VERSION 5.8 ;
BUSBITCHARS "[]" ;
DIVIDERCHAR "/" ;
UNITS
    DATABASE MICRONS 1000 ;
END UNITS

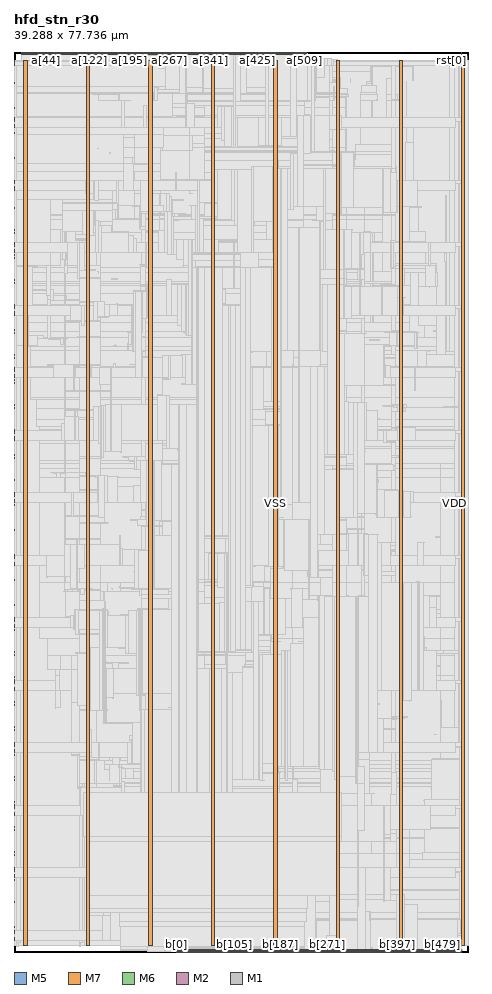
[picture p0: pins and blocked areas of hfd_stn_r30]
MACRO hfd_stn_r30
  FOREIGN hfd_stn_r30 0 0 ;
  CLASS BLOCK ;
  SIZE 39.288 BY 77.736 ;
  PIN a[0]
    DIRECTION INPUT ;
    USE SIGNAL ;
    PORT
      LAYER M5 ;
        RECT  0.624 77.544 0.648 77.736 ;
    END
  END a[0]
  PIN a[100]
    DIRECTION INPUT ;
    USE SIGNAL ;
    PORT
      LAYER M5 ;
        RECT  5.424 77.544 5.448 77.736 ;
    END
  END a[100]
  PIN a[101]
    DIRECTION INPUT ;
    USE SIGNAL ;
    PORT
      LAYER M5 ;
        RECT  5.472 77.544 5.496 77.736 ;
    END
  END a[101]
  PIN a[102]
    DIRECTION INPUT ;
    USE SIGNAL ;
    PORT
      LAYER M5 ;
        RECT  5.52 77.544 5.544 77.736 ;
    END
  END a[102]
  PIN a[103]
    DIRECTION INPUT ;
    USE SIGNAL ;
    PORT
      LAYER M5 ;
        RECT  5.568 77.544 5.592 77.736 ;
    END
  END a[103]
  PIN a[104]
    DIRECTION INPUT ;
    USE SIGNAL ;
    PORT
      LAYER M5 ;
        RECT  5.616 77.544 5.64 77.736 ;
    END
  END a[104]
  PIN a[105]
    DIRECTION INPUT ;
    USE SIGNAL ;
    PORT
      LAYER M5 ;
        RECT  5.664 77.544 5.688 77.736 ;
    END
  END a[105]
  PIN a[106]
    DIRECTION INPUT ;
    USE SIGNAL ;
    PORT
      LAYER M5 ;
        RECT  5.712 77.544 5.736 77.736 ;
    END
  END a[106]
  PIN a[107]
    DIRECTION INPUT ;
    USE SIGNAL ;
    PORT
      LAYER M5 ;
        RECT  5.76 77.544 5.784 77.736 ;
    END
  END a[107]
  PIN a[108]
    DIRECTION INPUT ;
    USE SIGNAL ;
    PORT
      LAYER M5 ;
        RECT  5.808 77.544 5.832 77.736 ;
    END
  END a[108]
  PIN a[109]
    DIRECTION INPUT ;
    USE SIGNAL ;
    PORT
      LAYER M5 ;
        RECT  5.856 77.544 5.88 77.736 ;
    END
  END a[109]
  PIN a[10]
    DIRECTION INPUT ;
    USE SIGNAL ;
    PORT
      LAYER M5 ;
        RECT  1.104 77.544 1.128 77.736 ;
    END
  END a[10]
  PIN a[110]
    DIRECTION INPUT ;
    USE SIGNAL ;
    PORT
      LAYER M5 ;
        RECT  5.904 77.544 5.928 77.736 ;
    END
  END a[110]
  PIN a[111]
    DIRECTION INPUT ;
    USE SIGNAL ;
    PORT
      LAYER M5 ;
        RECT  5.952 77.544 5.976 77.736 ;
    END
  END a[111]
  PIN a[112]
    DIRECTION INPUT ;
    USE SIGNAL ;
    PORT
      LAYER M5 ;
        RECT  6 77.544 6.024 77.736 ;
    END
  END a[112]
  PIN a[113]
    DIRECTION INPUT ;
    USE SIGNAL ;
    PORT
      LAYER M5 ;
        RECT  6.048 77.544 6.072 77.736 ;
    END
  END a[113]
  PIN a[114]
    DIRECTION INPUT ;
    USE SIGNAL ;
    PORT
      LAYER M5 ;
        RECT  6.096 77.544 6.12 77.736 ;
    END
  END a[114]
  PIN a[115]
    DIRECTION INPUT ;
    USE SIGNAL ;
    PORT
      LAYER M5 ;
        RECT  6.144 77.544 6.168 77.736 ;
    END
  END a[115]
  PIN a[116]
    DIRECTION INPUT ;
    USE SIGNAL ;
    PORT
      LAYER M5 ;
        RECT  6.192 77.544 6.216 77.736 ;
    END
  END a[116]
  PIN a[117]
    DIRECTION INPUT ;
    USE SIGNAL ;
    PORT
      LAYER M5 ;
        RECT  6.24 77.544 6.264 77.736 ;
    END
  END a[117]
  PIN a[118]
    DIRECTION INPUT ;
    USE SIGNAL ;
    PORT
      LAYER M5 ;
        RECT  6.288 77.544 6.312 77.736 ;
    END
  END a[118]
  PIN a[119]
    DIRECTION INPUT ;
    USE SIGNAL ;
    PORT
      LAYER M5 ;
        RECT  6.336 77.544 6.36 77.736 ;
    END
  END a[119]
  PIN a[11]
    DIRECTION INPUT ;
    USE SIGNAL ;
    PORT
      LAYER M5 ;
        RECT  1.152 77.544 1.176 77.736 ;
    END
  END a[11]
  PIN a[120]
    DIRECTION INPUT ;
    USE SIGNAL ;
    PORT
      LAYER M5 ;
        RECT  6.384 77.544 6.408 77.736 ;
    END
  END a[120]
  PIN a[121]
    DIRECTION INPUT ;
    USE SIGNAL ;
    PORT
      LAYER M5 ;
        RECT  6.432 77.544 6.456 77.736 ;
    END
  END a[121]
  PIN a[122]
    DIRECTION INPUT ;
    USE SIGNAL ;
    PORT
      LAYER M5 ;
        RECT  6.48 77.544 6.504 77.736 ;
    END
  END a[122]
  PIN a[123]
    DIRECTION INPUT ;
    USE SIGNAL ;
    PORT
      LAYER M5 ;
        RECT  6.528 77.544 6.552 77.736 ;
    END
  END a[123]
  PIN a[124]
    DIRECTION INPUT ;
    USE SIGNAL ;
    PORT
      LAYER M5 ;
        RECT  6.576 77.544 6.6 77.736 ;
    END
  END a[124]
  PIN a[125]
    DIRECTION INPUT ;
    USE SIGNAL ;
    PORT
      LAYER M5 ;
        RECT  6.624 77.544 6.648 77.736 ;
    END
  END a[125]
  PIN a[126]
    DIRECTION INPUT ;
    USE SIGNAL ;
    PORT
      LAYER M5 ;
        RECT  6.672 77.544 6.696 77.736 ;
    END
  END a[126]
  PIN a[127]
    DIRECTION INPUT ;
    USE SIGNAL ;
    PORT
      LAYER M5 ;
        RECT  6.72 77.544 6.744 77.736 ;
    END
  END a[127]
  PIN a[128]
    DIRECTION INPUT ;
    USE SIGNAL ;
    PORT
      LAYER M5 ;
        RECT  6.768 77.544 6.792 77.736 ;
    END
  END a[128]
  PIN a[129]
    DIRECTION INPUT ;
    USE SIGNAL ;
    PORT
      LAYER M5 ;
        RECT  6.816 77.544 6.84 77.736 ;
    END
  END a[129]
  PIN a[12]
    DIRECTION INPUT ;
    USE SIGNAL ;
    PORT
      LAYER M5 ;
        RECT  1.2 77.544 1.224 77.736 ;
    END
  END a[12]
  PIN a[130]
    DIRECTION INPUT ;
    USE SIGNAL ;
    PORT
      LAYER M5 ;
        RECT  6.864 77.544 6.888 77.736 ;
    END
  END a[130]
  PIN a[131]
    DIRECTION INPUT ;
    USE SIGNAL ;
    PORT
      LAYER M5 ;
        RECT  6.912 77.544 6.936 77.736 ;
    END
  END a[131]
  PIN a[132]
    DIRECTION INPUT ;
    USE SIGNAL ;
    PORT
      LAYER M5 ;
        RECT  6.96 77.544 6.984 77.736 ;
    END
  END a[132]
  PIN a[133]
    DIRECTION INPUT ;
    USE SIGNAL ;
    PORT
      LAYER M5 ;
        RECT  7.008 77.544 7.032 77.736 ;
    END
  END a[133]
  PIN a[134]
    DIRECTION INPUT ;
    USE SIGNAL ;
    PORT
      LAYER M5 ;
        RECT  7.056 77.544 7.08 77.736 ;
    END
  END a[134]
  PIN a[135]
    DIRECTION INPUT ;
    USE SIGNAL ;
    PORT
      LAYER M5 ;
        RECT  7.104 77.544 7.128 77.736 ;
    END
  END a[135]
  PIN a[136]
    DIRECTION INPUT ;
    USE SIGNAL ;
    PORT
      LAYER M5 ;
        RECT  7.152 77.544 7.176 77.736 ;
    END
  END a[136]
  PIN a[137]
    DIRECTION INPUT ;
    USE SIGNAL ;
    PORT
      LAYER M5 ;
        RECT  7.2 77.544 7.224 77.736 ;
    END
  END a[137]
  PIN a[138]
    DIRECTION INPUT ;
    USE SIGNAL ;
    PORT
      LAYER M5 ;
        RECT  7.248 77.544 7.272 77.736 ;
    END
  END a[138]
  PIN a[139]
    DIRECTION INPUT ;
    USE SIGNAL ;
    PORT
      LAYER M5 ;
        RECT  7.296 77.544 7.32 77.736 ;
    END
  END a[139]
  PIN a[13]
    DIRECTION INPUT ;
    USE SIGNAL ;
    PORT
      LAYER M5 ;
        RECT  1.248 77.544 1.272 77.736 ;
    END
  END a[13]
  PIN a[140]
    DIRECTION INPUT ;
    USE SIGNAL ;
    PORT
      LAYER M5 ;
        RECT  7.344 77.544 7.368 77.736 ;
    END
  END a[140]
  PIN a[141]
    DIRECTION INPUT ;
    USE SIGNAL ;
    PORT
      LAYER M5 ;
        RECT  7.392 77.544 7.416 77.736 ;
    END
  END a[141]
  PIN a[142]
    DIRECTION INPUT ;
    USE SIGNAL ;
    PORT
      LAYER M5 ;
        RECT  7.44 77.544 7.464 77.736 ;
    END
  END a[142]
  PIN a[143]
    DIRECTION INPUT ;
    USE SIGNAL ;
    PORT
      LAYER M5 ;
        RECT  7.488 77.544 7.512 77.736 ;
    END
  END a[143]
  PIN a[144]
    DIRECTION INPUT ;
    USE SIGNAL ;
    PORT
      LAYER M5 ;
        RECT  7.536 77.544 7.56 77.736 ;
    END
  END a[144]
  PIN a[145]
    DIRECTION INPUT ;
    USE SIGNAL ;
    PORT
      LAYER M5 ;
        RECT  7.584 77.544 7.608 77.736 ;
    END
  END a[145]
  PIN a[146]
    DIRECTION INPUT ;
    USE SIGNAL ;
    PORT
      LAYER M5 ;
        RECT  7.632 77.544 7.656 77.736 ;
    END
  END a[146]
  PIN a[147]
    DIRECTION INPUT ;
    USE SIGNAL ;
    PORT
      LAYER M5 ;
        RECT  7.68 77.544 7.704 77.736 ;
    END
  END a[147]
  PIN a[148]
    DIRECTION INPUT ;
    USE SIGNAL ;
    PORT
      LAYER M5 ;
        RECT  7.728 77.544 7.752 77.736 ;
    END
  END a[148]
  PIN a[149]
    DIRECTION INPUT ;
    USE SIGNAL ;
    PORT
      LAYER M5 ;
        RECT  7.776 77.544 7.8 77.736 ;
    END
  END a[149]
  PIN a[14]
    DIRECTION INPUT ;
    USE SIGNAL ;
    PORT
      LAYER M5 ;
        RECT  1.296 77.544 1.32 77.736 ;
    END
  END a[14]
  PIN a[150]
    DIRECTION INPUT ;
    USE SIGNAL ;
    PORT
      LAYER M5 ;
        RECT  7.824 77.544 7.848 77.736 ;
    END
  END a[150]
  PIN a[151]
    DIRECTION INPUT ;
    USE SIGNAL ;
    PORT
      LAYER M5 ;
        RECT  7.872 77.544 7.896 77.736 ;
    END
  END a[151]
  PIN a[152]
    DIRECTION INPUT ;
    USE SIGNAL ;
    PORT
      LAYER M5 ;
        RECT  7.92 77.544 7.944 77.736 ;
    END
  END a[152]
  PIN a[153]
    DIRECTION INPUT ;
    USE SIGNAL ;
    PORT
      LAYER M5 ;
        RECT  7.968 77.544 7.992 77.736 ;
    END
  END a[153]
  PIN a[154]
    DIRECTION INPUT ;
    USE SIGNAL ;
    PORT
      LAYER M5 ;
        RECT  8.016 77.544 8.04 77.736 ;
    END
  END a[154]
  PIN a[155]
    DIRECTION INPUT ;
    USE SIGNAL ;
    PORT
      LAYER M5 ;
        RECT  8.064 77.544 8.088 77.736 ;
    END
  END a[155]
  PIN a[156]
    DIRECTION INPUT ;
    USE SIGNAL ;
    PORT
      LAYER M5 ;
        RECT  8.112 77.544 8.136 77.736 ;
    END
  END a[156]
  PIN a[157]
    DIRECTION INPUT ;
    USE SIGNAL ;
    PORT
      LAYER M5 ;
        RECT  8.16 77.544 8.184 77.736 ;
    END
  END a[157]
  PIN a[158]
    DIRECTION INPUT ;
    USE SIGNAL ;
    PORT
      LAYER M5 ;
        RECT  8.208 77.544 8.232 77.736 ;
    END
  END a[158]
  PIN a[159]
    DIRECTION INPUT ;
    USE SIGNAL ;
    PORT
      LAYER M5 ;
        RECT  8.256 77.544 8.28 77.736 ;
    END
  END a[159]
  PIN a[15]
    DIRECTION INPUT ;
    USE SIGNAL ;
    PORT
      LAYER M5 ;
        RECT  1.344 77.544 1.368 77.736 ;
    END
  END a[15]
  PIN a[160]
    DIRECTION INPUT ;
    USE SIGNAL ;
    PORT
      LAYER M5 ;
        RECT  8.304 77.544 8.328 77.736 ;
    END
  END a[160]
  PIN a[161]
    DIRECTION INPUT ;
    USE SIGNAL ;
    PORT
      LAYER M5 ;
        RECT  8.352 77.544 8.376 77.736 ;
    END
  END a[161]
  PIN a[162]
    DIRECTION INPUT ;
    USE SIGNAL ;
    PORT
      LAYER M5 ;
        RECT  8.4 77.544 8.424 77.736 ;
    END
  END a[162]
  PIN a[163]
    DIRECTION INPUT ;
    USE SIGNAL ;
    PORT
      LAYER M5 ;
        RECT  8.448 77.544 8.472 77.736 ;
    END
  END a[163]
  PIN a[164]
    DIRECTION INPUT ;
    USE SIGNAL ;
    PORT
      LAYER M5 ;
        RECT  8.496 77.544 8.52 77.736 ;
    END
  END a[164]
  PIN a[165]
    DIRECTION INPUT ;
    USE SIGNAL ;
    PORT
      LAYER M5 ;
        RECT  8.544 77.544 8.568 77.736 ;
    END
  END a[165]
  PIN a[166]
    DIRECTION INPUT ;
    USE SIGNAL ;
    PORT
      LAYER M5 ;
        RECT  8.592 77.544 8.616 77.736 ;
    END
  END a[166]
  PIN a[167]
    DIRECTION INPUT ;
    USE SIGNAL ;
    PORT
      LAYER M5 ;
        RECT  8.64 77.544 8.664 77.736 ;
    END
  END a[167]
  PIN a[168]
    DIRECTION INPUT ;
    USE SIGNAL ;
    PORT
      LAYER M5 ;
        RECT  8.688 77.544 8.712 77.736 ;
    END
  END a[168]
  PIN a[169]
    DIRECTION INPUT ;
    USE SIGNAL ;
    PORT
      LAYER M5 ;
        RECT  8.736 77.544 8.76 77.736 ;
    END
  END a[169]
  PIN a[16]
    DIRECTION INPUT ;
    USE SIGNAL ;
    PORT
      LAYER M5 ;
        RECT  1.392 77.544 1.416 77.736 ;
    END
  END a[16]
  PIN a[170]
    DIRECTION INPUT ;
    USE SIGNAL ;
    PORT
      LAYER M5 ;
        RECT  8.784 77.544 8.808 77.736 ;
    END
  END a[170]
  PIN a[171]
    DIRECTION INPUT ;
    USE SIGNAL ;
    PORT
      LAYER M5 ;
        RECT  8.832 77.544 8.856 77.736 ;
    END
  END a[171]
  PIN a[172]
    DIRECTION INPUT ;
    USE SIGNAL ;
    PORT
      LAYER M5 ;
        RECT  8.88 77.544 8.904 77.736 ;
    END
  END a[172]
  PIN a[173]
    DIRECTION INPUT ;
    USE SIGNAL ;
    PORT
      LAYER M5 ;
        RECT  8.928 77.544 8.952 77.736 ;
    END
  END a[173]
  PIN a[174]
    DIRECTION INPUT ;
    USE SIGNAL ;
    PORT
      LAYER M5 ;
        RECT  8.976 77.544 9 77.736 ;
    END
  END a[174]
  PIN a[175]
    DIRECTION INPUT ;
    USE SIGNAL ;
    PORT
      LAYER M5 ;
        RECT  9.024 77.544 9.048 77.736 ;
    END
  END a[175]
  PIN a[176]
    DIRECTION INPUT ;
    USE SIGNAL ;
    PORT
      LAYER M5 ;
        RECT  9.072 77.544 9.096 77.736 ;
    END
  END a[176]
  PIN a[177]
    DIRECTION INPUT ;
    USE SIGNAL ;
    PORT
      LAYER M5 ;
        RECT  9.12 77.544 9.144 77.736 ;
    END
  END a[177]
  PIN a[178]
    DIRECTION INPUT ;
    USE SIGNAL ;
    PORT
      LAYER M5 ;
        RECT  9.168 77.544 9.192 77.736 ;
    END
  END a[178]
  PIN a[179]
    DIRECTION INPUT ;
    USE SIGNAL ;
    PORT
      LAYER M5 ;
        RECT  9.216 77.544 9.24 77.736 ;
    END
  END a[179]
  PIN a[17]
    DIRECTION INPUT ;
    USE SIGNAL ;
    PORT
      LAYER M5 ;
        RECT  1.44 77.544 1.464 77.736 ;
    END
  END a[17]
  PIN a[180]
    DIRECTION INPUT ;
    USE SIGNAL ;
    PORT
      LAYER M5 ;
        RECT  9.264 77.544 9.288 77.736 ;
    END
  END a[180]
  PIN a[181]
    DIRECTION INPUT ;
    USE SIGNAL ;
    PORT
      LAYER M5 ;
        RECT  9.312 77.544 9.336 77.736 ;
    END
  END a[181]
  PIN a[182]
    DIRECTION INPUT ;
    USE SIGNAL ;
    PORT
      LAYER M5 ;
        RECT  9.36 77.544 9.384 77.736 ;
    END
  END a[182]
  PIN a[183]
    DIRECTION INPUT ;
    USE SIGNAL ;
    PORT
      LAYER M5 ;
        RECT  9.408 77.544 9.432 77.736 ;
    END
  END a[183]
  PIN a[184]
    DIRECTION INPUT ;
    USE SIGNAL ;
    PORT
      LAYER M5 ;
        RECT  9.456 77.544 9.48 77.736 ;
    END
  END a[184]
  PIN a[185]
    DIRECTION INPUT ;
    USE SIGNAL ;
    PORT
      LAYER M5 ;
        RECT  9.504 77.544 9.528 77.736 ;
    END
  END a[185]
  PIN a[186]
    DIRECTION INPUT ;
    USE SIGNAL ;
    PORT
      LAYER M5 ;
        RECT  9.552 77.544 9.576 77.736 ;
    END
  END a[186]
  PIN a[187]
    DIRECTION INPUT ;
    USE SIGNAL ;
    PORT
      LAYER M5 ;
        RECT  9.6 77.544 9.624 77.736 ;
    END
  END a[187]
  PIN a[188]
    DIRECTION INPUT ;
    USE SIGNAL ;
    PORT
      LAYER M5 ;
        RECT  9.648 77.544 9.672 77.736 ;
    END
  END a[188]
  PIN a[189]
    DIRECTION INPUT ;
    USE SIGNAL ;
    PORT
      LAYER M5 ;
        RECT  9.696 77.544 9.72 77.736 ;
    END
  END a[189]
  PIN a[18]
    DIRECTION INPUT ;
    USE SIGNAL ;
    PORT
      LAYER M5 ;
        RECT  1.488 77.544 1.512 77.736 ;
    END
  END a[18]
  PIN a[190]
    DIRECTION INPUT ;
    USE SIGNAL ;
    PORT
      LAYER M5 ;
        RECT  9.744 77.544 9.768 77.736 ;
    END
  END a[190]
  PIN a[191]
    DIRECTION INPUT ;
    USE SIGNAL ;
    PORT
      LAYER M5 ;
        RECT  9.792 77.544 9.816 77.736 ;
    END
  END a[191]
  PIN a[192]
    DIRECTION INPUT ;
    USE SIGNAL ;
    PORT
      LAYER M5 ;
        RECT  9.84 77.544 9.864 77.736 ;
    END
  END a[192]
  PIN a[193]
    DIRECTION INPUT ;
    USE SIGNAL ;
    PORT
      LAYER M5 ;
        RECT  9.888 77.544 9.912 77.736 ;
    END
  END a[193]
  PIN a[194]
    DIRECTION INPUT ;
    USE SIGNAL ;
    PORT
      LAYER M5 ;
        RECT  9.936 77.544 9.96 77.736 ;
    END
  END a[194]
  PIN a[195]
    DIRECTION INPUT ;
    USE SIGNAL ;
    PORT
      LAYER M5 ;
        RECT  9.984 77.544 10.008 77.736 ;
    END
  END a[195]
  PIN a[196]
    DIRECTION INPUT ;
    USE SIGNAL ;
    PORT
      LAYER M5 ;
        RECT  10.032 77.544 10.056 77.736 ;
    END
  END a[196]
  PIN a[197]
    DIRECTION INPUT ;
    USE SIGNAL ;
    PORT
      LAYER M5 ;
        RECT  10.08 77.544 10.104 77.736 ;
    END
  END a[197]
  PIN a[198]
    DIRECTION INPUT ;
    USE SIGNAL ;
    PORT
      LAYER M5 ;
        RECT  10.128 77.544 10.152 77.736 ;
    END
  END a[198]
  PIN a[199]
    DIRECTION INPUT ;
    USE SIGNAL ;
    PORT
      LAYER M5 ;
        RECT  10.176 77.544 10.2 77.736 ;
    END
  END a[199]
  PIN a[19]
    DIRECTION INPUT ;
    USE SIGNAL ;
    PORT
      LAYER M5 ;
        RECT  1.536 77.544 1.56 77.736 ;
    END
  END a[19]
  PIN a[1]
    DIRECTION INPUT ;
    USE SIGNAL ;
    PORT
      LAYER M5 ;
        RECT  0.672 77.544 0.696 77.736 ;
    END
  END a[1]
  PIN a[200]
    DIRECTION INPUT ;
    USE SIGNAL ;
    PORT
      LAYER M5 ;
        RECT  10.224 77.544 10.248 77.736 ;
    END
  END a[200]
  PIN a[201]
    DIRECTION INPUT ;
    USE SIGNAL ;
    PORT
      LAYER M5 ;
        RECT  10.272 77.544 10.296 77.736 ;
    END
  END a[201]
  PIN a[202]
    DIRECTION INPUT ;
    USE SIGNAL ;
    PORT
      LAYER M5 ;
        RECT  10.32 77.544 10.344 77.736 ;
    END
  END a[202]
  PIN a[203]
    DIRECTION INPUT ;
    USE SIGNAL ;
    PORT
      LAYER M5 ;
        RECT  10.368 77.544 10.392 77.736 ;
    END
  END a[203]
  PIN a[204]
    DIRECTION INPUT ;
    USE SIGNAL ;
    PORT
      LAYER M5 ;
        RECT  10.416 77.544 10.44 77.736 ;
    END
  END a[204]
  PIN a[205]
    DIRECTION INPUT ;
    USE SIGNAL ;
    PORT
      LAYER M5 ;
        RECT  10.464 77.544 10.488 77.736 ;
    END
  END a[205]
  PIN a[206]
    DIRECTION INPUT ;
    USE SIGNAL ;
    PORT
      LAYER M5 ;
        RECT  10.512 77.544 10.536 77.736 ;
    END
  END a[206]
  PIN a[207]
    DIRECTION INPUT ;
    USE SIGNAL ;
    PORT
      LAYER M5 ;
        RECT  10.56 77.544 10.584 77.736 ;
    END
  END a[207]
  PIN a[208]
    DIRECTION INPUT ;
    USE SIGNAL ;
    PORT
      LAYER M5 ;
        RECT  10.608 77.544 10.632 77.736 ;
    END
  END a[208]
  PIN a[209]
    DIRECTION INPUT ;
    USE SIGNAL ;
    PORT
      LAYER M5 ;
        RECT  10.656 77.544 10.68 77.736 ;
    END
  END a[209]
  PIN a[20]
    DIRECTION INPUT ;
    USE SIGNAL ;
    PORT
      LAYER M5 ;
        RECT  1.584 77.544 1.608 77.736 ;
    END
  END a[20]
  PIN a[210]
    DIRECTION INPUT ;
    USE SIGNAL ;
    PORT
      LAYER M5 ;
        RECT  10.704 77.544 10.728 77.736 ;
    END
  END a[210]
  PIN a[211]
    DIRECTION INPUT ;
    USE SIGNAL ;
    PORT
      LAYER M5 ;
        RECT  10.752 77.544 10.776 77.736 ;
    END
  END a[211]
  PIN a[212]
    DIRECTION INPUT ;
    USE SIGNAL ;
    PORT
      LAYER M5 ;
        RECT  10.8 77.544 10.824 77.736 ;
    END
  END a[212]
  PIN a[213]
    DIRECTION INPUT ;
    USE SIGNAL ;
    PORT
      LAYER M5 ;
        RECT  10.848 77.544 10.872 77.736 ;
    END
  END a[213]
  PIN a[214]
    DIRECTION INPUT ;
    USE SIGNAL ;
    PORT
      LAYER M5 ;
        RECT  10.896 77.544 10.92 77.736 ;
    END
  END a[214]
  PIN a[215]
    DIRECTION INPUT ;
    USE SIGNAL ;
    PORT
      LAYER M5 ;
        RECT  10.944 77.544 10.968 77.736 ;
    END
  END a[215]
  PIN a[216]
    DIRECTION INPUT ;
    USE SIGNAL ;
    PORT
      LAYER M5 ;
        RECT  10.992 77.544 11.016 77.736 ;
    END
  END a[216]
  PIN a[217]
    DIRECTION INPUT ;
    USE SIGNAL ;
    PORT
      LAYER M5 ;
        RECT  11.04 77.544 11.064 77.736 ;
    END
  END a[217]
  PIN a[218]
    DIRECTION INPUT ;
    USE SIGNAL ;
    PORT
      LAYER M5 ;
        RECT  11.088 77.544 11.112 77.736 ;
    END
  END a[218]
  PIN a[219]
    DIRECTION INPUT ;
    USE SIGNAL ;
    PORT
      LAYER M5 ;
        RECT  11.136 77.544 11.16 77.736 ;
    END
  END a[219]
  PIN a[21]
    DIRECTION INPUT ;
    USE SIGNAL ;
    PORT
      LAYER M5 ;
        RECT  1.632 77.544 1.656 77.736 ;
    END
  END a[21]
  PIN a[220]
    DIRECTION INPUT ;
    USE SIGNAL ;
    PORT
      LAYER M5 ;
        RECT  11.184 77.544 11.208 77.736 ;
    END
  END a[220]
  PIN a[221]
    DIRECTION INPUT ;
    USE SIGNAL ;
    PORT
      LAYER M5 ;
        RECT  11.232 77.544 11.256 77.736 ;
    END
  END a[221]
  PIN a[222]
    DIRECTION INPUT ;
    USE SIGNAL ;
    PORT
      LAYER M5 ;
        RECT  11.28 77.544 11.304 77.736 ;
    END
  END a[222]
  PIN a[223]
    DIRECTION INPUT ;
    USE SIGNAL ;
    PORT
      LAYER M5 ;
        RECT  11.328 77.544 11.352 77.736 ;
    END
  END a[223]
  PIN a[224]
    DIRECTION INPUT ;
    USE SIGNAL ;
    PORT
      LAYER M5 ;
        RECT  11.376 77.544 11.4 77.736 ;
    END
  END a[224]
  PIN a[225]
    DIRECTION INPUT ;
    USE SIGNAL ;
    PORT
      LAYER M5 ;
        RECT  11.424 77.544 11.448 77.736 ;
    END
  END a[225]
  PIN a[226]
    DIRECTION INPUT ;
    USE SIGNAL ;
    PORT
      LAYER M5 ;
        RECT  11.472 77.544 11.496 77.736 ;
    END
  END a[226]
  PIN a[227]
    DIRECTION INPUT ;
    USE SIGNAL ;
    PORT
      LAYER M5 ;
        RECT  11.52 77.544 11.544 77.736 ;
    END
  END a[227]
  PIN a[228]
    DIRECTION INPUT ;
    USE SIGNAL ;
    PORT
      LAYER M5 ;
        RECT  11.568 77.544 11.592 77.736 ;
    END
  END a[228]
  PIN a[229]
    DIRECTION INPUT ;
    USE SIGNAL ;
    PORT
      LAYER M5 ;
        RECT  11.616 77.544 11.64 77.736 ;
    END
  END a[229]
  PIN a[22]
    DIRECTION INPUT ;
    USE SIGNAL ;
    PORT
      LAYER M5 ;
        RECT  1.68 77.544 1.704 77.736 ;
    END
  END a[22]
  PIN a[230]
    DIRECTION INPUT ;
    USE SIGNAL ;
    PORT
      LAYER M5 ;
        RECT  11.664 77.544 11.688 77.736 ;
    END
  END a[230]
  PIN a[231]
    DIRECTION INPUT ;
    USE SIGNAL ;
    PORT
      LAYER M5 ;
        RECT  11.712 77.544 11.736 77.736 ;
    END
  END a[231]
  PIN a[232]
    DIRECTION INPUT ;
    USE SIGNAL ;
    PORT
      LAYER M5 ;
        RECT  11.76 77.544 11.784 77.736 ;
    END
  END a[232]
  PIN a[233]
    DIRECTION INPUT ;
    USE SIGNAL ;
    PORT
      LAYER M5 ;
        RECT  11.808 77.544 11.832 77.736 ;
    END
  END a[233]
  PIN a[234]
    DIRECTION INPUT ;
    USE SIGNAL ;
    PORT
      LAYER M5 ;
        RECT  11.856 77.544 11.88 77.736 ;
    END
  END a[234]
  PIN a[235]
    DIRECTION INPUT ;
    USE SIGNAL ;
    PORT
      LAYER M5 ;
        RECT  11.904 77.544 11.928 77.736 ;
    END
  END a[235]
  PIN a[236]
    DIRECTION INPUT ;
    USE SIGNAL ;
    PORT
      LAYER M5 ;
        RECT  11.952 77.544 11.976 77.736 ;
    END
  END a[236]
  PIN a[237]
    DIRECTION INPUT ;
    USE SIGNAL ;
    PORT
      LAYER M5 ;
        RECT  12 77.544 12.024 77.736 ;
    END
  END a[237]
  PIN a[238]
    DIRECTION INPUT ;
    USE SIGNAL ;
    PORT
      LAYER M5 ;
        RECT  12.048 77.544 12.072 77.736 ;
    END
  END a[238]
  PIN a[239]
    DIRECTION INPUT ;
    USE SIGNAL ;
    PORT
      LAYER M5 ;
        RECT  12.096 77.544 12.12 77.736 ;
    END
  END a[239]
  PIN a[23]
    DIRECTION INPUT ;
    USE SIGNAL ;
    PORT
      LAYER M5 ;
        RECT  1.728 77.544 1.752 77.736 ;
    END
  END a[23]
  PIN a[240]
    DIRECTION INPUT ;
    USE SIGNAL ;
    PORT
      LAYER M5 ;
        RECT  12.144 77.544 12.168 77.736 ;
    END
  END a[240]
  PIN a[241]
    DIRECTION INPUT ;
    USE SIGNAL ;
    PORT
      LAYER M5 ;
        RECT  12.192 77.544 12.216 77.736 ;
    END
  END a[241]
  PIN a[242]
    DIRECTION INPUT ;
    USE SIGNAL ;
    PORT
      LAYER M5 ;
        RECT  12.24 77.544 12.264 77.736 ;
    END
  END a[242]
  PIN a[243]
    DIRECTION INPUT ;
    USE SIGNAL ;
    PORT
      LAYER M5 ;
        RECT  12.288 77.544 12.312 77.736 ;
    END
  END a[243]
  PIN a[244]
    DIRECTION INPUT ;
    USE SIGNAL ;
    PORT
      LAYER M5 ;
        RECT  12.336 77.544 12.36 77.736 ;
    END
  END a[244]
  PIN a[245]
    DIRECTION INPUT ;
    USE SIGNAL ;
    PORT
      LAYER M5 ;
        RECT  12.384 77.544 12.408 77.736 ;
    END
  END a[245]
  PIN a[246]
    DIRECTION INPUT ;
    USE SIGNAL ;
    PORT
      LAYER M5 ;
        RECT  12.432 77.544 12.456 77.736 ;
    END
  END a[246]
  PIN a[247]
    DIRECTION INPUT ;
    USE SIGNAL ;
    PORT
      LAYER M5 ;
        RECT  12.48 77.544 12.504 77.736 ;
    END
  END a[247]
  PIN a[248]
    DIRECTION INPUT ;
    USE SIGNAL ;
    PORT
      LAYER M5 ;
        RECT  12.528 77.544 12.552 77.736 ;
    END
  END a[248]
  PIN a[249]
    DIRECTION INPUT ;
    USE SIGNAL ;
    PORT
      LAYER M5 ;
        RECT  12.576 77.544 12.6 77.736 ;
    END
  END a[249]
  PIN a[24]
    DIRECTION INPUT ;
    USE SIGNAL ;
    PORT
      LAYER M5 ;
        RECT  1.776 77.544 1.8 77.736 ;
    END
  END a[24]
  PIN a[250]
    DIRECTION INPUT ;
    USE SIGNAL ;
    PORT
      LAYER M5 ;
        RECT  12.624 77.544 12.648 77.736 ;
    END
  END a[250]
  PIN a[251]
    DIRECTION INPUT ;
    USE SIGNAL ;
    PORT
      LAYER M5 ;
        RECT  12.672 77.544 12.696 77.736 ;
    END
  END a[251]
  PIN a[252]
    DIRECTION INPUT ;
    USE SIGNAL ;
    PORT
      LAYER M5 ;
        RECT  12.72 77.544 12.744 77.736 ;
    END
  END a[252]
  PIN a[253]
    DIRECTION INPUT ;
    USE SIGNAL ;
    PORT
      LAYER M5 ;
        RECT  12.768 77.544 12.792 77.736 ;
    END
  END a[253]
  PIN a[254]
    DIRECTION INPUT ;
    USE SIGNAL ;
    PORT
      LAYER M5 ;
        RECT  12.816 77.544 12.84 77.736 ;
    END
  END a[254]
  PIN a[255]
    DIRECTION INPUT ;
    USE SIGNAL ;
    PORT
      LAYER M5 ;
        RECT  12.864 77.544 12.888 77.736 ;
    END
  END a[255]
  PIN a[256]
    DIRECTION OUTPUT ;
    USE SIGNAL ;
    PORT
      LAYER M5 ;
        RECT  12.912 77.544 12.936 77.736 ;
    END
  END a[256]
  PIN a[257]
    DIRECTION OUTPUT ;
    USE SIGNAL ;
    PORT
      LAYER M5 ;
        RECT  12.96 77.544 12.984 77.736 ;
    END
  END a[257]
  PIN a[258]
    DIRECTION OUTPUT ;
    USE SIGNAL ;
    PORT
      LAYER M5 ;
        RECT  13.008 77.544 13.032 77.736 ;
    END
  END a[258]
  PIN a[259]
    DIRECTION OUTPUT ;
    USE SIGNAL ;
    PORT
      LAYER M5 ;
        RECT  13.056 77.544 13.08 77.736 ;
    END
  END a[259]
  PIN a[25]
    DIRECTION INPUT ;
    USE SIGNAL ;
    PORT
      LAYER M5 ;
        RECT  1.824 77.544 1.848 77.736 ;
    END
  END a[25]
  PIN a[260]
    DIRECTION OUTPUT ;
    USE SIGNAL ;
    PORT
      LAYER M5 ;
        RECT  13.104 77.544 13.128 77.736 ;
    END
  END a[260]
  PIN a[261]
    DIRECTION OUTPUT ;
    USE SIGNAL ;
    PORT
      LAYER M5 ;
        RECT  13.152 77.544 13.176 77.736 ;
    END
  END a[261]
  PIN a[262]
    DIRECTION OUTPUT ;
    USE SIGNAL ;
    PORT
      LAYER M5 ;
        RECT  13.2 77.544 13.224 77.736 ;
    END
  END a[262]
  PIN a[263]
    DIRECTION OUTPUT ;
    USE SIGNAL ;
    PORT
      LAYER M5 ;
        RECT  13.248 77.544 13.272 77.736 ;
    END
  END a[263]
  PIN a[264]
    DIRECTION OUTPUT ;
    USE SIGNAL ;
    PORT
      LAYER M5 ;
        RECT  13.296 77.544 13.32 77.736 ;
    END
  END a[264]
  PIN a[265]
    DIRECTION OUTPUT ;
    USE SIGNAL ;
    PORT
      LAYER M5 ;
        RECT  13.344 77.544 13.368 77.736 ;
    END
  END a[265]
  PIN a[266]
    DIRECTION OUTPUT ;
    USE SIGNAL ;
    PORT
      LAYER M5 ;
        RECT  13.392 77.544 13.416 77.736 ;
    END
  END a[266]
  PIN a[267]
    DIRECTION OUTPUT ;
    USE SIGNAL ;
    PORT
      LAYER M5 ;
        RECT  13.44 77.544 13.464 77.736 ;
    END
  END a[267]
  PIN a[268]
    DIRECTION OUTPUT ;
    USE SIGNAL ;
    PORT
      LAYER M5 ;
        RECT  13.488 77.544 13.512 77.736 ;
    END
  END a[268]
  PIN a[269]
    DIRECTION OUTPUT ;
    USE SIGNAL ;
    PORT
      LAYER M5 ;
        RECT  13.536 77.544 13.56 77.736 ;
    END
  END a[269]
  PIN a[26]
    DIRECTION INPUT ;
    USE SIGNAL ;
    PORT
      LAYER M5 ;
        RECT  1.872 77.544 1.896 77.736 ;
    END
  END a[26]
  PIN a[270]
    DIRECTION OUTPUT ;
    USE SIGNAL ;
    PORT
      LAYER M5 ;
        RECT  13.584 77.544 13.608 77.736 ;
    END
  END a[270]
  PIN a[271]
    DIRECTION OUTPUT ;
    USE SIGNAL ;
    PORT
      LAYER M5 ;
        RECT  13.632 77.544 13.656 77.736 ;
    END
  END a[271]
  PIN a[272]
    DIRECTION OUTPUT ;
    USE SIGNAL ;
    PORT
      LAYER M5 ;
        RECT  13.68 77.544 13.704 77.736 ;
    END
  END a[272]
  PIN a[273]
    DIRECTION OUTPUT ;
    USE SIGNAL ;
    PORT
      LAYER M5 ;
        RECT  13.728 77.544 13.752 77.736 ;
    END
  END a[273]
  PIN a[274]
    DIRECTION OUTPUT ;
    USE SIGNAL ;
    PORT
      LAYER M5 ;
        RECT  13.776 77.544 13.8 77.736 ;
    END
  END a[274]
  PIN a[275]
    DIRECTION OUTPUT ;
    USE SIGNAL ;
    PORT
      LAYER M5 ;
        RECT  13.824 77.544 13.848 77.736 ;
    END
  END a[275]
  PIN a[276]
    DIRECTION OUTPUT ;
    USE SIGNAL ;
    PORT
      LAYER M5 ;
        RECT  13.872 77.544 13.896 77.736 ;
    END
  END a[276]
  PIN a[277]
    DIRECTION OUTPUT ;
    USE SIGNAL ;
    PORT
      LAYER M5 ;
        RECT  13.92 77.544 13.944 77.736 ;
    END
  END a[277]
  PIN a[278]
    DIRECTION OUTPUT ;
    USE SIGNAL ;
    PORT
      LAYER M5 ;
        RECT  13.968 77.544 13.992 77.736 ;
    END
  END a[278]
  PIN a[279]
    DIRECTION OUTPUT ;
    USE SIGNAL ;
    PORT
      LAYER M5 ;
        RECT  14.016 77.544 14.04 77.736 ;
    END
  END a[279]
  PIN a[27]
    DIRECTION INPUT ;
    USE SIGNAL ;
    PORT
      LAYER M5 ;
        RECT  1.92 77.544 1.944 77.736 ;
    END
  END a[27]
  PIN a[280]
    DIRECTION OUTPUT ;
    USE SIGNAL ;
    PORT
      LAYER M5 ;
        RECT  14.064 77.544 14.088 77.736 ;
    END
  END a[280]
  PIN a[281]
    DIRECTION OUTPUT ;
    USE SIGNAL ;
    PORT
      LAYER M5 ;
        RECT  14.112 77.544 14.136 77.736 ;
    END
  END a[281]
  PIN a[282]
    DIRECTION OUTPUT ;
    USE SIGNAL ;
    PORT
      LAYER M5 ;
        RECT  14.16 77.544 14.184 77.736 ;
    END
  END a[282]
  PIN a[283]
    DIRECTION OUTPUT ;
    USE SIGNAL ;
    PORT
      LAYER M5 ;
        RECT  14.208 77.544 14.232 77.736 ;
    END
  END a[283]
  PIN a[284]
    DIRECTION OUTPUT ;
    USE SIGNAL ;
    PORT
      LAYER M5 ;
        RECT  14.256 77.544 14.28 77.736 ;
    END
  END a[284]
  PIN a[285]
    DIRECTION OUTPUT ;
    USE SIGNAL ;
    PORT
      LAYER M5 ;
        RECT  14.304 77.544 14.328 77.736 ;
    END
  END a[285]
  PIN a[286]
    DIRECTION OUTPUT ;
    USE SIGNAL ;
    PORT
      LAYER M5 ;
        RECT  14.352 77.544 14.376 77.736 ;
    END
  END a[286]
  PIN a[287]
    DIRECTION OUTPUT ;
    USE SIGNAL ;
    PORT
      LAYER M5 ;
        RECT  14.4 77.544 14.424 77.736 ;
    END
  END a[287]
  PIN a[288]
    DIRECTION OUTPUT ;
    USE SIGNAL ;
    PORT
      LAYER M5 ;
        RECT  14.448 77.544 14.472 77.736 ;
    END
  END a[288]
  PIN a[289]
    DIRECTION OUTPUT ;
    USE SIGNAL ;
    PORT
      LAYER M5 ;
        RECT  14.496 77.544 14.52 77.736 ;
    END
  END a[289]
  PIN a[28]
    DIRECTION INPUT ;
    USE SIGNAL ;
    PORT
      LAYER M5 ;
        RECT  1.968 77.544 1.992 77.736 ;
    END
  END a[28]
  PIN a[290]
    DIRECTION OUTPUT ;
    USE SIGNAL ;
    PORT
      LAYER M5 ;
        RECT  14.544 77.544 14.568 77.736 ;
    END
  END a[290]
  PIN a[291]
    DIRECTION OUTPUT ;
    USE SIGNAL ;
    PORT
      LAYER M5 ;
        RECT  14.592 77.544 14.616 77.736 ;
    END
  END a[291]
  PIN a[292]
    DIRECTION OUTPUT ;
    USE SIGNAL ;
    PORT
      LAYER M5 ;
        RECT  14.64 77.544 14.664 77.736 ;
    END
  END a[292]
  PIN a[293]
    DIRECTION OUTPUT ;
    USE SIGNAL ;
    PORT
      LAYER M5 ;
        RECT  14.688 77.544 14.712 77.736 ;
    END
  END a[293]
  PIN a[294]
    DIRECTION OUTPUT ;
    USE SIGNAL ;
    PORT
      LAYER M5 ;
        RECT  14.736 77.544 14.76 77.736 ;
    END
  END a[294]
  PIN a[295]
    DIRECTION OUTPUT ;
    USE SIGNAL ;
    PORT
      LAYER M5 ;
        RECT  14.784 77.544 14.808 77.736 ;
    END
  END a[295]
  PIN a[296]
    DIRECTION OUTPUT ;
    USE SIGNAL ;
    PORT
      LAYER M5 ;
        RECT  14.832 77.544 14.856 77.736 ;
    END
  END a[296]
  PIN a[297]
    DIRECTION OUTPUT ;
    USE SIGNAL ;
    PORT
      LAYER M5 ;
        RECT  14.88 77.544 14.904 77.736 ;
    END
  END a[297]
  PIN a[298]
    DIRECTION OUTPUT ;
    USE SIGNAL ;
    PORT
      LAYER M5 ;
        RECT  14.928 77.544 14.952 77.736 ;
    END
  END a[298]
  PIN a[299]
    DIRECTION OUTPUT ;
    USE SIGNAL ;
    PORT
      LAYER M5 ;
        RECT  14.976 77.544 15 77.736 ;
    END
  END a[299]
  PIN a[29]
    DIRECTION INPUT ;
    USE SIGNAL ;
    PORT
      LAYER M5 ;
        RECT  2.016 77.544 2.04 77.736 ;
    END
  END a[29]
  PIN a[2]
    DIRECTION INPUT ;
    USE SIGNAL ;
    PORT
      LAYER M5 ;
        RECT  0.72 77.544 0.744 77.736 ;
    END
  END a[2]
  PIN a[300]
    DIRECTION OUTPUT ;
    USE SIGNAL ;
    PORT
      LAYER M5 ;
        RECT  15.024 77.544 15.048 77.736 ;
    END
  END a[300]
  PIN a[301]
    DIRECTION OUTPUT ;
    USE SIGNAL ;
    PORT
      LAYER M5 ;
        RECT  15.072 77.544 15.096 77.736 ;
    END
  END a[301]
  PIN a[302]
    DIRECTION OUTPUT ;
    USE SIGNAL ;
    PORT
      LAYER M5 ;
        RECT  15.12 77.544 15.144 77.736 ;
    END
  END a[302]
  PIN a[303]
    DIRECTION OUTPUT ;
    USE SIGNAL ;
    PORT
      LAYER M5 ;
        RECT  15.168 77.544 15.192 77.736 ;
    END
  END a[303]
  PIN a[304]
    DIRECTION OUTPUT ;
    USE SIGNAL ;
    PORT
      LAYER M5 ;
        RECT  15.216 77.544 15.24 77.736 ;
    END
  END a[304]
  PIN a[305]
    DIRECTION OUTPUT ;
    USE SIGNAL ;
    PORT
      LAYER M5 ;
        RECT  15.264 77.544 15.288 77.736 ;
    END
  END a[305]
  PIN a[306]
    DIRECTION OUTPUT ;
    USE SIGNAL ;
    PORT
      LAYER M5 ;
        RECT  15.312 77.544 15.336 77.736 ;
    END
  END a[306]
  PIN a[307]
    DIRECTION OUTPUT ;
    USE SIGNAL ;
    PORT
      LAYER M5 ;
        RECT  15.36 77.544 15.384 77.736 ;
    END
  END a[307]
  PIN a[308]
    DIRECTION OUTPUT ;
    USE SIGNAL ;
    PORT
      LAYER M5 ;
        RECT  15.408 77.544 15.432 77.736 ;
    END
  END a[308]
  PIN a[309]
    DIRECTION OUTPUT ;
    USE SIGNAL ;
    PORT
      LAYER M5 ;
        RECT  15.456 77.544 15.48 77.736 ;
    END
  END a[309]
  PIN a[30]
    DIRECTION INPUT ;
    USE SIGNAL ;
    PORT
      LAYER M5 ;
        RECT  2.064 77.544 2.088 77.736 ;
    END
  END a[30]
  PIN a[310]
    DIRECTION OUTPUT ;
    USE SIGNAL ;
    PORT
      LAYER M5 ;
        RECT  15.504 77.544 15.528 77.736 ;
    END
  END a[310]
  PIN a[311]
    DIRECTION OUTPUT ;
    USE SIGNAL ;
    PORT
      LAYER M5 ;
        RECT  15.552 77.544 15.576 77.736 ;
    END
  END a[311]
  PIN a[312]
    DIRECTION OUTPUT ;
    USE SIGNAL ;
    PORT
      LAYER M5 ;
        RECT  15.6 77.544 15.624 77.736 ;
    END
  END a[312]
  PIN a[313]
    DIRECTION OUTPUT ;
    USE SIGNAL ;
    PORT
      LAYER M5 ;
        RECT  15.648 77.544 15.672 77.736 ;
    END
  END a[313]
  PIN a[314]
    DIRECTION OUTPUT ;
    USE SIGNAL ;
    PORT
      LAYER M5 ;
        RECT  15.696 77.544 15.72 77.736 ;
    END
  END a[314]
  PIN a[315]
    DIRECTION OUTPUT ;
    USE SIGNAL ;
    PORT
      LAYER M5 ;
        RECT  15.744 77.544 15.768 77.736 ;
    END
  END a[315]
  PIN a[316]
    DIRECTION OUTPUT ;
    USE SIGNAL ;
    PORT
      LAYER M5 ;
        RECT  15.792 77.544 15.816 77.736 ;
    END
  END a[316]
  PIN a[317]
    DIRECTION OUTPUT ;
    USE SIGNAL ;
    PORT
      LAYER M5 ;
        RECT  15.84 77.544 15.864 77.736 ;
    END
  END a[317]
  PIN a[318]
    DIRECTION OUTPUT ;
    USE SIGNAL ;
    PORT
      LAYER M5 ;
        RECT  15.888 77.544 15.912 77.736 ;
    END
  END a[318]
  PIN a[319]
    DIRECTION OUTPUT ;
    USE SIGNAL ;
    PORT
      LAYER M5 ;
        RECT  15.936 77.544 15.96 77.736 ;
    END
  END a[319]
  PIN a[31]
    DIRECTION INPUT ;
    USE SIGNAL ;
    PORT
      LAYER M5 ;
        RECT  2.112 77.544 2.136 77.736 ;
    END
  END a[31]
  PIN a[320]
    DIRECTION OUTPUT ;
    USE SIGNAL ;
    PORT
      LAYER M5 ;
        RECT  15.984 77.544 16.008 77.736 ;
    END
  END a[320]
  PIN a[321]
    DIRECTION OUTPUT ;
    USE SIGNAL ;
    PORT
      LAYER M5 ;
        RECT  16.032 77.544 16.056 77.736 ;
    END
  END a[321]
  PIN a[322]
    DIRECTION OUTPUT ;
    USE SIGNAL ;
    PORT
      LAYER M5 ;
        RECT  16.08 77.544 16.104 77.736 ;
    END
  END a[322]
  PIN a[323]
    DIRECTION OUTPUT ;
    USE SIGNAL ;
    PORT
      LAYER M5 ;
        RECT  16.128 77.544 16.152 77.736 ;
    END
  END a[323]
  PIN a[324]
    DIRECTION OUTPUT ;
    USE SIGNAL ;
    PORT
      LAYER M5 ;
        RECT  16.176 77.544 16.2 77.736 ;
    END
  END a[324]
  PIN a[325]
    DIRECTION OUTPUT ;
    USE SIGNAL ;
    PORT
      LAYER M5 ;
        RECT  16.224 77.544 16.248 77.736 ;
    END
  END a[325]
  PIN a[326]
    DIRECTION OUTPUT ;
    USE SIGNAL ;
    PORT
      LAYER M5 ;
        RECT  16.272 77.544 16.296 77.736 ;
    END
  END a[326]
  PIN a[327]
    DIRECTION OUTPUT ;
    USE SIGNAL ;
    PORT
      LAYER M5 ;
        RECT  16.32 77.544 16.344 77.736 ;
    END
  END a[327]
  PIN a[328]
    DIRECTION OUTPUT ;
    USE SIGNAL ;
    PORT
      LAYER M5 ;
        RECT  16.368 77.544 16.392 77.736 ;
    END
  END a[328]
  PIN a[329]
    DIRECTION OUTPUT ;
    USE SIGNAL ;
    PORT
      LAYER M5 ;
        RECT  16.416 77.544 16.44 77.736 ;
    END
  END a[329]
  PIN a[32]
    DIRECTION INPUT ;
    USE SIGNAL ;
    PORT
      LAYER M5 ;
        RECT  2.16 77.544 2.184 77.736 ;
    END
  END a[32]
  PIN a[330]
    DIRECTION OUTPUT ;
    USE SIGNAL ;
    PORT
      LAYER M5 ;
        RECT  16.464 77.544 16.488 77.736 ;
    END
  END a[330]
  PIN a[331]
    DIRECTION OUTPUT ;
    USE SIGNAL ;
    PORT
      LAYER M5 ;
        RECT  16.512 77.544 16.536 77.736 ;
    END
  END a[331]
  PIN a[332]
    DIRECTION OUTPUT ;
    USE SIGNAL ;
    PORT
      LAYER M5 ;
        RECT  16.56 77.544 16.584 77.736 ;
    END
  END a[332]
  PIN a[333]
    DIRECTION OUTPUT ;
    USE SIGNAL ;
    PORT
      LAYER M5 ;
        RECT  16.608 77.544 16.632 77.736 ;
    END
  END a[333]
  PIN a[334]
    DIRECTION OUTPUT ;
    USE SIGNAL ;
    PORT
      LAYER M5 ;
        RECT  16.656 77.544 16.68 77.736 ;
    END
  END a[334]
  PIN a[335]
    DIRECTION OUTPUT ;
    USE SIGNAL ;
    PORT
      LAYER M5 ;
        RECT  16.704 77.544 16.728 77.736 ;
    END
  END a[335]
  PIN a[336]
    DIRECTION OUTPUT ;
    USE SIGNAL ;
    PORT
      LAYER M5 ;
        RECT  16.752 77.544 16.776 77.736 ;
    END
  END a[336]
  PIN a[337]
    DIRECTION OUTPUT ;
    USE SIGNAL ;
    PORT
      LAYER M5 ;
        RECT  16.8 77.544 16.824 77.736 ;
    END
  END a[337]
  PIN a[338]
    DIRECTION OUTPUT ;
    USE SIGNAL ;
    PORT
      LAYER M5 ;
        RECT  16.848 77.544 16.872 77.736 ;
    END
  END a[338]
  PIN a[339]
    DIRECTION OUTPUT ;
    USE SIGNAL ;
    PORT
      LAYER M5 ;
        RECT  16.896 77.544 16.92 77.736 ;
    END
  END a[339]
  PIN a[33]
    DIRECTION INPUT ;
    USE SIGNAL ;
    PORT
      LAYER M5 ;
        RECT  2.208 77.544 2.232 77.736 ;
    END
  END a[33]
  PIN a[340]
    DIRECTION OUTPUT ;
    USE SIGNAL ;
    PORT
      LAYER M5 ;
        RECT  16.944 77.544 16.968 77.736 ;
    END
  END a[340]
  PIN a[341]
    DIRECTION OUTPUT ;
    USE SIGNAL ;
    PORT
      LAYER M5 ;
        RECT  16.992 77.544 17.016 77.736 ;
    END
  END a[341]
  PIN a[342]
    DIRECTION OUTPUT ;
    USE SIGNAL ;
    PORT
      LAYER M5 ;
        RECT  17.04 77.544 17.064 77.736 ;
    END
  END a[342]
  PIN a[343]
    DIRECTION OUTPUT ;
    USE SIGNAL ;
    PORT
      LAYER M5 ;
        RECT  17.088 77.544 17.112 77.736 ;
    END
  END a[343]
  PIN a[344]
    DIRECTION OUTPUT ;
    USE SIGNAL ;
    PORT
      LAYER M5 ;
        RECT  17.136 77.544 17.16 77.736 ;
    END
  END a[344]
  PIN a[345]
    DIRECTION OUTPUT ;
    USE SIGNAL ;
    PORT
      LAYER M5 ;
        RECT  17.184 77.544 17.208 77.736 ;
    END
  END a[345]
  PIN a[346]
    DIRECTION OUTPUT ;
    USE SIGNAL ;
    PORT
      LAYER M5 ;
        RECT  17.232 77.544 17.256 77.736 ;
    END
  END a[346]
  PIN a[347]
    DIRECTION OUTPUT ;
    USE SIGNAL ;
    PORT
      LAYER M5 ;
        RECT  17.28 77.544 17.304 77.736 ;
    END
  END a[347]
  PIN a[348]
    DIRECTION OUTPUT ;
    USE SIGNAL ;
    PORT
      LAYER M5 ;
        RECT  17.328 77.544 17.352 77.736 ;
    END
  END a[348]
  PIN a[349]
    DIRECTION OUTPUT ;
    USE SIGNAL ;
    PORT
      LAYER M5 ;
        RECT  17.376 77.544 17.4 77.736 ;
    END
  END a[349]
  PIN a[34]
    DIRECTION INPUT ;
    USE SIGNAL ;
    PORT
      LAYER M5 ;
        RECT  2.256 77.544 2.28 77.736 ;
    END
  END a[34]
  PIN a[350]
    DIRECTION OUTPUT ;
    USE SIGNAL ;
    PORT
      LAYER M5 ;
        RECT  17.424 77.544 17.448 77.736 ;
    END
  END a[350]
  PIN a[351]
    DIRECTION OUTPUT ;
    USE SIGNAL ;
    PORT
      LAYER M5 ;
        RECT  17.472 77.544 17.496 77.736 ;
    END
  END a[351]
  PIN a[352]
    DIRECTION OUTPUT ;
    USE SIGNAL ;
    PORT
      LAYER M5 ;
        RECT  17.52 77.544 17.544 77.736 ;
    END
  END a[352]
  PIN a[353]
    DIRECTION OUTPUT ;
    USE SIGNAL ;
    PORT
      LAYER M5 ;
        RECT  17.568 77.544 17.592 77.736 ;
    END
  END a[353]
  PIN a[354]
    DIRECTION OUTPUT ;
    USE SIGNAL ;
    PORT
      LAYER M5 ;
        RECT  17.616 77.544 17.64 77.736 ;
    END
  END a[354]
  PIN a[355]
    DIRECTION OUTPUT ;
    USE SIGNAL ;
    PORT
      LAYER M5 ;
        RECT  17.664 77.544 17.688 77.736 ;
    END
  END a[355]
  PIN a[356]
    DIRECTION OUTPUT ;
    USE SIGNAL ;
    PORT
      LAYER M5 ;
        RECT  17.712 77.544 17.736 77.736 ;
    END
  END a[356]
  PIN a[357]
    DIRECTION OUTPUT ;
    USE SIGNAL ;
    PORT
      LAYER M5 ;
        RECT  17.76 77.544 17.784 77.736 ;
    END
  END a[357]
  PIN a[358]
    DIRECTION OUTPUT ;
    USE SIGNAL ;
    PORT
      LAYER M5 ;
        RECT  17.808 77.544 17.832 77.736 ;
    END
  END a[358]
  PIN a[359]
    DIRECTION OUTPUT ;
    USE SIGNAL ;
    PORT
      LAYER M5 ;
        RECT  17.856 77.544 17.88 77.736 ;
    END
  END a[359]
  PIN a[35]
    DIRECTION INPUT ;
    USE SIGNAL ;
    PORT
      LAYER M5 ;
        RECT  2.304 77.544 2.328 77.736 ;
    END
  END a[35]
  PIN a[360]
    DIRECTION OUTPUT ;
    USE SIGNAL ;
    PORT
      LAYER M5 ;
        RECT  17.904 77.544 17.928 77.736 ;
    END
  END a[360]
  PIN a[361]
    DIRECTION OUTPUT ;
    USE SIGNAL ;
    PORT
      LAYER M5 ;
        RECT  17.952 77.544 17.976 77.736 ;
    END
  END a[361]
  PIN a[362]
    DIRECTION OUTPUT ;
    USE SIGNAL ;
    PORT
      LAYER M5 ;
        RECT  18 77.544 18.024 77.736 ;
    END
  END a[362]
  PIN a[363]
    DIRECTION OUTPUT ;
    USE SIGNAL ;
    PORT
      LAYER M5 ;
        RECT  18.048 77.544 18.072 77.736 ;
    END
  END a[363]
  PIN a[364]
    DIRECTION OUTPUT ;
    USE SIGNAL ;
    PORT
      LAYER M5 ;
        RECT  18.096 77.544 18.12 77.736 ;
    END
  END a[364]
  PIN a[365]
    DIRECTION OUTPUT ;
    USE SIGNAL ;
    PORT
      LAYER M5 ;
        RECT  18.144 77.544 18.168 77.736 ;
    END
  END a[365]
  PIN a[366]
    DIRECTION OUTPUT ;
    USE SIGNAL ;
    PORT
      LAYER M5 ;
        RECT  18.192 77.544 18.216 77.736 ;
    END
  END a[366]
  PIN a[367]
    DIRECTION OUTPUT ;
    USE SIGNAL ;
    PORT
      LAYER M5 ;
        RECT  18.24 77.544 18.264 77.736 ;
    END
  END a[367]
  PIN a[368]
    DIRECTION OUTPUT ;
    USE SIGNAL ;
    PORT
      LAYER M5 ;
        RECT  18.288 77.544 18.312 77.736 ;
    END
  END a[368]
  PIN a[369]
    DIRECTION OUTPUT ;
    USE SIGNAL ;
    PORT
      LAYER M5 ;
        RECT  18.336 77.544 18.36 77.736 ;
    END
  END a[369]
  PIN a[36]
    DIRECTION INPUT ;
    USE SIGNAL ;
    PORT
      LAYER M5 ;
        RECT  2.352 77.544 2.376 77.736 ;
    END
  END a[36]
  PIN a[370]
    DIRECTION OUTPUT ;
    USE SIGNAL ;
    PORT
      LAYER M5 ;
        RECT  18.384 77.544 18.408 77.736 ;
    END
  END a[370]
  PIN a[371]
    DIRECTION OUTPUT ;
    USE SIGNAL ;
    PORT
      LAYER M5 ;
        RECT  18.432 77.544 18.456 77.736 ;
    END
  END a[371]
  PIN a[372]
    DIRECTION OUTPUT ;
    USE SIGNAL ;
    PORT
      LAYER M5 ;
        RECT  18.48 77.544 18.504 77.736 ;
    END
  END a[372]
  PIN a[373]
    DIRECTION OUTPUT ;
    USE SIGNAL ;
    PORT
      LAYER M5 ;
        RECT  18.528 77.544 18.552 77.736 ;
    END
  END a[373]
  PIN a[374]
    DIRECTION OUTPUT ;
    USE SIGNAL ;
    PORT
      LAYER M5 ;
        RECT  18.576 77.544 18.6 77.736 ;
    END
  END a[374]
  PIN a[375]
    DIRECTION OUTPUT ;
    USE SIGNAL ;
    PORT
      LAYER M5 ;
        RECT  18.624 77.544 18.648 77.736 ;
    END
  END a[375]
  PIN a[376]
    DIRECTION OUTPUT ;
    USE SIGNAL ;
    PORT
      LAYER M5 ;
        RECT  18.672 77.544 18.696 77.736 ;
    END
  END a[376]
  PIN a[377]
    DIRECTION OUTPUT ;
    USE SIGNAL ;
    PORT
      LAYER M5 ;
        RECT  18.72 77.544 18.744 77.736 ;
    END
  END a[377]
  PIN a[378]
    DIRECTION OUTPUT ;
    USE SIGNAL ;
    PORT
      LAYER M5 ;
        RECT  18.768 77.544 18.792 77.736 ;
    END
  END a[378]
  PIN a[379]
    DIRECTION OUTPUT ;
    USE SIGNAL ;
    PORT
      LAYER M5 ;
        RECT  18.816 77.544 18.84 77.736 ;
    END
  END a[379]
  PIN a[37]
    DIRECTION INPUT ;
    USE SIGNAL ;
    PORT
      LAYER M5 ;
        RECT  2.4 77.544 2.424 77.736 ;
    END
  END a[37]
  PIN a[380]
    DIRECTION OUTPUT ;
    USE SIGNAL ;
    PORT
      LAYER M5 ;
        RECT  18.864 77.544 18.888 77.736 ;
    END
  END a[380]
  PIN a[381]
    DIRECTION OUTPUT ;
    USE SIGNAL ;
    PORT
      LAYER M5 ;
        RECT  18.912 77.544 18.936 77.736 ;
    END
  END a[381]
  PIN a[382]
    DIRECTION OUTPUT ;
    USE SIGNAL ;
    PORT
      LAYER M5 ;
        RECT  18.96 77.544 18.984 77.736 ;
    END
  END a[382]
  PIN a[383]
    DIRECTION OUTPUT ;
    USE SIGNAL ;
    PORT
      LAYER M5 ;
        RECT  19.008 77.544 19.032 77.736 ;
    END
  END a[383]
  PIN a[384]
    DIRECTION OUTPUT ;
    USE SIGNAL ;
    PORT
      LAYER M5 ;
        RECT  19.056 77.544 19.08 77.736 ;
    END
  END a[384]
  PIN a[385]
    DIRECTION OUTPUT ;
    USE SIGNAL ;
    PORT
      LAYER M5 ;
        RECT  19.104 77.544 19.128 77.736 ;
    END
  END a[385]
  PIN a[386]
    DIRECTION OUTPUT ;
    USE SIGNAL ;
    PORT
      LAYER M5 ;
        RECT  19.152 77.544 19.176 77.736 ;
    END
  END a[386]
  PIN a[387]
    DIRECTION OUTPUT ;
    USE SIGNAL ;
    PORT
      LAYER M5 ;
        RECT  19.2 77.544 19.224 77.736 ;
    END
  END a[387]
  PIN a[388]
    DIRECTION OUTPUT ;
    USE SIGNAL ;
    PORT
      LAYER M5 ;
        RECT  19.248 77.544 19.272 77.736 ;
    END
  END a[388]
  PIN a[389]
    DIRECTION OUTPUT ;
    USE SIGNAL ;
    PORT
      LAYER M5 ;
        RECT  19.296 77.544 19.32 77.736 ;
    END
  END a[389]
  PIN a[38]
    DIRECTION INPUT ;
    USE SIGNAL ;
    PORT
      LAYER M5 ;
        RECT  2.448 77.544 2.472 77.736 ;
    END
  END a[38]
  PIN a[390]
    DIRECTION OUTPUT ;
    USE SIGNAL ;
    PORT
      LAYER M5 ;
        RECT  19.344 77.544 19.368 77.736 ;
    END
  END a[390]
  PIN a[391]
    DIRECTION OUTPUT ;
    USE SIGNAL ;
    PORT
      LAYER M5 ;
        RECT  19.392 77.544 19.416 77.736 ;
    END
  END a[391]
  PIN a[392]
    DIRECTION OUTPUT ;
    USE SIGNAL ;
    PORT
      LAYER M5 ;
        RECT  19.44 77.544 19.464 77.736 ;
    END
  END a[392]
  PIN a[393]
    DIRECTION OUTPUT ;
    USE SIGNAL ;
    PORT
      LAYER M5 ;
        RECT  19.488 77.544 19.512 77.736 ;
    END
  END a[393]
  PIN a[394]
    DIRECTION OUTPUT ;
    USE SIGNAL ;
    PORT
      LAYER M5 ;
        RECT  19.536 77.544 19.56 77.736 ;
    END
  END a[394]
  PIN a[395]
    DIRECTION OUTPUT ;
    USE SIGNAL ;
    PORT
      LAYER M5 ;
        RECT  19.584 77.544 19.608 77.736 ;
    END
  END a[395]
  PIN a[396]
    DIRECTION OUTPUT ;
    USE SIGNAL ;
    PORT
      LAYER M5 ;
        RECT  19.632 77.544 19.656 77.736 ;
    END
  END a[396]
  PIN a[397]
    DIRECTION OUTPUT ;
    USE SIGNAL ;
    PORT
      LAYER M5 ;
        RECT  19.68 77.544 19.704 77.736 ;
    END
  END a[397]
  PIN a[398]
    DIRECTION OUTPUT ;
    USE SIGNAL ;
    PORT
      LAYER M5 ;
        RECT  19.728 77.544 19.752 77.736 ;
    END
  END a[398]
  PIN a[399]
    DIRECTION OUTPUT ;
    USE SIGNAL ;
    PORT
      LAYER M5 ;
        RECT  19.776 77.544 19.8 77.736 ;
    END
  END a[399]
  PIN a[39]
    DIRECTION INPUT ;
    USE SIGNAL ;
    PORT
      LAYER M5 ;
        RECT  2.496 77.544 2.52 77.736 ;
    END
  END a[39]
  PIN a[3]
    DIRECTION INPUT ;
    USE SIGNAL ;
    PORT
      LAYER M5 ;
        RECT  0.768 77.544 0.792 77.736 ;
    END
  END a[3]
  PIN a[400]
    DIRECTION OUTPUT ;
    USE SIGNAL ;
    PORT
      LAYER M5 ;
        RECT  19.824 77.544 19.848 77.736 ;
    END
  END a[400]
  PIN a[401]
    DIRECTION OUTPUT ;
    USE SIGNAL ;
    PORT
      LAYER M5 ;
        RECT  19.872 77.544 19.896 77.736 ;
    END
  END a[401]
  PIN a[402]
    DIRECTION OUTPUT ;
    USE SIGNAL ;
    PORT
      LAYER M5 ;
        RECT  19.92 77.544 19.944 77.736 ;
    END
  END a[402]
  PIN a[403]
    DIRECTION OUTPUT ;
    USE SIGNAL ;
    PORT
      LAYER M5 ;
        RECT  19.968 77.544 19.992 77.736 ;
    END
  END a[403]
  PIN a[404]
    DIRECTION OUTPUT ;
    USE SIGNAL ;
    PORT
      LAYER M5 ;
        RECT  20.016 77.544 20.04 77.736 ;
    END
  END a[404]
  PIN a[405]
    DIRECTION OUTPUT ;
    USE SIGNAL ;
    PORT
      LAYER M5 ;
        RECT  20.064 77.544 20.088 77.736 ;
    END
  END a[405]
  PIN a[406]
    DIRECTION OUTPUT ;
    USE SIGNAL ;
    PORT
      LAYER M5 ;
        RECT  20.112 77.544 20.136 77.736 ;
    END
  END a[406]
  PIN a[407]
    DIRECTION OUTPUT ;
    USE SIGNAL ;
    PORT
      LAYER M5 ;
        RECT  20.16 77.544 20.184 77.736 ;
    END
  END a[407]
  PIN a[408]
    DIRECTION OUTPUT ;
    USE SIGNAL ;
    PORT
      LAYER M5 ;
        RECT  20.208 77.544 20.232 77.736 ;
    END
  END a[408]
  PIN a[409]
    DIRECTION OUTPUT ;
    USE SIGNAL ;
    PORT
      LAYER M5 ;
        RECT  20.256 77.544 20.28 77.736 ;
    END
  END a[409]
  PIN a[40]
    DIRECTION INPUT ;
    USE SIGNAL ;
    PORT
      LAYER M5 ;
        RECT  2.544 77.544 2.568 77.736 ;
    END
  END a[40]
  PIN a[410]
    DIRECTION OUTPUT ;
    USE SIGNAL ;
    PORT
      LAYER M5 ;
        RECT  20.304 77.544 20.328 77.736 ;
    END
  END a[410]
  PIN a[411]
    DIRECTION OUTPUT ;
    USE SIGNAL ;
    PORT
      LAYER M5 ;
        RECT  20.352 77.544 20.376 77.736 ;
    END
  END a[411]
  PIN a[412]
    DIRECTION OUTPUT ;
    USE SIGNAL ;
    PORT
      LAYER M5 ;
        RECT  20.4 77.544 20.424 77.736 ;
    END
  END a[412]
  PIN a[413]
    DIRECTION OUTPUT ;
    USE SIGNAL ;
    PORT
      LAYER M5 ;
        RECT  20.448 77.544 20.472 77.736 ;
    END
  END a[413]
  PIN a[414]
    DIRECTION OUTPUT ;
    USE SIGNAL ;
    PORT
      LAYER M5 ;
        RECT  20.496 77.544 20.52 77.736 ;
    END
  END a[414]
  PIN a[415]
    DIRECTION OUTPUT ;
    USE SIGNAL ;
    PORT
      LAYER M5 ;
        RECT  20.544 77.544 20.568 77.736 ;
    END
  END a[415]
  PIN a[416]
    DIRECTION OUTPUT ;
    USE SIGNAL ;
    PORT
      LAYER M5 ;
        RECT  20.592 77.544 20.616 77.736 ;
    END
  END a[416]
  PIN a[417]
    DIRECTION OUTPUT ;
    USE SIGNAL ;
    PORT
      LAYER M5 ;
        RECT  20.64 77.544 20.664 77.736 ;
    END
  END a[417]
  PIN a[418]
    DIRECTION OUTPUT ;
    USE SIGNAL ;
    PORT
      LAYER M5 ;
        RECT  20.688 77.544 20.712 77.736 ;
    END
  END a[418]
  PIN a[419]
    DIRECTION OUTPUT ;
    USE SIGNAL ;
    PORT
      LAYER M5 ;
        RECT  20.736 77.544 20.76 77.736 ;
    END
  END a[419]
  PIN a[41]
    DIRECTION INPUT ;
    USE SIGNAL ;
    PORT
      LAYER M5 ;
        RECT  2.592 77.544 2.616 77.736 ;
    END
  END a[41]
  PIN a[420]
    DIRECTION OUTPUT ;
    USE SIGNAL ;
    PORT
      LAYER M5 ;
        RECT  20.784 77.544 20.808 77.736 ;
    END
  END a[420]
  PIN a[421]
    DIRECTION OUTPUT ;
    USE SIGNAL ;
    PORT
      LAYER M5 ;
        RECT  20.832 77.544 20.856 77.736 ;
    END
  END a[421]
  PIN a[422]
    DIRECTION OUTPUT ;
    USE SIGNAL ;
    PORT
      LAYER M5 ;
        RECT  20.88 77.544 20.904 77.736 ;
    END
  END a[422]
  PIN a[423]
    DIRECTION OUTPUT ;
    USE SIGNAL ;
    PORT
      LAYER M5 ;
        RECT  20.928 77.544 20.952 77.736 ;
    END
  END a[423]
  PIN a[424]
    DIRECTION OUTPUT ;
    USE SIGNAL ;
    PORT
      LAYER M5 ;
        RECT  20.976 77.544 21 77.736 ;
    END
  END a[424]
  PIN a[425]
    DIRECTION OUTPUT ;
    USE SIGNAL ;
    PORT
      LAYER M5 ;
        RECT  21.024 77.544 21.048 77.736 ;
    END
  END a[425]
  PIN a[426]
    DIRECTION OUTPUT ;
    USE SIGNAL ;
    PORT
      LAYER M5 ;
        RECT  21.072 77.544 21.096 77.736 ;
    END
  END a[426]
  PIN a[427]
    DIRECTION OUTPUT ;
    USE SIGNAL ;
    PORT
      LAYER M5 ;
        RECT  21.12 77.544 21.144 77.736 ;
    END
  END a[427]
  PIN a[428]
    DIRECTION OUTPUT ;
    USE SIGNAL ;
    PORT
      LAYER M5 ;
        RECT  21.168 77.544 21.192 77.736 ;
    END
  END a[428]
  PIN a[429]
    DIRECTION OUTPUT ;
    USE SIGNAL ;
    PORT
      LAYER M5 ;
        RECT  21.216 77.544 21.24 77.736 ;
    END
  END a[429]
  PIN a[42]
    DIRECTION INPUT ;
    USE SIGNAL ;
    PORT
      LAYER M5 ;
        RECT  2.64 77.544 2.664 77.736 ;
    END
  END a[42]
  PIN a[430]
    DIRECTION OUTPUT ;
    USE SIGNAL ;
    PORT
      LAYER M5 ;
        RECT  21.264 77.544 21.288 77.736 ;
    END
  END a[430]
  PIN a[431]
    DIRECTION OUTPUT ;
    USE SIGNAL ;
    PORT
      LAYER M5 ;
        RECT  21.312 77.544 21.336 77.736 ;
    END
  END a[431]
  PIN a[432]
    DIRECTION OUTPUT ;
    USE SIGNAL ;
    PORT
      LAYER M5 ;
        RECT  21.36 77.544 21.384 77.736 ;
    END
  END a[432]
  PIN a[433]
    DIRECTION OUTPUT ;
    USE SIGNAL ;
    PORT
      LAYER M5 ;
        RECT  21.408 77.544 21.432 77.736 ;
    END
  END a[433]
  PIN a[434]
    DIRECTION OUTPUT ;
    USE SIGNAL ;
    PORT
      LAYER M5 ;
        RECT  21.456 77.544 21.48 77.736 ;
    END
  END a[434]
  PIN a[435]
    DIRECTION OUTPUT ;
    USE SIGNAL ;
    PORT
      LAYER M5 ;
        RECT  21.504 77.544 21.528 77.736 ;
    END
  END a[435]
  PIN a[436]
    DIRECTION OUTPUT ;
    USE SIGNAL ;
    PORT
      LAYER M5 ;
        RECT  21.552 77.544 21.576 77.736 ;
    END
  END a[436]
  PIN a[437]
    DIRECTION OUTPUT ;
    USE SIGNAL ;
    PORT
      LAYER M5 ;
        RECT  21.6 77.544 21.624 77.736 ;
    END
  END a[437]
  PIN a[438]
    DIRECTION OUTPUT ;
    USE SIGNAL ;
    PORT
      LAYER M5 ;
        RECT  21.648 77.544 21.672 77.736 ;
    END
  END a[438]
  PIN a[439]
    DIRECTION OUTPUT ;
    USE SIGNAL ;
    PORT
      LAYER M5 ;
        RECT  21.696 77.544 21.72 77.736 ;
    END
  END a[439]
  PIN a[43]
    DIRECTION INPUT ;
    USE SIGNAL ;
    PORT
      LAYER M5 ;
        RECT  2.688 77.544 2.712 77.736 ;
    END
  END a[43]
  PIN a[440]
    DIRECTION OUTPUT ;
    USE SIGNAL ;
    PORT
      LAYER M5 ;
        RECT  21.744 77.544 21.768 77.736 ;
    END
  END a[440]
  PIN a[441]
    DIRECTION OUTPUT ;
    USE SIGNAL ;
    PORT
      LAYER M5 ;
        RECT  21.792 77.544 21.816 77.736 ;
    END
  END a[441]
  PIN a[442]
    DIRECTION OUTPUT ;
    USE SIGNAL ;
    PORT
      LAYER M5 ;
        RECT  21.84 77.544 21.864 77.736 ;
    END
  END a[442]
  PIN a[443]
    DIRECTION OUTPUT ;
    USE SIGNAL ;
    PORT
      LAYER M5 ;
        RECT  21.888 77.544 21.912 77.736 ;
    END
  END a[443]
  PIN a[444]
    DIRECTION OUTPUT ;
    USE SIGNAL ;
    PORT
      LAYER M5 ;
        RECT  21.936 77.544 21.96 77.736 ;
    END
  END a[444]
  PIN a[445]
    DIRECTION OUTPUT ;
    USE SIGNAL ;
    PORT
      LAYER M5 ;
        RECT  21.984 77.544 22.008 77.736 ;
    END
  END a[445]
  PIN a[446]
    DIRECTION OUTPUT ;
    USE SIGNAL ;
    PORT
      LAYER M5 ;
        RECT  22.032 77.544 22.056 77.736 ;
    END
  END a[446]
  PIN a[447]
    DIRECTION OUTPUT ;
    USE SIGNAL ;
    PORT
      LAYER M5 ;
        RECT  22.08 77.544 22.104 77.736 ;
    END
  END a[447]
  PIN a[448]
    DIRECTION OUTPUT ;
    USE SIGNAL ;
    PORT
      LAYER M5 ;
        RECT  22.128 77.544 22.152 77.736 ;
    END
  END a[448]
  PIN a[449]
    DIRECTION OUTPUT ;
    USE SIGNAL ;
    PORT
      LAYER M5 ;
        RECT  22.176 77.544 22.2 77.736 ;
    END
  END a[449]
  PIN a[44]
    DIRECTION INPUT ;
    USE SIGNAL ;
    PORT
      LAYER M5 ;
        RECT  2.736 77.544 2.76 77.736 ;
    END
  END a[44]
  PIN a[450]
    DIRECTION OUTPUT ;
    USE SIGNAL ;
    PORT
      LAYER M5 ;
        RECT  22.224 77.544 22.248 77.736 ;
    END
  END a[450]
  PIN a[451]
    DIRECTION OUTPUT ;
    USE SIGNAL ;
    PORT
      LAYER M5 ;
        RECT  22.272 77.544 22.296 77.736 ;
    END
  END a[451]
  PIN a[452]
    DIRECTION OUTPUT ;
    USE SIGNAL ;
    PORT
      LAYER M5 ;
        RECT  22.32 77.544 22.344 77.736 ;
    END
  END a[452]
  PIN a[453]
    DIRECTION OUTPUT ;
    USE SIGNAL ;
    PORT
      LAYER M5 ;
        RECT  22.368 77.544 22.392 77.736 ;
    END
  END a[453]
  PIN a[454]
    DIRECTION OUTPUT ;
    USE SIGNAL ;
    PORT
      LAYER M5 ;
        RECT  22.416 77.544 22.44 77.736 ;
    END
  END a[454]
  PIN a[455]
    DIRECTION OUTPUT ;
    USE SIGNAL ;
    PORT
      LAYER M5 ;
        RECT  22.464 77.544 22.488 77.736 ;
    END
  END a[455]
  PIN a[456]
    DIRECTION OUTPUT ;
    USE SIGNAL ;
    PORT
      LAYER M5 ;
        RECT  22.512 77.544 22.536 77.736 ;
    END
  END a[456]
  PIN a[457]
    DIRECTION OUTPUT ;
    USE SIGNAL ;
    PORT
      LAYER M5 ;
        RECT  22.56 77.544 22.584 77.736 ;
    END
  END a[457]
  PIN a[458]
    DIRECTION OUTPUT ;
    USE SIGNAL ;
    PORT
      LAYER M5 ;
        RECT  22.608 77.544 22.632 77.736 ;
    END
  END a[458]
  PIN a[459]
    DIRECTION OUTPUT ;
    USE SIGNAL ;
    PORT
      LAYER M5 ;
        RECT  22.656 77.544 22.68 77.736 ;
    END
  END a[459]
  PIN a[45]
    DIRECTION INPUT ;
    USE SIGNAL ;
    PORT
      LAYER M5 ;
        RECT  2.784 77.544 2.808 77.736 ;
    END
  END a[45]
  PIN a[460]
    DIRECTION OUTPUT ;
    USE SIGNAL ;
    PORT
      LAYER M5 ;
        RECT  22.704 77.544 22.728 77.736 ;
    END
  END a[460]
  PIN a[461]
    DIRECTION OUTPUT ;
    USE SIGNAL ;
    PORT
      LAYER M5 ;
        RECT  22.752 77.544 22.776 77.736 ;
    END
  END a[461]
  PIN a[462]
    DIRECTION OUTPUT ;
    USE SIGNAL ;
    PORT
      LAYER M5 ;
        RECT  22.8 77.544 22.824 77.736 ;
    END
  END a[462]
  PIN a[463]
    DIRECTION OUTPUT ;
    USE SIGNAL ;
    PORT
      LAYER M5 ;
        RECT  22.848 77.544 22.872 77.736 ;
    END
  END a[463]
  PIN a[464]
    DIRECTION OUTPUT ;
    USE SIGNAL ;
    PORT
      LAYER M5 ;
        RECT  22.896 77.544 22.92 77.736 ;
    END
  END a[464]
  PIN a[465]
    DIRECTION OUTPUT ;
    USE SIGNAL ;
    PORT
      LAYER M5 ;
        RECT  22.944 77.544 22.968 77.736 ;
    END
  END a[465]
  PIN a[466]
    DIRECTION OUTPUT ;
    USE SIGNAL ;
    PORT
      LAYER M5 ;
        RECT  22.992 77.544 23.016 77.736 ;
    END
  END a[466]
  PIN a[467]
    DIRECTION OUTPUT ;
    USE SIGNAL ;
    PORT
      LAYER M5 ;
        RECT  23.04 77.544 23.064 77.736 ;
    END
  END a[467]
  PIN a[468]
    DIRECTION OUTPUT ;
    USE SIGNAL ;
    PORT
      LAYER M5 ;
        RECT  23.088 77.544 23.112 77.736 ;
    END
  END a[468]
  PIN a[469]
    DIRECTION OUTPUT ;
    USE SIGNAL ;
    PORT
      LAYER M5 ;
        RECT  23.136 77.544 23.16 77.736 ;
    END
  END a[469]
  PIN a[46]
    DIRECTION INPUT ;
    USE SIGNAL ;
    PORT
      LAYER M5 ;
        RECT  2.832 77.544 2.856 77.736 ;
    END
  END a[46]
  PIN a[470]
    DIRECTION OUTPUT ;
    USE SIGNAL ;
    PORT
      LAYER M5 ;
        RECT  23.184 77.544 23.208 77.736 ;
    END
  END a[470]
  PIN a[471]
    DIRECTION OUTPUT ;
    USE SIGNAL ;
    PORT
      LAYER M5 ;
        RECT  23.232 77.544 23.256 77.736 ;
    END
  END a[471]
  PIN a[472]
    DIRECTION OUTPUT ;
    USE SIGNAL ;
    PORT
      LAYER M5 ;
        RECT  23.28 77.544 23.304 77.736 ;
    END
  END a[472]
  PIN a[473]
    DIRECTION OUTPUT ;
    USE SIGNAL ;
    PORT
      LAYER M5 ;
        RECT  23.328 77.544 23.352 77.736 ;
    END
  END a[473]
  PIN a[474]
    DIRECTION OUTPUT ;
    USE SIGNAL ;
    PORT
      LAYER M5 ;
        RECT  23.376 77.544 23.4 77.736 ;
    END
  END a[474]
  PIN a[475]
    DIRECTION OUTPUT ;
    USE SIGNAL ;
    PORT
      LAYER M5 ;
        RECT  23.424 77.544 23.448 77.736 ;
    END
  END a[475]
  PIN a[476]
    DIRECTION OUTPUT ;
    USE SIGNAL ;
    PORT
      LAYER M5 ;
        RECT  23.472 77.544 23.496 77.736 ;
    END
  END a[476]
  PIN a[477]
    DIRECTION OUTPUT ;
    USE SIGNAL ;
    PORT
      LAYER M5 ;
        RECT  23.52 77.544 23.544 77.736 ;
    END
  END a[477]
  PIN a[478]
    DIRECTION OUTPUT ;
    USE SIGNAL ;
    PORT
      LAYER M5 ;
        RECT  23.568 77.544 23.592 77.736 ;
    END
  END a[478]
  PIN a[479]
    DIRECTION OUTPUT ;
    USE SIGNAL ;
    PORT
      LAYER M5 ;
        RECT  23.616 77.544 23.64 77.736 ;
    END
  END a[479]
  PIN a[47]
    DIRECTION INPUT ;
    USE SIGNAL ;
    PORT
      LAYER M5 ;
        RECT  2.88 77.544 2.904 77.736 ;
    END
  END a[47]
  PIN a[480]
    DIRECTION OUTPUT ;
    USE SIGNAL ;
    PORT
      LAYER M5 ;
        RECT  23.664 77.544 23.688 77.736 ;
    END
  END a[480]
  PIN a[481]
    DIRECTION OUTPUT ;
    USE SIGNAL ;
    PORT
      LAYER M5 ;
        RECT  23.712 77.544 23.736 77.736 ;
    END
  END a[481]
  PIN a[482]
    DIRECTION OUTPUT ;
    USE SIGNAL ;
    PORT
      LAYER M5 ;
        RECT  23.76 77.544 23.784 77.736 ;
    END
  END a[482]
  PIN a[483]
    DIRECTION OUTPUT ;
    USE SIGNAL ;
    PORT
      LAYER M5 ;
        RECT  23.808 77.544 23.832 77.736 ;
    END
  END a[483]
  PIN a[484]
    DIRECTION OUTPUT ;
    USE SIGNAL ;
    PORT
      LAYER M5 ;
        RECT  23.856 77.544 23.88 77.736 ;
    END
  END a[484]
  PIN a[485]
    DIRECTION OUTPUT ;
    USE SIGNAL ;
    PORT
      LAYER M5 ;
        RECT  23.904 77.544 23.928 77.736 ;
    END
  END a[485]
  PIN a[486]
    DIRECTION OUTPUT ;
    USE SIGNAL ;
    PORT
      LAYER M5 ;
        RECT  23.952 77.544 23.976 77.736 ;
    END
  END a[486]
  PIN a[487]
    DIRECTION OUTPUT ;
    USE SIGNAL ;
    PORT
      LAYER M5 ;
        RECT  24 77.544 24.024 77.736 ;
    END
  END a[487]
  PIN a[488]
    DIRECTION OUTPUT ;
    USE SIGNAL ;
    PORT
      LAYER M5 ;
        RECT  24.048 77.544 24.072 77.736 ;
    END
  END a[488]
  PIN a[489]
    DIRECTION OUTPUT ;
    USE SIGNAL ;
    PORT
      LAYER M5 ;
        RECT  24.096 77.544 24.12 77.736 ;
    END
  END a[489]
  PIN a[48]
    DIRECTION INPUT ;
    USE SIGNAL ;
    PORT
      LAYER M5 ;
        RECT  2.928 77.544 2.952 77.736 ;
    END
  END a[48]
  PIN a[490]
    DIRECTION OUTPUT ;
    USE SIGNAL ;
    PORT
      LAYER M5 ;
        RECT  24.144 77.544 24.168 77.736 ;
    END
  END a[490]
  PIN a[491]
    DIRECTION OUTPUT ;
    USE SIGNAL ;
    PORT
      LAYER M5 ;
        RECT  24.192 77.544 24.216 77.736 ;
    END
  END a[491]
  PIN a[492]
    DIRECTION OUTPUT ;
    USE SIGNAL ;
    PORT
      LAYER M5 ;
        RECT  24.24 77.544 24.264 77.736 ;
    END
  END a[492]
  PIN a[493]
    DIRECTION OUTPUT ;
    USE SIGNAL ;
    PORT
      LAYER M5 ;
        RECT  24.288 77.544 24.312 77.736 ;
    END
  END a[493]
  PIN a[494]
    DIRECTION OUTPUT ;
    USE SIGNAL ;
    PORT
      LAYER M5 ;
        RECT  24.336 77.544 24.36 77.736 ;
    END
  END a[494]
  PIN a[495]
    DIRECTION OUTPUT ;
    USE SIGNAL ;
    PORT
      LAYER M5 ;
        RECT  24.384 77.544 24.408 77.736 ;
    END
  END a[495]
  PIN a[496]
    DIRECTION OUTPUT ;
    USE SIGNAL ;
    PORT
      LAYER M5 ;
        RECT  24.432 77.544 24.456 77.736 ;
    END
  END a[496]
  PIN a[497]
    DIRECTION OUTPUT ;
    USE SIGNAL ;
    PORT
      LAYER M5 ;
        RECT  24.48 77.544 24.504 77.736 ;
    END
  END a[497]
  PIN a[498]
    DIRECTION OUTPUT ;
    USE SIGNAL ;
    PORT
      LAYER M5 ;
        RECT  24.528 77.544 24.552 77.736 ;
    END
  END a[498]
  PIN a[499]
    DIRECTION OUTPUT ;
    USE SIGNAL ;
    PORT
      LAYER M5 ;
        RECT  24.576 77.544 24.6 77.736 ;
    END
  END a[499]
  PIN a[49]
    DIRECTION INPUT ;
    USE SIGNAL ;
    PORT
      LAYER M5 ;
        RECT  2.976 77.544 3 77.736 ;
    END
  END a[49]
  PIN a[4]
    DIRECTION INPUT ;
    USE SIGNAL ;
    PORT
      LAYER M5 ;
        RECT  0.816 77.544 0.84 77.736 ;
    END
  END a[4]
  PIN a[500]
    DIRECTION OUTPUT ;
    USE SIGNAL ;
    PORT
      LAYER M5 ;
        RECT  24.624 77.544 24.648 77.736 ;
    END
  END a[500]
  PIN a[501]
    DIRECTION OUTPUT ;
    USE SIGNAL ;
    PORT
      LAYER M5 ;
        RECT  24.672 77.544 24.696 77.736 ;
    END
  END a[501]
  PIN a[502]
    DIRECTION OUTPUT ;
    USE SIGNAL ;
    PORT
      LAYER M5 ;
        RECT  24.72 77.544 24.744 77.736 ;
    END
  END a[502]
  PIN a[503]
    DIRECTION OUTPUT ;
    USE SIGNAL ;
    PORT
      LAYER M5 ;
        RECT  24.768 77.544 24.792 77.736 ;
    END
  END a[503]
  PIN a[504]
    DIRECTION OUTPUT ;
    USE SIGNAL ;
    PORT
      LAYER M5 ;
        RECT  24.816 77.544 24.84 77.736 ;
    END
  END a[504]
  PIN a[505]
    DIRECTION OUTPUT ;
    USE SIGNAL ;
    PORT
      LAYER M5 ;
        RECT  24.864 77.544 24.888 77.736 ;
    END
  END a[505]
  PIN a[506]
    DIRECTION OUTPUT ;
    USE SIGNAL ;
    PORT
      LAYER M5 ;
        RECT  24.912 77.544 24.936 77.736 ;
    END
  END a[506]
  PIN a[507]
    DIRECTION OUTPUT ;
    USE SIGNAL ;
    PORT
      LAYER M5 ;
        RECT  24.96 77.544 24.984 77.736 ;
    END
  END a[507]
  PIN a[508]
    DIRECTION OUTPUT ;
    USE SIGNAL ;
    PORT
      LAYER M5 ;
        RECT  25.008 77.544 25.032 77.736 ;
    END
  END a[508]
  PIN a[509]
    DIRECTION OUTPUT ;
    USE SIGNAL ;
    PORT
      LAYER M5 ;
        RECT  25.056 77.544 25.08 77.736 ;
    END
  END a[509]
  PIN a[50]
    DIRECTION INPUT ;
    USE SIGNAL ;
    PORT
      LAYER M5 ;
        RECT  3.024 77.544 3.048 77.736 ;
    END
  END a[50]
  PIN a[510]
    DIRECTION OUTPUT ;
    USE SIGNAL ;
    PORT
      LAYER M5 ;
        RECT  25.104 77.544 25.128 77.736 ;
    END
  END a[510]
  PIN a[511]
    DIRECTION OUTPUT ;
    USE SIGNAL ;
    PORT
      LAYER M5 ;
        RECT  25.152 77.544 25.176 77.736 ;
    END
  END a[511]
  PIN a[512]
    DIRECTION INPUT ;
    USE SIGNAL ;
    PORT
      LAYER M5 ;
        RECT  25.2 77.544 25.224 77.736 ;
    END
  END a[512]
  PIN a[513]
    DIRECTION OUTPUT ;
    USE SIGNAL ;
    PORT
      LAYER M5 ;
        RECT  25.248 77.544 25.272 77.736 ;
    END
  END a[513]
  PIN a[51]
    DIRECTION INPUT ;
    USE SIGNAL ;
    PORT
      LAYER M5 ;
        RECT  3.072 77.544 3.096 77.736 ;
    END
  END a[51]
  PIN a[52]
    DIRECTION INPUT ;
    USE SIGNAL ;
    PORT
      LAYER M5 ;
        RECT  3.12 77.544 3.144 77.736 ;
    END
  END a[52]
  PIN a[53]
    DIRECTION INPUT ;
    USE SIGNAL ;
    PORT
      LAYER M5 ;
        RECT  3.168 77.544 3.192 77.736 ;
    END
  END a[53]
  PIN a[54]
    DIRECTION INPUT ;
    USE SIGNAL ;
    PORT
      LAYER M5 ;
        RECT  3.216 77.544 3.24 77.736 ;
    END
  END a[54]
  PIN a[55]
    DIRECTION INPUT ;
    USE SIGNAL ;
    PORT
      LAYER M5 ;
        RECT  3.264 77.544 3.288 77.736 ;
    END
  END a[55]
  PIN a[56]
    DIRECTION INPUT ;
    USE SIGNAL ;
    PORT
      LAYER M5 ;
        RECT  3.312 77.544 3.336 77.736 ;
    END
  END a[56]
  PIN a[57]
    DIRECTION INPUT ;
    USE SIGNAL ;
    PORT
      LAYER M5 ;
        RECT  3.36 77.544 3.384 77.736 ;
    END
  END a[57]
  PIN a[58]
    DIRECTION INPUT ;
    USE SIGNAL ;
    PORT
      LAYER M5 ;
        RECT  3.408 77.544 3.432 77.736 ;
    END
  END a[58]
  PIN a[59]
    DIRECTION INPUT ;
    USE SIGNAL ;
    PORT
      LAYER M5 ;
        RECT  3.456 77.544 3.48 77.736 ;
    END
  END a[59]
  PIN a[5]
    DIRECTION INPUT ;
    USE SIGNAL ;
    PORT
      LAYER M5 ;
        RECT  0.864 77.544 0.888 77.736 ;
    END
  END a[5]
  PIN a[60]
    DIRECTION INPUT ;
    USE SIGNAL ;
    PORT
      LAYER M5 ;
        RECT  3.504 77.544 3.528 77.736 ;
    END
  END a[60]
  PIN a[61]
    DIRECTION INPUT ;
    USE SIGNAL ;
    PORT
      LAYER M5 ;
        RECT  3.552 77.544 3.576 77.736 ;
    END
  END a[61]
  PIN a[62]
    DIRECTION INPUT ;
    USE SIGNAL ;
    PORT
      LAYER M5 ;
        RECT  3.6 77.544 3.624 77.736 ;
    END
  END a[62]
  PIN a[63]
    DIRECTION INPUT ;
    USE SIGNAL ;
    PORT
      LAYER M5 ;
        RECT  3.648 77.544 3.672 77.736 ;
    END
  END a[63]
  PIN a[64]
    DIRECTION INPUT ;
    USE SIGNAL ;
    PORT
      LAYER M5 ;
        RECT  3.696 77.544 3.72 77.736 ;
    END
  END a[64]
  PIN a[65]
    DIRECTION INPUT ;
    USE SIGNAL ;
    PORT
      LAYER M5 ;
        RECT  3.744 77.544 3.768 77.736 ;
    END
  END a[65]
  PIN a[66]
    DIRECTION INPUT ;
    USE SIGNAL ;
    PORT
      LAYER M5 ;
        RECT  3.792 77.544 3.816 77.736 ;
    END
  END a[66]
  PIN a[67]
    DIRECTION INPUT ;
    USE SIGNAL ;
    PORT
      LAYER M5 ;
        RECT  3.84 77.544 3.864 77.736 ;
    END
  END a[67]
  PIN a[68]
    DIRECTION INPUT ;
    USE SIGNAL ;
    PORT
      LAYER M5 ;
        RECT  3.888 77.544 3.912 77.736 ;
    END
  END a[68]
  PIN a[69]
    DIRECTION INPUT ;
    USE SIGNAL ;
    PORT
      LAYER M5 ;
        RECT  3.936 77.544 3.96 77.736 ;
    END
  END a[69]
  PIN a[6]
    DIRECTION INPUT ;
    USE SIGNAL ;
    PORT
      LAYER M5 ;
        RECT  0.912 77.544 0.936 77.736 ;
    END
  END a[6]
  PIN a[70]
    DIRECTION INPUT ;
    USE SIGNAL ;
    PORT
      LAYER M5 ;
        RECT  3.984 77.544 4.008 77.736 ;
    END
  END a[70]
  PIN a[71]
    DIRECTION INPUT ;
    USE SIGNAL ;
    PORT
      LAYER M5 ;
        RECT  4.032 77.544 4.056 77.736 ;
    END
  END a[71]
  PIN a[72]
    DIRECTION INPUT ;
    USE SIGNAL ;
    PORT
      LAYER M5 ;
        RECT  4.08 77.544 4.104 77.736 ;
    END
  END a[72]
  PIN a[73]
    DIRECTION INPUT ;
    USE SIGNAL ;
    PORT
      LAYER M5 ;
        RECT  4.128 77.544 4.152 77.736 ;
    END
  END a[73]
  PIN a[74]
    DIRECTION INPUT ;
    USE SIGNAL ;
    PORT
      LAYER M5 ;
        RECT  4.176 77.544 4.2 77.736 ;
    END
  END a[74]
  PIN a[75]
    DIRECTION INPUT ;
    USE SIGNAL ;
    PORT
      LAYER M5 ;
        RECT  4.224 77.544 4.248 77.736 ;
    END
  END a[75]
  PIN a[76]
    DIRECTION INPUT ;
    USE SIGNAL ;
    PORT
      LAYER M5 ;
        RECT  4.272 77.544 4.296 77.736 ;
    END
  END a[76]
  PIN a[77]
    DIRECTION INPUT ;
    USE SIGNAL ;
    PORT
      LAYER M5 ;
        RECT  4.32 77.544 4.344 77.736 ;
    END
  END a[77]
  PIN a[78]
    DIRECTION INPUT ;
    USE SIGNAL ;
    PORT
      LAYER M5 ;
        RECT  4.368 77.544 4.392 77.736 ;
    END
  END a[78]
  PIN a[79]
    DIRECTION INPUT ;
    USE SIGNAL ;
    PORT
      LAYER M5 ;
        RECT  4.416 77.544 4.44 77.736 ;
    END
  END a[79]
  PIN a[7]
    DIRECTION INPUT ;
    USE SIGNAL ;
    PORT
      LAYER M5 ;
        RECT  0.96 77.544 0.984 77.736 ;
    END
  END a[7]
  PIN a[80]
    DIRECTION INPUT ;
    USE SIGNAL ;
    PORT
      LAYER M5 ;
        RECT  4.464 77.544 4.488 77.736 ;
    END
  END a[80]
  PIN a[81]
    DIRECTION INPUT ;
    USE SIGNAL ;
    PORT
      LAYER M5 ;
        RECT  4.512 77.544 4.536 77.736 ;
    END
  END a[81]
  PIN a[82]
    DIRECTION INPUT ;
    USE SIGNAL ;
    PORT
      LAYER M5 ;
        RECT  4.56 77.544 4.584 77.736 ;
    END
  END a[82]
  PIN a[83]
    DIRECTION INPUT ;
    USE SIGNAL ;
    PORT
      LAYER M5 ;
        RECT  4.608 77.544 4.632 77.736 ;
    END
  END a[83]
  PIN a[84]
    DIRECTION INPUT ;
    USE SIGNAL ;
    PORT
      LAYER M5 ;
        RECT  4.656 77.544 4.68 77.736 ;
    END
  END a[84]
  PIN a[85]
    DIRECTION INPUT ;
    USE SIGNAL ;
    PORT
      LAYER M5 ;
        RECT  4.704 77.544 4.728 77.736 ;
    END
  END a[85]
  PIN a[86]
    DIRECTION INPUT ;
    USE SIGNAL ;
    PORT
      LAYER M5 ;
        RECT  4.752 77.544 4.776 77.736 ;
    END
  END a[86]
  PIN a[87]
    DIRECTION INPUT ;
    USE SIGNAL ;
    PORT
      LAYER M5 ;
        RECT  4.8 77.544 4.824 77.736 ;
    END
  END a[87]
  PIN a[88]
    DIRECTION INPUT ;
    USE SIGNAL ;
    PORT
      LAYER M5 ;
        RECT  4.848 77.544 4.872 77.736 ;
    END
  END a[88]
  PIN a[89]
    DIRECTION INPUT ;
    USE SIGNAL ;
    PORT
      LAYER M5 ;
        RECT  4.896 77.544 4.92 77.736 ;
    END
  END a[89]
  PIN a[8]
    DIRECTION INPUT ;
    USE SIGNAL ;
    PORT
      LAYER M5 ;
        RECT  1.008 77.544 1.032 77.736 ;
    END
  END a[8]
  PIN a[90]
    DIRECTION INPUT ;
    USE SIGNAL ;
    PORT
      LAYER M5 ;
        RECT  4.944 77.544 4.968 77.736 ;
    END
  END a[90]
  PIN a[91]
    DIRECTION INPUT ;
    USE SIGNAL ;
    PORT
      LAYER M5 ;
        RECT  4.992 77.544 5.016 77.736 ;
    END
  END a[91]
  PIN a[92]
    DIRECTION INPUT ;
    USE SIGNAL ;
    PORT
      LAYER M5 ;
        RECT  5.04 77.544 5.064 77.736 ;
    END
  END a[92]
  PIN a[93]
    DIRECTION INPUT ;
    USE SIGNAL ;
    PORT
      LAYER M5 ;
        RECT  5.088 77.544 5.112 77.736 ;
    END
  END a[93]
  PIN a[94]
    DIRECTION INPUT ;
    USE SIGNAL ;
    PORT
      LAYER M5 ;
        RECT  5.136 77.544 5.16 77.736 ;
    END
  END a[94]
  PIN a[95]
    DIRECTION INPUT ;
    USE SIGNAL ;
    PORT
      LAYER M5 ;
        RECT  5.184 77.544 5.208 77.736 ;
    END
  END a[95]
  PIN a[96]
    DIRECTION INPUT ;
    USE SIGNAL ;
    PORT
      LAYER M5 ;
        RECT  5.232 77.544 5.256 77.736 ;
    END
  END a[96]
  PIN a[97]
    DIRECTION INPUT ;
    USE SIGNAL ;
    PORT
      LAYER M5 ;
        RECT  5.28 77.544 5.304 77.736 ;
    END
  END a[97]
  PIN a[98]
    DIRECTION INPUT ;
    USE SIGNAL ;
    PORT
      LAYER M5 ;
        RECT  5.328 77.544 5.352 77.736 ;
    END
  END a[98]
  PIN a[99]
    DIRECTION INPUT ;
    USE SIGNAL ;
    PORT
      LAYER M5 ;
        RECT  5.376 77.544 5.4 77.736 ;
    END
  END a[99]
  PIN a[9]
    DIRECTION INPUT ;
    USE SIGNAL ;
    PORT
      LAYER M5 ;
        RECT  1.056 77.544 1.08 77.736 ;
    END
  END a[9]
  PIN b[0]
    DIRECTION OUTPUT ;
    USE SIGNAL ;
    PORT
      LAYER M5 ;
        RECT  14.016 0 14.04 0.192 ;
    END
  END b[0]
  PIN b[100]
    DIRECTION OUTPUT ;
    USE SIGNAL ;
    PORT
      LAYER M5 ;
        RECT  18.816 0 18.84 0.192 ;
    END
  END b[100]
  PIN b[101]
    DIRECTION OUTPUT ;
    USE SIGNAL ;
    PORT
      LAYER M5 ;
        RECT  18.864 0 18.888 0.192 ;
    END
  END b[101]
  PIN b[102]
    DIRECTION OUTPUT ;
    USE SIGNAL ;
    PORT
      LAYER M5 ;
        RECT  18.912 0 18.936 0.192 ;
    END
  END b[102]
  PIN b[103]
    DIRECTION OUTPUT ;
    USE SIGNAL ;
    PORT
      LAYER M5 ;
        RECT  18.96 0 18.984 0.192 ;
    END
  END b[103]
  PIN b[104]
    DIRECTION OUTPUT ;
    USE SIGNAL ;
    PORT
      LAYER M5 ;
        RECT  19.008 0 19.032 0.192 ;
    END
  END b[104]
  PIN b[105]
    DIRECTION OUTPUT ;
    USE SIGNAL ;
    PORT
      LAYER M5 ;
        RECT  19.056 0 19.08 0.192 ;
    END
  END b[105]
  PIN b[106]
    DIRECTION OUTPUT ;
    USE SIGNAL ;
    PORT
      LAYER M5 ;
        RECT  19.104 0 19.128 0.192 ;
    END
  END b[106]
  PIN b[107]
    DIRECTION OUTPUT ;
    USE SIGNAL ;
    PORT
      LAYER M5 ;
        RECT  19.152 0 19.176 0.192 ;
    END
  END b[107]
  PIN b[108]
    DIRECTION OUTPUT ;
    USE SIGNAL ;
    PORT
      LAYER M5 ;
        RECT  19.2 0 19.224 0.192 ;
    END
  END b[108]
  PIN b[109]
    DIRECTION OUTPUT ;
    USE SIGNAL ;
    PORT
      LAYER M5 ;
        RECT  19.248 0 19.272 0.192 ;
    END
  END b[109]
  PIN b[10]
    DIRECTION OUTPUT ;
    USE SIGNAL ;
    PORT
      LAYER M5 ;
        RECT  14.496 0 14.52 0.192 ;
    END
  END b[10]
  PIN b[110]
    DIRECTION OUTPUT ;
    USE SIGNAL ;
    PORT
      LAYER M5 ;
        RECT  19.296 0 19.32 0.192 ;
    END
  END b[110]
  PIN b[111]
    DIRECTION OUTPUT ;
    USE SIGNAL ;
    PORT
      LAYER M5 ;
        RECT  19.344 0 19.368 0.192 ;
    END
  END b[111]
  PIN b[112]
    DIRECTION OUTPUT ;
    USE SIGNAL ;
    PORT
      LAYER M5 ;
        RECT  19.392 0 19.416 0.192 ;
    END
  END b[112]
  PIN b[113]
    DIRECTION OUTPUT ;
    USE SIGNAL ;
    PORT
      LAYER M5 ;
        RECT  19.44 0 19.464 0.192 ;
    END
  END b[113]
  PIN b[114]
    DIRECTION OUTPUT ;
    USE SIGNAL ;
    PORT
      LAYER M5 ;
        RECT  19.488 0 19.512 0.192 ;
    END
  END b[114]
  PIN b[115]
    DIRECTION OUTPUT ;
    USE SIGNAL ;
    PORT
      LAYER M5 ;
        RECT  19.536 0 19.56 0.192 ;
    END
  END b[115]
  PIN b[116]
    DIRECTION OUTPUT ;
    USE SIGNAL ;
    PORT
      LAYER M5 ;
        RECT  19.584 0 19.608 0.192 ;
    END
  END b[116]
  PIN b[117]
    DIRECTION OUTPUT ;
    USE SIGNAL ;
    PORT
      LAYER M5 ;
        RECT  19.632 0 19.656 0.192 ;
    END
  END b[117]
  PIN b[118]
    DIRECTION OUTPUT ;
    USE SIGNAL ;
    PORT
      LAYER M5 ;
        RECT  19.68 0 19.704 0.192 ;
    END
  END b[118]
  PIN b[119]
    DIRECTION OUTPUT ;
    USE SIGNAL ;
    PORT
      LAYER M5 ;
        RECT  19.728 0 19.752 0.192 ;
    END
  END b[119]
  PIN b[11]
    DIRECTION OUTPUT ;
    USE SIGNAL ;
    PORT
      LAYER M5 ;
        RECT  14.544 0 14.568 0.192 ;
    END
  END b[11]
  PIN b[120]
    DIRECTION OUTPUT ;
    USE SIGNAL ;
    PORT
      LAYER M5 ;
        RECT  19.776 0 19.8 0.192 ;
    END
  END b[120]
  PIN b[121]
    DIRECTION OUTPUT ;
    USE SIGNAL ;
    PORT
      LAYER M5 ;
        RECT  19.824 0 19.848 0.192 ;
    END
  END b[121]
  PIN b[122]
    DIRECTION OUTPUT ;
    USE SIGNAL ;
    PORT
      LAYER M5 ;
        RECT  19.872 0 19.896 0.192 ;
    END
  END b[122]
  PIN b[123]
    DIRECTION OUTPUT ;
    USE SIGNAL ;
    PORT
      LAYER M5 ;
        RECT  19.92 0 19.944 0.192 ;
    END
  END b[123]
  PIN b[124]
    DIRECTION OUTPUT ;
    USE SIGNAL ;
    PORT
      LAYER M5 ;
        RECT  19.968 0 19.992 0.192 ;
    END
  END b[124]
  PIN b[125]
    DIRECTION OUTPUT ;
    USE SIGNAL ;
    PORT
      LAYER M5 ;
        RECT  20.016 0 20.04 0.192 ;
    END
  END b[125]
  PIN b[126]
    DIRECTION OUTPUT ;
    USE SIGNAL ;
    PORT
      LAYER M5 ;
        RECT  20.064 0 20.088 0.192 ;
    END
  END b[126]
  PIN b[127]
    DIRECTION OUTPUT ;
    USE SIGNAL ;
    PORT
      LAYER M5 ;
        RECT  20.112 0 20.136 0.192 ;
    END
  END b[127]
  PIN b[128]
    DIRECTION OUTPUT ;
    USE SIGNAL ;
    PORT
      LAYER M5 ;
        RECT  20.16 0 20.184 0.192 ;
    END
  END b[128]
  PIN b[129]
    DIRECTION OUTPUT ;
    USE SIGNAL ;
    PORT
      LAYER M5 ;
        RECT  20.208 0 20.232 0.192 ;
    END
  END b[129]
  PIN b[12]
    DIRECTION OUTPUT ;
    USE SIGNAL ;
    PORT
      LAYER M5 ;
        RECT  14.592 0 14.616 0.192 ;
    END
  END b[12]
  PIN b[130]
    DIRECTION OUTPUT ;
    USE SIGNAL ;
    PORT
      LAYER M5 ;
        RECT  20.256 0 20.28 0.192 ;
    END
  END b[130]
  PIN b[131]
    DIRECTION OUTPUT ;
    USE SIGNAL ;
    PORT
      LAYER M5 ;
        RECT  20.304 0 20.328 0.192 ;
    END
  END b[131]
  PIN b[132]
    DIRECTION OUTPUT ;
    USE SIGNAL ;
    PORT
      LAYER M5 ;
        RECT  20.352 0 20.376 0.192 ;
    END
  END b[132]
  PIN b[133]
    DIRECTION OUTPUT ;
    USE SIGNAL ;
    PORT
      LAYER M5 ;
        RECT  20.4 0 20.424 0.192 ;
    END
  END b[133]
  PIN b[134]
    DIRECTION OUTPUT ;
    USE SIGNAL ;
    PORT
      LAYER M5 ;
        RECT  20.448 0 20.472 0.192 ;
    END
  END b[134]
  PIN b[135]
    DIRECTION OUTPUT ;
    USE SIGNAL ;
    PORT
      LAYER M5 ;
        RECT  20.496 0 20.52 0.192 ;
    END
  END b[135]
  PIN b[136]
    DIRECTION OUTPUT ;
    USE SIGNAL ;
    PORT
      LAYER M5 ;
        RECT  20.544 0 20.568 0.192 ;
    END
  END b[136]
  PIN b[137]
    DIRECTION OUTPUT ;
    USE SIGNAL ;
    PORT
      LAYER M5 ;
        RECT  20.592 0 20.616 0.192 ;
    END
  END b[137]
  PIN b[138]
    DIRECTION OUTPUT ;
    USE SIGNAL ;
    PORT
      LAYER M5 ;
        RECT  20.64 0 20.664 0.192 ;
    END
  END b[138]
  PIN b[139]
    DIRECTION OUTPUT ;
    USE SIGNAL ;
    PORT
      LAYER M5 ;
        RECT  20.688 0 20.712 0.192 ;
    END
  END b[139]
  PIN b[13]
    DIRECTION OUTPUT ;
    USE SIGNAL ;
    PORT
      LAYER M5 ;
        RECT  14.64 0 14.664 0.192 ;
    END
  END b[13]
  PIN b[140]
    DIRECTION OUTPUT ;
    USE SIGNAL ;
    PORT
      LAYER M5 ;
        RECT  20.736 0 20.76 0.192 ;
    END
  END b[140]
  PIN b[141]
    DIRECTION OUTPUT ;
    USE SIGNAL ;
    PORT
      LAYER M5 ;
        RECT  20.784 0 20.808 0.192 ;
    END
  END b[141]
  PIN b[142]
    DIRECTION OUTPUT ;
    USE SIGNAL ;
    PORT
      LAYER M5 ;
        RECT  20.832 0 20.856 0.192 ;
    END
  END b[142]
  PIN b[143]
    DIRECTION OUTPUT ;
    USE SIGNAL ;
    PORT
      LAYER M5 ;
        RECT  20.88 0 20.904 0.192 ;
    END
  END b[143]
  PIN b[144]
    DIRECTION OUTPUT ;
    USE SIGNAL ;
    PORT
      LAYER M5 ;
        RECT  20.928 0 20.952 0.192 ;
    END
  END b[144]
  PIN b[145]
    DIRECTION OUTPUT ;
    USE SIGNAL ;
    PORT
      LAYER M5 ;
        RECT  20.976 0 21 0.192 ;
    END
  END b[145]
  PIN b[146]
    DIRECTION OUTPUT ;
    USE SIGNAL ;
    PORT
      LAYER M5 ;
        RECT  21.024 0 21.048 0.192 ;
    END
  END b[146]
  PIN b[147]
    DIRECTION OUTPUT ;
    USE SIGNAL ;
    PORT
      LAYER M5 ;
        RECT  21.072 0 21.096 0.192 ;
    END
  END b[147]
  PIN b[148]
    DIRECTION OUTPUT ;
    USE SIGNAL ;
    PORT
      LAYER M5 ;
        RECT  21.12 0 21.144 0.192 ;
    END
  END b[148]
  PIN b[149]
    DIRECTION OUTPUT ;
    USE SIGNAL ;
    PORT
      LAYER M5 ;
        RECT  21.168 0 21.192 0.192 ;
    END
  END b[149]
  PIN b[14]
    DIRECTION OUTPUT ;
    USE SIGNAL ;
    PORT
      LAYER M5 ;
        RECT  14.688 0 14.712 0.192 ;
    END
  END b[14]
  PIN b[150]
    DIRECTION OUTPUT ;
    USE SIGNAL ;
    PORT
      LAYER M5 ;
        RECT  21.216 0 21.24 0.192 ;
    END
  END b[150]
  PIN b[151]
    DIRECTION OUTPUT ;
    USE SIGNAL ;
    PORT
      LAYER M5 ;
        RECT  21.264 0 21.288 0.192 ;
    END
  END b[151]
  PIN b[152]
    DIRECTION OUTPUT ;
    USE SIGNAL ;
    PORT
      LAYER M5 ;
        RECT  21.312 0 21.336 0.192 ;
    END
  END b[152]
  PIN b[153]
    DIRECTION OUTPUT ;
    USE SIGNAL ;
    PORT
      LAYER M5 ;
        RECT  21.36 0 21.384 0.192 ;
    END
  END b[153]
  PIN b[154]
    DIRECTION OUTPUT ;
    USE SIGNAL ;
    PORT
      LAYER M5 ;
        RECT  21.408 0 21.432 0.192 ;
    END
  END b[154]
  PIN b[155]
    DIRECTION OUTPUT ;
    USE SIGNAL ;
    PORT
      LAYER M5 ;
        RECT  21.456 0 21.48 0.192 ;
    END
  END b[155]
  PIN b[156]
    DIRECTION OUTPUT ;
    USE SIGNAL ;
    PORT
      LAYER M5 ;
        RECT  21.504 0 21.528 0.192 ;
    END
  END b[156]
  PIN b[157]
    DIRECTION OUTPUT ;
    USE SIGNAL ;
    PORT
      LAYER M5 ;
        RECT  21.552 0 21.576 0.192 ;
    END
  END b[157]
  PIN b[158]
    DIRECTION OUTPUT ;
    USE SIGNAL ;
    PORT
      LAYER M5 ;
        RECT  21.6 0 21.624 0.192 ;
    END
  END b[158]
  PIN b[159]
    DIRECTION OUTPUT ;
    USE SIGNAL ;
    PORT
      LAYER M5 ;
        RECT  21.648 0 21.672 0.192 ;
    END
  END b[159]
  PIN b[15]
    DIRECTION OUTPUT ;
    USE SIGNAL ;
    PORT
      LAYER M5 ;
        RECT  14.736 0 14.76 0.192 ;
    END
  END b[15]
  PIN b[160]
    DIRECTION OUTPUT ;
    USE SIGNAL ;
    PORT
      LAYER M5 ;
        RECT  21.696 0 21.72 0.192 ;
    END
  END b[160]
  PIN b[161]
    DIRECTION OUTPUT ;
    USE SIGNAL ;
    PORT
      LAYER M5 ;
        RECT  21.744 0 21.768 0.192 ;
    END
  END b[161]
  PIN b[162]
    DIRECTION OUTPUT ;
    USE SIGNAL ;
    PORT
      LAYER M5 ;
        RECT  21.792 0 21.816 0.192 ;
    END
  END b[162]
  PIN b[163]
    DIRECTION OUTPUT ;
    USE SIGNAL ;
    PORT
      LAYER M5 ;
        RECT  21.84 0 21.864 0.192 ;
    END
  END b[163]
  PIN b[164]
    DIRECTION OUTPUT ;
    USE SIGNAL ;
    PORT
      LAYER M5 ;
        RECT  21.888 0 21.912 0.192 ;
    END
  END b[164]
  PIN b[165]
    DIRECTION OUTPUT ;
    USE SIGNAL ;
    PORT
      LAYER M5 ;
        RECT  21.936 0 21.96 0.192 ;
    END
  END b[165]
  PIN b[166]
    DIRECTION OUTPUT ;
    USE SIGNAL ;
    PORT
      LAYER M5 ;
        RECT  21.984 0 22.008 0.192 ;
    END
  END b[166]
  PIN b[167]
    DIRECTION OUTPUT ;
    USE SIGNAL ;
    PORT
      LAYER M5 ;
        RECT  22.032 0 22.056 0.192 ;
    END
  END b[167]
  PIN b[168]
    DIRECTION OUTPUT ;
    USE SIGNAL ;
    PORT
      LAYER M5 ;
        RECT  22.08 0 22.104 0.192 ;
    END
  END b[168]
  PIN b[169]
    DIRECTION OUTPUT ;
    USE SIGNAL ;
    PORT
      LAYER M5 ;
        RECT  22.128 0 22.152 0.192 ;
    END
  END b[169]
  PIN b[16]
    DIRECTION OUTPUT ;
    USE SIGNAL ;
    PORT
      LAYER M5 ;
        RECT  14.784 0 14.808 0.192 ;
    END
  END b[16]
  PIN b[170]
    DIRECTION OUTPUT ;
    USE SIGNAL ;
    PORT
      LAYER M5 ;
        RECT  22.176 0 22.2 0.192 ;
    END
  END b[170]
  PIN b[171]
    DIRECTION OUTPUT ;
    USE SIGNAL ;
    PORT
      LAYER M5 ;
        RECT  22.224 0 22.248 0.192 ;
    END
  END b[171]
  PIN b[172]
    DIRECTION OUTPUT ;
    USE SIGNAL ;
    PORT
      LAYER M5 ;
        RECT  22.272 0 22.296 0.192 ;
    END
  END b[172]
  PIN b[173]
    DIRECTION OUTPUT ;
    USE SIGNAL ;
    PORT
      LAYER M5 ;
        RECT  22.32 0 22.344 0.192 ;
    END
  END b[173]
  PIN b[174]
    DIRECTION OUTPUT ;
    USE SIGNAL ;
    PORT
      LAYER M5 ;
        RECT  22.368 0 22.392 0.192 ;
    END
  END b[174]
  PIN b[175]
    DIRECTION OUTPUT ;
    USE SIGNAL ;
    PORT
      LAYER M5 ;
        RECT  22.416 0 22.44 0.192 ;
    END
  END b[175]
  PIN b[176]
    DIRECTION OUTPUT ;
    USE SIGNAL ;
    PORT
      LAYER M5 ;
        RECT  22.464 0 22.488 0.192 ;
    END
  END b[176]
  PIN b[177]
    DIRECTION OUTPUT ;
    USE SIGNAL ;
    PORT
      LAYER M5 ;
        RECT  22.512 0 22.536 0.192 ;
    END
  END b[177]
  PIN b[178]
    DIRECTION OUTPUT ;
    USE SIGNAL ;
    PORT
      LAYER M5 ;
        RECT  22.56 0 22.584 0.192 ;
    END
  END b[178]
  PIN b[179]
    DIRECTION OUTPUT ;
    USE SIGNAL ;
    PORT
      LAYER M5 ;
        RECT  22.608 0 22.632 0.192 ;
    END
  END b[179]
  PIN b[17]
    DIRECTION OUTPUT ;
    USE SIGNAL ;
    PORT
      LAYER M5 ;
        RECT  14.832 0 14.856 0.192 ;
    END
  END b[17]
  PIN b[180]
    DIRECTION OUTPUT ;
    USE SIGNAL ;
    PORT
      LAYER M5 ;
        RECT  22.656 0 22.68 0.192 ;
    END
  END b[180]
  PIN b[181]
    DIRECTION OUTPUT ;
    USE SIGNAL ;
    PORT
      LAYER M5 ;
        RECT  22.704 0 22.728 0.192 ;
    END
  END b[181]
  PIN b[182]
    DIRECTION OUTPUT ;
    USE SIGNAL ;
    PORT
      LAYER M5 ;
        RECT  22.752 0 22.776 0.192 ;
    END
  END b[182]
  PIN b[183]
    DIRECTION OUTPUT ;
    USE SIGNAL ;
    PORT
      LAYER M5 ;
        RECT  22.8 0 22.824 0.192 ;
    END
  END b[183]
  PIN b[184]
    DIRECTION OUTPUT ;
    USE SIGNAL ;
    PORT
      LAYER M5 ;
        RECT  22.848 0 22.872 0.192 ;
    END
  END b[184]
  PIN b[185]
    DIRECTION OUTPUT ;
    USE SIGNAL ;
    PORT
      LAYER M5 ;
        RECT  22.896 0 22.92 0.192 ;
    END
  END b[185]
  PIN b[186]
    DIRECTION OUTPUT ;
    USE SIGNAL ;
    PORT
      LAYER M5 ;
        RECT  22.944 0 22.968 0.192 ;
    END
  END b[186]
  PIN b[187]
    DIRECTION OUTPUT ;
    USE SIGNAL ;
    PORT
      LAYER M5 ;
        RECT  22.992 0 23.016 0.192 ;
    END
  END b[187]
  PIN b[188]
    DIRECTION OUTPUT ;
    USE SIGNAL ;
    PORT
      LAYER M5 ;
        RECT  23.04 0 23.064 0.192 ;
    END
  END b[188]
  PIN b[189]
    DIRECTION OUTPUT ;
    USE SIGNAL ;
    PORT
      LAYER M5 ;
        RECT  23.088 0 23.112 0.192 ;
    END
  END b[189]
  PIN b[18]
    DIRECTION OUTPUT ;
    USE SIGNAL ;
    PORT
      LAYER M5 ;
        RECT  14.88 0 14.904 0.192 ;
    END
  END b[18]
  PIN b[190]
    DIRECTION OUTPUT ;
    USE SIGNAL ;
    PORT
      LAYER M5 ;
        RECT  23.136 0 23.16 0.192 ;
    END
  END b[190]
  PIN b[191]
    DIRECTION OUTPUT ;
    USE SIGNAL ;
    PORT
      LAYER M5 ;
        RECT  23.184 0 23.208 0.192 ;
    END
  END b[191]
  PIN b[192]
    DIRECTION OUTPUT ;
    USE SIGNAL ;
    PORT
      LAYER M5 ;
        RECT  23.232 0 23.256 0.192 ;
    END
  END b[192]
  PIN b[193]
    DIRECTION OUTPUT ;
    USE SIGNAL ;
    PORT
      LAYER M5 ;
        RECT  23.28 0 23.304 0.192 ;
    END
  END b[193]
  PIN b[194]
    DIRECTION OUTPUT ;
    USE SIGNAL ;
    PORT
      LAYER M5 ;
        RECT  23.328 0 23.352 0.192 ;
    END
  END b[194]
  PIN b[195]
    DIRECTION OUTPUT ;
    USE SIGNAL ;
    PORT
      LAYER M5 ;
        RECT  23.376 0 23.4 0.192 ;
    END
  END b[195]
  PIN b[196]
    DIRECTION OUTPUT ;
    USE SIGNAL ;
    PORT
      LAYER M5 ;
        RECT  23.424 0 23.448 0.192 ;
    END
  END b[196]
  PIN b[197]
    DIRECTION OUTPUT ;
    USE SIGNAL ;
    PORT
      LAYER M5 ;
        RECT  23.472 0 23.496 0.192 ;
    END
  END b[197]
  PIN b[198]
    DIRECTION OUTPUT ;
    USE SIGNAL ;
    PORT
      LAYER M5 ;
        RECT  23.52 0 23.544 0.192 ;
    END
  END b[198]
  PIN b[199]
    DIRECTION OUTPUT ;
    USE SIGNAL ;
    PORT
      LAYER M5 ;
        RECT  23.568 0 23.592 0.192 ;
    END
  END b[199]
  PIN b[19]
    DIRECTION OUTPUT ;
    USE SIGNAL ;
    PORT
      LAYER M5 ;
        RECT  14.928 0 14.952 0.192 ;
    END
  END b[19]
  PIN b[1]
    DIRECTION OUTPUT ;
    USE SIGNAL ;
    PORT
      LAYER M5 ;
        RECT  14.064 0 14.088 0.192 ;
    END
  END b[1]
  PIN b[200]
    DIRECTION OUTPUT ;
    USE SIGNAL ;
    PORT
      LAYER M5 ;
        RECT  23.616 0 23.64 0.192 ;
    END
  END b[200]
  PIN b[201]
    DIRECTION OUTPUT ;
    USE SIGNAL ;
    PORT
      LAYER M5 ;
        RECT  23.664 0 23.688 0.192 ;
    END
  END b[201]
  PIN b[202]
    DIRECTION OUTPUT ;
    USE SIGNAL ;
    PORT
      LAYER M5 ;
        RECT  23.712 0 23.736 0.192 ;
    END
  END b[202]
  PIN b[203]
    DIRECTION OUTPUT ;
    USE SIGNAL ;
    PORT
      LAYER M5 ;
        RECT  23.76 0 23.784 0.192 ;
    END
  END b[203]
  PIN b[204]
    DIRECTION OUTPUT ;
    USE SIGNAL ;
    PORT
      LAYER M5 ;
        RECT  23.808 0 23.832 0.192 ;
    END
  END b[204]
  PIN b[205]
    DIRECTION OUTPUT ;
    USE SIGNAL ;
    PORT
      LAYER M5 ;
        RECT  23.856 0 23.88 0.192 ;
    END
  END b[205]
  PIN b[206]
    DIRECTION OUTPUT ;
    USE SIGNAL ;
    PORT
      LAYER M5 ;
        RECT  23.904 0 23.928 0.192 ;
    END
  END b[206]
  PIN b[207]
    DIRECTION OUTPUT ;
    USE SIGNAL ;
    PORT
      LAYER M5 ;
        RECT  23.952 0 23.976 0.192 ;
    END
  END b[207]
  PIN b[208]
    DIRECTION OUTPUT ;
    USE SIGNAL ;
    PORT
      LAYER M5 ;
        RECT  24 0 24.024 0.192 ;
    END
  END b[208]
  PIN b[209]
    DIRECTION OUTPUT ;
    USE SIGNAL ;
    PORT
      LAYER M5 ;
        RECT  24.048 0 24.072 0.192 ;
    END
  END b[209]
  PIN b[20]
    DIRECTION OUTPUT ;
    USE SIGNAL ;
    PORT
      LAYER M5 ;
        RECT  14.976 0 15 0.192 ;
    END
  END b[20]
  PIN b[210]
    DIRECTION OUTPUT ;
    USE SIGNAL ;
    PORT
      LAYER M5 ;
        RECT  24.096 0 24.12 0.192 ;
    END
  END b[210]
  PIN b[211]
    DIRECTION OUTPUT ;
    USE SIGNAL ;
    PORT
      LAYER M5 ;
        RECT  24.144 0 24.168 0.192 ;
    END
  END b[211]
  PIN b[212]
    DIRECTION OUTPUT ;
    USE SIGNAL ;
    PORT
      LAYER M5 ;
        RECT  24.192 0 24.216 0.192 ;
    END
  END b[212]
  PIN b[213]
    DIRECTION OUTPUT ;
    USE SIGNAL ;
    PORT
      LAYER M5 ;
        RECT  24.24 0 24.264 0.192 ;
    END
  END b[213]
  PIN b[214]
    DIRECTION OUTPUT ;
    USE SIGNAL ;
    PORT
      LAYER M5 ;
        RECT  24.288 0 24.312 0.192 ;
    END
  END b[214]
  PIN b[215]
    DIRECTION OUTPUT ;
    USE SIGNAL ;
    PORT
      LAYER M5 ;
        RECT  24.336 0 24.36 0.192 ;
    END
  END b[215]
  PIN b[216]
    DIRECTION OUTPUT ;
    USE SIGNAL ;
    PORT
      LAYER M5 ;
        RECT  24.384 0 24.408 0.192 ;
    END
  END b[216]
  PIN b[217]
    DIRECTION OUTPUT ;
    USE SIGNAL ;
    PORT
      LAYER M5 ;
        RECT  24.432 0 24.456 0.192 ;
    END
  END b[217]
  PIN b[218]
    DIRECTION OUTPUT ;
    USE SIGNAL ;
    PORT
      LAYER M5 ;
        RECT  24.48 0 24.504 0.192 ;
    END
  END b[218]
  PIN b[219]
    DIRECTION OUTPUT ;
    USE SIGNAL ;
    PORT
      LAYER M5 ;
        RECT  24.528 0 24.552 0.192 ;
    END
  END b[219]
  PIN b[21]
    DIRECTION OUTPUT ;
    USE SIGNAL ;
    PORT
      LAYER M5 ;
        RECT  15.024 0 15.048 0.192 ;
    END
  END b[21]
  PIN b[220]
    DIRECTION OUTPUT ;
    USE SIGNAL ;
    PORT
      LAYER M5 ;
        RECT  24.576 0 24.6 0.192 ;
    END
  END b[220]
  PIN b[221]
    DIRECTION OUTPUT ;
    USE SIGNAL ;
    PORT
      LAYER M5 ;
        RECT  24.624 0 24.648 0.192 ;
    END
  END b[221]
  PIN b[222]
    DIRECTION OUTPUT ;
    USE SIGNAL ;
    PORT
      LAYER M5 ;
        RECT  24.672 0 24.696 0.192 ;
    END
  END b[222]
  PIN b[223]
    DIRECTION OUTPUT ;
    USE SIGNAL ;
    PORT
      LAYER M5 ;
        RECT  24.72 0 24.744 0.192 ;
    END
  END b[223]
  PIN b[224]
    DIRECTION OUTPUT ;
    USE SIGNAL ;
    PORT
      LAYER M5 ;
        RECT  24.768 0 24.792 0.192 ;
    END
  END b[224]
  PIN b[225]
    DIRECTION OUTPUT ;
    USE SIGNAL ;
    PORT
      LAYER M5 ;
        RECT  24.816 0 24.84 0.192 ;
    END
  END b[225]
  PIN b[226]
    DIRECTION OUTPUT ;
    USE SIGNAL ;
    PORT
      LAYER M5 ;
        RECT  24.864 0 24.888 0.192 ;
    END
  END b[226]
  PIN b[227]
    DIRECTION OUTPUT ;
    USE SIGNAL ;
    PORT
      LAYER M5 ;
        RECT  24.912 0 24.936 0.192 ;
    END
  END b[227]
  PIN b[228]
    DIRECTION OUTPUT ;
    USE SIGNAL ;
    PORT
      LAYER M5 ;
        RECT  24.96 0 24.984 0.192 ;
    END
  END b[228]
  PIN b[229]
    DIRECTION OUTPUT ;
    USE SIGNAL ;
    PORT
      LAYER M5 ;
        RECT  25.008 0 25.032 0.192 ;
    END
  END b[229]
  PIN b[22]
    DIRECTION OUTPUT ;
    USE SIGNAL ;
    PORT
      LAYER M5 ;
        RECT  15.072 0 15.096 0.192 ;
    END
  END b[22]
  PIN b[230]
    DIRECTION OUTPUT ;
    USE SIGNAL ;
    PORT
      LAYER M5 ;
        RECT  25.056 0 25.08 0.192 ;
    END
  END b[230]
  PIN b[231]
    DIRECTION OUTPUT ;
    USE SIGNAL ;
    PORT
      LAYER M5 ;
        RECT  25.104 0 25.128 0.192 ;
    END
  END b[231]
  PIN b[232]
    DIRECTION OUTPUT ;
    USE SIGNAL ;
    PORT
      LAYER M5 ;
        RECT  25.152 0 25.176 0.192 ;
    END
  END b[232]
  PIN b[233]
    DIRECTION OUTPUT ;
    USE SIGNAL ;
    PORT
      LAYER M5 ;
        RECT  25.2 0 25.224 0.192 ;
    END
  END b[233]
  PIN b[234]
    DIRECTION OUTPUT ;
    USE SIGNAL ;
    PORT
      LAYER M5 ;
        RECT  25.248 0 25.272 0.192 ;
    END
  END b[234]
  PIN b[235]
    DIRECTION OUTPUT ;
    USE SIGNAL ;
    PORT
      LAYER M5 ;
        RECT  25.296 0 25.32 0.192 ;
    END
  END b[235]
  PIN b[236]
    DIRECTION OUTPUT ;
    USE SIGNAL ;
    PORT
      LAYER M5 ;
        RECT  25.344 0 25.368 0.192 ;
    END
  END b[236]
  PIN b[237]
    DIRECTION OUTPUT ;
    USE SIGNAL ;
    PORT
      LAYER M5 ;
        RECT  25.392 0 25.416 0.192 ;
    END
  END b[237]
  PIN b[238]
    DIRECTION OUTPUT ;
    USE SIGNAL ;
    PORT
      LAYER M5 ;
        RECT  25.44 0 25.464 0.192 ;
    END
  END b[238]
  PIN b[239]
    DIRECTION OUTPUT ;
    USE SIGNAL ;
    PORT
      LAYER M5 ;
        RECT  25.488 0 25.512 0.192 ;
    END
  END b[239]
  PIN b[23]
    DIRECTION OUTPUT ;
    USE SIGNAL ;
    PORT
      LAYER M5 ;
        RECT  15.12 0 15.144 0.192 ;
    END
  END b[23]
  PIN b[240]
    DIRECTION OUTPUT ;
    USE SIGNAL ;
    PORT
      LAYER M5 ;
        RECT  25.536 0 25.56 0.192 ;
    END
  END b[240]
  PIN b[241]
    DIRECTION OUTPUT ;
    USE SIGNAL ;
    PORT
      LAYER M5 ;
        RECT  25.584 0 25.608 0.192 ;
    END
  END b[241]
  PIN b[242]
    DIRECTION OUTPUT ;
    USE SIGNAL ;
    PORT
      LAYER M5 ;
        RECT  25.632 0 25.656 0.192 ;
    END
  END b[242]
  PIN b[243]
    DIRECTION OUTPUT ;
    USE SIGNAL ;
    PORT
      LAYER M5 ;
        RECT  25.68 0 25.704 0.192 ;
    END
  END b[243]
  PIN b[244]
    DIRECTION OUTPUT ;
    USE SIGNAL ;
    PORT
      LAYER M5 ;
        RECT  25.728 0 25.752 0.192 ;
    END
  END b[244]
  PIN b[245]
    DIRECTION OUTPUT ;
    USE SIGNAL ;
    PORT
      LAYER M5 ;
        RECT  25.776 0 25.8 0.192 ;
    END
  END b[245]
  PIN b[246]
    DIRECTION OUTPUT ;
    USE SIGNAL ;
    PORT
      LAYER M5 ;
        RECT  25.824 0 25.848 0.192 ;
    END
  END b[246]
  PIN b[247]
    DIRECTION OUTPUT ;
    USE SIGNAL ;
    PORT
      LAYER M5 ;
        RECT  25.872 0 25.896 0.192 ;
    END
  END b[247]
  PIN b[248]
    DIRECTION OUTPUT ;
    USE SIGNAL ;
    PORT
      LAYER M5 ;
        RECT  25.92 0 25.944 0.192 ;
    END
  END b[248]
  PIN b[249]
    DIRECTION OUTPUT ;
    USE SIGNAL ;
    PORT
      LAYER M5 ;
        RECT  25.968 0 25.992 0.192 ;
    END
  END b[249]
  PIN b[24]
    DIRECTION OUTPUT ;
    USE SIGNAL ;
    PORT
      LAYER M5 ;
        RECT  15.168 0 15.192 0.192 ;
    END
  END b[24]
  PIN b[250]
    DIRECTION OUTPUT ;
    USE SIGNAL ;
    PORT
      LAYER M5 ;
        RECT  26.016 0 26.04 0.192 ;
    END
  END b[250]
  PIN b[251]
    DIRECTION OUTPUT ;
    USE SIGNAL ;
    PORT
      LAYER M5 ;
        RECT  26.064 0 26.088 0.192 ;
    END
  END b[251]
  PIN b[252]
    DIRECTION OUTPUT ;
    USE SIGNAL ;
    PORT
      LAYER M5 ;
        RECT  26.112 0 26.136 0.192 ;
    END
  END b[252]
  PIN b[253]
    DIRECTION OUTPUT ;
    USE SIGNAL ;
    PORT
      LAYER M5 ;
        RECT  26.16 0 26.184 0.192 ;
    END
  END b[253]
  PIN b[254]
    DIRECTION OUTPUT ;
    USE SIGNAL ;
    PORT
      LAYER M5 ;
        RECT  26.208 0 26.232 0.192 ;
    END
  END b[254]
  PIN b[255]
    DIRECTION OUTPUT ;
    USE SIGNAL ;
    PORT
      LAYER M5 ;
        RECT  26.256 0 26.28 0.192 ;
    END
  END b[255]
  PIN b[256]
    DIRECTION INPUT ;
    USE SIGNAL ;
    PORT
      LAYER M5 ;
        RECT  26.304 0 26.328 0.192 ;
    END
  END b[256]
  PIN b[257]
    DIRECTION INPUT ;
    USE SIGNAL ;
    PORT
      LAYER M5 ;
        RECT  26.352 0 26.376 0.192 ;
    END
  END b[257]
  PIN b[258]
    DIRECTION INPUT ;
    USE SIGNAL ;
    PORT
      LAYER M5 ;
        RECT  26.4 0 26.424 0.192 ;
    END
  END b[258]
  PIN b[259]
    DIRECTION INPUT ;
    USE SIGNAL ;
    PORT
      LAYER M5 ;
        RECT  26.448 0 26.472 0.192 ;
    END
  END b[259]
  PIN b[25]
    DIRECTION OUTPUT ;
    USE SIGNAL ;
    PORT
      LAYER M5 ;
        RECT  15.216 0 15.24 0.192 ;
    END
  END b[25]
  PIN b[260]
    DIRECTION INPUT ;
    USE SIGNAL ;
    PORT
      LAYER M5 ;
        RECT  26.496 0 26.52 0.192 ;
    END
  END b[260]
  PIN b[261]
    DIRECTION INPUT ;
    USE SIGNAL ;
    PORT
      LAYER M5 ;
        RECT  26.544 0 26.568 0.192 ;
    END
  END b[261]
  PIN b[262]
    DIRECTION INPUT ;
    USE SIGNAL ;
    PORT
      LAYER M5 ;
        RECT  26.592 0 26.616 0.192 ;
    END
  END b[262]
  PIN b[263]
    DIRECTION INPUT ;
    USE SIGNAL ;
    PORT
      LAYER M5 ;
        RECT  26.64 0 26.664 0.192 ;
    END
  END b[263]
  PIN b[264]
    DIRECTION INPUT ;
    USE SIGNAL ;
    PORT
      LAYER M5 ;
        RECT  26.688 0 26.712 0.192 ;
    END
  END b[264]
  PIN b[265]
    DIRECTION INPUT ;
    USE SIGNAL ;
    PORT
      LAYER M5 ;
        RECT  26.736 0 26.76 0.192 ;
    END
  END b[265]
  PIN b[266]
    DIRECTION INPUT ;
    USE SIGNAL ;
    PORT
      LAYER M5 ;
        RECT  26.784 0 26.808 0.192 ;
    END
  END b[266]
  PIN b[267]
    DIRECTION INPUT ;
    USE SIGNAL ;
    PORT
      LAYER M5 ;
        RECT  26.832 0 26.856 0.192 ;
    END
  END b[267]
  PIN b[268]
    DIRECTION INPUT ;
    USE SIGNAL ;
    PORT
      LAYER M5 ;
        RECT  26.88 0 26.904 0.192 ;
    END
  END b[268]
  PIN b[269]
    DIRECTION INPUT ;
    USE SIGNAL ;
    PORT
      LAYER M5 ;
        RECT  26.928 0 26.952 0.192 ;
    END
  END b[269]
  PIN b[26]
    DIRECTION OUTPUT ;
    USE SIGNAL ;
    PORT
      LAYER M5 ;
        RECT  15.264 0 15.288 0.192 ;
    END
  END b[26]
  PIN b[270]
    DIRECTION INPUT ;
    USE SIGNAL ;
    PORT
      LAYER M5 ;
        RECT  26.976 0 27 0.192 ;
    END
  END b[270]
  PIN b[271]
    DIRECTION INPUT ;
    USE SIGNAL ;
    PORT
      LAYER M5 ;
        RECT  27.024 0 27.048 0.192 ;
    END
  END b[271]
  PIN b[272]
    DIRECTION INPUT ;
    USE SIGNAL ;
    PORT
      LAYER M5 ;
        RECT  27.072 0 27.096 0.192 ;
    END
  END b[272]
  PIN b[273]
    DIRECTION INPUT ;
    USE SIGNAL ;
    PORT
      LAYER M5 ;
        RECT  27.12 0 27.144 0.192 ;
    END
  END b[273]
  PIN b[274]
    DIRECTION INPUT ;
    USE SIGNAL ;
    PORT
      LAYER M5 ;
        RECT  27.168 0 27.192 0.192 ;
    END
  END b[274]
  PIN b[275]
    DIRECTION INPUT ;
    USE SIGNAL ;
    PORT
      LAYER M5 ;
        RECT  27.216 0 27.24 0.192 ;
    END
  END b[275]
  PIN b[276]
    DIRECTION INPUT ;
    USE SIGNAL ;
    PORT
      LAYER M5 ;
        RECT  27.264 0 27.288 0.192 ;
    END
  END b[276]
  PIN b[277]
    DIRECTION INPUT ;
    USE SIGNAL ;
    PORT
      LAYER M5 ;
        RECT  27.312 0 27.336 0.192 ;
    END
  END b[277]
  PIN b[278]
    DIRECTION INPUT ;
    USE SIGNAL ;
    PORT
      LAYER M5 ;
        RECT  27.36 0 27.384 0.192 ;
    END
  END b[278]
  PIN b[279]
    DIRECTION INPUT ;
    USE SIGNAL ;
    PORT
      LAYER M5 ;
        RECT  27.408 0 27.432 0.192 ;
    END
  END b[279]
  PIN b[27]
    DIRECTION OUTPUT ;
    USE SIGNAL ;
    PORT
      LAYER M5 ;
        RECT  15.312 0 15.336 0.192 ;
    END
  END b[27]
  PIN b[280]
    DIRECTION INPUT ;
    USE SIGNAL ;
    PORT
      LAYER M5 ;
        RECT  27.456 0 27.48 0.192 ;
    END
  END b[280]
  PIN b[281]
    DIRECTION INPUT ;
    USE SIGNAL ;
    PORT
      LAYER M5 ;
        RECT  27.504 0 27.528 0.192 ;
    END
  END b[281]
  PIN b[282]
    DIRECTION INPUT ;
    USE SIGNAL ;
    PORT
      LAYER M5 ;
        RECT  27.552 0 27.576 0.192 ;
    END
  END b[282]
  PIN b[283]
    DIRECTION INPUT ;
    USE SIGNAL ;
    PORT
      LAYER M5 ;
        RECT  27.6 0 27.624 0.192 ;
    END
  END b[283]
  PIN b[284]
    DIRECTION INPUT ;
    USE SIGNAL ;
    PORT
      LAYER M5 ;
        RECT  27.648 0 27.672 0.192 ;
    END
  END b[284]
  PIN b[285]
    DIRECTION INPUT ;
    USE SIGNAL ;
    PORT
      LAYER M5 ;
        RECT  27.696 0 27.72 0.192 ;
    END
  END b[285]
  PIN b[286]
    DIRECTION INPUT ;
    USE SIGNAL ;
    PORT
      LAYER M5 ;
        RECT  27.744 0 27.768 0.192 ;
    END
  END b[286]
  PIN b[287]
    DIRECTION INPUT ;
    USE SIGNAL ;
    PORT
      LAYER M5 ;
        RECT  27.792 0 27.816 0.192 ;
    END
  END b[287]
  PIN b[288]
    DIRECTION INPUT ;
    USE SIGNAL ;
    PORT
      LAYER M5 ;
        RECT  27.84 0 27.864 0.192 ;
    END
  END b[288]
  PIN b[289]
    DIRECTION INPUT ;
    USE SIGNAL ;
    PORT
      LAYER M5 ;
        RECT  27.888 0 27.912 0.192 ;
    END
  END b[289]
  PIN b[28]
    DIRECTION OUTPUT ;
    USE SIGNAL ;
    PORT
      LAYER M5 ;
        RECT  15.36 0 15.384 0.192 ;
    END
  END b[28]
  PIN b[290]
    DIRECTION INPUT ;
    USE SIGNAL ;
    PORT
      LAYER M5 ;
        RECT  27.936 0 27.96 0.192 ;
    END
  END b[290]
  PIN b[291]
    DIRECTION INPUT ;
    USE SIGNAL ;
    PORT
      LAYER M5 ;
        RECT  27.984 0 28.008 0.192 ;
    END
  END b[291]
  PIN b[292]
    DIRECTION INPUT ;
    USE SIGNAL ;
    PORT
      LAYER M5 ;
        RECT  28.032 0 28.056 0.192 ;
    END
  END b[292]
  PIN b[293]
    DIRECTION INPUT ;
    USE SIGNAL ;
    PORT
      LAYER M5 ;
        RECT  28.08 0 28.104 0.192 ;
    END
  END b[293]
  PIN b[294]
    DIRECTION INPUT ;
    USE SIGNAL ;
    PORT
      LAYER M5 ;
        RECT  28.128 0 28.152 0.192 ;
    END
  END b[294]
  PIN b[295]
    DIRECTION INPUT ;
    USE SIGNAL ;
    PORT
      LAYER M5 ;
        RECT  28.176 0 28.2 0.192 ;
    END
  END b[295]
  PIN b[296]
    DIRECTION INPUT ;
    USE SIGNAL ;
    PORT
      LAYER M5 ;
        RECT  28.224 0 28.248 0.192 ;
    END
  END b[296]
  PIN b[297]
    DIRECTION INPUT ;
    USE SIGNAL ;
    PORT
      LAYER M5 ;
        RECT  28.272 0 28.296 0.192 ;
    END
  END b[297]
  PIN b[298]
    DIRECTION INPUT ;
    USE SIGNAL ;
    PORT
      LAYER M5 ;
        RECT  28.32 0 28.344 0.192 ;
    END
  END b[298]
  PIN b[299]
    DIRECTION INPUT ;
    USE SIGNAL ;
    PORT
      LAYER M5 ;
        RECT  28.368 0 28.392 0.192 ;
    END
  END b[299]
  PIN b[29]
    DIRECTION OUTPUT ;
    USE SIGNAL ;
    PORT
      LAYER M5 ;
        RECT  15.408 0 15.432 0.192 ;
    END
  END b[29]
  PIN b[2]
    DIRECTION OUTPUT ;
    USE SIGNAL ;
    PORT
      LAYER M5 ;
        RECT  14.112 0 14.136 0.192 ;
    END
  END b[2]
  PIN b[300]
    DIRECTION INPUT ;
    USE SIGNAL ;
    PORT
      LAYER M5 ;
        RECT  28.416 0 28.44 0.192 ;
    END
  END b[300]
  PIN b[301]
    DIRECTION INPUT ;
    USE SIGNAL ;
    PORT
      LAYER M5 ;
        RECT  28.464 0 28.488 0.192 ;
    END
  END b[301]
  PIN b[302]
    DIRECTION INPUT ;
    USE SIGNAL ;
    PORT
      LAYER M5 ;
        RECT  28.512 0 28.536 0.192 ;
    END
  END b[302]
  PIN b[303]
    DIRECTION INPUT ;
    USE SIGNAL ;
    PORT
      LAYER M5 ;
        RECT  28.56 0 28.584 0.192 ;
    END
  END b[303]
  PIN b[304]
    DIRECTION INPUT ;
    USE SIGNAL ;
    PORT
      LAYER M5 ;
        RECT  28.608 0 28.632 0.192 ;
    END
  END b[304]
  PIN b[305]
    DIRECTION INPUT ;
    USE SIGNAL ;
    PORT
      LAYER M5 ;
        RECT  28.656 0 28.68 0.192 ;
    END
  END b[305]
  PIN b[306]
    DIRECTION INPUT ;
    USE SIGNAL ;
    PORT
      LAYER M5 ;
        RECT  28.704 0 28.728 0.192 ;
    END
  END b[306]
  PIN b[307]
    DIRECTION INPUT ;
    USE SIGNAL ;
    PORT
      LAYER M5 ;
        RECT  28.752 0 28.776 0.192 ;
    END
  END b[307]
  PIN b[308]
    DIRECTION INPUT ;
    USE SIGNAL ;
    PORT
      LAYER M5 ;
        RECT  28.8 0 28.824 0.192 ;
    END
  END b[308]
  PIN b[309]
    DIRECTION INPUT ;
    USE SIGNAL ;
    PORT
      LAYER M5 ;
        RECT  28.848 0 28.872 0.192 ;
    END
  END b[309]
  PIN b[30]
    DIRECTION OUTPUT ;
    USE SIGNAL ;
    PORT
      LAYER M5 ;
        RECT  15.456 0 15.48 0.192 ;
    END
  END b[30]
  PIN b[310]
    DIRECTION INPUT ;
    USE SIGNAL ;
    PORT
      LAYER M5 ;
        RECT  28.896 0 28.92 0.192 ;
    END
  END b[310]
  PIN b[311]
    DIRECTION INPUT ;
    USE SIGNAL ;
    PORT
      LAYER M5 ;
        RECT  28.944 0 28.968 0.192 ;
    END
  END b[311]
  PIN b[312]
    DIRECTION INPUT ;
    USE SIGNAL ;
    PORT
      LAYER M5 ;
        RECT  28.992 0 29.016 0.192 ;
    END
  END b[312]
  PIN b[313]
    DIRECTION INPUT ;
    USE SIGNAL ;
    PORT
      LAYER M5 ;
        RECT  29.04 0 29.064 0.192 ;
    END
  END b[313]
  PIN b[314]
    DIRECTION INPUT ;
    USE SIGNAL ;
    PORT
      LAYER M5 ;
        RECT  29.088 0 29.112 0.192 ;
    END
  END b[314]
  PIN b[315]
    DIRECTION INPUT ;
    USE SIGNAL ;
    PORT
      LAYER M5 ;
        RECT  29.136 0 29.16 0.192 ;
    END
  END b[315]
  PIN b[316]
    DIRECTION INPUT ;
    USE SIGNAL ;
    PORT
      LAYER M5 ;
        RECT  29.184 0 29.208 0.192 ;
    END
  END b[316]
  PIN b[317]
    DIRECTION INPUT ;
    USE SIGNAL ;
    PORT
      LAYER M5 ;
        RECT  29.232 0 29.256 0.192 ;
    END
  END b[317]
  PIN b[318]
    DIRECTION INPUT ;
    USE SIGNAL ;
    PORT
      LAYER M5 ;
        RECT  29.28 0 29.304 0.192 ;
    END
  END b[318]
  PIN b[319]
    DIRECTION INPUT ;
    USE SIGNAL ;
    PORT
      LAYER M5 ;
        RECT  29.328 0 29.352 0.192 ;
    END
  END b[319]
  PIN b[31]
    DIRECTION OUTPUT ;
    USE SIGNAL ;
    PORT
      LAYER M5 ;
        RECT  15.504 0 15.528 0.192 ;
    END
  END b[31]
  PIN b[320]
    DIRECTION INPUT ;
    USE SIGNAL ;
    PORT
      LAYER M5 ;
        RECT  29.376 0 29.4 0.192 ;
    END
  END b[320]
  PIN b[321]
    DIRECTION INPUT ;
    USE SIGNAL ;
    PORT
      LAYER M5 ;
        RECT  29.424 0 29.448 0.192 ;
    END
  END b[321]
  PIN b[322]
    DIRECTION INPUT ;
    USE SIGNAL ;
    PORT
      LAYER M5 ;
        RECT  29.472 0 29.496 0.192 ;
    END
  END b[322]
  PIN b[323]
    DIRECTION INPUT ;
    USE SIGNAL ;
    PORT
      LAYER M5 ;
        RECT  29.52 0 29.544 0.192 ;
    END
  END b[323]
  PIN b[324]
    DIRECTION INPUT ;
    USE SIGNAL ;
    PORT
      LAYER M5 ;
        RECT  29.568 0 29.592 0.192 ;
    END
  END b[324]
  PIN b[325]
    DIRECTION INPUT ;
    USE SIGNAL ;
    PORT
      LAYER M5 ;
        RECT  29.616 0 29.64 0.192 ;
    END
  END b[325]
  PIN b[326]
    DIRECTION INPUT ;
    USE SIGNAL ;
    PORT
      LAYER M5 ;
        RECT  29.664 0 29.688 0.192 ;
    END
  END b[326]
  PIN b[327]
    DIRECTION INPUT ;
    USE SIGNAL ;
    PORT
      LAYER M5 ;
        RECT  29.712 0 29.736 0.192 ;
    END
  END b[327]
  PIN b[328]
    DIRECTION INPUT ;
    USE SIGNAL ;
    PORT
      LAYER M5 ;
        RECT  29.76 0 29.784 0.192 ;
    END
  END b[328]
  PIN b[329]
    DIRECTION INPUT ;
    USE SIGNAL ;
    PORT
      LAYER M5 ;
        RECT  29.808 0 29.832 0.192 ;
    END
  END b[329]
  PIN b[32]
    DIRECTION OUTPUT ;
    USE SIGNAL ;
    PORT
      LAYER M5 ;
        RECT  15.552 0 15.576 0.192 ;
    END
  END b[32]
  PIN b[330]
    DIRECTION INPUT ;
    USE SIGNAL ;
    PORT
      LAYER M5 ;
        RECT  29.856 0 29.88 0.192 ;
    END
  END b[330]
  PIN b[331]
    DIRECTION INPUT ;
    USE SIGNAL ;
    PORT
      LAYER M5 ;
        RECT  29.904 0 29.928 0.192 ;
    END
  END b[331]
  PIN b[332]
    DIRECTION INPUT ;
    USE SIGNAL ;
    PORT
      LAYER M5 ;
        RECT  29.952 0 29.976 0.192 ;
    END
  END b[332]
  PIN b[333]
    DIRECTION INPUT ;
    USE SIGNAL ;
    PORT
      LAYER M5 ;
        RECT  30 0 30.024 0.192 ;
    END
  END b[333]
  PIN b[334]
    DIRECTION INPUT ;
    USE SIGNAL ;
    PORT
      LAYER M5 ;
        RECT  30.048 0 30.072 0.192 ;
    END
  END b[334]
  PIN b[335]
    DIRECTION INPUT ;
    USE SIGNAL ;
    PORT
      LAYER M5 ;
        RECT  30.096 0 30.12 0.192 ;
    END
  END b[335]
  PIN b[336]
    DIRECTION INPUT ;
    USE SIGNAL ;
    PORT
      LAYER M5 ;
        RECT  30.144 0 30.168 0.192 ;
    END
  END b[336]
  PIN b[337]
    DIRECTION INPUT ;
    USE SIGNAL ;
    PORT
      LAYER M5 ;
        RECT  30.192 0 30.216 0.192 ;
    END
  END b[337]
  PIN b[338]
    DIRECTION INPUT ;
    USE SIGNAL ;
    PORT
      LAYER M5 ;
        RECT  30.24 0 30.264 0.192 ;
    END
  END b[338]
  PIN b[339]
    DIRECTION INPUT ;
    USE SIGNAL ;
    PORT
      LAYER M5 ;
        RECT  30.288 0 30.312 0.192 ;
    END
  END b[339]
  PIN b[33]
    DIRECTION OUTPUT ;
    USE SIGNAL ;
    PORT
      LAYER M5 ;
        RECT  15.6 0 15.624 0.192 ;
    END
  END b[33]
  PIN b[340]
    DIRECTION INPUT ;
    USE SIGNAL ;
    PORT
      LAYER M5 ;
        RECT  30.336 0 30.36 0.192 ;
    END
  END b[340]
  PIN b[341]
    DIRECTION INPUT ;
    USE SIGNAL ;
    PORT
      LAYER M5 ;
        RECT  30.384 0 30.408 0.192 ;
    END
  END b[341]
  PIN b[342]
    DIRECTION INPUT ;
    USE SIGNAL ;
    PORT
      LAYER M5 ;
        RECT  30.432 0 30.456 0.192 ;
    END
  END b[342]
  PIN b[343]
    DIRECTION INPUT ;
    USE SIGNAL ;
    PORT
      LAYER M5 ;
        RECT  30.48 0 30.504 0.192 ;
    END
  END b[343]
  PIN b[344]
    DIRECTION INPUT ;
    USE SIGNAL ;
    PORT
      LAYER M5 ;
        RECT  30.528 0 30.552 0.192 ;
    END
  END b[344]
  PIN b[345]
    DIRECTION INPUT ;
    USE SIGNAL ;
    PORT
      LAYER M5 ;
        RECT  30.576 0 30.6 0.192 ;
    END
  END b[345]
  PIN b[346]
    DIRECTION INPUT ;
    USE SIGNAL ;
    PORT
      LAYER M5 ;
        RECT  30.624 0 30.648 0.192 ;
    END
  END b[346]
  PIN b[347]
    DIRECTION INPUT ;
    USE SIGNAL ;
    PORT
      LAYER M5 ;
        RECT  30.672 0 30.696 0.192 ;
    END
  END b[347]
  PIN b[348]
    DIRECTION INPUT ;
    USE SIGNAL ;
    PORT
      LAYER M5 ;
        RECT  30.72 0 30.744 0.192 ;
    END
  END b[348]
  PIN b[349]
    DIRECTION INPUT ;
    USE SIGNAL ;
    PORT
      LAYER M5 ;
        RECT  30.768 0 30.792 0.192 ;
    END
  END b[349]
  PIN b[34]
    DIRECTION OUTPUT ;
    USE SIGNAL ;
    PORT
      LAYER M5 ;
        RECT  15.648 0 15.672 0.192 ;
    END
  END b[34]
  PIN b[350]
    DIRECTION INPUT ;
    USE SIGNAL ;
    PORT
      LAYER M5 ;
        RECT  30.816 0 30.84 0.192 ;
    END
  END b[350]
  PIN b[351]
    DIRECTION INPUT ;
    USE SIGNAL ;
    PORT
      LAYER M5 ;
        RECT  30.864 0 30.888 0.192 ;
    END
  END b[351]
  PIN b[352]
    DIRECTION INPUT ;
    USE SIGNAL ;
    PORT
      LAYER M5 ;
        RECT  30.912 0 30.936 0.192 ;
    END
  END b[352]
  PIN b[353]
    DIRECTION INPUT ;
    USE SIGNAL ;
    PORT
      LAYER M5 ;
        RECT  30.96 0 30.984 0.192 ;
    END
  END b[353]
  PIN b[354]
    DIRECTION INPUT ;
    USE SIGNAL ;
    PORT
      LAYER M5 ;
        RECT  31.008 0 31.032 0.192 ;
    END
  END b[354]
  PIN b[355]
    DIRECTION INPUT ;
    USE SIGNAL ;
    PORT
      LAYER M5 ;
        RECT  31.056 0 31.08 0.192 ;
    END
  END b[355]
  PIN b[356]
    DIRECTION INPUT ;
    USE SIGNAL ;
    PORT
      LAYER M5 ;
        RECT  31.104 0 31.128 0.192 ;
    END
  END b[356]
  PIN b[357]
    DIRECTION INPUT ;
    USE SIGNAL ;
    PORT
      LAYER M5 ;
        RECT  31.152 0 31.176 0.192 ;
    END
  END b[357]
  PIN b[358]
    DIRECTION INPUT ;
    USE SIGNAL ;
    PORT
      LAYER M5 ;
        RECT  31.2 0 31.224 0.192 ;
    END
  END b[358]
  PIN b[359]
    DIRECTION INPUT ;
    USE SIGNAL ;
    PORT
      LAYER M5 ;
        RECT  31.248 0 31.272 0.192 ;
    END
  END b[359]
  PIN b[35]
    DIRECTION OUTPUT ;
    USE SIGNAL ;
    PORT
      LAYER M5 ;
        RECT  15.696 0 15.72 0.192 ;
    END
  END b[35]
  PIN b[360]
    DIRECTION INPUT ;
    USE SIGNAL ;
    PORT
      LAYER M5 ;
        RECT  31.296 0 31.32 0.192 ;
    END
  END b[360]
  PIN b[361]
    DIRECTION INPUT ;
    USE SIGNAL ;
    PORT
      LAYER M5 ;
        RECT  31.344 0 31.368 0.192 ;
    END
  END b[361]
  PIN b[362]
    DIRECTION INPUT ;
    USE SIGNAL ;
    PORT
      LAYER M5 ;
        RECT  31.392 0 31.416 0.192 ;
    END
  END b[362]
  PIN b[363]
    DIRECTION INPUT ;
    USE SIGNAL ;
    PORT
      LAYER M5 ;
        RECT  31.44 0 31.464 0.192 ;
    END
  END b[363]
  PIN b[364]
    DIRECTION INPUT ;
    USE SIGNAL ;
    PORT
      LAYER M5 ;
        RECT  31.488 0 31.512 0.192 ;
    END
  END b[364]
  PIN b[365]
    DIRECTION INPUT ;
    USE SIGNAL ;
    PORT
      LAYER M5 ;
        RECT  31.536 0 31.56 0.192 ;
    END
  END b[365]
  PIN b[366]
    DIRECTION INPUT ;
    USE SIGNAL ;
    PORT
      LAYER M5 ;
        RECT  31.584 0 31.608 0.192 ;
    END
  END b[366]
  PIN b[367]
    DIRECTION INPUT ;
    USE SIGNAL ;
    PORT
      LAYER M5 ;
        RECT  31.632 0 31.656 0.192 ;
    END
  END b[367]
  PIN b[368]
    DIRECTION INPUT ;
    USE SIGNAL ;
    PORT
      LAYER M5 ;
        RECT  31.68 0 31.704 0.192 ;
    END
  END b[368]
  PIN b[369]
    DIRECTION INPUT ;
    USE SIGNAL ;
    PORT
      LAYER M5 ;
        RECT  31.728 0 31.752 0.192 ;
    END
  END b[369]
  PIN b[36]
    DIRECTION OUTPUT ;
    USE SIGNAL ;
    PORT
      LAYER M5 ;
        RECT  15.744 0 15.768 0.192 ;
    END
  END b[36]
  PIN b[370]
    DIRECTION INPUT ;
    USE SIGNAL ;
    PORT
      LAYER M5 ;
        RECT  31.776 0 31.8 0.192 ;
    END
  END b[370]
  PIN b[371]
    DIRECTION INPUT ;
    USE SIGNAL ;
    PORT
      LAYER M5 ;
        RECT  31.824 0 31.848 0.192 ;
    END
  END b[371]
  PIN b[372]
    DIRECTION INPUT ;
    USE SIGNAL ;
    PORT
      LAYER M5 ;
        RECT  31.872 0 31.896 0.192 ;
    END
  END b[372]
  PIN b[373]
    DIRECTION INPUT ;
    USE SIGNAL ;
    PORT
      LAYER M5 ;
        RECT  31.92 0 31.944 0.192 ;
    END
  END b[373]
  PIN b[374]
    DIRECTION INPUT ;
    USE SIGNAL ;
    PORT
      LAYER M5 ;
        RECT  31.968 0 31.992 0.192 ;
    END
  END b[374]
  PIN b[375]
    DIRECTION INPUT ;
    USE SIGNAL ;
    PORT
      LAYER M5 ;
        RECT  32.016 0 32.04 0.192 ;
    END
  END b[375]
  PIN b[376]
    DIRECTION INPUT ;
    USE SIGNAL ;
    PORT
      LAYER M5 ;
        RECT  32.064 0 32.088 0.192 ;
    END
  END b[376]
  PIN b[377]
    DIRECTION INPUT ;
    USE SIGNAL ;
    PORT
      LAYER M5 ;
        RECT  32.112 0 32.136 0.192 ;
    END
  END b[377]
  PIN b[378]
    DIRECTION INPUT ;
    USE SIGNAL ;
    PORT
      LAYER M5 ;
        RECT  32.16 0 32.184 0.192 ;
    END
  END b[378]
  PIN b[379]
    DIRECTION INPUT ;
    USE SIGNAL ;
    PORT
      LAYER M5 ;
        RECT  32.208 0 32.232 0.192 ;
    END
  END b[379]
  PIN b[37]
    DIRECTION OUTPUT ;
    USE SIGNAL ;
    PORT
      LAYER M5 ;
        RECT  15.792 0 15.816 0.192 ;
    END
  END b[37]
  PIN b[380]
    DIRECTION INPUT ;
    USE SIGNAL ;
    PORT
      LAYER M5 ;
        RECT  32.256 0 32.28 0.192 ;
    END
  END b[380]
  PIN b[381]
    DIRECTION INPUT ;
    USE SIGNAL ;
    PORT
      LAYER M5 ;
        RECT  32.304 0 32.328 0.192 ;
    END
  END b[381]
  PIN b[382]
    DIRECTION INPUT ;
    USE SIGNAL ;
    PORT
      LAYER M5 ;
        RECT  32.352 0 32.376 0.192 ;
    END
  END b[382]
  PIN b[383]
    DIRECTION INPUT ;
    USE SIGNAL ;
    PORT
      LAYER M5 ;
        RECT  32.4 0 32.424 0.192 ;
    END
  END b[383]
  PIN b[384]
    DIRECTION INPUT ;
    USE SIGNAL ;
    PORT
      LAYER M5 ;
        RECT  32.448 0 32.472 0.192 ;
    END
  END b[384]
  PIN b[385]
    DIRECTION INPUT ;
    USE SIGNAL ;
    PORT
      LAYER M5 ;
        RECT  32.496 0 32.52 0.192 ;
    END
  END b[385]
  PIN b[386]
    DIRECTION INPUT ;
    USE SIGNAL ;
    PORT
      LAYER M5 ;
        RECT  32.544 0 32.568 0.192 ;
    END
  END b[386]
  PIN b[387]
    DIRECTION INPUT ;
    USE SIGNAL ;
    PORT
      LAYER M5 ;
        RECT  32.592 0 32.616 0.192 ;
    END
  END b[387]
  PIN b[388]
    DIRECTION INPUT ;
    USE SIGNAL ;
    PORT
      LAYER M5 ;
        RECT  32.64 0 32.664 0.192 ;
    END
  END b[388]
  PIN b[389]
    DIRECTION INPUT ;
    USE SIGNAL ;
    PORT
      LAYER M5 ;
        RECT  32.688 0 32.712 0.192 ;
    END
  END b[389]
  PIN b[38]
    DIRECTION OUTPUT ;
    USE SIGNAL ;
    PORT
      LAYER M5 ;
        RECT  15.84 0 15.864 0.192 ;
    END
  END b[38]
  PIN b[390]
    DIRECTION INPUT ;
    USE SIGNAL ;
    PORT
      LAYER M5 ;
        RECT  32.736 0 32.76 0.192 ;
    END
  END b[390]
  PIN b[391]
    DIRECTION INPUT ;
    USE SIGNAL ;
    PORT
      LAYER M5 ;
        RECT  32.784 0 32.808 0.192 ;
    END
  END b[391]
  PIN b[392]
    DIRECTION INPUT ;
    USE SIGNAL ;
    PORT
      LAYER M5 ;
        RECT  32.832 0 32.856 0.192 ;
    END
  END b[392]
  PIN b[393]
    DIRECTION INPUT ;
    USE SIGNAL ;
    PORT
      LAYER M5 ;
        RECT  32.88 0 32.904 0.192 ;
    END
  END b[393]
  PIN b[394]
    DIRECTION INPUT ;
    USE SIGNAL ;
    PORT
      LAYER M5 ;
        RECT  32.928 0 32.952 0.192 ;
    END
  END b[394]
  PIN b[395]
    DIRECTION INPUT ;
    USE SIGNAL ;
    PORT
      LAYER M5 ;
        RECT  32.976 0 33 0.192 ;
    END
  END b[395]
  PIN b[396]
    DIRECTION INPUT ;
    USE SIGNAL ;
    PORT
      LAYER M5 ;
        RECT  33.024 0 33.048 0.192 ;
    END
  END b[396]
  PIN b[397]
    DIRECTION INPUT ;
    USE SIGNAL ;
    PORT
      LAYER M5 ;
        RECT  33.072 0 33.096 0.192 ;
    END
  END b[397]
  PIN b[398]
    DIRECTION INPUT ;
    USE SIGNAL ;
    PORT
      LAYER M5 ;
        RECT  33.12 0 33.144 0.192 ;
    END
  END b[398]
  PIN b[399]
    DIRECTION INPUT ;
    USE SIGNAL ;
    PORT
      LAYER M5 ;
        RECT  33.168 0 33.192 0.192 ;
    END
  END b[399]
  PIN b[39]
    DIRECTION OUTPUT ;
    USE SIGNAL ;
    PORT
      LAYER M5 ;
        RECT  15.888 0 15.912 0.192 ;
    END
  END b[39]
  PIN b[3]
    DIRECTION OUTPUT ;
    USE SIGNAL ;
    PORT
      LAYER M5 ;
        RECT  14.16 0 14.184 0.192 ;
    END
  END b[3]
  PIN b[400]
    DIRECTION INPUT ;
    USE SIGNAL ;
    PORT
      LAYER M5 ;
        RECT  33.216 0 33.24 0.192 ;
    END
  END b[400]
  PIN b[401]
    DIRECTION INPUT ;
    USE SIGNAL ;
    PORT
      LAYER M5 ;
        RECT  33.264 0 33.288 0.192 ;
    END
  END b[401]
  PIN b[402]
    DIRECTION INPUT ;
    USE SIGNAL ;
    PORT
      LAYER M5 ;
        RECT  33.312 0 33.336 0.192 ;
    END
  END b[402]
  PIN b[403]
    DIRECTION INPUT ;
    USE SIGNAL ;
    PORT
      LAYER M5 ;
        RECT  33.36 0 33.384 0.192 ;
    END
  END b[403]
  PIN b[404]
    DIRECTION INPUT ;
    USE SIGNAL ;
    PORT
      LAYER M5 ;
        RECT  33.408 0 33.432 0.192 ;
    END
  END b[404]
  PIN b[405]
    DIRECTION INPUT ;
    USE SIGNAL ;
    PORT
      LAYER M5 ;
        RECT  33.456 0 33.48 0.192 ;
    END
  END b[405]
  PIN b[406]
    DIRECTION INPUT ;
    USE SIGNAL ;
    PORT
      LAYER M5 ;
        RECT  33.504 0 33.528 0.192 ;
    END
  END b[406]
  PIN b[407]
    DIRECTION INPUT ;
    USE SIGNAL ;
    PORT
      LAYER M5 ;
        RECT  33.552 0 33.576 0.192 ;
    END
  END b[407]
  PIN b[408]
    DIRECTION INPUT ;
    USE SIGNAL ;
    PORT
      LAYER M5 ;
        RECT  33.6 0 33.624 0.192 ;
    END
  END b[408]
  PIN b[409]
    DIRECTION INPUT ;
    USE SIGNAL ;
    PORT
      LAYER M5 ;
        RECT  33.648 0 33.672 0.192 ;
    END
  END b[409]
  PIN b[40]
    DIRECTION OUTPUT ;
    USE SIGNAL ;
    PORT
      LAYER M5 ;
        RECT  15.936 0 15.96 0.192 ;
    END
  END b[40]
  PIN b[410]
    DIRECTION INPUT ;
    USE SIGNAL ;
    PORT
      LAYER M5 ;
        RECT  33.696 0 33.72 0.192 ;
    END
  END b[410]
  PIN b[411]
    DIRECTION INPUT ;
    USE SIGNAL ;
    PORT
      LAYER M5 ;
        RECT  33.744 0 33.768 0.192 ;
    END
  END b[411]
  PIN b[412]
    DIRECTION INPUT ;
    USE SIGNAL ;
    PORT
      LAYER M5 ;
        RECT  33.792 0 33.816 0.192 ;
    END
  END b[412]
  PIN b[413]
    DIRECTION INPUT ;
    USE SIGNAL ;
    PORT
      LAYER M5 ;
        RECT  33.84 0 33.864 0.192 ;
    END
  END b[413]
  PIN b[414]
    DIRECTION INPUT ;
    USE SIGNAL ;
    PORT
      LAYER M5 ;
        RECT  33.888 0 33.912 0.192 ;
    END
  END b[414]
  PIN b[415]
    DIRECTION INPUT ;
    USE SIGNAL ;
    PORT
      LAYER M5 ;
        RECT  33.936 0 33.96 0.192 ;
    END
  END b[415]
  PIN b[416]
    DIRECTION INPUT ;
    USE SIGNAL ;
    PORT
      LAYER M5 ;
        RECT  33.984 0 34.008 0.192 ;
    END
  END b[416]
  PIN b[417]
    DIRECTION INPUT ;
    USE SIGNAL ;
    PORT
      LAYER M5 ;
        RECT  34.032 0 34.056 0.192 ;
    END
  END b[417]
  PIN b[418]
    DIRECTION INPUT ;
    USE SIGNAL ;
    PORT
      LAYER M5 ;
        RECT  34.08 0 34.104 0.192 ;
    END
  END b[418]
  PIN b[419]
    DIRECTION INPUT ;
    USE SIGNAL ;
    PORT
      LAYER M5 ;
        RECT  34.128 0 34.152 0.192 ;
    END
  END b[419]
  PIN b[41]
    DIRECTION OUTPUT ;
    USE SIGNAL ;
    PORT
      LAYER M5 ;
        RECT  15.984 0 16.008 0.192 ;
    END
  END b[41]
  PIN b[420]
    DIRECTION INPUT ;
    USE SIGNAL ;
    PORT
      LAYER M5 ;
        RECT  34.176 0 34.2 0.192 ;
    END
  END b[420]
  PIN b[421]
    DIRECTION INPUT ;
    USE SIGNAL ;
    PORT
      LAYER M5 ;
        RECT  34.224 0 34.248 0.192 ;
    END
  END b[421]
  PIN b[422]
    DIRECTION INPUT ;
    USE SIGNAL ;
    PORT
      LAYER M5 ;
        RECT  34.272 0 34.296 0.192 ;
    END
  END b[422]
  PIN b[423]
    DIRECTION INPUT ;
    USE SIGNAL ;
    PORT
      LAYER M5 ;
        RECT  34.32 0 34.344 0.192 ;
    END
  END b[423]
  PIN b[424]
    DIRECTION INPUT ;
    USE SIGNAL ;
    PORT
      LAYER M5 ;
        RECT  34.368 0 34.392 0.192 ;
    END
  END b[424]
  PIN b[425]
    DIRECTION INPUT ;
    USE SIGNAL ;
    PORT
      LAYER M5 ;
        RECT  34.416 0 34.44 0.192 ;
    END
  END b[425]
  PIN b[426]
    DIRECTION INPUT ;
    USE SIGNAL ;
    PORT
      LAYER M5 ;
        RECT  34.464 0 34.488 0.192 ;
    END
  END b[426]
  PIN b[427]
    DIRECTION INPUT ;
    USE SIGNAL ;
    PORT
      LAYER M5 ;
        RECT  34.512 0 34.536 0.192 ;
    END
  END b[427]
  PIN b[428]
    DIRECTION INPUT ;
    USE SIGNAL ;
    PORT
      LAYER M5 ;
        RECT  34.56 0 34.584 0.192 ;
    END
  END b[428]
  PIN b[429]
    DIRECTION INPUT ;
    USE SIGNAL ;
    PORT
      LAYER M5 ;
        RECT  34.608 0 34.632 0.192 ;
    END
  END b[429]
  PIN b[42]
    DIRECTION OUTPUT ;
    USE SIGNAL ;
    PORT
      LAYER M5 ;
        RECT  16.032 0 16.056 0.192 ;
    END
  END b[42]
  PIN b[430]
    DIRECTION INPUT ;
    USE SIGNAL ;
    PORT
      LAYER M5 ;
        RECT  34.656 0 34.68 0.192 ;
    END
  END b[430]
  PIN b[431]
    DIRECTION INPUT ;
    USE SIGNAL ;
    PORT
      LAYER M5 ;
        RECT  34.704 0 34.728 0.192 ;
    END
  END b[431]
  PIN b[432]
    DIRECTION INPUT ;
    USE SIGNAL ;
    PORT
      LAYER M5 ;
        RECT  34.752 0 34.776 0.192 ;
    END
  END b[432]
  PIN b[433]
    DIRECTION INPUT ;
    USE SIGNAL ;
    PORT
      LAYER M5 ;
        RECT  34.8 0 34.824 0.192 ;
    END
  END b[433]
  PIN b[434]
    DIRECTION INPUT ;
    USE SIGNAL ;
    PORT
      LAYER M5 ;
        RECT  34.848 0 34.872 0.192 ;
    END
  END b[434]
  PIN b[435]
    DIRECTION INPUT ;
    USE SIGNAL ;
    PORT
      LAYER M5 ;
        RECT  34.896 0 34.92 0.192 ;
    END
  END b[435]
  PIN b[436]
    DIRECTION INPUT ;
    USE SIGNAL ;
    PORT
      LAYER M5 ;
        RECT  34.944 0 34.968 0.192 ;
    END
  END b[436]
  PIN b[437]
    DIRECTION INPUT ;
    USE SIGNAL ;
    PORT
      LAYER M5 ;
        RECT  34.992 0 35.016 0.192 ;
    END
  END b[437]
  PIN b[438]
    DIRECTION INPUT ;
    USE SIGNAL ;
    PORT
      LAYER M5 ;
        RECT  35.04 0 35.064 0.192 ;
    END
  END b[438]
  PIN b[439]
    DIRECTION INPUT ;
    USE SIGNAL ;
    PORT
      LAYER M5 ;
        RECT  35.088 0 35.112 0.192 ;
    END
  END b[439]
  PIN b[43]
    DIRECTION OUTPUT ;
    USE SIGNAL ;
    PORT
      LAYER M5 ;
        RECT  16.08 0 16.104 0.192 ;
    END
  END b[43]
  PIN b[440]
    DIRECTION INPUT ;
    USE SIGNAL ;
    PORT
      LAYER M5 ;
        RECT  35.136 0 35.16 0.192 ;
    END
  END b[440]
  PIN b[441]
    DIRECTION INPUT ;
    USE SIGNAL ;
    PORT
      LAYER M5 ;
        RECT  35.184 0 35.208 0.192 ;
    END
  END b[441]
  PIN b[442]
    DIRECTION INPUT ;
    USE SIGNAL ;
    PORT
      LAYER M5 ;
        RECT  35.232 0 35.256 0.192 ;
    END
  END b[442]
  PIN b[443]
    DIRECTION INPUT ;
    USE SIGNAL ;
    PORT
      LAYER M5 ;
        RECT  35.28 0 35.304 0.192 ;
    END
  END b[443]
  PIN b[444]
    DIRECTION INPUT ;
    USE SIGNAL ;
    PORT
      LAYER M5 ;
        RECT  35.328 0 35.352 0.192 ;
    END
  END b[444]
  PIN b[445]
    DIRECTION INPUT ;
    USE SIGNAL ;
    PORT
      LAYER M5 ;
        RECT  35.376 0 35.4 0.192 ;
    END
  END b[445]
  PIN b[446]
    DIRECTION INPUT ;
    USE SIGNAL ;
    PORT
      LAYER M5 ;
        RECT  35.424 0 35.448 0.192 ;
    END
  END b[446]
  PIN b[447]
    DIRECTION INPUT ;
    USE SIGNAL ;
    PORT
      LAYER M5 ;
        RECT  35.472 0 35.496 0.192 ;
    END
  END b[447]
  PIN b[448]
    DIRECTION INPUT ;
    USE SIGNAL ;
    PORT
      LAYER M5 ;
        RECT  35.52 0 35.544 0.192 ;
    END
  END b[448]
  PIN b[449]
    DIRECTION INPUT ;
    USE SIGNAL ;
    PORT
      LAYER M5 ;
        RECT  35.568 0 35.592 0.192 ;
    END
  END b[449]
  PIN b[44]
    DIRECTION OUTPUT ;
    USE SIGNAL ;
    PORT
      LAYER M5 ;
        RECT  16.128 0 16.152 0.192 ;
    END
  END b[44]
  PIN b[450]
    DIRECTION INPUT ;
    USE SIGNAL ;
    PORT
      LAYER M5 ;
        RECT  35.616 0 35.64 0.192 ;
    END
  END b[450]
  PIN b[451]
    DIRECTION INPUT ;
    USE SIGNAL ;
    PORT
      LAYER M5 ;
        RECT  35.664 0 35.688 0.192 ;
    END
  END b[451]
  PIN b[452]
    DIRECTION INPUT ;
    USE SIGNAL ;
    PORT
      LAYER M5 ;
        RECT  35.712 0 35.736 0.192 ;
    END
  END b[452]
  PIN b[453]
    DIRECTION INPUT ;
    USE SIGNAL ;
    PORT
      LAYER M5 ;
        RECT  35.76 0 35.784 0.192 ;
    END
  END b[453]
  PIN b[454]
    DIRECTION INPUT ;
    USE SIGNAL ;
    PORT
      LAYER M5 ;
        RECT  35.808 0 35.832 0.192 ;
    END
  END b[454]
  PIN b[455]
    DIRECTION INPUT ;
    USE SIGNAL ;
    PORT
      LAYER M5 ;
        RECT  35.856 0 35.88 0.192 ;
    END
  END b[455]
  PIN b[456]
    DIRECTION INPUT ;
    USE SIGNAL ;
    PORT
      LAYER M5 ;
        RECT  35.904 0 35.928 0.192 ;
    END
  END b[456]
  PIN b[457]
    DIRECTION INPUT ;
    USE SIGNAL ;
    PORT
      LAYER M5 ;
        RECT  35.952 0 35.976 0.192 ;
    END
  END b[457]
  PIN b[458]
    DIRECTION INPUT ;
    USE SIGNAL ;
    PORT
      LAYER M5 ;
        RECT  36 0 36.024 0.192 ;
    END
  END b[458]
  PIN b[459]
    DIRECTION INPUT ;
    USE SIGNAL ;
    PORT
      LAYER M5 ;
        RECT  36.048 0 36.072 0.192 ;
    END
  END b[459]
  PIN b[45]
    DIRECTION OUTPUT ;
    USE SIGNAL ;
    PORT
      LAYER M5 ;
        RECT  16.176 0 16.2 0.192 ;
    END
  END b[45]
  PIN b[460]
    DIRECTION INPUT ;
    USE SIGNAL ;
    PORT
      LAYER M5 ;
        RECT  36.096 0 36.12 0.192 ;
    END
  END b[460]
  PIN b[461]
    DIRECTION INPUT ;
    USE SIGNAL ;
    PORT
      LAYER M5 ;
        RECT  36.144 0 36.168 0.192 ;
    END
  END b[461]
  PIN b[462]
    DIRECTION INPUT ;
    USE SIGNAL ;
    PORT
      LAYER M5 ;
        RECT  36.192 0 36.216 0.192 ;
    END
  END b[462]
  PIN b[463]
    DIRECTION INPUT ;
    USE SIGNAL ;
    PORT
      LAYER M5 ;
        RECT  36.24 0 36.264 0.192 ;
    END
  END b[463]
  PIN b[464]
    DIRECTION INPUT ;
    USE SIGNAL ;
    PORT
      LAYER M5 ;
        RECT  36.288 0 36.312 0.192 ;
    END
  END b[464]
  PIN b[465]
    DIRECTION INPUT ;
    USE SIGNAL ;
    PORT
      LAYER M5 ;
        RECT  36.336 0 36.36 0.192 ;
    END
  END b[465]
  PIN b[466]
    DIRECTION INPUT ;
    USE SIGNAL ;
    PORT
      LAYER M5 ;
        RECT  36.384 0 36.408 0.192 ;
    END
  END b[466]
  PIN b[467]
    DIRECTION INPUT ;
    USE SIGNAL ;
    PORT
      LAYER M5 ;
        RECT  36.432 0 36.456 0.192 ;
    END
  END b[467]
  PIN b[468]
    DIRECTION INPUT ;
    USE SIGNAL ;
    PORT
      LAYER M5 ;
        RECT  36.48 0 36.504 0.192 ;
    END
  END b[468]
  PIN b[469]
    DIRECTION INPUT ;
    USE SIGNAL ;
    PORT
      LAYER M5 ;
        RECT  36.528 0 36.552 0.192 ;
    END
  END b[469]
  PIN b[46]
    DIRECTION OUTPUT ;
    USE SIGNAL ;
    PORT
      LAYER M5 ;
        RECT  16.224 0 16.248 0.192 ;
    END
  END b[46]
  PIN b[470]
    DIRECTION INPUT ;
    USE SIGNAL ;
    PORT
      LAYER M5 ;
        RECT  36.576 0 36.6 0.192 ;
    END
  END b[470]
  PIN b[471]
    DIRECTION INPUT ;
    USE SIGNAL ;
    PORT
      LAYER M5 ;
        RECT  36.624 0 36.648 0.192 ;
    END
  END b[471]
  PIN b[472]
    DIRECTION INPUT ;
    USE SIGNAL ;
    PORT
      LAYER M5 ;
        RECT  36.672 0 36.696 0.192 ;
    END
  END b[472]
  PIN b[473]
    DIRECTION INPUT ;
    USE SIGNAL ;
    PORT
      LAYER M5 ;
        RECT  36.72 0 36.744 0.192 ;
    END
  END b[473]
  PIN b[474]
    DIRECTION INPUT ;
    USE SIGNAL ;
    PORT
      LAYER M5 ;
        RECT  36.768 0 36.792 0.192 ;
    END
  END b[474]
  PIN b[475]
    DIRECTION INPUT ;
    USE SIGNAL ;
    PORT
      LAYER M5 ;
        RECT  36.816 0 36.84 0.192 ;
    END
  END b[475]
  PIN b[476]
    DIRECTION INPUT ;
    USE SIGNAL ;
    PORT
      LAYER M5 ;
        RECT  36.864 0 36.888 0.192 ;
    END
  END b[476]
  PIN b[477]
    DIRECTION INPUT ;
    USE SIGNAL ;
    PORT
      LAYER M5 ;
        RECT  36.912 0 36.936 0.192 ;
    END
  END b[477]
  PIN b[478]
    DIRECTION INPUT ;
    USE SIGNAL ;
    PORT
      LAYER M5 ;
        RECT  36.96 0 36.984 0.192 ;
    END
  END b[478]
  PIN b[479]
    DIRECTION INPUT ;
    USE SIGNAL ;
    PORT
      LAYER M5 ;
        RECT  37.008 0 37.032 0.192 ;
    END
  END b[479]
  PIN b[47]
    DIRECTION OUTPUT ;
    USE SIGNAL ;
    PORT
      LAYER M5 ;
        RECT  16.272 0 16.296 0.192 ;
    END
  END b[47]
  PIN b[480]
    DIRECTION INPUT ;
    USE SIGNAL ;
    PORT
      LAYER M5 ;
        RECT  37.056 0 37.08 0.192 ;
    END
  END b[480]
  PIN b[481]
    DIRECTION INPUT ;
    USE SIGNAL ;
    PORT
      LAYER M5 ;
        RECT  37.104 0 37.128 0.192 ;
    END
  END b[481]
  PIN b[482]
    DIRECTION INPUT ;
    USE SIGNAL ;
    PORT
      LAYER M5 ;
        RECT  37.152 0 37.176 0.192 ;
    END
  END b[482]
  PIN b[483]
    DIRECTION INPUT ;
    USE SIGNAL ;
    PORT
      LAYER M5 ;
        RECT  37.2 0 37.224 0.192 ;
    END
  END b[483]
  PIN b[484]
    DIRECTION INPUT ;
    USE SIGNAL ;
    PORT
      LAYER M5 ;
        RECT  37.248 0 37.272 0.192 ;
    END
  END b[484]
  PIN b[485]
    DIRECTION INPUT ;
    USE SIGNAL ;
    PORT
      LAYER M5 ;
        RECT  37.296 0 37.32 0.192 ;
    END
  END b[485]
  PIN b[486]
    DIRECTION INPUT ;
    USE SIGNAL ;
    PORT
      LAYER M5 ;
        RECT  37.344 0 37.368 0.192 ;
    END
  END b[486]
  PIN b[487]
    DIRECTION INPUT ;
    USE SIGNAL ;
    PORT
      LAYER M5 ;
        RECT  37.392 0 37.416 0.192 ;
    END
  END b[487]
  PIN b[488]
    DIRECTION INPUT ;
    USE SIGNAL ;
    PORT
      LAYER M5 ;
        RECT  37.44 0 37.464 0.192 ;
    END
  END b[488]
  PIN b[489]
    DIRECTION INPUT ;
    USE SIGNAL ;
    PORT
      LAYER M5 ;
        RECT  37.488 0 37.512 0.192 ;
    END
  END b[489]
  PIN b[48]
    DIRECTION OUTPUT ;
    USE SIGNAL ;
    PORT
      LAYER M5 ;
        RECT  16.32 0 16.344 0.192 ;
    END
  END b[48]
  PIN b[490]
    DIRECTION INPUT ;
    USE SIGNAL ;
    PORT
      LAYER M5 ;
        RECT  37.536 0 37.56 0.192 ;
    END
  END b[490]
  PIN b[491]
    DIRECTION INPUT ;
    USE SIGNAL ;
    PORT
      LAYER M5 ;
        RECT  37.584 0 37.608 0.192 ;
    END
  END b[491]
  PIN b[492]
    DIRECTION INPUT ;
    USE SIGNAL ;
    PORT
      LAYER M5 ;
        RECT  37.632 0 37.656 0.192 ;
    END
  END b[492]
  PIN b[493]
    DIRECTION INPUT ;
    USE SIGNAL ;
    PORT
      LAYER M5 ;
        RECT  37.68 0 37.704 0.192 ;
    END
  END b[493]
  PIN b[494]
    DIRECTION INPUT ;
    USE SIGNAL ;
    PORT
      LAYER M5 ;
        RECT  37.728 0 37.752 0.192 ;
    END
  END b[494]
  PIN b[495]
    DIRECTION INPUT ;
    USE SIGNAL ;
    PORT
      LAYER M5 ;
        RECT  37.776 0 37.8 0.192 ;
    END
  END b[495]
  PIN b[496]
    DIRECTION INPUT ;
    USE SIGNAL ;
    PORT
      LAYER M5 ;
        RECT  37.824 0 37.848 0.192 ;
    END
  END b[496]
  PIN b[497]
    DIRECTION INPUT ;
    USE SIGNAL ;
    PORT
      LAYER M5 ;
        RECT  37.872 0 37.896 0.192 ;
    END
  END b[497]
  PIN b[498]
    DIRECTION INPUT ;
    USE SIGNAL ;
    PORT
      LAYER M5 ;
        RECT  37.92 0 37.944 0.192 ;
    END
  END b[498]
  PIN b[499]
    DIRECTION INPUT ;
    USE SIGNAL ;
    PORT
      LAYER M5 ;
        RECT  37.968 0 37.992 0.192 ;
    END
  END b[499]
  PIN b[49]
    DIRECTION OUTPUT ;
    USE SIGNAL ;
    PORT
      LAYER M5 ;
        RECT  16.368 0 16.392 0.192 ;
    END
  END b[49]
  PIN b[4]
    DIRECTION OUTPUT ;
    USE SIGNAL ;
    PORT
      LAYER M5 ;
        RECT  14.208 0 14.232 0.192 ;
    END
  END b[4]
  PIN b[500]
    DIRECTION INPUT ;
    USE SIGNAL ;
    PORT
      LAYER M5 ;
        RECT  38.016 0 38.04 0.192 ;
    END
  END b[500]
  PIN b[501]
    DIRECTION INPUT ;
    USE SIGNAL ;
    PORT
      LAYER M5 ;
        RECT  38.064 0 38.088 0.192 ;
    END
  END b[501]
  PIN b[502]
    DIRECTION INPUT ;
    USE SIGNAL ;
    PORT
      LAYER M5 ;
        RECT  38.112 0 38.136 0.192 ;
    END
  END b[502]
  PIN b[503]
    DIRECTION INPUT ;
    USE SIGNAL ;
    PORT
      LAYER M5 ;
        RECT  38.16 0 38.184 0.192 ;
    END
  END b[503]
  PIN b[504]
    DIRECTION INPUT ;
    USE SIGNAL ;
    PORT
      LAYER M5 ;
        RECT  38.208 0 38.232 0.192 ;
    END
  END b[504]
  PIN b[505]
    DIRECTION INPUT ;
    USE SIGNAL ;
    PORT
      LAYER M5 ;
        RECT  38.256 0 38.28 0.192 ;
    END
  END b[505]
  PIN b[506]
    DIRECTION INPUT ;
    USE SIGNAL ;
    PORT
      LAYER M5 ;
        RECT  38.304 0 38.328 0.192 ;
    END
  END b[506]
  PIN b[507]
    DIRECTION INPUT ;
    USE SIGNAL ;
    PORT
      LAYER M5 ;
        RECT  38.352 0 38.376 0.192 ;
    END
  END b[507]
  PIN b[508]
    DIRECTION INPUT ;
    USE SIGNAL ;
    PORT
      LAYER M5 ;
        RECT  38.4 0 38.424 0.192 ;
    END
  END b[508]
  PIN b[509]
    DIRECTION INPUT ;
    USE SIGNAL ;
    PORT
      LAYER M5 ;
        RECT  38.448 0 38.472 0.192 ;
    END
  END b[509]
  PIN b[50]
    DIRECTION OUTPUT ;
    USE SIGNAL ;
    PORT
      LAYER M5 ;
        RECT  16.416 0 16.44 0.192 ;
    END
  END b[50]
  PIN b[510]
    DIRECTION INPUT ;
    USE SIGNAL ;
    PORT
      LAYER M5 ;
        RECT  38.496 0 38.52 0.192 ;
    END
  END b[510]
  PIN b[511]
    DIRECTION INPUT ;
    USE SIGNAL ;
    PORT
      LAYER M5 ;
        RECT  38.544 0 38.568 0.192 ;
    END
  END b[511]
  PIN b[512]
    DIRECTION OUTPUT ;
    USE SIGNAL ;
    PORT
      LAYER M5 ;
        RECT  38.592 0 38.616 0.192 ;
    END
  END b[512]
  PIN b[513]
    DIRECTION INPUT ;
    USE SIGNAL ;
    PORT
      LAYER M5 ;
        RECT  38.64 0 38.664 0.192 ;
    END
  END b[513]
  PIN b[51]
    DIRECTION OUTPUT ;
    USE SIGNAL ;
    PORT
      LAYER M5 ;
        RECT  16.464 0 16.488 0.192 ;
    END
  END b[51]
  PIN b[52]
    DIRECTION OUTPUT ;
    USE SIGNAL ;
    PORT
      LAYER M5 ;
        RECT  16.512 0 16.536 0.192 ;
    END
  END b[52]
  PIN b[53]
    DIRECTION OUTPUT ;
    USE SIGNAL ;
    PORT
      LAYER M5 ;
        RECT  16.56 0 16.584 0.192 ;
    END
  END b[53]
  PIN b[54]
    DIRECTION OUTPUT ;
    USE SIGNAL ;
    PORT
      LAYER M5 ;
        RECT  16.608 0 16.632 0.192 ;
    END
  END b[54]
  PIN b[55]
    DIRECTION OUTPUT ;
    USE SIGNAL ;
    PORT
      LAYER M5 ;
        RECT  16.656 0 16.68 0.192 ;
    END
  END b[55]
  PIN b[56]
    DIRECTION OUTPUT ;
    USE SIGNAL ;
    PORT
      LAYER M5 ;
        RECT  16.704 0 16.728 0.192 ;
    END
  END b[56]
  PIN b[57]
    DIRECTION OUTPUT ;
    USE SIGNAL ;
    PORT
      LAYER M5 ;
        RECT  16.752 0 16.776 0.192 ;
    END
  END b[57]
  PIN b[58]
    DIRECTION OUTPUT ;
    USE SIGNAL ;
    PORT
      LAYER M5 ;
        RECT  16.8 0 16.824 0.192 ;
    END
  END b[58]
  PIN b[59]
    DIRECTION OUTPUT ;
    USE SIGNAL ;
    PORT
      LAYER M5 ;
        RECT  16.848 0 16.872 0.192 ;
    END
  END b[59]
  PIN b[5]
    DIRECTION OUTPUT ;
    USE SIGNAL ;
    PORT
      LAYER M5 ;
        RECT  14.256 0 14.28 0.192 ;
    END
  END b[5]
  PIN b[60]
    DIRECTION OUTPUT ;
    USE SIGNAL ;
    PORT
      LAYER M5 ;
        RECT  16.896 0 16.92 0.192 ;
    END
  END b[60]
  PIN b[61]
    DIRECTION OUTPUT ;
    USE SIGNAL ;
    PORT
      LAYER M5 ;
        RECT  16.944 0 16.968 0.192 ;
    END
  END b[61]
  PIN b[62]
    DIRECTION OUTPUT ;
    USE SIGNAL ;
    PORT
      LAYER M5 ;
        RECT  16.992 0 17.016 0.192 ;
    END
  END b[62]
  PIN b[63]
    DIRECTION OUTPUT ;
    USE SIGNAL ;
    PORT
      LAYER M5 ;
        RECT  17.04 0 17.064 0.192 ;
    END
  END b[63]
  PIN b[64]
    DIRECTION OUTPUT ;
    USE SIGNAL ;
    PORT
      LAYER M5 ;
        RECT  17.088 0 17.112 0.192 ;
    END
  END b[64]
  PIN b[65]
    DIRECTION OUTPUT ;
    USE SIGNAL ;
    PORT
      LAYER M5 ;
        RECT  17.136 0 17.16 0.192 ;
    END
  END b[65]
  PIN b[66]
    DIRECTION OUTPUT ;
    USE SIGNAL ;
    PORT
      LAYER M5 ;
        RECT  17.184 0 17.208 0.192 ;
    END
  END b[66]
  PIN b[67]
    DIRECTION OUTPUT ;
    USE SIGNAL ;
    PORT
      LAYER M5 ;
        RECT  17.232 0 17.256 0.192 ;
    END
  END b[67]
  PIN b[68]
    DIRECTION OUTPUT ;
    USE SIGNAL ;
    PORT
      LAYER M5 ;
        RECT  17.28 0 17.304 0.192 ;
    END
  END b[68]
  PIN b[69]
    DIRECTION OUTPUT ;
    USE SIGNAL ;
    PORT
      LAYER M5 ;
        RECT  17.328 0 17.352 0.192 ;
    END
  END b[69]
  PIN b[6]
    DIRECTION OUTPUT ;
    USE SIGNAL ;
    PORT
      LAYER M5 ;
        RECT  14.304 0 14.328 0.192 ;
    END
  END b[6]
  PIN b[70]
    DIRECTION OUTPUT ;
    USE SIGNAL ;
    PORT
      LAYER M5 ;
        RECT  17.376 0 17.4 0.192 ;
    END
  END b[70]
  PIN b[71]
    DIRECTION OUTPUT ;
    USE SIGNAL ;
    PORT
      LAYER M5 ;
        RECT  17.424 0 17.448 0.192 ;
    END
  END b[71]
  PIN b[72]
    DIRECTION OUTPUT ;
    USE SIGNAL ;
    PORT
      LAYER M5 ;
        RECT  17.472 0 17.496 0.192 ;
    END
  END b[72]
  PIN b[73]
    DIRECTION OUTPUT ;
    USE SIGNAL ;
    PORT
      LAYER M5 ;
        RECT  17.52 0 17.544 0.192 ;
    END
  END b[73]
  PIN b[74]
    DIRECTION OUTPUT ;
    USE SIGNAL ;
    PORT
      LAYER M5 ;
        RECT  17.568 0 17.592 0.192 ;
    END
  END b[74]
  PIN b[75]
    DIRECTION OUTPUT ;
    USE SIGNAL ;
    PORT
      LAYER M5 ;
        RECT  17.616 0 17.64 0.192 ;
    END
  END b[75]
  PIN b[76]
    DIRECTION OUTPUT ;
    USE SIGNAL ;
    PORT
      LAYER M5 ;
        RECT  17.664 0 17.688 0.192 ;
    END
  END b[76]
  PIN b[77]
    DIRECTION OUTPUT ;
    USE SIGNAL ;
    PORT
      LAYER M5 ;
        RECT  17.712 0 17.736 0.192 ;
    END
  END b[77]
  PIN b[78]
    DIRECTION OUTPUT ;
    USE SIGNAL ;
    PORT
      LAYER M5 ;
        RECT  17.76 0 17.784 0.192 ;
    END
  END b[78]
  PIN b[79]
    DIRECTION OUTPUT ;
    USE SIGNAL ;
    PORT
      LAYER M5 ;
        RECT  17.808 0 17.832 0.192 ;
    END
  END b[79]
  PIN b[7]
    DIRECTION OUTPUT ;
    USE SIGNAL ;
    PORT
      LAYER M5 ;
        RECT  14.352 0 14.376 0.192 ;
    END
  END b[7]
  PIN b[80]
    DIRECTION OUTPUT ;
    USE SIGNAL ;
    PORT
      LAYER M5 ;
        RECT  17.856 0 17.88 0.192 ;
    END
  END b[80]
  PIN b[81]
    DIRECTION OUTPUT ;
    USE SIGNAL ;
    PORT
      LAYER M5 ;
        RECT  17.904 0 17.928 0.192 ;
    END
  END b[81]
  PIN b[82]
    DIRECTION OUTPUT ;
    USE SIGNAL ;
    PORT
      LAYER M5 ;
        RECT  17.952 0 17.976 0.192 ;
    END
  END b[82]
  PIN b[83]
    DIRECTION OUTPUT ;
    USE SIGNAL ;
    PORT
      LAYER M5 ;
        RECT  18 0 18.024 0.192 ;
    END
  END b[83]
  PIN b[84]
    DIRECTION OUTPUT ;
    USE SIGNAL ;
    PORT
      LAYER M5 ;
        RECT  18.048 0 18.072 0.192 ;
    END
  END b[84]
  PIN b[85]
    DIRECTION OUTPUT ;
    USE SIGNAL ;
    PORT
      LAYER M5 ;
        RECT  18.096 0 18.12 0.192 ;
    END
  END b[85]
  PIN b[86]
    DIRECTION OUTPUT ;
    USE SIGNAL ;
    PORT
      LAYER M5 ;
        RECT  18.144 0 18.168 0.192 ;
    END
  END b[86]
  PIN b[87]
    DIRECTION OUTPUT ;
    USE SIGNAL ;
    PORT
      LAYER M5 ;
        RECT  18.192 0 18.216 0.192 ;
    END
  END b[87]
  PIN b[88]
    DIRECTION OUTPUT ;
    USE SIGNAL ;
    PORT
      LAYER M5 ;
        RECT  18.24 0 18.264 0.192 ;
    END
  END b[88]
  PIN b[89]
    DIRECTION OUTPUT ;
    USE SIGNAL ;
    PORT
      LAYER M5 ;
        RECT  18.288 0 18.312 0.192 ;
    END
  END b[89]
  PIN b[8]
    DIRECTION OUTPUT ;
    USE SIGNAL ;
    PORT
      LAYER M5 ;
        RECT  14.4 0 14.424 0.192 ;
    END
  END b[8]
  PIN b[90]
    DIRECTION OUTPUT ;
    USE SIGNAL ;
    PORT
      LAYER M5 ;
        RECT  18.336 0 18.36 0.192 ;
    END
  END b[90]
  PIN b[91]
    DIRECTION OUTPUT ;
    USE SIGNAL ;
    PORT
      LAYER M5 ;
        RECT  18.384 0 18.408 0.192 ;
    END
  END b[91]
  PIN b[92]
    DIRECTION OUTPUT ;
    USE SIGNAL ;
    PORT
      LAYER M5 ;
        RECT  18.432 0 18.456 0.192 ;
    END
  END b[92]
  PIN b[93]
    DIRECTION OUTPUT ;
    USE SIGNAL ;
    PORT
      LAYER M5 ;
        RECT  18.48 0 18.504 0.192 ;
    END
  END b[93]
  PIN b[94]
    DIRECTION OUTPUT ;
    USE SIGNAL ;
    PORT
      LAYER M5 ;
        RECT  18.528 0 18.552 0.192 ;
    END
  END b[94]
  PIN b[95]
    DIRECTION OUTPUT ;
    USE SIGNAL ;
    PORT
      LAYER M5 ;
        RECT  18.576 0 18.6 0.192 ;
    END
  END b[95]
  PIN b[96]
    DIRECTION OUTPUT ;
    USE SIGNAL ;
    PORT
      LAYER M5 ;
        RECT  18.624 0 18.648 0.192 ;
    END
  END b[96]
  PIN b[97]
    DIRECTION OUTPUT ;
    USE SIGNAL ;
    PORT
      LAYER M5 ;
        RECT  18.672 0 18.696 0.192 ;
    END
  END b[97]
  PIN b[98]
    DIRECTION OUTPUT ;
    USE SIGNAL ;
    PORT
      LAYER M5 ;
        RECT  18.72 0 18.744 0.192 ;
    END
  END b[98]
  PIN b[99]
    DIRECTION OUTPUT ;
    USE SIGNAL ;
    PORT
      LAYER M5 ;
        RECT  18.768 0 18.792 0.192 ;
    END
  END b[99]
  PIN b[9]
    DIRECTION OUTPUT ;
    USE SIGNAL ;
    PORT
      LAYER M5 ;
        RECT  14.448 0 14.472 0.192 ;
    END
  END b[9]
  PIN rst[0]
    DIRECTION INPUT ;
    USE SIGNAL ;
    PORT
      LAYER M5 ;
        RECT  38.64 77.544 38.664 77.736 ;
    END
  END rst[0]
  PIN VDD
    DIRECTION INOUT ;
    USE POWER ;
    PORT
      LAYER M7 ;
        RECT  38.656 0.531 38.944 76.959 ;
        RECT  27.856 0.531 28.144 76.959 ;
        RECT  17.056 0.531 17.344 76.959 ;
        RECT  6.256 0.531 6.544 76.959 ;
      LAYER M6 ;
        RECT  0 71.772 0.032 72.06 ;
        RECT  0 66.372 0.032 66.66 ;
        RECT  0 60.972 0.032 61.26 ;
        RECT  0 55.572 0.032 55.86 ;
        RECT  0 50.172 0.032 50.46 ;
        RECT  0 44.772 0.032 45.06 ;
        RECT  0 39.372 0.032 39.66 ;
        RECT  0 33.972 0.032 34.26 ;
        RECT  0 28.572 0.032 28.86 ;
        RECT  0 23.172 0.032 23.46 ;
        RECT  0 17.772 0.032 18.06 ;
        RECT  0 12.372 0.032 12.66 ;
        RECT  0 6.972 0.032 7.26 ;
        RECT  0 1.572 0.032 1.86 ;
      LAYER M2 ;
        RECT  0 76.941 0.018 76.959 ;
        RECT  0 76.401 0.018 76.419 ;
        RECT  0 75.861 0.018 75.879 ;
        RECT  0 75.321 0.018 75.339 ;
        RECT  0 74.781 0.018 74.799 ;
        RECT  0 74.241 0.018 74.259 ;
        RECT  0 73.701 0.018 73.719 ;
        RECT  0 73.161 0.018 73.179 ;
        RECT  0 72.621 0.018 72.639 ;
        RECT  0 72.081 0.018 72.099 ;
        RECT  0 71.541 0.018 71.559 ;
        RECT  0 71.001 0.018 71.019 ;
        RECT  0 70.461 0.018 70.479 ;
        RECT  0 69.921 0.018 69.939 ;
        RECT  0 69.381 0.018 69.399 ;
        RECT  0 68.841 0.018 68.859 ;
        RECT  0 68.301 0.018 68.319 ;
        RECT  0 67.761 0.018 67.779 ;
        RECT  0 67.221 0.018 67.239 ;
        RECT  0 66.681 0.018 66.699 ;
        RECT  0 66.141 0.018 66.159 ;
        RECT  0 65.601 0.018 65.619 ;
        RECT  0 65.061 0.018 65.079 ;
        RECT  0 64.521 0.018 64.539 ;
        RECT  0 63.981 0.018 63.999 ;
        RECT  0 63.441 0.018 63.459 ;
        RECT  0 62.901 0.018 62.919 ;
        RECT  0 62.361 0.018 62.379 ;
        RECT  0 61.821 0.018 61.839 ;
        RECT  0 61.281 0.018 61.299 ;
        RECT  0 60.741 0.018 60.759 ;
        RECT  0 60.201 0.018 60.219 ;
        RECT  0 59.661 0.018 59.679 ;
        RECT  0 59.121 0.018 59.139 ;
        RECT  0 58.581 0.018 58.599 ;
        RECT  0 58.041 0.018 58.059 ;
        RECT  0 57.501 0.018 57.519 ;
        RECT  0 56.961 0.018 56.979 ;
        RECT  0 56.421 0.018 56.439 ;
        RECT  0 55.881 0.018 55.899 ;
        RECT  0 55.341 0.018 55.359 ;
        RECT  0 54.801 0.018 54.819 ;
        RECT  0 54.261 0.018 54.279 ;
        RECT  0 53.721 0.018 53.739 ;
        RECT  0 53.181 0.018 53.199 ;
        RECT  0 52.641 0.018 52.659 ;
        RECT  0 52.101 0.018 52.119 ;
        RECT  0 51.561 0.018 51.579 ;
        RECT  0 51.021 0.018 51.039 ;
        RECT  0 50.481 0.018 50.499 ;
        RECT  0 49.941 0.018 49.959 ;
        RECT  0 49.401 0.018 49.419 ;
        RECT  0 48.861 0.018 48.879 ;
        RECT  0 48.321 0.018 48.339 ;
        RECT  0 47.781 0.018 47.799 ;
        RECT  0 47.241 0.018 47.259 ;
        RECT  0 46.701 0.018 46.719 ;
        RECT  0 46.161 0.018 46.179 ;
        RECT  0 45.621 0.018 45.639 ;
        RECT  0 45.081 0.018 45.099 ;
        RECT  0 44.541 0.018 44.559 ;
        RECT  0 44.001 0.018 44.019 ;
        RECT  0 43.461 0.018 43.479 ;
        RECT  0 42.921 0.018 42.939 ;
        RECT  0 42.381 0.018 42.399 ;
        RECT  0 41.841 0.018 41.859 ;
        RECT  0 41.301 0.018 41.319 ;
        RECT  0 40.761 0.018 40.779 ;
        RECT  0 40.221 0.018 40.239 ;
        RECT  0 39.681 0.018 39.699 ;
        RECT  0 39.141 0.018 39.159 ;
        RECT  0 38.601 0.018 38.619 ;
        RECT  0 38.061 0.018 38.079 ;
        RECT  0 37.521 0.018 37.539 ;
        RECT  0 36.981 0.018 36.999 ;
        RECT  0 36.441 0.018 36.459 ;
        RECT  0 35.901 0.018 35.919 ;
        RECT  0 35.361 0.018 35.379 ;
        RECT  0 34.821 0.018 34.839 ;
        RECT  0 34.281 0.018 34.299 ;
        RECT  0 33.741 0.018 33.759 ;
        RECT  0 33.201 0.018 33.219 ;
        RECT  0 32.661 0.018 32.679 ;
        RECT  0 32.121 0.018 32.139 ;
        RECT  0 31.581 0.018 31.599 ;
        RECT  0 31.041 0.018 31.059 ;
        RECT  0 30.501 0.018 30.519 ;
        RECT  0 29.961 0.018 29.979 ;
        RECT  0 29.421 0.018 29.439 ;
        RECT  0 28.881 0.018 28.899 ;
        RECT  0 28.341 0.018 28.359 ;
        RECT  0 27.801 0.018 27.819 ;
        RECT  0 27.261 0.018 27.279 ;
        RECT  0 26.721 0.018 26.739 ;
        RECT  0 26.181 0.018 26.199 ;
        RECT  0 25.641 0.018 25.659 ;
        RECT  0 25.101 0.018 25.119 ;
        RECT  0 24.561 0.018 24.579 ;
        RECT  0 24.021 0.018 24.039 ;
        RECT  0 23.481 0.018 23.499 ;
        RECT  0 22.941 0.018 22.959 ;
        RECT  0 22.401 0.018 22.419 ;
        RECT  0 21.861 0.018 21.879 ;
        RECT  0 21.321 0.018 21.339 ;
        RECT  0 20.781 0.018 20.799 ;
        RECT  0 20.241 0.018 20.259 ;
        RECT  0 19.701 0.018 19.719 ;
        RECT  0 19.161 0.018 19.179 ;
        RECT  0 18.621 0.018 18.639 ;
        RECT  0 18.081 0.018 18.099 ;
        RECT  0 17.541 0.018 17.559 ;
        RECT  0 17.001 0.018 17.019 ;
        RECT  0 16.461 0.018 16.479 ;
        RECT  0 15.921 0.018 15.939 ;
        RECT  0 15.381 0.018 15.399 ;
        RECT  0 14.841 0.018 14.859 ;
        RECT  0 14.301 0.018 14.319 ;
        RECT  0 13.761 0.018 13.779 ;
        RECT  0 13.221 0.018 13.239 ;
        RECT  0 12.681 0.018 12.699 ;
        RECT  0 12.141 0.018 12.159 ;
        RECT  0 11.601 0.018 11.619 ;
        RECT  0 11.061 0.018 11.079 ;
        RECT  0 10.521 0.018 10.539 ;
        RECT  0 9.981 0.018 9.999 ;
        RECT  0 9.441 0.018 9.459 ;
        RECT  0 8.901 0.018 8.919 ;
        RECT  0 8.361 0.018 8.379 ;
        RECT  0 7.821 0.018 7.839 ;
        RECT  0 7.281 0.018 7.299 ;
        RECT  0 6.741 0.018 6.759 ;
        RECT  0 6.201 0.018 6.219 ;
        RECT  0 5.661 0.018 5.679 ;
        RECT  0 5.121 0.018 5.139 ;
        RECT  0 4.581 0.018 4.599 ;
        RECT  0 4.041 0.018 4.059 ;
        RECT  0 3.501 0.018 3.519 ;
        RECT  0 2.961 0.018 2.979 ;
        RECT  0 2.421 0.018 2.439 ;
        RECT  0 1.881 0.018 1.899 ;
        RECT  0 1.341 0.018 1.359 ;
        RECT  0 0.801 0.018 0.819 ;
      LAYER M1 ;
        RECT  0 76.941 0.018 76.959 ;
        RECT  0 76.401 0.018 76.419 ;
        RECT  0 75.861 0.018 75.879 ;
        RECT  0 75.321 0.018 75.339 ;
        RECT  0 74.781 0.018 74.799 ;
        RECT  0 74.241 0.018 74.259 ;
        RECT  0 73.701 0.018 73.719 ;
        RECT  0 73.161 0.018 73.179 ;
        RECT  0 72.621 0.018 72.639 ;
        RECT  0 72.081 0.018 72.099 ;
        RECT  0 71.541 0.018 71.559 ;
        RECT  0 71.001 0.018 71.019 ;
        RECT  0 70.461 0.018 70.479 ;
        RECT  0 69.921 0.018 69.939 ;
        RECT  0 69.381 0.018 69.399 ;
        RECT  0 68.841 0.018 68.859 ;
        RECT  0 68.301 0.018 68.319 ;
        RECT  0 67.761 0.018 67.779 ;
        RECT  0 67.221 0.018 67.239 ;
        RECT  0 66.681 0.018 66.699 ;
        RECT  0 66.141 0.018 66.159 ;
        RECT  0 65.601 0.018 65.619 ;
        RECT  0 65.061 0.018 65.079 ;
        RECT  0 64.521 0.018 64.539 ;
        RECT  0 63.981 0.018 63.999 ;
        RECT  0 63.441 0.018 63.459 ;
        RECT  0 62.901 0.018 62.919 ;
        RECT  0 62.361 0.018 62.379 ;
        RECT  0 61.821 0.018 61.839 ;
        RECT  0 61.281 0.018 61.299 ;
        RECT  0 60.741 0.018 60.759 ;
        RECT  0 60.201 0.018 60.219 ;
        RECT  0 59.661 0.018 59.679 ;
        RECT  0 59.121 0.018 59.139 ;
        RECT  0 58.581 0.018 58.599 ;
        RECT  0 58.041 0.018 58.059 ;
        RECT  0 57.501 0.018 57.519 ;
        RECT  0 56.961 0.018 56.979 ;
        RECT  0 56.421 0.018 56.439 ;
        RECT  0 55.881 0.018 55.899 ;
        RECT  0 55.341 0.018 55.359 ;
        RECT  0 54.801 0.018 54.819 ;
        RECT  0 54.261 0.018 54.279 ;
        RECT  0 53.721 0.018 53.739 ;
        RECT  0 53.181 0.018 53.199 ;
        RECT  0 52.641 0.018 52.659 ;
        RECT  0 52.101 0.018 52.119 ;
        RECT  0 51.561 0.018 51.579 ;
        RECT  0 51.021 0.018 51.039 ;
        RECT  0 50.481 0.018 50.499 ;
        RECT  0 49.941 0.018 49.959 ;
        RECT  0 49.401 0.018 49.419 ;
        RECT  0 48.861 0.018 48.879 ;
        RECT  0 48.321 0.018 48.339 ;
        RECT  0 47.781 0.018 47.799 ;
        RECT  0 47.241 0.018 47.259 ;
        RECT  0 46.701 0.018 46.719 ;
        RECT  0 46.161 0.018 46.179 ;
        RECT  0 45.621 0.018 45.639 ;
        RECT  0 45.081 0.018 45.099 ;
        RECT  0 44.541 0.018 44.559 ;
        RECT  0 44.001 0.018 44.019 ;
        RECT  0 43.461 0.018 43.479 ;
        RECT  0 42.921 0.018 42.939 ;
        RECT  0 42.381 0.018 42.399 ;
        RECT  0 41.841 0.018 41.859 ;
        RECT  0 41.301 0.018 41.319 ;
        RECT  0 40.761 0.018 40.779 ;
        RECT  0 40.221 0.018 40.239 ;
        RECT  0 39.681 0.018 39.699 ;
        RECT  0 39.141 0.018 39.159 ;
        RECT  0 38.601 0.018 38.619 ;
        RECT  0 38.061 0.018 38.079 ;
        RECT  0 37.521 0.018 37.539 ;
        RECT  0 36.981 0.018 36.999 ;
        RECT  0 36.441 0.018 36.459 ;
        RECT  0 35.901 0.018 35.919 ;
        RECT  0 35.361 0.018 35.379 ;
        RECT  0 34.821 0.018 34.839 ;
        RECT  0 34.281 0.018 34.299 ;
        RECT  0 33.741 0.018 33.759 ;
        RECT  0 33.201 0.018 33.219 ;
        RECT  0 32.661 0.018 32.679 ;
        RECT  0 32.121 0.018 32.139 ;
        RECT  0 31.581 0.018 31.599 ;
        RECT  0 31.041 0.018 31.059 ;
        RECT  0 30.501 0.018 30.519 ;
        RECT  0 29.961 0.018 29.979 ;
        RECT  0 29.421 0.018 29.439 ;
        RECT  0 28.881 0.018 28.899 ;
        RECT  0 28.341 0.018 28.359 ;
        RECT  0 27.801 0.018 27.819 ;
        RECT  0 27.261 0.018 27.279 ;
        RECT  0 26.721 0.018 26.739 ;
        RECT  0 26.181 0.018 26.199 ;
        RECT  0 25.641 0.018 25.659 ;
        RECT  0 25.101 0.018 25.119 ;
        RECT  0 24.561 0.018 24.579 ;
        RECT  0 24.021 0.018 24.039 ;
        RECT  0 23.481 0.018 23.499 ;
        RECT  0 22.941 0.018 22.959 ;
        RECT  0 22.401 0.018 22.419 ;
        RECT  0 21.861 0.018 21.879 ;
        RECT  0 21.321 0.018 21.339 ;
        RECT  0 20.781 0.018 20.799 ;
        RECT  0 20.241 0.018 20.259 ;
        RECT  0 19.701 0.018 19.719 ;
        RECT  0 19.161 0.018 19.179 ;
        RECT  0 18.621 0.018 18.639 ;
        RECT  0 18.081 0.018 18.099 ;
        RECT  0 17.541 0.018 17.559 ;
        RECT  0 17.001 0.018 17.019 ;
        RECT  0 16.461 0.018 16.479 ;
        RECT  0 15.921 0.018 15.939 ;
        RECT  0 15.381 0.018 15.399 ;
        RECT  0 14.841 0.018 14.859 ;
        RECT  0 14.301 0.018 14.319 ;
        RECT  0 13.761 0.018 13.779 ;
        RECT  0 13.221 0.018 13.239 ;
        RECT  0 12.681 0.018 12.699 ;
        RECT  0 12.141 0.018 12.159 ;
        RECT  0 11.601 0.018 11.619 ;
        RECT  0 11.061 0.018 11.079 ;
        RECT  0 10.521 0.018 10.539 ;
        RECT  0 9.981 0.018 9.999 ;
        RECT  0 9.441 0.018 9.459 ;
        RECT  0 8.901 0.018 8.919 ;
        RECT  0 8.361 0.018 8.379 ;
        RECT  0 7.821 0.018 7.839 ;
        RECT  0 7.281 0.018 7.299 ;
        RECT  0 6.741 0.018 6.759 ;
        RECT  0 6.201 0.018 6.219 ;
        RECT  0 5.661 0.018 5.679 ;
        RECT  0 5.121 0.018 5.139 ;
        RECT  0 4.581 0.018 4.599 ;
        RECT  0 4.041 0.018 4.059 ;
        RECT  0 3.501 0.018 3.519 ;
        RECT  0 2.961 0.018 2.979 ;
        RECT  0 2.421 0.018 2.439 ;
        RECT  0 1.881 0.018 1.899 ;
        RECT  0 1.341 0.018 1.359 ;
        RECT  0 0.801 0.018 0.819 ;
    END
  END VDD
  PIN VSS
    DIRECTION INOUT ;
    USE GROUND ;
    PORT
      LAYER M7 ;
        RECT  33.256 0.531 33.544 76.959 ;
        RECT  22.456 0.531 22.744 76.959 ;
        RECT  11.656 0.531 11.944 76.959 ;
        RECT  0.856 0.531 1.144 76.959 ;
      LAYER M6 ;
        RECT  0 76.596 0.032 76.884 ;
        RECT  0 71.196 0.032 71.484 ;
        RECT  0 65.796 0.032 66.084 ;
        RECT  0 60.396 0.032 60.684 ;
        RECT  0 54.996 0.032 55.284 ;
        RECT  0 49.596 0.032 49.884 ;
        RECT  0 44.196 0.032 44.484 ;
        RECT  0 38.796 0.032 39.084 ;
        RECT  0 33.396 0.032 33.684 ;
        RECT  0 27.996 0.032 28.284 ;
        RECT  0 22.596 0.032 22.884 ;
        RECT  0 17.196 0.032 17.484 ;
        RECT  0 11.796 0.032 12.084 ;
        RECT  0 6.396 0.032 6.684 ;
        RECT  0 0.996 0.032 1.284 ;
      LAYER M2 ;
        RECT  0 76.671 0.018 76.689 ;
        RECT  0 76.131 0.018 76.149 ;
        RECT  0 75.591 0.018 75.609 ;
        RECT  0 75.051 0.018 75.069 ;
        RECT  0 74.511 0.018 74.529 ;
        RECT  0 73.971 0.018 73.989 ;
        RECT  0 73.431 0.018 73.449 ;
        RECT  0 72.891 0.018 72.909 ;
        RECT  0 72.351 0.018 72.369 ;
        RECT  0 71.811 0.018 71.829 ;
        RECT  0 71.271 0.018 71.289 ;
        RECT  0 70.731 0.018 70.749 ;
        RECT  0 70.191 0.018 70.209 ;
        RECT  0 69.651 0.018 69.669 ;
        RECT  0 69.111 0.018 69.129 ;
        RECT  0 68.571 0.018 68.589 ;
        RECT  0 68.031 0.018 68.049 ;
        RECT  0 67.491 0.018 67.509 ;
        RECT  0 66.951 0.018 66.969 ;
        RECT  0 66.411 0.018 66.429 ;
        RECT  0 65.871 0.018 65.889 ;
        RECT  0 65.331 0.018 65.349 ;
        RECT  0 64.791 0.018 64.809 ;
        RECT  0 64.251 0.018 64.269 ;
        RECT  0 63.711 0.018 63.729 ;
        RECT  0 63.171 0.018 63.189 ;
        RECT  0 62.631 0.018 62.649 ;
        RECT  0 62.091 0.018 62.109 ;
        RECT  0 61.551 0.018 61.569 ;
        RECT  0 61.011 0.018 61.029 ;
        RECT  0 60.471 0.018 60.489 ;
        RECT  0 59.931 0.018 59.949 ;
        RECT  0 59.391 0.018 59.409 ;
        RECT  0 58.851 0.018 58.869 ;
        RECT  0 58.311 0.018 58.329 ;
        RECT  0 57.771 0.018 57.789 ;
        RECT  0 57.231 0.018 57.249 ;
        RECT  0 56.691 0.018 56.709 ;
        RECT  0 56.151 0.018 56.169 ;
        RECT  0 55.611 0.018 55.629 ;
        RECT  0 55.071 0.018 55.089 ;
        RECT  0 54.531 0.018 54.549 ;
        RECT  0 53.991 0.018 54.009 ;
        RECT  0 53.451 0.018 53.469 ;
        RECT  0 52.911 0.018 52.929 ;
        RECT  0 52.371 0.018 52.389 ;
        RECT  0 51.831 0.018 51.849 ;
        RECT  0 51.291 0.018 51.309 ;
        RECT  0 50.751 0.018 50.769 ;
        RECT  0 50.211 0.018 50.229 ;
        RECT  0 49.671 0.018 49.689 ;
        RECT  0 49.131 0.018 49.149 ;
        RECT  0 48.591 0.018 48.609 ;
        RECT  0 48.051 0.018 48.069 ;
        RECT  0 47.511 0.018 47.529 ;
        RECT  0 46.971 0.018 46.989 ;
        RECT  0 46.431 0.018 46.449 ;
        RECT  0 45.891 0.018 45.909 ;
        RECT  0 45.351 0.018 45.369 ;
        RECT  0 44.811 0.018 44.829 ;
        RECT  0 44.271 0.018 44.289 ;
        RECT  0 43.731 0.018 43.749 ;
        RECT  0 43.191 0.018 43.209 ;
        RECT  0 42.651 0.018 42.669 ;
        RECT  0 42.111 0.018 42.129 ;
        RECT  0 41.571 0.018 41.589 ;
        RECT  0 41.031 0.018 41.049 ;
        RECT  0 40.491 0.018 40.509 ;
        RECT  0 39.951 0.018 39.969 ;
        RECT  0 39.411 0.018 39.429 ;
        RECT  0 38.871 0.018 38.889 ;
        RECT  0 38.331 0.018 38.349 ;
        RECT  0 37.791 0.018 37.809 ;
        RECT  0 37.251 0.018 37.269 ;
        RECT  0 36.711 0.018 36.729 ;
        RECT  0 36.171 0.018 36.189 ;
        RECT  0 35.631 0.018 35.649 ;
        RECT  0 35.091 0.018 35.109 ;
        RECT  0 34.551 0.018 34.569 ;
        RECT  0 34.011 0.018 34.029 ;
        RECT  0 33.471 0.018 33.489 ;
        RECT  0 32.931 0.018 32.949 ;
        RECT  0 32.391 0.018 32.409 ;
        RECT  0 31.851 0.018 31.869 ;
        RECT  0 31.311 0.018 31.329 ;
        RECT  0 30.771 0.018 30.789 ;
        RECT  0 30.231 0.018 30.249 ;
        RECT  0 29.691 0.018 29.709 ;
        RECT  0 29.151 0.018 29.169 ;
        RECT  0 28.611 0.018 28.629 ;
        RECT  0 28.071 0.018 28.089 ;
        RECT  0 27.531 0.018 27.549 ;
        RECT  0 26.991 0.018 27.009 ;
        RECT  0 26.451 0.018 26.469 ;
        RECT  0 25.911 0.018 25.929 ;
        RECT  0 25.371 0.018 25.389 ;
        RECT  0 24.831 0.018 24.849 ;
        RECT  0 24.291 0.018 24.309 ;
        RECT  0 23.751 0.018 23.769 ;
        RECT  0 23.211 0.018 23.229 ;
        RECT  0 22.671 0.018 22.689 ;
        RECT  0 22.131 0.018 22.149 ;
        RECT  0 21.591 0.018 21.609 ;
        RECT  0 21.051 0.018 21.069 ;
        RECT  0 20.511 0.018 20.529 ;
        RECT  0 19.971 0.018 19.989 ;
        RECT  0 19.431 0.018 19.449 ;
        RECT  0 18.891 0.018 18.909 ;
        RECT  0 18.351 0.018 18.369 ;
        RECT  0 17.811 0.018 17.829 ;
        RECT  0 17.271 0.018 17.289 ;
        RECT  0 16.731 0.018 16.749 ;
        RECT  0 16.191 0.018 16.209 ;
        RECT  0 15.651 0.018 15.669 ;
        RECT  0 15.111 0.018 15.129 ;
        RECT  0 14.571 0.018 14.589 ;
        RECT  0 14.031 0.018 14.049 ;
        RECT  0 13.491 0.018 13.509 ;
        RECT  0 12.951 0.018 12.969 ;
        RECT  0 12.411 0.018 12.429 ;
        RECT  0 11.871 0.018 11.889 ;
        RECT  0 11.331 0.018 11.349 ;
        RECT  0 10.791 0.018 10.809 ;
        RECT  0 10.251 0.018 10.269 ;
        RECT  0 9.711 0.018 9.729 ;
        RECT  0 9.171 0.018 9.189 ;
        RECT  0 8.631 0.018 8.649 ;
        RECT  0 8.091 0.018 8.109 ;
        RECT  0 7.551 0.018 7.569 ;
        RECT  0 7.011 0.018 7.029 ;
        RECT  0 6.471 0.018 6.489 ;
        RECT  0 5.931 0.018 5.949 ;
        RECT  0 5.391 0.018 5.409 ;
        RECT  0 4.851 0.018 4.869 ;
        RECT  0 4.311 0.018 4.329 ;
        RECT  0 3.771 0.018 3.789 ;
        RECT  0 3.231 0.018 3.249 ;
        RECT  0 2.691 0.018 2.709 ;
        RECT  0 2.151 0.018 2.169 ;
        RECT  0 1.611 0.018 1.629 ;
        RECT  0 1.071 0.018 1.089 ;
        RECT  0 0.531 0.018 0.549 ;
      LAYER M1 ;
        RECT  0 76.671 0.018 76.689 ;
        RECT  0 76.131 0.018 76.149 ;
        RECT  0 75.591 0.018 75.609 ;
        RECT  0 75.051 0.018 75.069 ;
        RECT  0 74.511 0.018 74.529 ;
        RECT  0 73.971 0.018 73.989 ;
        RECT  0 73.431 0.018 73.449 ;
        RECT  0 72.891 0.018 72.909 ;
        RECT  0 72.351 0.018 72.369 ;
        RECT  0 71.811 0.018 71.829 ;
        RECT  0 71.271 0.018 71.289 ;
        RECT  0 70.731 0.018 70.749 ;
        RECT  0 70.191 0.018 70.209 ;
        RECT  0 69.651 0.018 69.669 ;
        RECT  0 69.111 0.018 69.129 ;
        RECT  0 68.571 0.018 68.589 ;
        RECT  0 68.031 0.018 68.049 ;
        RECT  0 67.491 0.018 67.509 ;
        RECT  0 66.951 0.018 66.969 ;
        RECT  0 66.411 0.018 66.429 ;
        RECT  0 65.871 0.018 65.889 ;
        RECT  0 65.331 0.018 65.349 ;
        RECT  0 64.791 0.018 64.809 ;
        RECT  0 64.251 0.018 64.269 ;
        RECT  0 63.711 0.018 63.729 ;
        RECT  0 63.171 0.018 63.189 ;
        RECT  0 62.631 0.018 62.649 ;
        RECT  0 62.091 0.018 62.109 ;
        RECT  0 61.551 0.018 61.569 ;
        RECT  0 61.011 0.018 61.029 ;
        RECT  0 60.471 0.018 60.489 ;
        RECT  0 59.931 0.018 59.949 ;
        RECT  0 59.391 0.018 59.409 ;
        RECT  0 58.851 0.018 58.869 ;
        RECT  0 58.311 0.018 58.329 ;
        RECT  0 57.771 0.018 57.789 ;
        RECT  0 57.231 0.018 57.249 ;
        RECT  0 56.691 0.018 56.709 ;
        RECT  0 56.151 0.018 56.169 ;
        RECT  0 55.611 0.018 55.629 ;
        RECT  0 55.071 0.018 55.089 ;
        RECT  0 54.531 0.018 54.549 ;
        RECT  0 53.991 0.018 54.009 ;
        RECT  0 53.451 0.018 53.469 ;
        RECT  0 52.911 0.018 52.929 ;
        RECT  0 52.371 0.018 52.389 ;
        RECT  0 51.831 0.018 51.849 ;
        RECT  0 51.291 0.018 51.309 ;
        RECT  0 50.751 0.018 50.769 ;
        RECT  0 50.211 0.018 50.229 ;
        RECT  0 49.671 0.018 49.689 ;
        RECT  0 49.131 0.018 49.149 ;
        RECT  0 48.591 0.018 48.609 ;
        RECT  0 48.051 0.018 48.069 ;
        RECT  0 47.511 0.018 47.529 ;
        RECT  0 46.971 0.018 46.989 ;
        RECT  0 46.431 0.018 46.449 ;
        RECT  0 45.891 0.018 45.909 ;
        RECT  0 45.351 0.018 45.369 ;
        RECT  0 44.811 0.018 44.829 ;
        RECT  0 44.271 0.018 44.289 ;
        RECT  0 43.731 0.018 43.749 ;
        RECT  0 43.191 0.018 43.209 ;
        RECT  0 42.651 0.018 42.669 ;
        RECT  0 42.111 0.018 42.129 ;
        RECT  0 41.571 0.018 41.589 ;
        RECT  0 41.031 0.018 41.049 ;
        RECT  0 40.491 0.018 40.509 ;
        RECT  0 39.951 0.018 39.969 ;
        RECT  0 39.411 0.018 39.429 ;
        RECT  0 38.871 0.018 38.889 ;
        RECT  0 38.331 0.018 38.349 ;
        RECT  0 37.791 0.018 37.809 ;
        RECT  0 37.251 0.018 37.269 ;
        RECT  0 36.711 0.018 36.729 ;
        RECT  0 36.171 0.018 36.189 ;
        RECT  0 35.631 0.018 35.649 ;
        RECT  0 35.091 0.018 35.109 ;
        RECT  0 34.551 0.018 34.569 ;
        RECT  0 34.011 0.018 34.029 ;
        RECT  0 33.471 0.018 33.489 ;
        RECT  0 32.931 0.018 32.949 ;
        RECT  0 32.391 0.018 32.409 ;
        RECT  0 31.851 0.018 31.869 ;
        RECT  0 31.311 0.018 31.329 ;
        RECT  0 30.771 0.018 30.789 ;
        RECT  0 30.231 0.018 30.249 ;
        RECT  0 29.691 0.018 29.709 ;
        RECT  0 29.151 0.018 29.169 ;
        RECT  0 28.611 0.018 28.629 ;
        RECT  0 28.071 0.018 28.089 ;
        RECT  0 27.531 0.018 27.549 ;
        RECT  0 26.991 0.018 27.009 ;
        RECT  0 26.451 0.018 26.469 ;
        RECT  0 25.911 0.018 25.929 ;
        RECT  0 25.371 0.018 25.389 ;
        RECT  0 24.831 0.018 24.849 ;
        RECT  0 24.291 0.018 24.309 ;
        RECT  0 23.751 0.018 23.769 ;
        RECT  0 23.211 0.018 23.229 ;
        RECT  0 22.671 0.018 22.689 ;
        RECT  0 22.131 0.018 22.149 ;
        RECT  0 21.591 0.018 21.609 ;
        RECT  0 21.051 0.018 21.069 ;
        RECT  0 20.511 0.018 20.529 ;
        RECT  0 19.971 0.018 19.989 ;
        RECT  0 19.431 0.018 19.449 ;
        RECT  0 18.891 0.018 18.909 ;
        RECT  0 18.351 0.018 18.369 ;
        RECT  0 17.811 0.018 17.829 ;
        RECT  0 17.271 0.018 17.289 ;
        RECT  0 16.731 0.018 16.749 ;
        RECT  0 16.191 0.018 16.209 ;
        RECT  0 15.651 0.018 15.669 ;
        RECT  0 15.111 0.018 15.129 ;
        RECT  0 14.571 0.018 14.589 ;
        RECT  0 14.031 0.018 14.049 ;
        RECT  0 13.491 0.018 13.509 ;
        RECT  0 12.951 0.018 12.969 ;
        RECT  0 12.411 0.018 12.429 ;
        RECT  0 11.871 0.018 11.889 ;
        RECT  0 11.331 0.018 11.349 ;
        RECT  0 10.791 0.018 10.809 ;
        RECT  0 10.251 0.018 10.269 ;
        RECT  0 9.711 0.018 9.729 ;
        RECT  0 9.171 0.018 9.189 ;
        RECT  0 8.631 0.018 8.649 ;
        RECT  0 8.091 0.018 8.109 ;
        RECT  0 7.551 0.018 7.569 ;
        RECT  0 7.011 0.018 7.029 ;
        RECT  0 6.471 0.018 6.489 ;
        RECT  0 5.931 0.018 5.949 ;
        RECT  0 5.391 0.018 5.409 ;
        RECT  0 4.851 0.018 4.869 ;
        RECT  0 4.311 0.018 4.329 ;
        RECT  0 3.771 0.018 3.789 ;
        RECT  0 3.231 0.018 3.249 ;
        RECT  0 2.691 0.018 2.709 ;
        RECT  0 2.151 0.018 2.169 ;
        RECT  0 1.611 0.018 1.629 ;
        RECT  0 1.071 0.018 1.089 ;
        RECT  0 0.531 0.018 0.549 ;
    END
  END VSS
  OBS
    LAYER RVTN ;
     RECT  0 0.54 39.258 0.675 ;
     RECT  0 0.945 39.258 1.215 ;
     RECT  0 1.485 39.258 1.755 ;
     RECT  0 2.025 39.258 2.295 ;
     RECT  0 2.565 39.258 2.835 ;
     RECT  0 3.105 39.258 3.375 ;
     RECT  0 3.645 39.258 3.915 ;
     RECT  0 4.185 39.258 4.455 ;
     RECT  0 4.725 39.258 4.995 ;
     RECT  0 5.265 39.258 5.535 ;
     RECT  0 5.805 39.258 6.075 ;
     RECT  0 6.345 39.258 6.615 ;
     RECT  0 6.885 39.258 7.155 ;
     RECT  0 7.425 39.258 7.695 ;
     RECT  0 7.965 39.258 8.235 ;
     RECT  0 8.505 39.258 8.775 ;
     RECT  0 9.045 39.258 9.315 ;
     RECT  0 9.585 39.258 9.855 ;
     RECT  0 10.125 39.258 10.395 ;
     RECT  0 10.665 39.258 10.935 ;
     RECT  0 11.205 39.258 11.475 ;
     RECT  0 11.745 39.258 12.015 ;
     RECT  0 12.285 39.258 12.555 ;
     RECT  0 12.825 39.258 13.095 ;
     RECT  0 13.365 39.258 13.635 ;
     RECT  0 13.905 39.258 14.175 ;
     RECT  0 14.445 39.258 14.715 ;
     RECT  0 14.985 39.258 15.255 ;
     RECT  0 15.525 39.258 15.795 ;
     RECT  0 16.065 39.258 16.335 ;
     RECT  0 16.605 39.258 16.875 ;
     RECT  0 17.145 39.258 17.415 ;
     RECT  0 17.685 39.258 17.955 ;
     RECT  0 18.225 39.258 18.495 ;
     RECT  0 18.765 39.258 19.035 ;
     RECT  0 19.305 39.258 19.575 ;
     RECT  0 19.845 39.258 20.115 ;
     RECT  0 20.385 39.258 20.655 ;
     RECT  0 20.925 39.258 21.195 ;
     RECT  0 21.465 39.258 21.735 ;
     RECT  0 22.005 39.258 22.275 ;
     RECT  0 22.545 39.258 22.815 ;
     RECT  0 23.085 39.258 23.355 ;
     RECT  0 23.625 39.258 23.895 ;
     RECT  0 24.165 39.258 24.435 ;
     RECT  0 24.705 39.258 24.975 ;
     RECT  0 25.245 39.258 25.515 ;
     RECT  0 25.785 39.258 26.055 ;
     RECT  0 26.325 39.258 26.595 ;
     RECT  0 26.865 39.258 27.135 ;
     RECT  0 27.405 39.258 27.675 ;
     RECT  0 27.945 39.258 28.215 ;
     RECT  0 28.485 39.258 28.755 ;
     RECT  0 29.025 39.258 29.295 ;
     RECT  0 29.565 39.258 29.835 ;
     RECT  0 30.105 39.258 30.375 ;
     RECT  0 30.645 39.258 30.915 ;
     RECT  0 31.185 39.258 31.455 ;
     RECT  0 31.725 39.258 31.995 ;
     RECT  0 32.265 39.258 32.535 ;
     RECT  0 32.805 39.258 33.075 ;
     RECT  0 33.345 39.258 33.615 ;
     RECT  0 33.885 39.258 34.155 ;
     RECT  0 34.425 39.258 34.695 ;
     RECT  0 34.965 39.258 35.235 ;
     RECT  0 35.505 39.258 35.775 ;
     RECT  0 36.045 39.258 36.315 ;
     RECT  0 36.585 39.258 36.855 ;
     RECT  0 37.125 39.258 37.395 ;
     RECT  0 37.665 39.258 37.935 ;
     RECT  0 38.205 39.258 38.475 ;
     RECT  0 38.745 39.258 39.015 ;
     RECT  0 39.285 39.258 39.555 ;
     RECT  0 39.825 39.258 40.095 ;
     RECT  0 40.365 39.258 40.635 ;
     RECT  0 40.905 39.258 41.175 ;
     RECT  0 41.445 39.258 41.715 ;
     RECT  0 41.985 39.258 42.255 ;
     RECT  0 42.525 39.258 42.795 ;
     RECT  0 43.065 39.258 43.335 ;
     RECT  0 43.605 39.258 43.875 ;
     RECT  0 44.145 39.258 44.415 ;
     RECT  0 44.685 39.258 44.955 ;
     RECT  0 45.225 39.258 45.495 ;
     RECT  0 45.765 39.258 46.035 ;
     RECT  0 46.305 39.258 46.575 ;
     RECT  0 46.845 39.258 47.115 ;
     RECT  0 47.385 39.258 47.655 ;
     RECT  0 47.925 39.258 48.195 ;
     RECT  0 48.465 39.258 48.735 ;
     RECT  0 49.005 39.258 49.275 ;
     RECT  0 49.545 39.258 49.815 ;
     RECT  0 50.085 39.258 50.355 ;
     RECT  0 50.625 39.258 50.895 ;
     RECT  0 51.165 39.258 51.435 ;
     RECT  0 51.705 39.258 51.975 ;
     RECT  0 52.245 39.258 52.515 ;
     RECT  0 52.785 39.258 53.055 ;
     RECT  0 53.325 39.258 53.595 ;
     RECT  0 53.865 39.258 54.135 ;
     RECT  0 54.405 39.258 54.675 ;
     RECT  0 54.945 39.258 55.215 ;
     RECT  0 55.485 39.258 55.755 ;
     RECT  0 56.025 39.258 56.295 ;
     RECT  0 56.565 39.258 56.835 ;
     RECT  0 57.105 39.258 57.375 ;
     RECT  0 57.645 39.258 57.915 ;
     RECT  0 58.185 39.258 58.455 ;
     RECT  0 58.725 39.258 58.995 ;
     RECT  0 59.265 39.258 59.535 ;
     RECT  0 59.805 39.258 60.075 ;
     RECT  0 60.345 39.258 60.615 ;
     RECT  0 60.885 39.258 61.155 ;
     RECT  0 61.425 39.258 61.695 ;
     RECT  0 61.965 39.258 62.235 ;
     RECT  0 62.505 39.258 62.775 ;
     RECT  0 63.045 39.258 63.315 ;
     RECT  0 63.585 39.258 63.855 ;
     RECT  0 64.125 39.258 64.395 ;
     RECT  0 64.665 39.258 64.935 ;
     RECT  0 65.205 39.258 65.475 ;
     RECT  0 65.745 39.258 66.015 ;
     RECT  0 66.285 39.258 66.555 ;
     RECT  0 66.825 39.258 67.095 ;
     RECT  0 67.365 39.258 67.635 ;
     RECT  0 67.905 39.258 68.175 ;
     RECT  0 68.445 39.258 68.715 ;
     RECT  0 68.985 39.258 69.255 ;
     RECT  0 69.525 39.258 69.795 ;
     RECT  0 70.065 39.258 70.335 ;
     RECT  0 70.605 39.258 70.875 ;
     RECT  0 71.145 39.258 71.415 ;
     RECT  0 71.685 39.258 71.955 ;
     RECT  0 72.225 39.258 72.495 ;
     RECT  0 72.765 39.258 73.035 ;
     RECT  0 73.305 39.258 73.575 ;
     RECT  0 73.845 39.258 74.115 ;
     RECT  0 74.385 39.258 74.655 ;
     RECT  0 74.925 39.258 75.195 ;
     RECT  0 75.465 39.258 75.735 ;
     RECT  0 76.005 39.258 76.275 ;
     RECT  0 76.545 39.258 76.815 ;
    LAYER RVTP ;
     RECT  0 0.675 39.258 0.945 ;
     RECT  0 1.215 39.258 1.485 ;
     RECT  0 1.755 39.258 2.025 ;
     RECT  0 2.295 39.258 2.565 ;
     RECT  0 2.835 39.258 3.105 ;
     RECT  0 3.375 39.258 3.645 ;
     RECT  0 3.915 39.258 4.185 ;
     RECT  0 4.455 39.258 4.725 ;
     RECT  0 4.995 39.258 5.265 ;
     RECT  0 5.535 39.258 5.805 ;
     RECT  0 6.075 39.258 6.345 ;
     RECT  0 6.615 39.258 6.885 ;
     RECT  0 7.155 39.258 7.425 ;
     RECT  0 7.695 39.258 7.965 ;
     RECT  0 8.235 39.258 8.505 ;
     RECT  0 8.775 39.258 9.045 ;
     RECT  0 9.315 39.258 9.585 ;
     RECT  0 9.855 39.258 10.125 ;
     RECT  0 10.395 39.258 10.665 ;
     RECT  0 10.935 39.258 11.205 ;
     RECT  0 11.475 39.258 11.745 ;
     RECT  0 12.015 39.258 12.285 ;
     RECT  0 12.555 39.258 12.825 ;
     RECT  0 13.095 39.258 13.365 ;
     RECT  0 13.635 39.258 13.905 ;
     RECT  0 14.175 39.258 14.445 ;
     RECT  0 14.715 39.258 14.985 ;
     RECT  0 15.255 39.258 15.525 ;
     RECT  0 15.795 39.258 16.065 ;
     RECT  0 16.335 39.258 16.605 ;
     RECT  0 16.875 39.258 17.145 ;
     RECT  0 17.415 39.258 17.685 ;
     RECT  0 17.955 39.258 18.225 ;
     RECT  0 18.495 39.258 18.765 ;
     RECT  0 19.035 39.258 19.305 ;
     RECT  0 19.575 39.258 19.845 ;
     RECT  0 20.115 39.258 20.385 ;
     RECT  0 20.655 39.258 20.925 ;
     RECT  0 21.195 39.258 21.465 ;
     RECT  0 21.735 39.258 22.005 ;
     RECT  0 22.275 39.258 22.545 ;
     RECT  0 22.815 39.258 23.085 ;
     RECT  0 23.355 39.258 23.625 ;
     RECT  0 23.895 39.258 24.165 ;
     RECT  0 24.435 39.258 24.705 ;
     RECT  0 24.975 39.258 25.245 ;
     RECT  0 25.515 39.258 25.785 ;
     RECT  0 26.055 39.258 26.325 ;
     RECT  0 26.595 39.258 26.865 ;
     RECT  0 27.135 39.258 27.405 ;
     RECT  0 27.675 39.258 27.945 ;
     RECT  0 28.215 39.258 28.485 ;
     RECT  0 28.755 39.258 29.025 ;
     RECT  0 29.295 39.258 29.565 ;
     RECT  0 29.835 39.258 30.105 ;
     RECT  0 30.375 39.258 30.645 ;
     RECT  0 30.915 39.258 31.185 ;
     RECT  0 31.455 39.258 31.725 ;
     RECT  0 31.995 39.258 32.265 ;
     RECT  0 32.535 39.258 32.805 ;
     RECT  0 33.075 39.258 33.345 ;
     RECT  0 33.615 39.258 33.885 ;
     RECT  0 34.155 39.258 34.425 ;
     RECT  0 34.695 39.258 34.965 ;
     RECT  0 35.235 39.258 35.505 ;
     RECT  0 35.775 39.258 36.045 ;
     RECT  0 36.315 39.258 36.585 ;
     RECT  0 36.855 39.258 37.125 ;
     RECT  0 37.395 39.258 37.665 ;
     RECT  0 37.935 39.258 38.205 ;
     RECT  0 38.475 39.258 38.745 ;
     RECT  0 39.015 39.258 39.285 ;
     RECT  0 39.555 39.258 39.825 ;
     RECT  0 40.095 39.258 40.365 ;
     RECT  0 40.635 39.258 40.905 ;
     RECT  0 41.175 39.258 41.445 ;
     RECT  0 41.715 39.258 41.985 ;
     RECT  0 42.255 39.258 42.525 ;
     RECT  0 42.795 39.258 43.065 ;
     RECT  0 43.335 39.258 43.605 ;
     RECT  0 43.875 39.258 44.145 ;
     RECT  0 44.415 39.258 44.685 ;
     RECT  0 44.955 39.258 45.225 ;
     RECT  0 45.495 39.258 45.765 ;
     RECT  0 46.035 39.258 46.305 ;
     RECT  0 46.575 39.258 46.845 ;
     RECT  0 47.115 39.258 47.385 ;
     RECT  0 47.655 39.258 47.925 ;
     RECT  0 48.195 39.258 48.465 ;
     RECT  0 48.735 39.258 49.005 ;
     RECT  0 49.275 39.258 49.545 ;
     RECT  0 49.815 39.258 50.085 ;
     RECT  0 50.355 39.258 50.625 ;
     RECT  0 50.895 39.258 51.165 ;
     RECT  0 51.435 39.258 51.705 ;
     RECT  0 51.975 39.258 52.245 ;
     RECT  0 52.515 39.258 52.785 ;
     RECT  0 53.055 39.258 53.325 ;
     RECT  0 53.595 39.258 53.865 ;
     RECT  0 54.135 39.258 54.405 ;
     RECT  0 54.675 39.258 54.945 ;
     RECT  0 55.215 39.258 55.485 ;
     RECT  0 55.755 39.258 56.025 ;
     RECT  0 56.295 39.258 56.565 ;
     RECT  0 56.835 39.258 57.105 ;
     RECT  0 57.375 39.258 57.645 ;
     RECT  0 57.915 39.258 58.185 ;
     RECT  0 58.455 39.258 58.725 ;
     RECT  0 58.995 39.258 59.265 ;
     RECT  0 59.535 39.258 59.805 ;
     RECT  0 60.075 39.258 60.345 ;
     RECT  0 60.615 39.258 60.885 ;
     RECT  0 61.155 39.258 61.425 ;
     RECT  0 61.695 39.258 61.965 ;
     RECT  0 62.235 39.258 62.505 ;
     RECT  0 62.775 39.258 63.045 ;
     RECT  0 63.315 39.258 63.585 ;
     RECT  0 63.855 39.258 64.125 ;
     RECT  0 64.395 39.258 64.665 ;
     RECT  0 64.935 39.258 65.205 ;
     RECT  0 65.475 39.258 65.745 ;
     RECT  0 66.015 39.258 66.285 ;
     RECT  0 66.555 39.258 66.825 ;
     RECT  0 67.095 39.258 67.365 ;
     RECT  0 67.635 39.258 67.905 ;
     RECT  0 68.175 39.258 68.445 ;
     RECT  0 68.715 39.258 68.985 ;
     RECT  0 69.255 39.258 69.525 ;
     RECT  0 69.795 39.258 70.065 ;
     RECT  0 70.335 39.258 70.605 ;
     RECT  0 70.875 39.258 71.145 ;
     RECT  0 71.415 39.258 71.685 ;
     RECT  0 71.955 39.258 72.225 ;
     RECT  0 72.495 39.258 72.765 ;
     RECT  0 73.035 39.258 73.305 ;
     RECT  0 73.575 39.258 73.845 ;
     RECT  0 74.115 39.258 74.385 ;
     RECT  0 74.655 39.258 74.925 ;
     RECT  0 75.195 39.258 75.465 ;
     RECT  0 75.735 39.258 76.005 ;
     RECT  0 76.275 39.258 76.545 ;
     RECT  0 76.815 39.258 76.95 ;
    LAYER M1 ;
     RECT  0 0.531 39.258 76.959 ;
    LAYER M2 ;
     RECT  0 0.531 5.647 76.959 ;
     RECT  5.647 0.531 6.107 77.184 ;
     RECT  6.107 0.531 11.191 76.959 ;
     RECT  11.191 0.531 11.291 77.04 ;
     RECT  11.291 0.531 16.339 76.959 ;
     RECT  16.339 0.45 16.511 76.959 ;
     RECT  16.511 0.531 17.635 76.959 ;
     RECT  17.635 0.45 18.167 76.959 ;
     RECT  18.167 0.531 19.507 76.959 ;
     RECT  19.507 0.45 21.983 76.959 ;
     RECT  21.983 0.531 23.827 76.959 ;
     RECT  23.827 0.216 25.051 76.959 ;
     RECT  25.051 0.144 25.123 76.959 ;
     RECT  25.123 0.144 25.331 77.382 ;
     RECT  25.331 0.144 25.403 76.959 ;
     RECT  25.403 0.531 27.139 76.959 ;
     RECT  27.139 0.486 27.455 76.959 ;
     RECT  27.455 0.531 30.811 76.959 ;
     RECT  30.811 0.45 30.947 76.959 ;
     RECT  30.947 0.531 33.367 76.959 ;
     RECT  33.367 0.036 37.643 76.959 ;
     RECT  37.643 0.306 38.471 76.959 ;
     RECT  38.471 0.531 39.258 76.959 ;
    LAYER M3 ;
     RECT  33.372 0.031 33.39 0.043 ;
     RECT  24.084 0.043 24.318 0.091 ;
     RECT  25.56 0.091 25.578 0.133 ;
     RECT  16.956 0.091 16.974 0.139 ;
     RECT  20.232 0.043 20.25 0.139 ;
     RECT  22.536 0.043 22.554 0.139 ;
     RECT  25.38 0.133 25.578 0.139 ;
     RECT  26.64 0.043 26.766 0.139 ;
     RECT  28.008 0.043 28.026 0.139 ;
     RECT  31.536 0.091 31.554 0.139 ;
     RECT  37.62 0.031 37.638 0.139 ;
     RECT  15.336 0.091 15.354 0.187 ;
     RECT  16.524 0.139 16.974 0.187 ;
     RECT  17.82 0.043 17.838 0.187 ;
     RECT  22.068 0.139 22.662 0.187 ;
     RECT  23.58 0.091 24.318 0.187 ;
     RECT  25.056 0.139 25.578 0.187 ;
     RECT  26.64 0.139 28.062 0.187 ;
     RECT  28.8 0.091 28.818 0.187 ;
     RECT  31.104 0.139 31.554 0.187 ;
     RECT  32.904 0.043 33.39 0.187 ;
     RECT  36.9 0.139 38.106 0.187 ;
     RECT  15.3 0.187 15.75 0.235 ;
     RECT  21.996 0.187 22.77 0.235 ;
     RECT  23.58 0.187 25.578 0.235 ;
     RECT  26.64 0.187 28.818 0.235 ;
     RECT  30.96 0.187 33.39 0.235 ;
     RECT  35.64 0.043 35.658 0.235 ;
     RECT  36.648 0.187 38.106 0.235 ;
     RECT  14.184 0.139 14.202 0.283 ;
     RECT  15.12 0.235 15.75 0.283 ;
     RECT  16.524 0.187 17.838 0.283 ;
     RECT  20.232 0.139 20.97 0.283 ;
     RECT  21.996 0.235 28.818 0.283 ;
     RECT  29.844 0.043 29.862 0.283 ;
     RECT  30.96 0.235 33.462 0.283 ;
     RECT  34.488 0.235 34.506 0.283 ;
     RECT  35.64 0.235 38.106 0.283 ;
     RECT  35.64 0.283 38.358 0.301 ;
     RECT  14.184 0.283 17.838 0.331 ;
     RECT  20.124 0.283 34.866 0.331 ;
     RECT  35.64 0.301 38.466 0.331 ;
     RECT  20.124 0.331 38.466 0.379 ;
     RECT  20.124 0.379 38.502 0.445 ;
     RECT  14.184 0.331 18.234 0.523 ;
     RECT  19.512 0.445 38.502 0.523 ;
     RECT  14.184 0.523 18.45 0.571 ;
     RECT  19.224 0.523 38.502 0.571 ;
     RECT  0.255 0.523 0.345 0.793 ;
     RECT  5.655 0.523 5.745 0.793 ;
     RECT  11.055 0.523 11.145 0.793 ;
     RECT  11.055 0.793 11.337 0.859 ;
     RECT  14.184 0.571 38.502 0.989 ;
     RECT  13.392 1.489 13.41 1.579 ;
     RECT  14.184 0.989 38.466 1.579 ;
     RECT  12.312 1.099 12.33 1.723 ;
     RECT  13.392 1.579 38.466 1.723 ;
     RECT  10.512 0.859 11.337 2.101 ;
     RECT  10.44 2.101 11.337 2.251 ;
     RECT  12.312 1.723 38.466 2.251 ;
     RECT  12.312 2.251 38.538 2.489 ;
     RECT  9.936 2.251 11.337 2.605 ;
     RECT  9.396 2.605 11.337 2.759 ;
     RECT  9.576 2.759 11.337 2.939 ;
     RECT  12.312 2.489 38.466 3.181 ;
     RECT  9.648 2.939 11.337 5.305 ;
     RECT  9.576 5.305 11.337 5.611 ;
     RECT  12.168 3.181 38.466 5.611 ;
     RECT  8.64 5.605 8.658 5.645 ;
     RECT  9.576 5.611 38.466 6.781 ;
     RECT  9.324 6.781 38.466 6.809 ;
     RECT  9.324 6.809 11.337 8.005 ;
     RECT  8.964 8.005 11.337 8.159 ;
     RECT  9.288 8.159 11.337 8.491 ;
     RECT  12.168 6.809 38.466 8.491 ;
     RECT  9.288 8.491 38.466 8.537 ;
     RECT  7.776 9.751 7.794 9.821 ;
     RECT  12.168 8.537 38.466 9.823 ;
     RECT  12.06 9.823 38.466 9.869 ;
     RECT  7.308 9.925 7.326 9.965 ;
     RECT  9.288 8.537 11.337 11.281 ;
     RECT  12.204 9.869 38.466 11.281 ;
     RECT  8.28 12.811 8.298 13.019 ;
     RECT  5.655 0.793 5.937 13.945 ;
     RECT  7.092 13.063 7.11 13.945 ;
     RECT  5.655 13.945 7.11 14.099 ;
     RECT  5.655 14.099 5.937 14.107 ;
     RECT  9.288 11.281 38.466 14.299 ;
     RECT  8.64 14.299 38.466 14.573 ;
     RECT  9.252 14.573 38.466 14.639 ;
     RECT  9.288 14.639 38.466 14.981 ;
     RECT  10.332 14.981 38.466 15.629 ;
     RECT  8.244 14.791 8.262 15.727 ;
     RECT  9.288 14.981 9.594 15.871 ;
     RECT  10.332 15.629 38.43 15.871 ;
     RECT  7.848 15.727 8.262 16.219 ;
     RECT  9.288 15.871 38.43 16.219 ;
     RECT  7.092 14.099 7.11 16.501 ;
     RECT  7.848 16.219 38.43 16.501 ;
     RECT  7.092 16.501 38.43 16.529 ;
     RECT  5.472 14.107 5.937 16.951 ;
     RECT  5.004 16.951 5.937 17.041 ;
     RECT  7.092 16.529 8.262 17.041 ;
     RECT  9.216 16.529 38.43 17.645 ;
     RECT  5.004 17.041 8.262 17.653 ;
     RECT  9.216 17.645 38.337 17.653 ;
     RECT  3.6 21.001 3.618 21.127 ;
     RECT  3.6 21.127 4.05 22.711 ;
     RECT  3.6 22.711 4.158 23.431 ;
     RECT  5.004 17.653 38.337 23.431 ;
     RECT  3.6 23.431 38.337 23.885 ;
     RECT  3.6 23.885 4.05 24.403 ;
     RECT  2.88 24.403 4.05 25.591 ;
     RECT  5.004 23.885 38.337 25.591 ;
     RECT  2.88 25.591 38.337 27.103 ;
     RECT  2.232 27.103 38.337 31.891 ;
     RECT  2.196 31.891 38.337 41.021 ;
     RECT  2.196 41.021 19.818 41.791 ;
     RECT  20.7 41.021 38.337 41.791 ;
     RECT  2.196 41.791 38.337 42.179 ;
     RECT  2.196 42.179 23.778 42.449 ;
     RECT  20.736 42.449 23.778 43.501 ;
     RECT  24.696 42.179 38.337 43.501 ;
     RECT  20.736 43.501 38.337 43.661 ;
     RECT  2.196 42.449 19.494 43.915 ;
     RECT  2.196 43.915 19.926 44.311 ;
     RECT  20.736 43.661 23.778 44.311 ;
     RECT  2.196 44.311 23.778 45.157 ;
     RECT  24.696 43.661 38.337 45.157 ;
     RECT  2.196 45.157 38.337 45.427 ;
     RECT  1.98 45.427 38.337 45.959 ;
     RECT  1.98 45.959 23.778 46.921 ;
     RECT  1.98 46.921 23.958 47.695 ;
     RECT  1.404 47.695 23.958 47.899 ;
     RECT  24.696 45.959 38.337 47.899 ;
     RECT  1.404 47.899 38.337 50.549 ;
     RECT  35.604 50.549 38.337 51.629 ;
     RECT  37.296 51.629 38.337 51.899 ;
     RECT  1.404 50.549 34.866 51.931 ;
     RECT  35.604 51.629 36.45 51.931 ;
     RECT  0.255 0.793 0.537 52.285 ;
     RECT  1.404 51.931 36.45 52.285 ;
     RECT  0.255 52.285 36.45 53.051 ;
     RECT  0.255 53.051 34.614 53.555 ;
     RECT  35.46 53.051 36.45 54.103 ;
     RECT  0.255 53.555 34.146 54.329 ;
     RECT  0.255 54.329 30.222 55.381 ;
     RECT  31.032 54.329 34.146 55.831 ;
     RECT  0.255 55.381 30.258 55.901 ;
     RECT  1.404 55.901 30.258 55.912 ;
     RECT  31.032 55.831 34.218 55.912 ;
     RECT  1.404 55.912 34.218 55.949 ;
     RECT  0.255 55.901 0.537 56.875 ;
     RECT  1.404 55.949 30.222 56.875 ;
     RECT  34.956 54.103 36.45 57.451 ;
     RECT  34.956 57.451 36.558 57.485 ;
     RECT  0.255 56.875 30.222 57.541 ;
     RECT  31.032 55.949 34.218 57.569 ;
     RECT  0.255 57.541 30.258 57.721 ;
     RECT  31.032 57.569 32.994 57.721 ;
     RECT  0.255 57.721 32.994 57.947 ;
     RECT  36.432 57.485 36.558 58.649 ;
     RECT  33.732 57.569 34.218 58.657 ;
     RECT  34.956 57.485 35.514 58.657 ;
     RECT  0.255 57.947 30.258 58.721 ;
     RECT  31.032 57.947 32.994 58.757 ;
     RECT  36.432 58.649 36.486 58.829 ;
     RECT  32.616 58.757 32.994 59.071 ;
     RECT  33.732 58.657 35.514 59.071 ;
     RECT  0.255 58.721 30.222 59.117 ;
     RECT  32.616 59.071 35.514 59.275 ;
     RECT  36.432 58.829 36.45 59.275 ;
     RECT  32.616 59.275 36.45 59.459 ;
     RECT  32.616 59.459 36.234 59.495 ;
     RECT  37.296 51.899 37.314 59.611 ;
     RECT  37.152 59.611 37.314 60.341 ;
     RECT  1.404 59.117 30.222 60.385 ;
     RECT  32.616 59.495 35.514 60.413 ;
     RECT  31.032 58.757 31.842 61.087 ;
     RECT  32.616 60.413 32.994 61.087 ;
     RECT  31.032 61.087 32.994 61.133 ;
     RECT  32.655 61.133 32.994 61.231 ;
     RECT  34.128 60.413 35.514 61.231 ;
     RECT  31.032 61.133 31.842 61.349 ;
     RECT  32.655 61.231 35.514 61.349 ;
     RECT  1.404 60.385 30.258 62.155 ;
     RECT  31.176 61.349 31.842 62.155 ;
     RECT  34.128 61.349 35.514 62.231 ;
     RECT  0.255 59.117 0.537 63.247 ;
     RECT  1.404 62.155 31.842 63.247 ;
     RECT  0.255 63.247 31.842 63.625 ;
     RECT  0.255 63.625 31.878 63.677 ;
     RECT  32.655 61.349 32.994 63.883 ;
     RECT  32.655 63.883 33.03 64.049 ;
     RECT  34.128 62.231 34.974 64.291 ;
     RECT  34.128 64.291 35.19 64.397 ;
     RECT  34.128 64.397 34.866 64.459 ;
     RECT  33.912 64.459 34.866 64.589 ;
     RECT  34.2 64.589 34.866 64.733 ;
     RECT  32.655 64.049 32.937 65.281 ;
     RECT  37.296 60.341 37.314 65.309 ;
     RECT  32.655 65.281 33.102 65.399 ;
     RECT  34.2 64.733 34.47 65.551 ;
     RECT  0.255 63.677 31.842 66.479 ;
     RECT  0.255 66.479 20.574 66.701 ;
     RECT  21.42 66.479 31.842 66.991 ;
     RECT  32.655 65.399 32.937 66.991 ;
     RECT  21.42 66.991 32.937 67.675 ;
     RECT  21.42 67.675 33.03 67.829 ;
     RECT  29.448 67.829 32.937 68.909 ;
     RECT  29.484 68.909 32.937 69.179 ;
     RECT  0.255 66.701 20.394 69.493 ;
     RECT  21.42 67.829 28.638 69.493 ;
     RECT  29.52 69.179 32.937 69.719 ;
     RECT  33.804 65.551 34.47 69.899 ;
     RECT  29.916 69.719 32.937 71.609 ;
     RECT  29.916 71.609 31.338 71.789 ;
     RECT  33.876 69.899 34.47 71.951 ;
     RECT  0.255 69.493 28.638 72.959 ;
     RECT  29.916 71.789 30.906 73.579 ;
     RECT  32.184 71.609 32.937 73.579 ;
     RECT  0.255 72.959 18.738 73.849 ;
     RECT  19.476 72.959 28.638 73.849 ;
     RECT  0.255 73.849 28.638 73.921 ;
     RECT  0.255 73.921 28.926 74.039 ;
     RECT  29.916 73.579 31.374 74.039 ;
     RECT  32.184 73.579 33.138 74.039 ;
     RECT  29.916 74.039 31.338 74.219 ;
     RECT  0.255 74.039 28.782 74.615 ;
     RECT  29.988 74.219 31.338 74.849 ;
     RECT  30.456 74.849 31.338 74.885 ;
     RECT  30.456 74.885 30.906 74.993 ;
     RECT  33.876 71.951 33.894 75.155 ;
     RECT  30.456 74.993 30.87 75.191 ;
     RECT  0.255 74.615 28.206 75.227 ;
     RECT  26.496 75.227 28.206 75.245 ;
     RECT  0.255 75.227 25.758 75.389 ;
     RECT  26.676 75.245 28.206 75.389 ;
     RECT  29.052 75.091 29.07 75.425 ;
     RECT  32.184 74.039 32.937 75.461 ;
     RECT  26.748 75.389 28.206 75.497 ;
     RECT  30.852 75.191 30.87 76.109 ;
     RECT  0.255 75.389 25.686 76.469 ;
     RECT  34.452 75.271 34.47 76.541 ;
     RECT  30.78 76.507 30.798 76.637 ;
     RECT  0.255 76.469 23.814 76.697 ;
     RECT  32.655 75.461 32.937 76.697 ;
     RECT  38.055 51.899 38.337 76.697 ;
     RECT  0.447 76.697 23.814 76.733 ;
     RECT  26.748 75.497 27.918 76.781 ;
     RECT  0.447 76.733 14.922 76.829 ;
     RECT  27.432 76.781 27.918 76.877 ;
     RECT  24.696 76.469 25.686 76.925 ;
     RECT  0.447 76.829 14.886 76.967 ;
     RECT  27.447 76.877 27.918 76.967 ;
     RECT  32.847 76.697 32.937 76.967 ;
     RECT  38.247 76.697 38.337 76.967 ;
     RECT  1.224 76.967 14.886 76.973 ;
     RECT  16.02 76.733 23.814 76.973 ;
     RECT  24.876 76.925 25.686 76.973 ;
     RECT  2.088 76.973 7.614 77.021 ;
     RECT  8.496 76.973 14.886 77.021 ;
     RECT  2.088 77.021 7.434 77.069 ;
     RECT  10.476 77.021 14.886 77.069 ;
     RECT  27.9 76.967 27.918 77.069 ;
     RECT  2.088 77.069 2.862 77.117 ;
     RECT  3.636 77.069 3.69 77.117 ;
     RECT  4.572 77.069 7.434 77.117 ;
     RECT  2.088 77.117 2.106 77.165 ;
     RECT  10.8 77.069 14.886 77.213 ;
     RECT  18.792 76.973 23.598 77.213 ;
     RECT  3.672 77.117 3.69 77.261 ;
     RECT  10.8 77.213 13.986 77.261 ;
     RECT  18.792 77.213 23.346 77.261 ;
     RECT  2.844 77.117 2.862 77.309 ;
     RECT  4.572 77.117 6.858 77.309 ;
     RECT  8.532 77.021 9.378 77.309 ;
     RECT  11.952 77.261 12.438 77.309 ;
     RECT  16.02 76.973 17.838 77.309 ;
     RECT  18.792 77.261 22.482 77.309 ;
     RECT  13.32 77.261 13.986 77.357 ;
     RECT  18.792 77.309 22.446 77.357 ;
     RECT  4.572 77.309 4.59 77.405 ;
     RECT  10.8 77.261 10.998 77.405 ;
     RECT  14.76 77.213 14.886 77.405 ;
     RECT  16.02 77.309 16.866 77.405 ;
     RECT  18.792 77.357 19.35 77.405 ;
     RECT  23.328 77.261 23.346 77.405 ;
     RECT  25.056 76.973 25.686 77.405 ;
     RECT  9.144 77.309 9.378 77.453 ;
     RECT  10.8 77.405 10.818 77.453 ;
     RECT  16.02 77.405 16.614 77.453 ;
     RECT  25.092 77.405 25.686 77.453 ;
     RECT  11.952 77.309 12.114 77.501 ;
     RECT  14.832 77.405 14.886 77.501 ;
     RECT  25.092 77.453 25.146 77.501 ;
     RECT  5.796 77.309 6.858 77.549 ;
     RECT  12.096 77.501 12.114 77.549 ;
     RECT  20.34 77.357 22.446 77.549 ;
     RECT  9.144 77.453 9.234 77.597 ;
     RECT  13.32 77.357 13.338 77.597 ;
     RECT  14.868 77.501 14.886 77.597 ;
     RECT  21.06 77.549 21.078 77.597 ;
     RECT  5.796 77.549 5.814 77.645 ;
     RECT  6.84 77.549 6.858 77.645 ;
     RECT  9.216 77.597 9.234 77.645 ;
     RECT  16.416 77.453 16.434 77.645 ;
     RECT  18.864 77.405 18.882 77.645 ;
     RECT  25.092 77.501 25.11 77.645 ;
    LAYER M4 ;
     RECT  0.248 0.528 0.352 76.692 ;
     RECT  0.352 0.798 0.44 76.692 ;
     RECT  0.44 0.798 0.544 76.962 ;
     RECT  0.544 76.608 0.997 76.962 ;
     RECT  0.544 55.248 1.145 55.896 ;
     RECT  0.544 59.088 1.145 59.208 ;
     RECT  0.544 71.808 1.469 71.832 ;
     RECT  1.145 55.248 1.573 55.848 ;
     RECT  1.145 59.184 1.637 59.208 ;
     RECT  1.637 59.184 1.717 59.256 ;
     RECT  0.544 50.4 1.721 50.424 ;
     RECT  1.573 55.152 1.721 55.848 ;
     RECT  0.544 67.776 1.721 67.8 ;
     RECT  0.544 61.824 1.813 62.424 ;
     RECT  0.997 76.608 1.897 77.112 ;
     RECT  0.544 52.416 2.045 53.256 ;
     RECT  1.717 59.184 2.045 59.64 ;
     RECT  1.897 76.368 2.077 77.112 ;
     RECT  2.077 76.368 2.245 77.16 ;
     RECT  2.045 52.992 2.585 53.256 ;
     RECT  2.581 66.96 2.629 66.984 ;
     RECT  0.544 57.168 2.773 57.192 ;
     RECT  2.045 59.28 2.821 59.64 ;
     RECT  1.813 60.96 2.821 62.424 ;
     RECT  2.245 75.504 2.833 77.16 ;
     RECT  2.78 32.352 2.867 32.376 ;
     RECT  2.773 56.688 2.869 57.192 ;
     RECT  2.869 56.352 2.965 57.192 ;
     RECT  2.833 75.504 3.013 77.304 ;
     RECT  2.585 52.992 3.02 53.016 ;
     RECT  1.721 55.152 3.061 55.176 ;
     RECT  3.02 52.944 3.157 53.016 ;
     RECT  3.116 33.36 3.203 33.384 ;
     RECT  3.013 74.688 3.203 77.304 ;
     RECT  2.629 66.096 3.205 66.984 ;
     RECT  3.061 55.152 3.413 55.272 ;
     RECT  2.965 56.304 3.413 57.192 ;
     RECT  3.157 41.376 3.443 41.4 ;
     RECT  2.905 50.688 3.443 50.712 ;
     RECT  3.413 55.152 3.449 55.176 ;
     RECT  3.301 69.504 3.781 69.528 ;
     RECT  3.205 66.096 3.809 67.272 ;
     RECT  3.781 69.504 3.877 70.104 ;
     RECT  3.877 50.544 3.961 50.568 ;
     RECT  3.809 66.96 3.973 67.272 ;
     RECT  2.821 59.28 3.989 62.424 ;
     RECT  3.877 68.976 3.989 70.104 ;
     RECT  3.973 66.96 4.021 67.848 ;
     RECT  3.989 68.976 4.021 69 ;
     RECT  3.157 52.896 4.057 53.016 ;
     RECT  3.973 41.04 4.133 41.064 ;
     RECT  4.129 22.752 4.213 22.776 ;
     RECT  4.057 52.512 4.307 53.016 ;
     RECT  4.069 64.992 4.309 65.016 ;
     RECT  4.309 64.416 4.313 65.016 ;
     RECT  4.093 45.648 4.373 45.672 ;
     RECT  3.596 23.856 4.429 23.88 ;
     RECT  3.989 59.808 4.453 62.424 ;
     RECT  4.373 45.648 4.457 46.248 ;
     RECT  4.313 64.416 4.457 64.44 ;
     RECT  4.457 45.648 4.489 45.672 ;
     RECT  3.203 75.12 4.489 77.304 ;
     RECT  4.021 66.96 4.529 69 ;
     RECT  4.307 52.896 4.549 53.016 ;
     RECT  4.489 74.592 4.561 77.304 ;
     RECT  4.549 52.896 4.565 53.064 ;
     RECT  3.413 56.304 4.565 56.712 ;
     RECT  4.453 59.808 4.565 63.288 ;
     RECT  4.489 45.216 4.573 45.672 ;
     RECT  4.309 31.152 4.597 31.176 ;
     RECT  4.561 58.656 4.645 58.68 ;
     RECT  4.565 53.04 4.673 53.064 ;
     RECT  4.597 31.152 5.036 31.416 ;
     RECT  4.561 74.592 5.077 77.4 ;
     RECT  5.269 64.368 5.365 64.392 ;
     RECT  5.468 21.312 5.489 21.336 ;
     RECT  4.573 45.648 5.497 45.672 ;
     RECT  5.269 46.8 5.497 46.824 ;
     RECT  4.453 28.992 5.509 29.016 ;
     RECT  5.509 14.208 5.648 14.232 ;
     RECT  5.489 21.312 5.648 21.576 ;
     RECT  5.276 25.824 5.648 25.848 ;
     RECT  5.276 27.408 5.648 27.432 ;
     RECT  5.509 28.992 5.648 29.592 ;
     RECT  5.036 31.152 5.648 31.896 ;
     RECT  5.413 35.664 5.648 35.688 ;
     RECT  5.125 37.68 5.648 37.704 ;
     RECT  5.497 45.648 5.648 46.824 ;
     RECT  5.137 48.48 5.648 48.504 ;
     RECT  5.269 50.688 5.648 50.712 ;
     RECT  5.509 53.088 5.648 53.112 ;
     RECT  4.844 54.528 5.648 54.552 ;
     RECT  4.565 56.304 5.648 56.376 ;
     RECT  5.497 58.224 5.648 58.248 ;
     RECT  4.565 60.096 5.648 63.288 ;
     RECT  5.365 64.32 5.648 64.392 ;
     RECT  4.529 66.96 5.648 68.376 ;
     RECT  3.989 70.08 5.648 70.104 ;
     RECT  4.549 71.712 5.648 71.736 ;
     RECT  5.077 74.592 5.648 77.448 ;
     RECT  5.648 0.528 5.752 77.448 ;
     RECT  5.752 0.798 5.785 77.448 ;
     RECT  5.785 0.798 5.944 77.64 ;
     RECT  5.944 30.96 6.083 31.416 ;
     RECT  5.944 33.12 6.083 33.912 ;
     RECT  5.944 54.192 6.083 54.216 ;
     RECT  5.944 56.304 6.113 56.376 ;
     RECT  6.083 33.12 6.121 33.144 ;
     RECT  5.944 25.296 6.172 25.32 ;
     RECT  5.944 41.472 6.221 41.496 ;
     RECT  5.944 67.776 6.221 72.456 ;
     RECT  5.944 45.936 6.275 45.96 ;
     RECT  5.944 18.384 6.323 19.176 ;
     RECT  5.944 27.84 6.364 27.864 ;
     RECT  6.113 56.352 6.545 56.376 ;
     RECT  6.221 67.776 6.653 71.256 ;
     RECT  5.944 28.992 6.659 29.592 ;
     RECT  5.944 50.592 6.659 50.76 ;
     RECT  5.944 17.088 6.707 17.112 ;
     RECT  6.323 18.384 6.748 18.408 ;
     RECT  6.083 31.152 6.755 31.416 ;
     RECT  5.944 74.064 6.803 77.64 ;
     RECT  5.944 61.44 6.833 65.544 ;
     RECT  6.221 72.432 6.833 72.456 ;
     RECT  6.803 74.784 6.869 77.64 ;
     RECT  5.944 58.896 6.949 59.304 ;
     RECT  6.833 62.736 6.995 65.544 ;
     RECT  6.659 50.736 7.049 50.76 ;
     RECT  6.833 61.44 7.139 61.656 ;
     RECT  7.045 41.04 7.157 41.064 ;
     RECT  7.045 42.768 7.157 42.792 ;
     RECT  7.045 66.672 7.193 66.696 ;
     RECT  7.141 54.96 7.228 54.984 ;
     RECT  6.973 58.8 7.235 58.824 ;
     RECT  7.093 17.04 7.244 17.064 ;
     RECT  7.244 16.8 7.333 17.064 ;
     RECT  7.253 58.704 7.337 58.728 ;
     RECT  6.995 65.52 7.337 65.544 ;
     RECT  7.285 9.936 7.372 9.96 ;
     RECT  6.973 43.92 7.379 43.944 ;
     RECT  6.653 68.16 7.409 71.256 ;
     RECT  7.333 16.608 7.417 17.064 ;
     RECT  7.34 49.056 7.427 49.08 ;
     RECT  7.405 42.624 7.523 42.648 ;
     RECT  6.995 62.736 7.597 64.104 ;
     RECT  6.659 28.992 7.621 29.016 ;
     RECT  7.139 61.44 7.625 61.608 ;
     RECT  7.625 61.584 7.769 61.608 ;
     RECT  7.621 28.992 7.772 29.688 ;
     RECT  6.755 31.152 7.772 31.176 ;
     RECT  7.765 45.264 7.801 45.288 ;
     RECT  7.333 73.584 7.813 73.608 ;
     RECT  6.869 74.784 7.813 77.448 ;
     RECT  7.765 37.584 7.852 37.608 ;
     RECT  7.765 56.112 7.852 56.136 ;
     RECT  7.772 28.992 7.859 31.176 ;
     RECT  7.429 24.96 7.861 24.984 ;
     RECT  7.801 45.264 7.885 46.152 ;
     RECT  7.861 39.888 7.948 39.912 ;
     RECT  7.861 24.96 7.949 25.08 ;
     RECT  7.765 9.792 8.003 9.816 ;
     RECT  7.859 31.152 8.089 31.176 ;
     RECT  8.005 41.136 8.092 41.16 ;
     RECT  7.957 20.88 8.093 20.904 ;
     RECT  8.053 37.104 8.137 37.128 ;
     RECT  7.859 28.992 8.14 29.4 ;
     RECT  7.957 22.992 8.165 23.016 ;
     RECT  8.117 54.864 8.201 54.888 ;
     RECT  7.813 73.584 8.245 77.448 ;
     RECT  7.409 68.16 8.291 69.048 ;
     RECT  8.269 12.816 8.353 12.84 ;
     RECT  8.377 48.48 8.461 48.504 ;
     RECT  8.396 58.08 8.483 58.104 ;
     RECT  7.417 17.04 8.493 17.064 ;
     RECT  8.444 43.248 8.531 43.272 ;
     RECT  7.949 24.96 8.533 24.984 ;
     RECT  8.485 49.968 8.557 49.992 ;
     RECT  8.557 49.968 8.569 50.04 ;
     RECT  5.944 14.544 8.581 14.568 ;
     RECT  8.569 50.016 8.593 50.04 ;
     RECT  8.533 21.936 8.633 21.96 ;
     RECT  8.14 28.992 8.636 29.016 ;
     RECT  7.885 45.264 8.641 45.672 ;
     RECT  8.588 5.616 8.675 5.64 ;
     RECT  8.636 28.848 8.723 29.016 ;
     RECT  8.593 50.016 8.741 50.808 ;
     RECT  7.597 63.264 8.741 64.104 ;
     RECT  8.725 52.368 8.812 52.392 ;
     RECT  8.581 14.304 8.849 14.568 ;
     RECT  8.533 35.136 8.849 35.16 ;
     RECT  8.291 68.16 8.849 68.664 ;
     RECT  8.773 40.176 8.86 41.064 ;
     RECT  8.809 55.92 8.915 55.944 ;
     RECT  8.741 63.312 8.965 64.104 ;
     RECT  8.86 41.04 8.993 41.064 ;
     RECT  8.953 39.984 9.025 40.008 ;
     RECT  9.025 39.36 9.037 40.008 ;
     RECT  8.965 63.312 9.052 64.728 ;
     RECT  8.809 45.168 9.059 45.192 ;
     RECT  8.493 16.224 9.061 17.064 ;
     RECT  8.629 26.736 9.061 26.76 ;
     RECT  8.533 24.384 9.065 24.984 ;
     RECT  8.917 34.848 9.089 34.872 ;
     RECT  9.061 15.936 9.107 17.064 ;
     RECT  9.089 34.608 9.107 34.872 ;
     RECT  9.037 39.36 9.109 39.384 ;
     RECT  8.245 72.912 9.133 77.448 ;
     RECT  8.723 28.992 9.169 29.016 ;
     RECT  9.107 34.608 9.173 34.632 ;
     RECT  9.107 17.04 9.205 17.064 ;
     RECT  9.133 72.912 9.205 77.592 ;
     RECT  8.089 31.152 9.209 31.896 ;
     RECT  9.133 35.904 9.217 35.928 ;
     RECT  7.409 70.368 9.253 71.256 ;
     RECT  9.205 72.912 9.253 77.64 ;
     RECT  9.109 23.04 9.277 23.064 ;
     RECT  9.205 43.152 9.292 43.176 ;
     RECT  9.277 22.8 9.389 23.064 ;
     RECT  9.061 26.208 9.397 26.76 ;
     RECT  9.301 27.936 9.397 27.96 ;
     RECT  8.732 66.432 9.397 66.456 ;
     RECT  9.397 66.144 9.421 66.456 ;
     RECT  9.404 67.44 9.421 67.464 ;
     RECT  9.107 15.936 9.425 15.96 ;
     RECT  9.389 23.04 9.461 23.064 ;
     RECT  9.397 26.208 9.484 27.96 ;
     RECT  9.421 66.144 9.491 67.464 ;
     RECT  9.413 42.768 9.497 42.792 ;
     RECT  9.493 34.416 9.577 34.44 ;
     RECT  9.349 11.952 9.637 11.976 ;
     RECT  9.484 26.208 9.677 26.808 ;
     RECT  8.437 62.16 9.677 62.232 ;
     RECT  8.849 14.304 9.683 14.328 ;
     RECT  9.601 49.968 9.685 49.992 ;
     RECT  9.637 11.952 9.721 12.216 ;
     RECT  9.644 6.192 9.731 6.216 ;
     RECT  9.701 55.392 9.785 55.416 ;
     RECT  9.709 23.568 9.793 23.592 ;
     RECT  9.673 51.936 9.845 51.96 ;
     RECT  9.491 66.144 9.893 66.504 ;
     RECT  9.677 62.16 9.901 62.184 ;
     RECT  9.836 53.52 9.923 53.544 ;
     RECT  9.065 24.96 9.929 24.984 ;
     RECT  9.845 51.936 9.929 52.536 ;
     RECT  9.877 2.256 9.965 2.28 ;
     RECT  9.889 58.704 10.073 58.728 ;
     RECT  9.721 11.952 10.172 11.976 ;
     RECT  8.849 68.64 10.261 68.664 ;
     RECT  9.052 63.312 10.405 64.488 ;
     RECT  9.893 66.144 10.405 66.168 ;
     RECT  9.884 42.432 10.501 42.456 ;
     RECT  10.261 67.728 10.501 68.664 ;
     RECT  9.997 50.736 10.508 50.76 ;
     RECT  9.929 51.936 10.508 51.96 ;
     RECT  9.253 70.368 10.549 77.64 ;
     RECT  10.549 3.312 10.597 3.336 ;
     RECT  10.597 22.176 10.604 22.2 ;
     RECT  10.597 3.312 10.609 4.296 ;
     RECT  10.565 39.84 10.609 39.864 ;
     RECT  9.169 28.992 10.645 29.112 ;
     RECT  9.565 46.896 10.645 46.92 ;
     RECT  9.484 27.936 10.717 27.96 ;
     RECT  9.997 18.288 10.825 18.696 ;
     RECT  10.604 22.176 10.825 22.488 ;
     RECT  10.405 63.312 10.825 66.168 ;
     RECT  10.825 18.288 10.837 18.84 ;
     RECT  10.825 21.312 10.837 22.488 ;
     RECT  9.209 31.152 10.837 31.416 ;
     RECT  10.501 42.432 10.853 42.792 ;
     RECT  10.837 31.152 10.861 31.8 ;
     RECT  10.309 57.072 10.861 57.096 ;
     RECT  10.825 62.448 10.861 66.168 ;
     RECT  10.501 67.728 10.885 69.24 ;
     RECT  10.549 70.272 10.885 77.64 ;
     RECT  10.861 57.072 10.897 57.144 ;
     RECT  10.609 39.6 10.925 39.864 ;
     RECT  9.997 9.168 10.933 9.192 ;
     RECT  10.837 18.288 10.933 18.936 ;
     RECT  10.861 62.448 10.969 66.216 ;
     RECT  10.501 0.864 11.048 0.888 ;
     RECT  10.609 2.736 11.048 4.296 ;
     RECT  10.837 6.816 11.048 6.84 ;
     RECT  10.933 9.168 11.048 9.624 ;
     RECT  10.172 11.856 11.048 11.976 ;
     RECT  10.925 15.024 11.048 15.048 ;
     RECT  9.205 17.04 11.048 17.16 ;
     RECT  10.933 18.288 11.048 19.368 ;
     RECT  10.837 20.88 11.048 22.488 ;
     RECT  9.677 26.208 11.048 26.568 ;
     RECT  10.717 27.6 11.048 27.96 ;
     RECT  10.645 28.992 11.048 29.688 ;
     RECT  10.861 30.768 11.048 31.8 ;
     RECT  10.364 32.832 11.048 32.856 ;
     RECT  10.645 34.752 11.048 34.776 ;
     RECT  10.933 37.584 11.048 37.608 ;
     RECT  10.925 39.6 11.048 40.584 ;
     RECT  10.853 42.192 11.048 42.792 ;
     RECT  10.645 46.896 11.048 47.064 ;
     RECT  10.508 50.736 11.048 51.96 ;
     RECT  10.789 53.04 11.048 53.16 ;
     RECT  10.213 54.768 11.048 54.792 ;
     RECT  10.897 57.024 11.048 57.144 ;
     RECT  10.825 59.376 11.048 59.4 ;
     RECT  10.969 62.448 11.048 66.696 ;
     RECT  10.885 67.728 11.048 77.64 ;
     RECT  11.048 0.528 11.152 77.64 ;
     RECT  11.152 0.798 11.344 77.64 ;
     RECT  11.344 30.768 11.405 32.52 ;
     RECT  11.344 27.6 11.441 27.624 ;
     RECT  11.344 36.816 11.441 38.184 ;
     RECT  11.405 31.152 11.459 32.52 ;
     RECT  11.441 38.16 11.459 38.184 ;
     RECT  11.344 59.28 11.459 59.304 ;
     RECT  11.344 8.496 11.477 8.52 ;
     RECT  11.344 39.6 11.477 39.912 ;
     RECT  11.344 60.768 11.485 60.792 ;
     RECT  11.344 68.064 11.485 77.64 ;
     RECT  11.344 6.576 11.548 6.84 ;
     RECT  11.344 26.256 11.657 26.568 ;
     RECT  11.344 54.768 11.729 55.128 ;
     RECT  11.344 17.136 11.765 18.312 ;
     RECT  11.344 24.288 11.837 24.696 ;
     RECT  11.765 17.136 11.873 17.736 ;
     RECT  11.344 28.992 11.909 29.16 ;
     RECT  11.344 57.552 11.909 57.672 ;
     RECT  11.344 63.312 11.981 65.304 ;
     RECT  11.657 26.256 11.987 26.28 ;
     RECT  11.344 46.512 11.987 47.304 ;
     RECT  11.344 49.968 11.987 49.992 ;
     RECT  11.909 57.552 11.987 57.576 ;
     RECT  11.485 68.448 11.987 77.64 ;
     RECT  11.344 15.456 12.025 16.056 ;
     RECT  11.344 9.84 12.089 9.864 ;
     RECT  11.344 51.36 12.089 51.384 ;
     RECT  11.441 36.816 12.172 36.84 ;
     RECT  11.344 56.4 12.179 56.424 ;
     RECT  11.344 45.408 12.269 45.432 ;
     RECT  11.344 33.648 12.277 33.672 ;
     RECT  11.344 3.36 12.316 3.432 ;
     RECT  11.987 68.448 12.341 72.168 ;
     RECT  11.873 17.136 12.349 17.16 ;
     RECT  11.987 46.8 12.38 47.304 ;
     RECT  11.837 24.672 12.413 24.696 ;
     RECT  12.38 46.8 12.413 48.12 ;
     RECT  12.373 27.408 12.457 27.432 ;
     RECT  12.413 46.848 12.467 48.12 ;
     RECT  11.477 39.888 12.481 39.912 ;
     RECT  12.409 45.216 12.493 45.24 ;
     RECT  12.316 3.36 12.517 3.384 ;
     RECT  12.437 38.256 12.517 38.28 ;
     RECT  12.517 38.256 12.521 38.808 ;
     RECT  12.467 46.848 12.529 47.832 ;
     RECT  12.409 19.44 12.563 19.464 ;
     RECT  11.459 31.152 12.563 31.848 ;
     RECT  11.344 62.256 12.563 62.28 ;
     RECT  12.563 31.152 12.565 31.416 ;
     RECT  12.517 13.536 12.604 13.56 ;
     RECT  11.344 0.864 12.661 1.128 ;
     RECT  11.981 63.792 12.661 65.304 ;
     RECT  12.689 56.448 12.773 56.472 ;
     RECT  12.709 42.432 12.796 42.456 ;
     RECT  12.697 20.592 12.803 20.616 ;
     RECT  12.716 24.912 12.803 24.936 ;
     RECT  12.625 34.752 12.809 34.776 ;
     RECT  12.341 69.216 12.809 72.168 ;
     RECT  12.565 61.008 12.845 61.032 ;
     RECT  11.909 28.992 12.949 29.016 ;
     RECT  12.517 2.784 12.953 3.384 ;
     RECT  12.521 38.784 12.989 38.808 ;
     RECT  12.757 62.16 12.989 62.184 ;
     RECT  12.613 66.672 13.025 66.696 ;
     RECT  12.949 28.32 13.036 29.016 ;
     RECT  13.004 4.512 13.091 4.536 ;
     RECT  12.949 57.024 13.091 57.048 ;
     RECT  12.025 16.032 13.093 16.056 ;
     RECT  13.036 28.992 13.093 29.016 ;
     RECT  12.661 63.792 13.129 65.544 ;
     RECT  13.045 50.976 13.132 51 ;
     RECT  12.565 31.152 13.165 31.176 ;
     RECT  13.085 22.368 13.169 22.392 ;
     RECT  12.805 26.784 13.189 26.808 ;
     RECT  13.093 28.992 13.205 29.064 ;
     RECT  13.148 58.032 13.235 58.056 ;
     RECT  13.093 41.664 13.276 42.216 ;
     RECT  13.189 26.736 13.277 26.808 ;
     RECT  13.093 15.984 13.292 16.056 ;
     RECT  13.165 37.2 13.331 37.704 ;
     RECT  12.529 46.896 13.379 47.832 ;
     RECT  13.205 28.992 13.385 29.016 ;
     RECT  13.333 60.288 13.42 60.312 ;
     RECT  12.661 0.528 13.453 1.128 ;
     RECT  13.129 63.312 13.457 65.544 ;
     RECT  13.429 49.488 13.516 49.512 ;
     RECT  13.276 41.616 13.529 42.216 ;
     RECT  13.292 15.984 13.561 16.2 ;
     RECT  13.477 19.152 13.565 19.176 ;
     RECT  13.457 63.312 13.565 65.256 ;
     RECT  11.548 6.816 13.621 6.84 ;
     RECT  13.381 33.12 13.621 33.144 ;
     RECT  13.379 46.896 13.645 47.208 ;
     RECT  13.565 63.312 13.66 64.968 ;
     RECT  13.561 15.984 13.667 16.632 ;
     RECT  13.621 32.448 13.667 33.144 ;
     RECT  13.561 34.992 13.667 35.448 ;
     RECT  13.331 37.2 13.667 37.224 ;
     RECT  13.345 14.304 13.669 14.328 ;
     RECT  12.481 39.888 13.669 40.008 ;
     RECT  13.148 43.728 13.669 43.752 ;
     RECT  12.809 71.616 13.669 72.168 ;
     RECT  13.667 32.448 13.708 32.472 ;
     RECT  13.667 34.992 13.708 35.016 ;
     RECT  13.621 6.432 13.709 6.84 ;
     RECT  13.453 0.528 13.717 1.608 ;
     RECT  13.525 61.488 13.753 62.088 ;
     RECT  13.345 21.12 13.765 21.144 ;
     RECT  13.669 39.216 13.765 40.008 ;
     RECT  13.669 14.112 13.781 14.328 ;
     RECT  13.717 0.48 13.813 1.608 ;
     RECT  13.765 21.12 13.852 21.576 ;
     RECT  13.765 39.216 13.852 40.92 ;
     RECT  13.669 43.728 13.859 43.944 ;
     RECT  13.66 63.312 13.885 63.816 ;
     RECT  13.82 27.6 13.907 27.624 ;
     RECT  13.861 20.928 13.948 20.952 ;
     RECT  13.813 0.384 13.957 1.608 ;
     RECT  13.916 18.624 13.957 18.888 ;
     RECT  13.957 0.288 13.964 1.608 ;
     RECT  12.953 2.832 13.964 3.384 ;
     RECT  13.957 17.712 14.003 18.888 ;
     RECT  13.957 67.296 14.041 67.32 ;
     RECT  13.667 16.608 14.053 16.632 ;
     RECT  14.003 17.712 14.053 17.736 ;
     RECT  13.669 71.616 14.069 72.216 ;
     RECT  14.053 16.608 14.099 17.736 ;
     RECT  13.561 51.408 14.137 51.432 ;
     RECT  13.993 36.24 14.14 36.312 ;
     RECT  14.029 14.832 14.141 14.856 ;
     RECT  13.964 0.288 14.173 3.384 ;
     RECT  14.101 57.648 14.185 57.672 ;
     RECT  14.197 9.648 14.237 9.672 ;
     RECT  13.852 39.216 14.243 40.584 ;
     RECT  13.529 42.192 14.243 42.216 ;
     RECT  14.137 43.344 14.243 43.56 ;
     RECT  14.137 50.784 14.243 51.432 ;
     RECT  13.885 63.216 14.243 63.816 ;
     RECT  14.173 0.144 14.245 3.384 ;
     RECT  14.237 8.688 14.245 9.672 ;
     RECT  14.245 8.448 14.284 9.672 ;
     RECT  14.284 8.448 14.321 8.712 ;
     RECT  14.237 11.472 14.321 11.496 ;
     RECT  14.003 18.864 14.329 18.888 ;
     RECT  14.273 57.024 14.357 57.048 ;
     RECT  14.243 43.536 14.435 43.56 ;
     RECT  14.245 12.72 14.437 12.744 ;
     RECT  14.389 20.496 14.476 20.52 ;
     RECT  13.093 23.808 14.485 23.832 ;
     RECT  13.165 30.528 14.492 31.176 ;
     RECT  14.492 29.76 14.497 31.176 ;
     RECT  14.243 39.216 14.533 39.912 ;
     RECT  14.245 0.144 14.537 3.72 ;
     RECT  14.485 24.912 14.572 24.936 ;
     RECT  14.321 8.448 14.573 8.472 ;
     RECT  14.492 22.128 14.579 22.152 ;
     RECT  14.492 51.552 14.579 51.576 ;
     RECT  14.425 53.616 14.605 53.64 ;
     RECT  14.099 17.088 14.617 17.736 ;
     RECT  14.533 39.168 14.627 39.912 ;
     RECT  14.485 23.712 14.629 23.832 ;
     RECT  14.629 23.712 14.677 24.312 ;
     RECT  13.645 47.184 14.681 47.208 ;
     RECT  14.597 59.28 14.681 59.304 ;
     RECT  13.66 64.944 14.681 64.968 ;
     RECT  14.149 6 14.713 6.024 ;
     RECT  14.677 23.52 14.716 24.312 ;
     RECT  14.716 23.52 14.764 24.12 ;
     RECT  14.437 12.24 14.789 12.744 ;
     RECT  14.497 29.232 14.819 31.176 ;
     RECT  14.461 49.056 14.819 49.08 ;
     RECT  14.533 61.392 14.819 61.416 ;
     RECT  14.396 26.4 14.821 26.424 ;
     RECT  14.741 47.04 14.825 47.064 ;
     RECT  14.243 63.792 14.825 63.816 ;
     RECT  14.819 30.768 14.861 31.176 ;
     RECT  14.821 60.288 14.908 60.312 ;
     RECT  14.317 34.416 14.917 34.44 ;
     RECT  14.917 46.8 15.004 46.824 ;
     RECT  14.617 17.712 15.011 17.736 ;
     RECT  11.987 73.248 15.077 77.64 ;
     RECT  14.713 5.088 15.155 6.024 ;
     RECT  14.14 36.288 15.221 36.312 ;
     RECT  14.789 12.24 15.251 12.264 ;
     RECT  14.821 26.4 15.293 26.472 ;
     RECT  14.537 0.144 15.325 3.432 ;
     RECT  14.821 13.824 15.325 13.848 ;
     RECT  14.605 53.52 15.356 53.64 ;
     RECT  15.145 49.968 15.395 49.992 ;
     RECT  15.308 57.264 15.395 57.288 ;
     RECT  15.289 58.704 15.395 58.728 ;
     RECT  15.181 64.464 15.395 64.488 ;
     RECT  14.819 29.232 15.397 29.544 ;
     RECT  14.108 45.648 15.397 45.672 ;
     RECT  12.809 69.216 15.401 70.536 ;
     RECT  15.077 73.968 15.401 77.64 ;
     RECT  15.325 13.68 15.409 13.848 ;
     RECT  15.157 65.52 15.437 65.544 ;
     RECT  15.389 8.976 15.473 9 ;
     RECT  15.397 28.992 15.481 29.544 ;
     RECT  14.917 34.416 15.481 34.632 ;
     RECT  15.356 53.52 15.541 53.976 ;
     RECT  14.965 42.144 15.577 42.168 ;
     RECT  15.577 42.144 15.644 42.216 ;
     RECT  15.397 25.824 15.821 25.848 ;
     RECT  15.821 41.04 15.829 41.064 ;
     RECT  15.644 42.048 15.829 42.216 ;
     RECT  14.627 39.888 15.865 39.912 ;
     RECT  15.325 0.096 15.877 3.432 ;
     RECT  15.481 29.088 15.877 29.544 ;
     RECT  15.155 5.664 15.884 6.024 ;
     RECT  15.788 14.064 15.893 14.088 ;
     RECT  15.74 48.384 15.932 48.408 ;
     RECT  15.217 22.8 15.973 22.824 ;
     RECT  14.764 24.096 15.973 24.12 ;
     RECT  15.685 62.736 15.973 62.76 ;
     RECT  15.973 19.776 16.045 19.8 ;
     RECT  15.973 22.8 16.261 24.12 ;
     RECT  15.541 53.088 16.289 53.976 ;
     RECT  16.289 53.088 16.297 54.216 ;
     RECT  15.877 61.584 16.297 61.608 ;
     RECT  15.973 62.736 16.297 63.528 ;
     RECT  15.973 18.432 16.309 18.456 ;
     RECT  16.045 19.776 16.309 20.568 ;
     RECT  15.877 29.088 16.309 29.688 ;
     RECT  15.973 38.64 16.309 38.664 ;
     RECT  15.865 39.744 16.309 39.912 ;
     RECT  15.401 74.16 16.445 77.64 ;
     RECT  15.877 0.096 16.448 4.152 ;
     RECT  15.884 5.664 16.448 6.408 ;
     RECT  15.404 10.56 16.448 10.584 ;
     RECT  15.893 14.064 16.448 14.856 ;
     RECT  15.865 17.088 16.448 17.112 ;
     RECT  16.309 18.432 16.448 20.568 ;
     RECT  16.261 22.56 16.448 24.12 ;
     RECT  15.821 25.68 16.448 25.848 ;
     RECT  16.153 27.936 16.448 27.96 ;
     RECT  16.309 29.088 16.448 29.832 ;
     RECT  14.861 31.152 16.448 31.176 ;
     RECT  15.901 35.328 16.448 35.88 ;
     RECT  16.309 38.64 16.448 39.912 ;
     RECT  15.829 41.04 16.448 42.216 ;
     RECT  16.309 44.16 16.448 44.184 ;
     RECT  15.397 45.648 16.448 45.816 ;
     RECT  15.932 48.288 16.448 48.408 ;
     RECT  15.973 50.592 16.448 50.616 ;
     RECT  16.297 53.088 16.448 54.312 ;
     RECT  16.253 55.968 16.448 55.992 ;
     RECT  16.253 58.224 16.448 58.248 ;
     RECT  15.397 59.76 16.448 59.784 ;
     RECT  16.297 61.584 16.448 63.528 ;
     RECT  15.401 69.792 16.448 70.536 ;
     RECT  14.069 72.144 16.448 72.216 ;
     RECT  16.445 74.16 16.448 77.592 ;
     RECT  16.448 0.096 16.744 77.592 ;
     RECT  16.744 69.792 16.841 70.392 ;
     RECT  16.744 6.144 16.883 8.376 ;
     RECT  16.744 13.392 16.883 14.088 ;
     RECT  16.744 32.208 16.883 32.472 ;
     RECT  16.744 44.16 16.885 47.88 ;
     RECT  16.744 16.224 16.913 16.248 ;
     RECT  16.744 41.616 16.913 41.736 ;
     RECT  16.744 18.144 16.921 24.456 ;
     RECT  16.913 41.616 16.921 41.64 ;
     RECT  16.883 6.144 16.985 7.128 ;
     RECT  16.744 10.32 17.021 10.344 ;
     RECT  16.744 43.152 17.021 43.176 ;
     RECT  16.744 74.592 17.075 77.592 ;
     RECT  17.075 74.64 17.093 77.592 ;
     RECT  16.921 21.744 17.123 24.456 ;
     RECT  16.744 66.672 17.123 67.56 ;
     RECT  16.744 0.096 17.165 4.152 ;
     RECT  16.744 63.216 17.267 64.872 ;
     RECT  16.744 56.352 17.273 56.376 ;
     RECT  16.744 37.68 17.507 38.424 ;
     RECT  16.885 44.16 17.555 46.392 ;
     RECT  16.744 52.992 17.561 54.6 ;
     RECT  16.921 18.144 17.603 20.616 ;
     RECT  16.744 50.688 17.633 50.76 ;
     RECT  17.507 38.4 17.651 38.424 ;
     RECT  16.744 58.08 17.651 58.104 ;
     RECT  16.744 71.808 17.651 73.56 ;
     RECT  17.603 18.144 17.669 20.184 ;
     RECT  16.744 27.696 17.669 28.968 ;
     RECT  17.555 46.224 17.669 46.392 ;
     RECT  16.744 25.872 17.692 25.896 ;
     RECT  17.123 22.56 17.705 24.456 ;
     RECT  17.669 27.696 17.705 27.96 ;
     RECT  17.561 54.576 17.705 54.6 ;
     RECT  17.561 52.992 17.74 53.4 ;
     RECT  16.744 61.248 17.74 61.272 ;
     RECT  17.123 66.672 17.749 67.272 ;
     RECT  17.651 73.536 17.749 73.56 ;
     RECT  16.744 35.952 17.773 35.976 ;
     RECT  16.744 12.192 17.797 12.264 ;
     RECT  17.165 0.096 17.809 4.104 ;
     RECT  16.883 13.488 17.845 14.088 ;
     RECT  17.773 35.952 17.857 36.552 ;
     RECT  17.267 63.888 17.881 64.872 ;
     RECT  17.797 11.328 17.884 12.264 ;
     RECT  17.555 44.16 17.891 44.664 ;
     RECT  17.884 12.192 17.917 12.264 ;
     RECT  17.845 13.488 17.917 14.28 ;
     RECT  17.749 29.088 17.921 29.112 ;
     RECT  17.837 57.6 17.921 57.624 ;
     RECT  17.917 12.192 17.929 14.28 ;
     RECT  17.881 15.408 17.965 15.432 ;
     RECT  17.881 56.448 17.965 56.472 ;
     RECT  17.881 63.888 17.965 65.064 ;
     RECT  17.929 12.192 17.987 14.232 ;
     RECT  16.744 49.44 18.025 49.464 ;
     RECT  16.841 69.792 18.025 69.816 ;
     RECT  16.883 8.352 18.035 8.376 ;
     RECT  17.989 62.64 18.073 62.808 ;
     RECT  17.857 35.952 18.101 36.072 ;
     RECT  18.073 62.784 18.101 62.808 ;
     RECT  18.025 49.44 18.131 50.184 ;
     RECT  17.809 0.048 18.133 4.104 ;
     RECT  18.097 30.288 18.133 30.312 ;
     RECT  17.749 66.192 18.133 67.272 ;
     RECT  18.133 33.792 18.14 33.816 ;
     RECT  18.025 69.792 18.169 70.776 ;
     RECT  16.885 47.856 18.181 47.88 ;
     RECT  18.169 69.6 18.181 70.776 ;
     RECT  17.651 71.808 18.181 72.36 ;
     RECT  18.133 29.664 18.217 30.312 ;
     RECT  18.133 0.048 18.22 4.872 ;
     RECT  18.217 30.288 18.227 30.312 ;
     RECT  18.14 33.504 18.227 33.816 ;
     RECT  17.965 63.888 18.229 64.776 ;
     RECT  17.74 52.992 18.245 53.112 ;
     RECT  18.181 69.6 18.253 72.36 ;
     RECT  18.236 30.672 18.323 30.696 ;
     RECT  18.181 47.856 18.325 48.408 ;
     RECT  18.131 49.44 18.325 49.608 ;
     RECT  18.325 47.856 18.361 49.608 ;
     RECT  17.669 20.016 18.371 20.184 ;
     RECT  17.705 22.704 18.373 24.456 ;
     RECT  18.313 55.392 18.397 55.416 ;
     RECT  18.229 63.84 18.419 64.776 ;
     RECT  16.985 7.104 18.421 7.128 ;
     RECT  17.093 74.688 18.421 77.592 ;
     RECT  17.705 27.696 18.457 27.72 ;
     RECT  18.373 22.704 18.461 24.84 ;
     RECT  18.277 41.904 18.517 41.928 ;
     RECT  18.133 66.096 18.517 67.272 ;
     RECT  18.461 22.704 18.533 23.976 ;
     RECT  18.457 43.92 18.541 43.944 ;
     RECT  18.517 41.904 18.565 42.168 ;
     RECT  18.361 47.856 18.569 49.08 ;
     RECT  18.565 41.712 18.593 42.168 ;
     RECT  18.421 7.104 18.613 7.416 ;
     RECT  18.253 70.56 18.637 72.36 ;
     RECT  16.744 51.744 18.661 51.768 ;
     RECT  18.637 60.96 18.721 60.984 ;
     RECT  18.637 70.56 18.721 72.456 ;
     RECT  18.529 69.504 18.745 69.528 ;
     RECT  18.673 33.888 18.757 33.912 ;
     RECT  17.669 18.144 18.785 18.984 ;
     RECT  18.661 51.744 18.785 52.68 ;
     RECT  18.745 69.456 18.803 69.528 ;
     RECT  18.613 6.288 18.805 7.416 ;
     RECT  18.457 26.688 18.805 27.72 ;
     RECT  18.593 41.616 18.805 42.168 ;
     RECT  18.785 51.744 18.805 52.44 ;
     RECT  18.785 18.144 18.817 18.84 ;
     RECT  18.673 58.704 18.817 58.728 ;
     RECT  18.313 59.808 18.817 59.832 ;
     RECT  18.421 73.872 18.853 77.592 ;
     RECT  18.517 65.952 18.86 67.272 ;
     RECT  18.805 5.424 18.892 7.416 ;
     RECT  18.101 36.048 18.892 36.072 ;
     RECT  17.987 13.008 18.893 14.232 ;
     RECT  18.22 0.048 18.899 4.296 ;
     RECT  18.721 70.56 18.929 72.36 ;
     RECT  18.893 13.008 18.94 13.512 ;
     RECT  18.86 65.952 18.947 67.464 ;
     RECT  16.883 32.448 18.956 32.472 ;
     RECT  18.805 10.992 19.001 11.016 ;
     RECT  18.817 58.704 19.043 59.832 ;
     RECT  18.925 21.6 19.045 21.624 ;
     RECT  18.533 22.704 19.045 23.688 ;
     RECT  18.805 26.688 19.045 28.296 ;
     RECT  19.043 59.808 19.081 59.832 ;
     RECT  19.045 21.6 19.105 23.688 ;
     RECT  19.045 25.872 19.132 28.296 ;
     RECT  18.892 6.24 19.139 7.416 ;
     RECT  18.94 13.008 19.141 13.368 ;
     RECT  18.469 46.848 19.141 46.872 ;
     RECT  18.569 47.856 19.141 48.888 ;
     RECT  18.947 65.952 19.181 67.272 ;
     RECT  19.133 16.56 19.217 16.584 ;
     RECT  18.961 62.832 19.237 62.856 ;
     RECT  18.805 41.616 19.253 42.456 ;
     RECT  18.805 54.864 19.253 54.888 ;
     RECT  19.105 21.168 19.325 23.688 ;
     RECT  19.325 21.168 19.331 23.016 ;
     RECT  19.244 34.992 19.331 35.016 ;
     RECT  19.237 62.016 19.369 62.856 ;
     RECT  19.141 46.848 19.379 48.888 ;
     RECT  19.369 62.016 19.379 62.184 ;
     RECT  18.956 31.872 19.381 32.472 ;
     RECT  19.333 39.696 19.381 39.72 ;
     RECT  18.419 63.84 19.381 63.864 ;
     RECT  18.961 64.848 19.381 64.872 ;
     RECT  18.853 73.872 19.397 77.64 ;
     RECT  19.253 41.616 19.429 42.216 ;
     RECT  19.349 37.296 19.433 37.32 ;
     RECT  19.381 58.56 19.468 58.584 ;
     RECT  19.331 21.264 19.469 23.016 ;
     RECT  19.379 48.384 19.469 48.888 ;
     RECT  19.379 46.848 19.501 46.968 ;
     RECT  19.381 63.216 19.523 64.872 ;
     RECT  19.523 63.264 19.541 64.872 ;
     RECT  19.181 65.952 19.577 66.792 ;
     RECT  19.501 46.8 19.637 46.968 ;
     RECT  19.381 31.536 19.649 33.816 ;
     RECT  19.429 41.568 19.681 42.216 ;
     RECT  19.469 21.264 19.693 21.768 ;
     RECT  19.541 64.752 19.717 64.872 ;
     RECT  19.577 65.952 19.717 66.696 ;
     RECT  19.637 46.56 19.721 46.968 ;
     RECT  18.817 18.096 19.753 18.84 ;
     RECT  18.371 20.016 19.753 20.04 ;
     RECT  18.805 50.688 19.753 52.44 ;
     RECT  19.381 15.456 19.757 15.48 ;
     RECT  19.649 31.536 19.757 33.336 ;
     RECT  19.381 35.232 19.793 35.88 ;
     RECT  19.681 41.184 19.801 42.216 ;
     RECT  19.753 50.688 19.859 52.536 ;
     RECT  19.381 39.696 19.861 39.816 ;
     RECT  19.469 22.752 19.907 23.016 ;
     RECT  19.724 24.048 19.916 24.6 ;
     RECT  19.757 31.536 19.937 33.288 ;
     RECT  19.717 64.752 19.937 66.696 ;
     RECT  19.861 38.784 19.945 39.816 ;
     RECT  19.861 16.512 19.948 16.536 ;
     RECT  19.753 18.096 19.955 20.04 ;
     RECT  19.469 48.864 19.955 48.888 ;
     RECT  19.937 64.992 19.955 66.696 ;
     RECT  19.945 39.6 19.957 39.816 ;
     RECT  19.388 29.376 19.964 29.4 ;
     RECT  19.916 24.048 19.981 24.792 ;
     RECT  19.897 43.92 19.981 43.944 ;
     RECT  19.981 24.768 20.003 24.792 ;
     RECT  19.916 60.72 20.003 60.744 ;
     RECT  18.899 0.048 20.005 3.864 ;
     RECT  19.141 12.672 20.005 13.368 ;
     RECT  19.132 26.208 20.005 28.296 ;
     RECT  19.964 29.376 20.005 29.688 ;
     RECT  19.693 21.264 20.009 21.672 ;
     RECT  19.859 50.688 20.009 51.816 ;
     RECT  19.925 57.456 20.009 57.48 ;
     RECT  19.957 37.968 20.081 37.992 ;
     RECT  19.801 42.192 20.081 42.216 ;
     RECT  20.009 51.264 20.081 51.816 ;
     RECT  19.397 74.16 20.089 77.64 ;
     RECT  19.139 6.24 20.099 7.128 ;
     RECT  19.813 8.88 20.101 8.904 ;
     RECT  19.937 31.536 20.149 31.944 ;
     RECT  20.101 8.88 20.189 9.672 ;
     RECT  20.005 26.208 20.221 29.688 ;
     RECT  19.793 35.232 20.225 35.256 ;
     RECT  20.099 6.288 20.243 7.128 ;
     RECT  19.957 39.6 20.257 39.912 ;
     RECT  19.801 41.184 20.257 41.208 ;
     RECT  20.005 0.048 20.261 4.536 ;
     RECT  20.257 39.6 20.332 41.208 ;
     RECT  19.897 54.816 20.389 54.84 ;
     RECT  20.081 51.312 20.413 51.816 ;
     RECT  20.005 11.904 20.441 13.368 ;
     RECT  20.413 51.504 20.441 51.816 ;
     RECT  20.245 50.16 20.477 50.184 ;
     RECT  20.261 0.144 20.483 4.536 ;
     RECT  20.149 31.344 20.483 31.944 ;
     RECT  20.221 24.912 20.485 29.688 ;
     RECT  20.437 49.056 20.501 49.08 ;
     RECT  19.955 18.096 20.513 19.896 ;
     RECT  20.501 49.056 20.521 49.992 ;
     RECT  20.365 8.688 20.531 8.712 ;
     RECT  20.332 39.696 20.531 41.208 ;
     RECT  19.541 63.264 20.531 63.288 ;
     RECT  20.441 11.904 20.533 12.264 ;
     RECT  20.389 54.816 20.533 55.272 ;
     RECT  20.533 16.56 20.545 16.584 ;
     RECT  20.485 24.912 20.545 30.12 ;
     RECT  18.929 70.56 20.549 71.784 ;
     RECT  20.533 11.664 20.585 12.264 ;
     RECT  20.521 49.44 20.585 49.992 ;
     RECT  19.955 65.76 20.585 66.696 ;
     RECT  19.721 46.656 20.593 46.968 ;
     RECT  20.441 51.792 20.62 51.816 ;
     RECT  20.533 34.512 20.621 34.536 ;
     RECT  20.585 49.968 20.675 49.992 ;
     RECT  20.545 16.56 20.677 17.112 ;
     RECT  20.483 31.536 20.716 31.944 ;
     RECT  20.677 16.56 20.723 17.736 ;
     RECT  20.593 46.848 20.773 46.968 ;
     RECT  20.723 17.712 20.819 17.736 ;
     RECT  20.531 41.04 20.819 41.208 ;
     RECT  19.937 33.264 20.873 33.288 ;
     RECT  20.533 54.816 20.933 55.416 ;
     RECT  20.545 24.912 20.941 30.168 ;
     RECT  20.941 24.912 20.965 30.264 ;
     RECT  20.009 21.552 20.972 21.672 ;
     RECT  19.907 22.848 20.972 23.016 ;
     RECT  20.773 46.848 21.013 47.112 ;
     RECT  21.077 57.36 21.109 57.384 ;
     RECT  18.803 69.456 21.109 69.48 ;
     RECT  20.549 70.56 21.109 71.208 ;
     RECT  20.243 6.288 21.205 6.84 ;
     RECT  20.965 43.776 21.229 43.8 ;
     RECT  20.965 24.768 21.253 30.264 ;
     RECT  21.109 36.96 21.253 36.984 ;
     RECT  20.933 54.192 21.301 55.416 ;
     RECT  21.121 34.368 21.373 34.392 ;
     RECT  20.585 65.76 21.397 66.072 ;
     RECT  20.972 21.552 21.541 23.016 ;
     RECT  21.397 38.4 21.581 38.424 ;
     RECT  21.205 5.904 21.637 6.84 ;
     RECT  21.541 21.552 21.637 23.064 ;
     RECT  20.716 31.536 21.637 31.56 ;
     RECT  21.253 36.144 21.637 36.984 ;
     RECT  21.581 38.208 21.637 38.424 ;
     RECT  20.531 39.696 21.637 39.768 ;
     RECT  21.077 51.84 21.637 51.864 ;
     RECT  21.109 69.456 21.637 71.208 ;
     RECT  20.221 72.96 21.637 72.984 ;
     RECT  20.585 11.664 21.685 11.688 ;
     RECT  20.441 13.344 21.685 13.368 ;
     RECT  21.013 46.848 21.725 47.928 ;
     RECT  21.637 69.456 21.725 72.984 ;
     RECT  21.637 21.216 21.733 23.064 ;
     RECT  21.301 53.616 21.733 55.416 ;
     RECT  21.397 65.52 21.733 66.072 ;
     RECT  20.089 74.736 21.733 77.64 ;
     RECT  20.483 0.144 21.848 3.96 ;
     RECT  21.637 5.904 21.848 7.8 ;
     RECT  21.685 11.664 21.848 13.368 ;
     RECT  19.765 14.832 21.848 15.432 ;
     RECT  20.723 16.56 21.848 16.584 ;
     RECT  20.513 18.72 21.848 19.896 ;
     RECT  21.733 21.12 21.848 23.064 ;
     RECT  21.253 24.336 21.848 30.264 ;
     RECT  21.637 31.392 21.848 31.56 ;
     RECT  21.373 33.888 21.848 34.392 ;
     RECT  21.637 35.904 21.848 36.984 ;
     RECT  21.637 38.208 21.848 39.768 ;
     RECT  20.869 41.52 21.848 41.544 ;
     RECT  21.229 43.344 21.848 43.8 ;
     RECT  21.085 45.168 21.848 45.192 ;
     RECT  21.725 46.848 21.848 48.504 ;
     RECT  21.733 50.016 21.848 50.04 ;
     RECT  21.637 51.84 21.848 52.296 ;
     RECT  21.733 53.28 21.848 55.416 ;
     RECT  21.109 56.448 21.848 57.48 ;
     RECT  20.725 62.736 21.848 63.24 ;
     RECT  21.733 65.52 21.848 66.6 ;
     RECT  19.045 68.4 21.848 68.424 ;
     RECT  21.725 69.456 21.848 73.608 ;
     RECT  21.733 74.688 21.848 77.64 ;
     RECT  21.848 0.144 22.144 77.64 ;
     RECT  22.144 24.864 22.259 25.128 ;
     RECT  22.144 26.784 22.259 29.688 ;
     RECT  22.259 28.272 22.285 29.688 ;
     RECT  22.144 49.968 22.3 54.024 ;
     RECT  22.144 12 22.313 13.368 ;
     RECT  22.3 49.968 22.321 52.296 ;
     RECT  22.144 19.92 22.348 20.088 ;
     RECT  22.144 64.992 22.355 67.32 ;
     RECT  22.144 16.608 22.393 17.112 ;
     RECT  22.348 20.064 22.393 20.088 ;
     RECT  22.321 52.176 22.396 52.296 ;
     RECT  22.3 53.52 22.396 54.024 ;
     RECT  22.144 56.4 22.493 57.576 ;
     RECT  22.144 0.144 22.525 4.152 ;
     RECT  22.144 41.856 22.529 43.272 ;
     RECT  22.144 60.384 22.565 60.84 ;
     RECT  22.144 39.072 22.601 40.008 ;
     RECT  22.529 41.856 22.601 42.888 ;
     RECT  22.355 66.048 22.673 67.32 ;
     RECT  22.565 60.816 22.684 60.84 ;
     RECT  22.355 64.992 22.781 65.016 ;
     RECT  22.393 16.608 22.787 16.632 ;
     RECT  22.259 25.104 22.787 25.128 ;
     RECT  22.144 36.144 22.787 37.56 ;
     RECT  22.601 39.168 22.787 40.008 ;
     RECT  22.601 41.856 22.787 42.696 ;
     RECT  22.144 58.944 22.787 59.256 ;
     RECT  22.144 14.928 22.817 15.528 ;
     RECT  22.285 29.472 22.817 29.688 ;
     RECT  22.321 49.968 22.817 50.76 ;
     RECT  22.144 62.064 22.817 62.712 ;
     RECT  22.313 12.192 22.876 13.368 ;
     RECT  22.144 7.392 22.889 7.416 ;
     RECT  22.144 18.672 22.889 18.744 ;
     RECT  22.144 46.896 22.925 48.312 ;
     RECT  22.817 15.408 22.969 15.528 ;
     RECT  22.969 15.504 22.979 15.528 ;
     RECT  22.396 53.52 23.027 53.544 ;
     RECT  22.259 26.784 23.033 26.808 ;
     RECT  22.787 36.144 23.068 36.168 ;
     RECT  22.925 46.896 23.075 48.168 ;
     RECT  22.396 52.272 23.075 52.296 ;
     RECT  22.525 0.048 23.171 4.152 ;
     RECT  22.144 55.104 23.171 55.128 ;
     RECT  22.144 68.4 23.201 72.984 ;
     RECT  22.144 33.12 23.213 33.336 ;
     RECT  22.144 21.648 23.221 21.672 ;
     RECT  22.144 22.752 23.221 23.688 ;
     RECT  22.817 49.968 23.221 49.992 ;
     RECT  23.221 21.648 23.245 23.688 ;
     RECT  23.201 68.4 23.245 73.608 ;
     RECT  22.144 74.688 23.245 77.64 ;
     RECT  22.787 37.536 23.249 37.56 ;
     RECT  23.245 21.648 23.269 23.88 ;
     RECT  23.221 49.248 23.308 49.992 ;
     RECT  23.075 46.896 23.315 46.92 ;
     RECT  22.787 41.856 23.321 41.88 ;
     RECT  23.269 21.552 23.345 23.88 ;
     RECT  23.171 0.048 23.356 3.192 ;
     RECT  23.221 4.56 23.357 4.584 ;
     RECT  23.213 33.12 23.363 33.144 ;
     RECT  22.787 39.168 23.363 39.864 ;
     RECT  23.245 64.56 23.363 64.824 ;
     RECT  23.345 21.552 23.389 24.408 ;
     RECT  22.817 62.16 23.42 62.712 ;
     RECT  23.389 21.36 23.429 24.408 ;
     RECT  22.787 59.088 23.429 59.112 ;
     RECT  23.363 39.84 23.501 39.864 ;
     RECT  23.365 46.128 23.501 46.728 ;
     RECT  23.42 62.16 23.506 63.192 ;
     RECT  23.501 46.704 23.507 46.728 ;
     RECT  23.365 9.648 23.569 9.672 ;
     RECT  22.144 44.448 23.569 45 ;
     RECT  23.365 30.288 23.609 30.312 ;
     RECT  23.569 9.648 23.645 9.912 ;
     RECT  23.245 68.4 23.701 77.64 ;
     RECT  23.701 68.352 23.753 77.64 ;
     RECT  23.753 71.184 23.789 77.64 ;
     RECT  23.363 64.8 23.821 64.824 ;
     RECT  22.673 66.864 23.821 67.32 ;
     RECT  22.285 28.272 23.845 28.296 ;
     RECT  23.365 19.296 23.861 19.32 ;
     RECT  22.493 56.928 23.897 57.576 ;
     RECT  23.569 43.92 23.921 45 ;
     RECT  23.821 66.288 23.921 67.32 ;
     RECT  23.845 8.352 23.932 8.376 ;
     RECT  23.605 18.288 23.939 18.312 ;
     RECT  23.429 21.36 23.939 24.12 ;
     RECT  23.921 43.632 23.939 45 ;
     RECT  23.821 64.8 23.939 65.256 ;
     RECT  23.753 68.352 23.939 70.2 ;
     RECT  23.845 41.808 23.941 41.832 ;
     RECT  23.893 19.392 23.977 19.416 ;
     RECT  23.9 29.76 23.987 30.024 ;
     RECT  23.9 31.344 23.987 31.368 ;
     RECT  23.9 37.008 23.987 37.032 ;
     RECT  23.939 43.632 24.005 43.656 ;
     RECT  23.929 38.64 24.035 38.664 ;
     RECT  23.948 39.984 24.035 40.008 ;
     RECT  23.308 49.44 24.037 49.992 ;
     RECT  23.939 65.04 24.037 65.256 ;
     RECT  23.921 66.288 24.037 67.368 ;
     RECT  22.876 12.768 24.044 13.368 ;
     RECT  23.939 44.64 24.101 45 ;
     RECT  24.044 12.192 24.109 13.368 ;
     RECT  24.109 12.192 24.131 14.232 ;
     RECT  23.939 21.744 24.149 24.12 ;
     RECT  24.037 49.44 24.179 50.76 ;
     RECT  23.897 56.928 24.179 57.528 ;
     RECT  23.941 41.76 24.185 41.832 ;
     RECT  24.131 12.768 24.193 14.232 ;
     RECT  23.749 53.328 24.217 53.352 ;
     RECT  23.413 54.528 24.217 54.84 ;
     RECT  24.133 59.232 24.22 59.256 ;
     RECT  24.149 21.744 24.221 22.488 ;
     RECT  24.149 23.712 24.221 24.12 ;
     RECT  23.506 62.16 24.245 63.24 ;
     RECT  24.179 57.072 24.257 57.528 ;
     RECT  23.075 47.904 24.301 48.168 ;
     RECT  24.179 49.44 24.325 49.992 ;
     RECT  23.893 51.984 24.325 52.2 ;
     RECT  24.217 53.328 24.325 54.84 ;
     RECT  23.813 60.384 24.325 60.408 ;
     RECT  24.185 41.808 24.329 41.832 ;
     RECT  24.245 62.112 24.329 63.24 ;
     RECT  24.325 60.384 24.361 60.84 ;
     RECT  23.645 9.792 24.401 9.912 ;
     RECT  24.221 24.096 24.401 24.12 ;
     RECT  24.325 48.48 24.401 49.992 ;
     RECT  24.257 57.504 24.401 57.528 ;
     RECT  24.329 62.64 24.401 63.24 ;
     RECT  24.401 48.48 24.467 49.08 ;
     RECT  24.389 14.832 24.473 14.856 ;
     RECT  24.373 11.328 24.509 11.352 ;
     RECT  23.789 71.232 24.509 77.64 ;
     RECT  24.361 20.592 24.515 20.616 ;
     RECT  24.101 44.64 24.515 45.528 ;
     RECT  24.467 49.056 24.515 49.08 ;
     RECT  24.325 51.984 24.515 54.84 ;
     RECT  24.361 60.384 24.515 61.608 ;
     RECT  24.515 51.984 24.541 52.104 ;
     RECT  24.509 71.376 24.581 77.64 ;
     RECT  23.987 29.952 24.589 30.024 ;
     RECT  24.401 63.216 24.589 63.24 ;
     RECT  24.515 53.088 24.604 54.024 ;
     RECT  24.037 65.04 24.613 67.368 ;
     RECT  24.541 51.36 24.625 52.104 ;
     RECT  24.515 60.384 24.697 61.56 ;
     RECT  24.613 65.04 24.697 67.848 ;
     RECT  23.356 0.048 24.757 2.856 ;
     RECT  24.697 65.04 24.761 67.32 ;
     RECT  24.625 52.08 24.803 52.104 ;
     RECT  24.401 9.888 24.86 9.912 ;
     RECT  24.697 60.816 24.877 61.56 ;
     RECT  24.221 21.744 24.901 22.2 ;
     RECT  24.877 60.816 24.905 60.84 ;
     RECT  24.193 12.768 24.941 13.704 ;
     RECT  24.901 21.648 24.941 22.2 ;
     RECT  24.589 29.952 24.941 29.976 ;
     RECT  24.517 36.912 24.941 36.936 ;
     RECT  24.86 9.888 24.947 10.728 ;
     RECT  24.941 21.648 24.985 21.672 ;
     RECT  24.901 19.872 24.995 20.52 ;
     RECT  24.581 71.376 25.043 73.608 ;
     RECT  24.949 59.808 25.049 59.832 ;
     RECT  24.613 26.832 25.091 26.856 ;
     RECT  24.604 53.088 25.091 53.976 ;
     RECT  24.581 74.64 25.121 77.64 ;
     RECT  25.052 5.328 25.139 5.352 ;
     RECT  25.091 53.616 25.187 53.976 ;
     RECT  25.093 40.704 25.189 40.728 ;
     RECT  25.141 17.856 25.229 17.88 ;
     RECT  25.121 74.64 25.379 77.592 ;
     RECT  25.093 32.976 25.388 33 ;
     RECT  25.429 49.44 25.441 49.464 ;
     RECT  23.939 69.216 25.441 70.2 ;
     RECT  25.441 49.44 25.477 50.04 ;
     RECT  24.995 20.496 25.481 20.52 ;
     RECT  25.189 40.512 25.481 40.728 ;
     RECT  24.761 66.144 25.481 67.32 ;
     RECT  25.441 69.216 25.505 70.248 ;
     RECT  25.043 73.488 25.517 73.608 ;
     RECT  23.845 28.272 25.549 28.488 ;
     RECT  25.043 71.376 25.553 72.36 ;
     RECT  25.477 49.2 25.564 50.04 ;
     RECT  25.564 50.016 25.571 50.04 ;
     RECT  25.481 40.704 25.589 40.728 ;
     RECT  25.381 43.344 25.589 43.368 ;
     RECT  25.525 34.224 25.612 34.248 ;
     RECT  25.388 32.448 25.628 33 ;
     RECT  25.549 27.936 25.633 28.488 ;
     RECT  25.628 32.448 25.667 33.528 ;
     RECT  25.505 69.024 25.667 70.248 ;
     RECT  25.517 73.584 25.667 73.608 ;
     RECT  25.633 28.272 25.697 28.488 ;
     RECT  25.667 69.024 25.697 70.104 ;
     RECT  25.379 74.64 25.697 77.448 ;
     RECT  25.621 46.224 25.705 46.248 ;
     RECT  25.667 33.504 25.715 33.528 ;
     RECT  25.553 71.376 25.715 72.024 ;
     RECT  25.669 52.368 25.756 52.392 ;
     RECT  24.515 44.64 25.765 44.664 ;
     RECT  25.697 74.64 25.829 77.064 ;
     RECT  24.901 64.416 25.873 64.776 ;
     RECT  25.481 66.144 25.873 66.936 ;
     RECT  25.697 69.024 25.873 69.576 ;
     RECT  24.757 0.048 25.909 3.384 ;
     RECT  25.621 4.512 25.909 4.584 ;
     RECT  25.073 58.656 25.945 58.68 ;
     RECT  25.765 43.824 25.955 45 ;
     RECT  25.187 53.616 26.003 53.64 ;
     RECT  25.873 68.4 26.003 69.576 ;
     RECT  25.873 64.416 26.044 66.936 ;
     RECT  25.909 0.048 26.101 4.584 ;
     RECT  25.669 11.184 26.129 11.208 ;
     RECT  25.813 41.04 26.129 41.064 ;
     RECT  25.621 42.72 26.129 42.792 ;
     RECT  25.669 56.496 26.129 56.52 ;
     RECT  25.153 26.256 26.149 26.28 ;
     RECT  25.765 63.216 26.195 63.24 ;
     RECT  25.729 16.8 26.197 16.824 ;
     RECT  26.189 55.92 26.197 55.944 ;
     RECT  25.873 57.648 26.243 57.672 ;
     RECT  26.101 22.992 26.245 23.016 ;
     RECT  25.955 44.448 26.269 45 ;
     RECT  26.044 64.416 26.305 66.312 ;
     RECT  25.945 58.656 26.348 58.968 ;
     RECT  24.947 9.888 26.636 9.912 ;
     RECT  26.149 26.256 26.684 26.424 ;
     RECT  26.348 58.08 26.684 58.968 ;
     RECT  26.629 41.616 26.693 41.64 ;
     RECT  26.684 26.256 26.773 26.952 ;
     RECT  26.341 30.672 26.773 30.696 ;
     RECT  26.485 38.208 26.773 38.232 ;
     RECT  26.269 44.448 26.773 45.912 ;
     RECT  26.485 19.104 26.821 19.128 ;
     RECT  26.845 62.736 26.928 62.76 ;
     RECT  26.197 16.8 26.953 17.016 ;
     RECT  26.413 50.592 27.025 50.616 ;
     RECT  26.629 51.936 27.025 51.96 ;
     RECT  27.025 50.592 27.061 51.96 ;
     RECT  25.697 28.464 27.089 28.488 ;
     RECT  26.003 68.928 27.089 69.576 ;
     RECT  25.957 6.864 27.097 6.888 ;
     RECT  27.089 28.464 27.109 28.584 ;
     RECT  26.773 37.584 27.109 38.232 ;
     RECT  26.773 44.448 27.109 46.344 ;
     RECT  26.101 0.048 27.248 4.728 ;
     RECT  27.097 6.096 27.248 6.888 ;
     RECT  26.636 8.928 27.248 9.912 ;
     RECT  24.941 12.768 27.248 12.792 ;
     RECT  26.953 16.512 27.248 17.016 ;
     RECT  26.821 19.104 27.248 19.272 ;
     RECT  26.197 21.12 27.248 21.144 ;
     RECT  26.245 22.992 27.248 23.736 ;
     RECT  26.773 25.968 27.248 26.952 ;
     RECT  27.109 28.464 27.248 29.016 ;
     RECT  26.773 30.672 27.248 30.744 ;
     RECT  26.245 32.4 27.248 32.424 ;
     RECT  26.197 35.136 27.248 35.16 ;
     RECT  27.109 37.584 27.248 39 ;
     RECT  26.693 41.616 27.248 42.168 ;
     RECT  27.109 43.824 27.248 46.536 ;
     RECT  26.821 47.808 27.248 47.832 ;
     RECT  27.061 50.016 27.248 51.96 ;
     RECT  26.245 53.088 27.248 53.112 ;
     RECT  26.197 55.392 27.248 55.944 ;
     RECT  26.869 56.928 27.248 56.952 ;
     RECT  26.684 58.08 27.248 59.88 ;
     RECT  26.928 62.688 27.248 62.76 ;
     RECT  26.305 63.744 27.248 66.312 ;
     RECT  26.701 67.296 27.248 67.32 ;
     RECT  27.089 68.928 27.248 70.2 ;
     RECT  25.715 71.376 27.248 71.928 ;
     RECT  25.829 74.16 27.248 77.064 ;
     RECT  27.248 0.048 27.544 77.064 ;
     RECT  27.544 14.208 27.683 17.256 ;
     RECT  27.544 30.336 27.683 30.36 ;
     RECT  27.544 46.368 27.683 48.168 ;
     RECT  27.544 42 27.713 43.704 ;
     RECT  27.544 73.584 27.713 75.096 ;
     RECT  27.544 26.736 27.721 26.76 ;
     RECT  27.544 58.032 27.721 59.736 ;
     RECT  27.544 36.384 27.724 37.32 ;
     RECT  27.544 9.888 27.731 10.632 ;
     RECT  27.544 44.736 27.731 44.76 ;
     RECT  27.544 0.048 27.749 5.112 ;
     RECT  27.544 28.416 27.749 29.016 ;
     RECT  27.544 51.312 27.757 55.176 ;
     RECT  27.544 12.768 27.827 13.08 ;
     RECT  27.544 69.12 27.827 69.144 ;
     RECT  27.544 22.752 27.857 23.064 ;
     RECT  27.544 18.432 27.923 20.568 ;
     RECT  27.757 51.312 27.923 52.248 ;
     RECT  27.757 53.232 27.923 55.176 ;
     RECT  27.544 76.08 27.929 77.064 ;
     RECT  27.923 18.432 27.971 19.848 ;
     RECT  27.923 53.232 27.971 54.12 ;
     RECT  27.544 56.64 27.984 57.048 ;
     RECT  27.731 10.464 28.009 10.632 ;
     RECT  27.971 19.584 28.009 19.848 ;
     RECT  27.713 73.968 28.019 75.096 ;
     RECT  27.749 0.048 28.037 3.432 ;
     RECT  27.683 14.208 28.067 15.192 ;
     RECT  27.544 71.184 28.067 71.928 ;
     RECT  27.683 47.904 28.081 48.168 ;
     RECT  27.749 28.416 28.109 28.968 ;
     RECT  27.724 37.296 28.109 37.32 ;
     RECT  28.067 71.712 28.181 71.928 ;
     RECT  27.713 42 28.189 43.032 ;
     RECT  27.923 51.936 28.217 52.248 ;
     RECT  27.683 16.56 28.259 16.584 ;
     RECT  27.683 46.368 28.289 46.392 ;
     RECT  27.544 6.096 28.307 6.888 ;
     RECT  28.067 14.208 28.433 14.856 ;
     RECT  27.971 53.232 28.433 53.496 ;
     RECT  27.721 58.032 28.433 59.016 ;
     RECT  28.433 14.208 28.451 14.28 ;
     RECT  27.857 22.752 28.492 22.776 ;
     RECT  27.544 38.688 28.499 38.808 ;
     RECT  28.433 58.032 28.499 58.104 ;
     RECT  27.544 67.92 28.499 67.944 ;
     RECT  27.544 24.192 28.54 24.648 ;
     RECT  28.109 28.464 28.541 28.968 ;
     RECT  28.433 53.232 28.547 53.256 ;
     RECT  27.971 18.432 28.585 18.456 ;
     RECT  27.984 56.928 28.585 57.048 ;
     RECT  27.544 40.944 28.613 40.968 ;
     RECT  28.081 48.144 28.613 48.168 ;
     RECT  28.541 28.944 28.732 28.968 ;
     RECT  28.217 51.936 28.757 51.96 ;
     RECT  28.7 36.096 28.787 36.12 ;
     RECT  28.019 74.112 28.793 74.136 ;
     RECT  28.189 43.008 28.829 43.032 ;
     RECT  28.789 30.768 28.861 30.792 ;
     RECT  28.861 30.288 28.901 30.792 ;
     RECT  28.885 38.016 28.972 38.04 ;
     RECT  28.585 57.024 28.973 57.048 ;
     RECT  28.753 21.6 29.027 21.624 ;
     RECT  28.94 59.28 29.027 59.304 ;
     RECT  28.789 24.096 29.036 24.12 ;
     RECT  28.009 10.464 29.075 10.488 ;
     RECT  28.901 30.288 29.075 30.744 ;
     RECT  27.923 55.152 29.077 55.176 ;
     RECT  27.749 4.704 29.117 5.112 ;
     RECT  27.544 49.968 29.125 49.992 ;
     RECT  29.117 5.088 29.149 5.112 ;
     RECT  29.125 49.92 29.149 49.992 ;
     RECT  28.037 0.096 29.185 3.432 ;
     RECT  28.009 19.584 29.185 19.8 ;
     RECT  29.149 49.92 29.212 50.76 ;
     RECT  29.125 62.352 29.212 62.376 ;
     RECT  29.077 43.584 29.225 43.608 ;
     RECT  29.077 54.768 29.225 55.176 ;
     RECT  29.225 54.864 29.297 55.176 ;
     RECT  29.221 61.776 29.308 61.8 ;
     RECT  29.228 64.32 29.315 64.344 ;
     RECT  29.185 19.584 29.333 19.992 ;
     RECT  29.149 5.088 29.461 5.688 ;
     RECT  28.307 6.672 29.461 6.888 ;
     RECT  28.451 14.256 29.461 14.28 ;
     RECT  29.077 68.448 29.461 68.472 ;
     RECT  29.461 68.448 29.477 69.144 ;
     RECT  29.477 69.12 29.548 69.144 ;
     RECT  29.333 19.968 29.555 19.992 ;
     RECT  29.036 23.904 29.605 24.12 ;
     RECT  29.461 14.256 29.651 14.616 ;
     RECT  29.077 15.984 29.653 16.008 ;
     RECT  29.605 23.664 29.653 24.12 ;
     RECT  28.499 58.08 29.653 58.104 ;
     RECT  29.653 45.264 29.701 45.96 ;
     RECT  29.645 37.584 29.729 37.608 ;
     RECT  29.653 10.32 29.737 10.344 ;
     RECT  29.653 15.744 29.737 16.008 ;
     RECT  29.653 36.48 29.737 36.504 ;
     RECT  29.653 39.216 29.737 39.24 ;
     RECT  28.189 42 29.756 42.024 ;
     RECT  29.651 14.256 29.765 14.28 ;
     RECT  29.756 42 29.788 42.12 ;
     RECT  29.737 15.984 29.801 16.008 ;
     RECT  29.653 58.08 29.801 59.016 ;
     RECT  29.077 60.288 29.804 60.312 ;
     RECT  29.653 55.392 29.809 55.464 ;
     RECT  29.185 0.096 29.833 3.96 ;
     RECT  29.725 51.888 29.833 51.912 ;
     RECT  29.075 30.72 29.837 30.744 ;
     RECT  29.212 50.688 29.837 50.76 ;
     RECT  29.788 42.096 29.843 42.12 ;
     RECT  29.801 58.08 29.891 58.104 ;
     RECT  29.653 23.664 29.941 24.456 ;
     RECT  27.827 12.768 29.981 12.792 ;
     RECT  29.804 60.288 30.005 60.408 ;
     RECT  29.653 20.304 30.017 20.328 ;
     RECT  29.941 23.04 30.017 24.456 ;
     RECT  30.005 59.856 30.085 60.408 ;
     RECT  29.989 47.424 30.089 47.448 ;
     RECT  30.085 59.856 30.089 60.456 ;
     RECT  30.089 60.432 30.179 60.456 ;
     RECT  30.049 32.544 30.227 32.568 ;
     RECT  29.701 44.976 30.229 45.96 ;
     RECT  29.833 51.888 30.229 52.008 ;
     RECT  29.809 55.44 30.269 55.464 ;
     RECT  29.837 50.736 30.284 50.76 ;
     RECT  30.229 51.888 30.284 52.152 ;
     RECT  30.229 44.592 30.313 46.728 ;
     RECT  29.941 65.52 30.323 65.544 ;
     RECT  29.833 0.048 30.337 3.96 ;
     RECT  29.461 5.088 30.337 6.888 ;
     RECT  30.229 43.2 30.341 43.224 ;
     RECT  30.313 45.168 30.341 46.728 ;
     RECT  30.284 50.736 30.449 52.152 ;
     RECT  30.337 0.048 30.485 6.888 ;
     RECT  30.229 53.424 30.485 53.448 ;
     RECT  30.229 36.096 30.521 36.12 ;
     RECT  30.017 23.04 30.589 23.688 ;
     RECT  30.589 22.8 30.593 23.688 ;
     RECT  30.229 62.208 30.625 62.232 ;
     RECT  30.229 20.496 30.629 21.624 ;
     RECT  30.229 39.168 30.665 39.192 ;
     RECT  30.341 45.168 30.673 46.248 ;
     RECT  30.593 22.8 30.701 22.824 ;
     RECT  30.668 27.456 30.755 27.48 ;
     RECT  30.625 62.16 30.755 62.232 ;
     RECT  30.229 11.616 30.757 11.64 ;
     RECT  30.755 62.208 30.773 62.232 ;
     RECT  27.929 76.08 30.809 76.632 ;
     RECT  30.809 76.08 30.881 76.536 ;
     RECT  30.485 6.768 30.899 6.888 ;
     RECT  30.757 10.8 30.899 11.64 ;
     RECT  30.805 30.192 30.949 30.216 ;
     RECT  30.949 29.376 31.004 30.216 ;
     RECT  31.004 28.512 31.036 30.216 ;
     RECT  30.956 25.344 31.043 25.368 ;
     RECT  30.956 32.928 31.043 32.952 ;
     RECT  30.805 55.92 31.043 55.944 ;
     RECT  31.036 30.192 31.061 30.216 ;
     RECT  31.036 28.512 31.091 28.536 ;
     RECT  30.853 13.68 31.169 13.704 ;
     RECT  30.629 20.496 31.205 21.432 ;
     RECT  30.229 38.064 31.237 38.088 ;
     RECT  30.899 6.816 31.241 6.84 ;
     RECT  30.229 18.96 31.241 18.984 ;
     RECT  31.237 37.776 31.333 38.088 ;
     RECT  31.237 40.56 31.333 40.584 ;
     RECT  30.449 50.736 31.333 51.288 ;
     RECT  30.673 45.168 31.349 46.104 ;
     RECT  28.181 71.712 31.349 71.736 ;
     RECT  31.285 42.144 31.372 42.168 ;
     RECT  31.301 73.584 31.385 73.608 ;
     RECT  31.333 36.048 31.457 36.072 ;
     RECT  31.333 40.56 31.457 40.824 ;
     RECT  31.333 20.064 31.529 20.088 ;
     RECT  31.349 45.984 31.529 46.104 ;
     RECT  31.205 21.408 31.565 21.432 ;
     RECT  30.697 52.848 31.601 52.872 ;
     RECT  31.529 45.984 31.673 46.008 ;
     RECT  31.333 50.496 31.724 51.288 ;
     RECT  28.681 8.496 31.909 8.52 ;
     RECT  31.877 9.552 31.909 9.576 ;
     RECT  31.877 25.2 31.909 25.224 ;
     RECT  31.669 34.752 31.909 34.776 ;
     RECT  31.333 37.776 32.101 38.136 ;
     RECT  32.053 30.288 32.137 30.312 ;
     RECT  31.909 34.752 32.425 35.064 ;
     RECT  31.909 42 32.437 42.024 ;
     RECT  32.425 34.752 32.453 35.4 ;
     RECT  30.485 0.048 32.485 5.4 ;
     RECT  31.909 8.496 32.485 9.576 ;
     RECT  31.909 25.056 32.492 25.224 ;
     RECT  32.437 41.664 32.497 42.024 ;
     RECT  31.849 47.184 32.569 47.208 ;
     RECT  32.485 0.048 32.605 5.496 ;
     RECT  32.605 0.048 32.648 6.12 ;
     RECT  32.485 8.496 32.648 10.2 ;
     RECT  31.333 11.664 32.648 11.688 ;
     RECT  32.533 13.584 32.648 13.608 ;
     RECT  31.877 19.2 32.648 19.224 ;
     RECT  32.492 24.864 32.648 25.224 ;
     RECT  32.137 30.24 32.648 30.312 ;
     RECT  31.628 32.832 32.648 32.856 ;
     RECT  32.453 34.608 32.648 35.4 ;
     RECT  32.101 37.584 32.648 38.136 ;
     RECT  31.877 39.888 32.648 39.912 ;
     RECT  32.497 41.616 32.648 42.024 ;
     RECT  31.916 44.016 32.648 44.04 ;
     RECT  32.569 47.136 32.648 47.208 ;
     RECT  31.909 48.96 32.648 48.984 ;
     RECT  31.724 50.496 32.648 51.624 ;
     RECT  31.993 53.472 32.648 53.496 ;
     RECT  31.669 56.256 32.648 56.52 ;
     RECT  31.669 57.648 32.648 57.672 ;
     RECT  32.533 59.088 32.648 59.112 ;
     RECT  32.492 61.104 32.648 61.128 ;
     RECT  31.82 63.648 32.648 63.672 ;
     RECT  32.485 65.136 32.648 65.16 ;
     RECT  32.485 67.68 32.648 67.704 ;
     RECT  30.881 76.512 32.648 76.536 ;
     RECT  32.648 0.048 32.84 76.692 ;
     RECT  32.84 0.048 32.944 76.962 ;
     RECT  32.944 50.64 33.041 50.664 ;
     RECT  32.944 67.296 33.041 67.704 ;
     RECT  32.944 15.456 33.059 15.48 ;
     RECT  32.944 20.064 33.059 20.184 ;
     RECT  32.944 55.44 33.059 57.528 ;
     RECT  33.041 67.296 33.059 67.32 ;
     RECT  32.944 63.888 33.085 64.488 ;
     RECT  32.944 0.048 33.107 4.92 ;
     RECT  33.059 56.496 33.12 57.528 ;
     RECT  32.944 39.792 33.155 39.912 ;
     RECT  33.12 57.504 33.185 57.528 ;
     RECT  32.944 53.616 33.193 53.64 ;
     RECT  32.944 73.584 33.193 73.608 ;
     RECT  32.944 45.264 33.347 45.288 ;
     RECT  32.944 6.096 33.437 6.936 ;
     RECT  32.944 37.728 33.437 37.752 ;
     RECT  32.944 25.008 33.473 25.032 ;
     RECT  32.944 30.576 33.581 31.32 ;
     RECT  33.059 55.44 33.635 55.464 ;
     RECT  33.437 6.096 33.683 6.84 ;
     RECT  33.581 30.576 33.689 30.6 ;
     RECT  33.059 20.16 33.725 20.184 ;
     RECT  32.944 46.704 33.797 47.256 ;
     RECT  33.12 56.496 33.833 56.52 ;
     RECT  33.797 47.232 33.916 47.256 ;
     RECT  33.155 39.792 34.049 39.816 ;
     RECT  33.683 6.768 34.115 6.84 ;
     RECT  33.107 4.512 34.121 4.92 ;
     RECT  33.973 11.424 34.211 11.448 ;
     RECT  34.124 21.696 34.211 21.72 ;
     RECT  34.124 28.032 34.211 28.056 ;
     RECT  34.115 6.768 34.373 6.792 ;
     RECT  34.213 37.584 34.373 37.608 ;
     RECT  32.944 76.512 34.481 76.536 ;
     RECT  34.412 23.712 34.499 23.736 ;
     RECT  34.501 39.648 34.588 39.672 ;
     RECT  34.213 30 34.589 30.024 ;
     RECT  34.121 4.512 34.595 4.536 ;
     RECT  34.556 48.528 34.643 48.552 ;
     RECT  34.549 53.52 34.787 53.544 ;
     RECT  33.107 0.048 34.789 3.432 ;
     RECT  34.685 52.176 34.789 52.2 ;
     RECT  33.085 64.464 34.789 64.488 ;
     RECT  34.412 27.312 34.876 27.864 ;
     RECT  34.789 52.176 34.877 52.44 ;
     RECT  34.789 64.368 34.877 64.68 ;
     RECT  34.789 29.088 34.949 29.112 ;
     RECT  34.796 31.968 34.979 31.992 ;
     RECT  34.933 10.752 35.02 10.776 ;
     RECT  34.789 0.048 35.057 4.104 ;
     RECT  34.789 55.248 35.123 55.272 ;
     RECT  35.057 0.048 35.171 3.432 ;
     RECT  34.877 64.368 35.201 64.392 ;
     RECT  35.077 7.968 35.269 7.992 ;
     RECT  35.171 0.048 35.417 2.904 ;
     RECT  35.317 23.664 35.417 23.688 ;
     RECT  35.317 25.68 35.417 27.288 ;
     RECT  35.269 7.968 35.461 8.568 ;
     RECT  35.405 13.104 35.489 13.128 ;
     RECT  35.317 35.376 35.489 35.4 ;
     RECT  35.377 12 35.603 12.024 ;
     RECT  35.417 25.68 35.633 26.328 ;
     RECT  35.417 0.048 35.669 1.704 ;
     RECT  35.653 44.688 35.74 44.712 ;
     RECT  35.317 31.872 35.777 31.896 ;
     RECT  35.377 51.936 35.843 51.96 ;
     RECT  34.892 30.144 35.873 30.744 ;
     RECT  35.804 57.456 35.891 57.48 ;
     RECT  35.873 29.328 35.929 30.744 ;
     RECT  35.873 10.56 35.957 10.584 ;
     RECT  35.929 29.328 35.957 29.784 ;
     RECT  35.461 7.44 35.993 8.568 ;
     RECT  36.025 16.608 36.053 16.632 ;
     RECT  35.989 14.208 36.061 14.232 ;
     RECT  35.993 7.92 36.083 8.568 ;
     RECT  36.053 16.56 36.133 16.632 ;
     RECT  36.083 8.496 36.179 8.568 ;
     RECT  36.133 16.56 36.205 16.68 ;
     RECT  36.061 14.208 36.209 14.856 ;
     RECT  35.893 59.28 36.245 59.304 ;
     RECT  35.417 2.784 36.323 2.904 ;
     RECT  36.209 14.208 36.371 14.232 ;
     RECT  36.241 53.616 36.419 53.64 ;
     RECT  36.373 35.856 36.46 35.88 ;
     RECT  36.205 16.56 36.467 16.728 ;
     RECT  36.313 18.768 36.497 18.792 ;
     RECT  36.467 16.56 36.569 16.584 ;
     RECT  35.669 0.24 36.637 1.704 ;
     RECT  36.469 24.672 36.713 24.696 ;
     RECT  35.957 29.76 36.713 29.784 ;
     RECT  36.179 8.544 36.857 8.568 ;
     RECT  36.637 0.192 36.889 1.704 ;
     RECT  36.805 42.192 36.929 42.216 ;
     RECT  36.853 21.648 36.947 21.672 ;
     RECT  36.889 0.144 37.537 1.704 ;
     RECT  36.349 3.36 37.717 3.432 ;
     RECT  37.537 0.144 38.048 2.328 ;
     RECT  37.717 3.36 38.048 3.96 ;
     RECT  37.033 5.088 38.048 5.112 ;
     RECT  37.645 19.392 38.048 19.416 ;
     RECT  37.045 25.824 38.048 25.992 ;
     RECT  37.033 47.04 38.048 47.064 ;
     RECT  38.048 0.144 38.24 76.692 ;
     RECT  38.24 0.144 38.344 76.962 ;
     RECT  38.344 13.632 38.483 13.656 ;
     RECT  38.344 0.144 38.531 2.76 ;
     RECT  38.344 17.664 38.531 17.688 ;
     RECT  38.531 0.144 38.557 0.408 ;
     RECT  38.531 1.44 38.579 2.76 ;
     RECT  38.579 2.256 38.627 2.28 ;
     RECT  38.557 0.144 38.771 0.168 ;
    LAYER M5 ;
     RECT  38.736 0.117 38.76 0.133 ;
     RECT  38.64 0.133 38.76 0.144 ;
     RECT  14.016 0.144 38.76 0.205 ;
     RECT  14.016 0.205 38.616 0.245 ;
     RECT  13.824 0.245 38.616 0.469 ;
     RECT  13.728 0.469 38.616 0.555 ;
     RECT  12.672 0.501 12.696 0.589 ;
     RECT  0.24 0.517 0.36 0.787 ;
     RECT  5.64 0.517 5.76 0.787 ;
     RECT  11.04 0.517 11.16 0.787 ;
     RECT  13.776 0.555 38.616 1.465 ;
     RECT  14.016 1.465 38.616 2.091 ;
     RECT  14.064 2.091 38.616 2.253 ;
     RECT  14.592 2.253 38.616 2.291 ;
     RECT  9.888 2.229 9.912 2.317 ;
     RECT  11.04 0.787 11.352 2.725 ;
     RECT  14.592 2.291 38.568 2.809 ;
     RECT  14.592 2.809 38.52 2.915 ;
     RECT  12.528 2.735 12.552 3.193 ;
     RECT  10.704 2.725 11.352 3.301 ;
     RECT  10.56 3.301 11.352 3.381 ;
     RECT  10.56 3.381 12.264 3.385 ;
     RECT  25.68 2.915 38.52 3.385 ;
     RECT  10.608 3.385 12.264 3.469 ;
     RECT  14.592 2.915 24.504 3.573 ;
     RECT  13.968 3.573 24.504 3.731 ;
     RECT  13.968 3.731 14.136 3.947 ;
     RECT  15.12 3.731 24.504 4.153 ;
     RECT  14.112 3.947 14.136 4.203 ;
     RECT  10.608 3.469 11.352 4.331 ;
     RECT  25.968 3.385 38.52 4.501 ;
     RECT  18.144 4.153 24.504 4.547 ;
     RECT  13.056 4.501 13.08 4.587 ;
     RECT  21.36 4.547 24.504 4.595 ;
     RECT  18.144 4.547 20.232 4.907 ;
     RECT  24.048 4.595 24.504 5.317 ;
     RECT  25.632 4.501 38.52 5.317 ;
     RECT  24.048 5.317 38.52 5.419 ;
     RECT  8.64 5.587 8.664 5.675 ;
     RECT  11.04 4.331 11.352 5.877 ;
     RECT  21.36 4.595 22.92 5.893 ;
     RECT  15.12 4.153 16.752 5.971 ;
     RECT  14.736 5.971 16.752 5.989 ;
     RECT  21.216 5.893 22.92 5.995 ;
     RECT  14.16 5.989 16.752 6.059 ;
     RECT  15.408 6.059 16.752 6.073 ;
     RECT  15.936 6.073 16.752 6.191 ;
     RECT  9.696 6.163 9.72 6.251 ;
     RECT  14.16 6.059 14.328 6.251 ;
     RECT  18.624 4.907 20.232 6.261 ;
     RECT  17.904 6.261 20.28 6.323 ;
     RECT  15.936 6.191 16.872 6.419 ;
     RECT  10.944 5.877 11.352 6.565 ;
     RECT  10.944 6.565 11.496 6.767 ;
     RECT  10.848 6.767 11.496 6.827 ;
     RECT  13.632 6.421 13.656 6.827 ;
     RECT  19.104 6.323 20.28 6.827 ;
     RECT  20.208 6.827 20.28 6.841 ;
     RECT  10.848 6.827 11.352 6.851 ;
     RECT  21.36 5.995 22.92 6.851 ;
     RECT  25.968 5.419 38.52 6.899 ;
     RECT  26.448 6.899 38.52 6.947 ;
     RECT  20.208 6.841 20.232 7.139 ;
     RECT  21.6 6.851 22.92 7.349 ;
     RECT  19.104 6.827 19.176 7.427 ;
     RECT  19.152 7.427 19.176 7.925 ;
     RECT  34.176 6.947 38.52 8.003 ;
     RECT  16.44 6.419 16.872 8.341 ;
     RECT  17.904 6.323 17.928 8.341 ;
     RECT  21.6 7.349 22.968 8.341 ;
     RECT  24.048 5.419 24.504 8.341 ;
     RECT  16.44 8.341 18.024 8.427 ;
     RECT  21.6 8.341 24.504 8.427 ;
     RECT  11.04 6.851 11.352 8.485 ;
     RECT  21.6 8.427 22.968 8.501 ;
     RECT  26.448 6.947 33.048 8.531 ;
     RECT  17.904 8.427 18.024 8.565 ;
     RECT  19.152 7.925 19.992 8.565 ;
     RECT  11.04 8.485 11.448 8.569 ;
     RECT  35.28 8.003 38.52 8.579 ;
     RECT  17.904 8.565 19.992 8.677 ;
     RECT  21.264 8.501 22.968 8.677 ;
     RECT  14.256 8.437 14.28 8.761 ;
     RECT  17.904 8.677 22.968 8.761 ;
     RECT  15.408 8.927 15.432 9.011 ;
     RECT  11.04 8.569 11.352 9.119 ;
     RECT  10.224 9.119 11.352 9.203 ;
     RECT  31.92 8.531 33.048 9.587 ;
     RECT  10.944 9.203 11.352 9.635 ;
     RECT  21.264 8.761 22.968 9.637 ;
     RECT  24.048 8.427 24.504 9.637 ;
     RECT  14.208 9.619 14.232 9.707 ;
     RECT  21.264 9.637 24.504 9.721 ;
     RECT  11.04 9.635 11.352 9.829 ;
     RECT  7.968 9.781 7.992 9.865 ;
     RECT  23.952 9.721 24.504 9.865 ;
     RECT  11.04 9.829 12.024 9.913 ;
     RECT  7.296 9.925 7.32 10.027 ;
     RECT  32.496 9.587 33.048 10.219 ;
     RECT  17.904 8.761 20.136 10.229 ;
     RECT  21.264 9.721 22.968 10.229 ;
     RECT  16.44 8.427 16.752 10.271 ;
     RECT  16.44 10.271 16.872 10.355 ;
     RECT  16.44 10.355 16.752 10.515 ;
     RECT  15.456 10.515 16.752 10.603 ;
     RECT  24.048 9.865 24.504 10.677 ;
     RECT  34.176 8.003 34.2 10.707 ;
     RECT  35.424 8.579 38.52 10.707 ;
     RECT  24.048 10.677 24.936 10.765 ;
     RECT  34.176 10.707 38.52 10.795 ;
     RECT  17.904 10.229 22.968 10.805 ;
     RECT  14.832 10.869 14.856 11.051 ;
     RECT  26.448 8.531 30.888 11.125 ;
     RECT  25.68 11.125 30.888 11.219 ;
     RECT  17.856 10.805 22.968 11.253 ;
     RECT  11.04 9.913 11.352 11.445 ;
     RECT  34.176 10.795 34.2 11.459 ;
     RECT  14.256 11.423 14.28 11.507 ;
     RECT  10.848 11.445 11.352 11.509 ;
     RECT  26.448 11.219 30.888 11.615 ;
     RECT  26.448 11.615 31.368 11.699 ;
     RECT  16.44 10.603 16.752 12.143 ;
     RECT  17.808 11.253 22.968 12.143 ;
     RECT  24.048 10.765 24.504 12.149 ;
     RECT  10.224 11.509 11.352 12.181 ;
     RECT  14.448 12.191 14.472 12.213 ;
     RECT  9.648 12.181 11.352 12.267 ;
     RECT  16.44 12.143 22.968 12.275 ;
     RECT  14.448 12.213 15.24 12.709 ;
     RECT  14.256 12.709 15.24 12.793 ;
     RECT  8.304 12.767 8.328 12.851 ;
     RECT  14.544 12.793 15.24 13.109 ;
     RECT  35.424 10.795 38.52 13.139 ;
     RECT  16.44 12.275 16.752 13.365 ;
     RECT  17.808 12.275 22.968 13.365 ;
     RECT  12.624 13.429 12.648 13.525 ;
     RECT  12.528 13.525 12.648 13.611 ;
     RECT  32.544 10.219 33.048 13.619 ;
     RECT  14.544 13.109 15.384 13.621 ;
     RECT  16.44 13.365 22.968 13.621 ;
     RECT  14.544 13.621 22.968 13.715 ;
     RECT  24.048 12.149 24.552 13.715 ;
     RECT  26.448 11.699 30.888 13.715 ;
     RECT  14.544 13.715 14.856 13.897 ;
     RECT  15.84 13.715 22.968 14.099 ;
     RECT  14.544 13.897 14.568 14.101 ;
     RECT  13.68 14.101 14.568 14.187 ;
     RECT  5.64 0.787 5.952 14.197 ;
     RECT  9.072 14.133 9.096 14.197 ;
     RECT  8.592 14.197 9.096 14.255 ;
     RECT  5.52 14.197 5.952 14.281 ;
     RECT  17.856 14.099 22.968 14.291 ;
     RECT  8.592 14.255 9.672 14.339 ;
     RECT  13.44 14.255 13.464 14.339 ;
     RECT  5.64 14.281 5.952 14.533 ;
     RECT  24.048 13.715 24.456 14.867 ;
     RECT  11.04 12.267 11.352 14.965 ;
     RECT  10.944 14.965 11.352 15.059 ;
     RECT  11.04 15.059 11.352 15.407 ;
     RECT  17.904 14.291 22.968 15.443 ;
     RECT  11.04 15.407 11.976 15.491 ;
     RECT  32.64 13.619 33.048 15.491 ;
     RECT  18.048 15.443 22.968 15.539 ;
     RECT  14.544 14.187 14.568 15.973 ;
     RECT  12.528 15.983 12.552 16.067 ;
     RECT  13.632 15.973 14.568 16.147 ;
     RECT  9.072 14.339 9.096 16.213 ;
     RECT  15.936 14.099 16.752 16.213 ;
     RECT  13.344 16.147 14.568 16.235 ;
     RECT  15.936 16.213 16.872 16.299 ;
     RECT  18.048 15.539 22.824 16.363 ;
     RECT  5.64 14.533 6.936 16.559 ;
     RECT  18.048 16.363 22.776 16.595 ;
     RECT  26.448 13.715 30.744 16.595 ;
     RECT  36.096 13.139 38.52 16.595 ;
     RECT  5.64 16.559 7.368 16.643 ;
     RECT  13.632 16.235 14.568 16.643 ;
     RECT  19.776 16.595 22.776 16.643 ;
     RECT  36.192 16.595 38.52 16.691 ;
     RECT  36.432 16.691 38.52 16.739 ;
     RECT  26.448 16.595 27.672 16.751 ;
     RECT  8.544 16.213 9.096 16.811 ;
     RECT  5.64 16.643 7.32 16.845 ;
     RECT  24.048 14.867 24.168 17.067 ;
     RECT  26.208 16.751 27.672 17.067 ;
     RECT  11.04 15.491 11.352 17.077 ;
     RECT  15.936 16.299 16.752 17.123 ;
     RECT  19.776 16.643 22.344 17.123 ;
     RECT  9.216 17.077 9.24 17.171 ;
     RECT  10.224 17.077 12.312 17.171 ;
     RECT  14.064 16.643 14.568 17.643 ;
     RECT  19.776 17.123 22.152 17.653 ;
     RECT  36.816 16.739 38.52 17.699 ;
     RECT  11.04 17.171 11.592 17.747 ;
     RECT  14.976 17.653 15 17.747 ;
     RECT  25.152 17.653 25.176 17.891 ;
     RECT  16.44 17.123 16.752 18.181 ;
     RECT  11.04 17.747 11.496 18.229 ;
     RECT  24.048 17.067 24.072 18.229 ;
     RECT  10.176 18.229 11.496 18.323 ;
     RECT  16.44 18.181 16.92 18.421 ;
     RECT  26.448 17.067 27.672 18.421 ;
     RECT  28.704 16.595 30.744 18.421 ;
     RECT  15.984 18.421 16.92 18.505 ;
     RECT  19.296 17.653 22.152 18.643 ;
     RECT  16.32 18.505 16.92 18.709 ;
     RECT  18.048 16.595 18.264 18.709 ;
     RECT  10.224 18.323 11.352 18.745 ;
     RECT  13.968 17.653 13.992 18.805 ;
     RECT  16.32 18.709 18.264 18.805 ;
     RECT  19.296 18.643 22.632 18.805 ;
     RECT  13.968 18.805 14.28 18.899 ;
     RECT  26.448 18.421 30.744 18.911 ;
     RECT  10.848 18.745 11.352 18.947 ;
     RECT  26.448 18.911 30.84 18.995 ;
     RECT  16.32 18.805 22.632 19.061 ;
     RECT  16.32 19.061 22.824 19.189 ;
     RECT  32.64 15.491 32.952 19.189 ;
     RECT  13.488 19.141 13.512 19.243 ;
     RECT  31.92 19.189 32.952 19.273 ;
     RECT  16.32 19.189 22.92 19.285 ;
     RECT  23.904 18.229 24.072 19.285 ;
     RECT  16.32 19.285 24.072 19.371 ;
     RECT  10.944 18.947 11.352 19.405 ;
     RECT  23.904 19.371 24.072 19.427 ;
     RECT  36.816 17.699 38.352 19.427 ;
     RECT  12.528 19.381 12.552 19.475 ;
     RECT  16.32 19.371 22.344 19.765 ;
     RECT  15.984 19.765 22.344 19.849 ;
     RECT  24.048 19.427 24.072 19.861 ;
     RECT  26.448 18.995 30.744 20.053 ;
     RECT  32.64 19.273 32.952 20.053 ;
     RECT  26.448 20.053 31.368 20.139 ;
     RECT  32.64 20.053 33.048 20.149 ;
     RECT  32.64 20.149 33.672 20.233 ;
     RECT  32.64 20.233 33.048 20.331 ;
     RECT  26.448 20.139 30.84 20.339 ;
     RECT  24.048 19.861 24.984 20.447 ;
     RECT  24.048 20.447 25.464 20.531 ;
     RECT  14.4 20.469 14.424 20.557 ;
     RECT  26.448 20.339 28.728 20.579 ;
     RECT  26.448 20.579 27.552 20.597 ;
     RECT  16.08 19.849 22.344 20.617 ;
     RECT  12.768 20.533 12.792 20.627 ;
     RECT  24.048 20.531 24.504 20.627 ;
     RECT  30.048 20.339 30.84 20.723 ;
     RECT  5.64 16.845 7.128 20.831 ;
     RECT  25.536 20.597 27.552 20.843 ;
     RECT  11.04 19.405 11.352 20.869 ;
     RECT  5.64 20.831 7.992 20.915 ;
     RECT  13.872 20.883 13.896 20.971 ;
     RECT  16.44 20.617 22.344 21.045 ;
     RECT  13.632 21.109 13.8 21.193 ;
     RECT  26.208 20.843 27.552 21.193 ;
     RECT  5.64 20.915 7.128 21.267 ;
     RECT  24.048 20.627 24.072 21.349 ;
     RECT  31.344 21.397 31.368 21.483 ;
     RECT  16.44 21.045 22.92 21.541 ;
     RECT  23.904 21.349 24.072 21.541 ;
     RECT  28.704 20.579 28.728 21.589 ;
     RECT  16.44 21.541 24.072 21.599 ;
     RECT  5.52 21.267 7.128 21.611 ;
     RECT  13.776 21.193 13.8 21.611 ;
     RECT  28.704 21.589 29.016 21.675 ;
     RECT  16.44 21.599 24.936 21.683 ;
     RECT  36.816 19.427 36.936 21.683 ;
     RECT  34.176 21.651 34.2 21.739 ;
     RECT  8.544 21.925 8.568 22.009 ;
     RECT  10.848 20.869 11.352 22.133 ;
     RECT  14.544 22.099 14.568 22.187 ;
     RECT  10.608 22.133 11.352 22.221 ;
     RECT  16.44 21.683 24.888 22.251 ;
     RECT  13.104 22.319 13.128 22.403 ;
     RECT  26.448 21.193 27.552 22.453 ;
     RECT  28.704 21.675 28.728 22.453 ;
     RECT  10.656 22.221 11.352 22.507 ;
     RECT  16.44 22.251 24.072 22.537 ;
     RECT  16.44 22.537 22.92 22.549 ;
     RECT  26.448 22.453 28.728 22.787 ;
     RECT  5.64 21.611 7.128 22.943 ;
     RECT  26.448 22.787 27.672 22.943 ;
     RECT  5.64 22.943 7.992 23.027 ;
     RECT  26.112 22.943 27.672 23.027 ;
     RECT  30.048 20.723 30.312 23.029 ;
     RECT  16.272 22.549 22.92 23.083 ;
     RECT  9.12 23.029 9.144 23.113 ;
     RECT  26.256 23.027 27.672 23.113 ;
     RECT  9.744 23.519 9.768 23.603 ;
     RECT  16.272 23.083 22.152 23.605 ;
     RECT  24.048 22.537 24.072 23.605 ;
     RECT  28.704 22.787 28.728 23.635 ;
     RECT  29.952 23.029 30.312 23.635 ;
     RECT  14.688 23.509 14.712 23.669 ;
     RECT  15.984 23.605 22.152 23.699 ;
     RECT  35.328 23.605 35.352 23.699 ;
     RECT  23.328 23.605 24.072 23.701 ;
     RECT  13.008 23.541 13.032 23.763 ;
     RECT  14.496 23.669 14.712 23.763 ;
     RECT  13.008 23.763 14.712 23.787 ;
     RECT  23.328 23.701 24.168 23.787 ;
     RECT  34.464 23.701 34.488 23.787 ;
     RECT  4.176 22.741 4.2 23.827 ;
     RECT  3.648 23.827 4.2 23.845 ;
     RECT  13.104 23.787 14.712 23.851 ;
     RECT  13.104 23.851 13.368 23.881 ;
     RECT  3.648 23.845 4.392 23.915 ;
     RECT  26.256 23.113 27.552 23.915 ;
     RECT  4.368 23.915 4.392 23.929 ;
     RECT  23.328 23.787 24.072 23.929 ;
     RECT  16.44 23.699 18.504 23.987 ;
     RECT  14.64 23.851 14.712 24.047 ;
     RECT  14.64 24.047 15.432 24.131 ;
     RECT  26.448 23.915 27.552 24.147 ;
     RECT  28.704 23.635 30.312 24.147 ;
     RECT  11.04 22.507 11.352 24.277 ;
     RECT  14.64 24.131 14.664 24.363 ;
     RECT  8.544 24.373 8.568 24.457 ;
     RECT  23.376 23.929 24.072 24.457 ;
     RECT  26.448 24.147 30.312 24.505 ;
     RECT  19.776 23.699 22.152 24.619 ;
     RECT  11.04 24.277 11.784 24.623 ;
     RECT  36.816 21.683 36.84 24.623 ;
     RECT  32.64 20.331 32.952 24.629 ;
     RECT  26.448 24.505 28.728 24.683 ;
     RECT  11.04 24.623 12.024 24.707 ;
     RECT  36.48 24.623 36.84 24.707 ;
     RECT  19.968 24.619 22.152 24.815 ;
     RECT  16.44 23.987 18.408 24.875 ;
     RECT  13.344 23.881 13.368 24.901 ;
     RECT  5.64 23.027 7.128 24.949 ;
     RECT  32.544 24.629 32.952 24.949 ;
     RECT  12.768 24.901 13.368 25.003 ;
     RECT  14.496 24.901 14.52 25.003 ;
     RECT  32.544 24.949 33.096 25.007 ;
     RECT  5.64 24.949 7.464 25.013 ;
     RECT  31.92 25.007 33.096 25.043 ;
     RECT  19.968 24.815 22.248 25.055 ;
     RECT  5.64 25.013 7.896 25.101 ;
     RECT  19.968 25.055 22.776 25.139 ;
     RECT  31.92 25.043 32.952 25.273 ;
     RECT  30.048 24.505 30.312 25.299 ;
     RECT  30.048 25.299 31.032 25.387 ;
     RECT  16.44 24.875 18.264 25.631 ;
     RECT  15.84 25.631 18.264 25.715 ;
     RECT  36.816 24.707 36.84 25.775 ;
     RECT  38.04 19.427 38.352 25.775 ;
     RECT  5.64 25.101 7.464 25.781 ;
     RECT  15.408 25.775 15.432 25.859 ;
     RECT  16.44 25.715 18.264 25.861 ;
     RECT  19.968 25.139 22.152 25.861 ;
     RECT  5.328 25.781 7.464 25.869 ;
     RECT  16.44 25.861 22.152 26.027 ;
     RECT  36.816 25.775 38.352 26.041 ;
     RECT  11.04 24.707 11.352 26.207 ;
     RECT  10.368 26.207 11.976 26.229 ;
     RECT  26.448 24.683 27.552 26.229 ;
     RECT  10.08 26.229 11.976 26.293 ;
     RECT  9.696 26.293 11.976 26.339 ;
     RECT  9.696 26.339 9.72 26.377 ;
     RECT  19.776 26.027 22.152 26.387 ;
     RECT  25.68 26.229 27.552 26.445 ;
     RECT  14.448 26.389 14.856 26.483 ;
     RECT  13.344 25.003 13.368 26.485 ;
     RECT  11.04 26.339 11.976 26.613 ;
     RECT  13.2 26.485 13.368 26.613 ;
     RECT  26.448 26.445 27.552 26.707 ;
     RECT  8.64 26.707 8.664 26.795 ;
     RECT  25.392 26.613 25.416 26.795 ;
     RECT  26.448 26.707 27.672 26.795 ;
     RECT  25.056 26.805 25.08 26.893 ;
     RECT  19.872 26.387 22.152 26.915 ;
     RECT  16.44 26.027 18.696 27.189 ;
     RECT  35.328 25.631 35.352 27.283 ;
     RECT  34.464 27.283 35.352 27.337 ;
     RECT  19.92 26.915 22.152 27.359 ;
     RECT  16.44 27.189 18.888 27.371 ;
     RECT  5.64 25.869 7.464 27.381 ;
     RECT  11.04 26.613 13.368 27.435 ;
     RECT  12.384 27.435 13.368 27.443 ;
     RECT  19.92 27.359 22.248 27.443 ;
     RECT  30.048 25.387 30.312 27.445 ;
     RECT  5.328 27.381 7.464 27.469 ;
     RECT  12.816 27.443 13.368 27.573 ;
     RECT  14.448 26.483 14.472 27.573 ;
     RECT  12.816 27.573 14.472 27.661 ;
     RECT  9.312 27.283 9.432 27.829 ;
     RECT  11.04 27.435 11.352 27.829 ;
     RECT  16.44 27.371 18.84 27.829 ;
     RECT  26.448 26.795 27.552 27.829 ;
     RECT  34.464 27.337 34.824 27.913 ;
     RECT  9.312 27.829 11.352 27.971 ;
     RECT  25.584 27.829 27.552 27.971 ;
     RECT  26.448 27.971 27.552 28.405 ;
     RECT  28.704 24.683 28.728 28.405 ;
     RECT  30.048 27.445 30.744 28.405 ;
     RECT  24.048 24.457 24.072 28.453 ;
     RECT  34.176 28.021 34.2 28.459 ;
     RECT  26.448 28.405 28.728 28.489 ;
     RECT  30.048 28.405 31.08 28.547 ;
     RECT  11.04 27.971 11.352 28.981 ;
     RECT  14.448 27.661 14.472 28.981 ;
     RECT  15.456 27.829 18.84 28.981 ;
     RECT  20.688 27.443 22.152 28.981 ;
     RECT  8.688 28.837 8.712 29.035 ;
     RECT  23.856 28.453 24.072 29.035 ;
     RECT  28.656 28.489 28.728 29.035 ;
     RECT  5.64 27.469 7.464 29.039 ;
     RECT  10.128 28.981 11.352 29.045 ;
     RECT  12.816 27.661 13.368 29.045 ;
     RECT  20.016 28.981 22.152 29.087 ;
     RECT  34.8 29.039 34.824 29.123 ;
     RECT  10.128 29.045 13.368 29.163 ;
     RECT  14.448 28.981 18.84 29.173 ;
     RECT  36.816 26.041 36.84 29.279 ;
     RECT  14.448 29.173 18.936 29.355 ;
     RECT  20.016 29.087 22.248 29.365 ;
     RECT  19.392 29.365 22.248 29.461 ;
     RECT  30.048 28.547 30.984 29.483 ;
     RECT  5.64 29.039 8.088 29.523 ;
     RECT  5.52 29.523 8.088 29.547 ;
     RECT  35.904 29.279 36.84 29.547 ;
     RECT  14.448 29.355 18.264 29.555 ;
     RECT  5.52 29.547 7.848 29.611 ;
     RECT  10.752 29.163 13.368 29.699 ;
     RECT  15.888 29.555 18.264 29.699 ;
     RECT  19.392 29.461 22.776 29.699 ;
     RECT  16.32 29.699 18.264 29.843 ;
     RECT  26.448 28.489 27.552 29.877 ;
     RECT  23.952 29.035 24.072 29.907 ;
     RECT  23.952 29.907 24.888 29.995 ;
     RECT  23.952 29.995 24.552 30.073 ;
     RECT  34.224 29.989 34.248 30.073 ;
     RECT  32.64 25.273 32.952 30.191 ;
     RECT  23.952 30.073 24.072 30.239 ;
     RECT  28.704 29.035 28.728 30.239 ;
     RECT  32.16 30.191 32.952 30.261 ;
     RECT  19.392 29.699 22.152 30.275 ;
     RECT  30.048 29.483 30.84 30.315 ;
     RECT  23.376 30.239 24.072 30.323 ;
     RECT  28.704 30.239 29.064 30.323 ;
     RECT  26.304 29.877 27.552 30.325 ;
     RECT  5.64 29.611 7.848 30.349 ;
     RECT  32.064 30.261 32.952 30.349 ;
     RECT  14.448 29.555 14.808 30.409 ;
     RECT  26.304 30.325 27.672 30.409 ;
     RECT  11.04 29.699 13.368 30.517 ;
     RECT  14.448 30.409 14.76 30.517 ;
     RECT  32.64 30.349 32.952 30.565 ;
     RECT  16.44 29.843 18.264 30.645 ;
     RECT  30.048 30.315 30.312 30.645 ;
     RECT  32.64 30.565 33.672 30.649 ;
     RECT  35.328 30.133 35.352 30.675 ;
     RECT  36.48 29.547 36.84 30.675 ;
     RECT  29.76 30.645 30.312 30.755 ;
     RECT  26.304 30.409 27.552 30.763 ;
     RECT  34.944 30.675 36.84 30.763 ;
     RECT  11.04 30.517 14.76 30.841 ;
     RECT  4.464 28.981 4.488 31.141 ;
     RECT  5.64 30.349 7.464 31.251 ;
     RECT  24.048 30.323 24.072 31.315 ;
     RECT  4.32 31.141 4.488 31.343 ;
     RECT  5.52 31.251 7.464 31.343 ;
     RECT  11.04 30.841 13.368 31.343 ;
     RECT  32.64 30.649 33.096 31.369 ;
     RECT  23.952 31.315 24.072 31.403 ;
     RECT  8.496 31.343 8.52 31.427 ;
     RECT  10.128 31.343 13.368 31.427 ;
     RECT  21.6 30.275 22.152 31.477 ;
     RECT  19.392 30.275 20.472 31.525 ;
     RECT  10.848 31.427 13.368 31.531 ;
     RECT  9.072 31.477 9.096 31.571 ;
     RECT  16.44 30.645 18.312 31.669 ;
     RECT  19.392 31.525 20.568 31.669 ;
     RECT  12.528 31.531 13.368 31.859 ;
     RECT  16.44 31.669 20.568 31.891 ;
     RECT  21.552 31.477 22.152 31.891 ;
     RECT  4.32 31.343 7.464 31.915 ;
     RECT  35.328 31.861 35.352 31.919 ;
     RECT  34.944 31.919 35.352 31.945 ;
     RECT  34.944 31.945 34.968 31.957 ;
     RECT  16.44 31.891 22.152 31.979 ;
     RECT  16.44 31.979 19.272 32.003 ;
     RECT  34.848 31.957 34.968 32.003 ;
     RECT  34.848 32.003 34.872 32.043 ;
     RECT  26.448 30.763 27.552 32.373 ;
     RECT  12.816 31.859 13.368 32.403 ;
     RECT  2.832 32.341 2.856 32.491 ;
     RECT  16.44 32.003 18.84 32.491 ;
     RECT  32.64 31.369 32.952 32.501 ;
     RECT  10.848 31.531 11.496 32.757 ;
     RECT  10.416 32.757 11.496 32.867 ;
     RECT  31.68 32.501 32.952 32.867 ;
     RECT  30.048 30.755 30.312 32.917 ;
     RECT  25.44 32.373 27.552 32.927 ;
     RECT  30.048 32.917 31.032 33.003 ;
     RECT  25.104 32.927 27.552 33.011 ;
     RECT  24.048 31.403 24.072 33.071 ;
     RECT  11.04 32.867 11.496 33.077 ;
     RECT  12.816 32.403 13.656 33.077 ;
     RECT  11.04 33.077 13.656 33.155 ;
     RECT  23.328 33.071 24.072 33.155 ;
     RECT  21.6 31.979 22.152 33.263 ;
     RECT  20.544 33.205 20.568 33.299 ;
     RECT  21.6 33.263 22.824 33.347 ;
     RECT  3.168 33.269 3.192 33.395 ;
     RECT  11.04 33.155 13.368 33.683 ;
     RECT  19.392 33.263 19.416 33.781 ;
     RECT  16.44 32.491 18.264 33.839 ;
     RECT  19.392 33.781 19.512 33.839 ;
     RECT  16.44 33.839 19.512 33.865 ;
     RECT  25.68 33.011 27.552 34.213 ;
     RECT  14.784 32.309 14.808 34.357 ;
     RECT  25.536 34.213 27.552 34.411 ;
     RECT  9.504 34.357 9.528 34.451 ;
     RECT  14.784 34.357 15.432 34.451 ;
     RECT  16.44 33.865 18.84 34.539 ;
     RECT  20.544 34.463 20.568 34.547 ;
     RECT  32.64 32.867 32.952 34.597 ;
     RECT  9.12 34.597 9.144 34.681 ;
     RECT  14.784 34.451 14.952 34.681 ;
     RECT  11.04 33.683 11.352 34.707 ;
     RECT  32.496 34.597 32.952 34.707 ;
     RECT  10.656 34.707 11.352 34.795 ;
     RECT  14.784 34.681 14.808 34.795 ;
     RECT  31.872 34.707 32.952 34.795 ;
     RECT  9.072 34.799 9.096 34.883 ;
     RECT  12.816 33.683 13.368 34.933 ;
     RECT  31.92 34.795 32.952 35.115 ;
     RECT  8.544 35.125 8.568 35.209 ;
     RECT  26.208 34.411 27.552 35.209 ;
     RECT  19.296 34.933 19.32 35.221 ;
     RECT  19.296 35.221 19.992 35.307 ;
     RECT  32.448 35.115 32.952 35.411 ;
     RECT  35.328 35.317 35.352 35.411 ;
     RECT  4.32 31.915 4.488 35.637 ;
     RECT  5.64 31.915 7.464 35.637 ;
     RECT  16.44 34.539 18.264 35.701 ;
     RECT  19.296 35.307 19.416 35.701 ;
     RECT  4.32 35.637 7.464 35.725 ;
     RECT  12.816 34.933 13.656 35.829 ;
     RECT  36.816 30.763 36.84 35.829 ;
     RECT  16.44 35.701 19.416 35.891 ;
     RECT  36.384 35.829 36.84 35.917 ;
     RECT  12.528 35.829 13.656 35.947 ;
     RECT  9.168 35.893 9.192 35.977 ;
     RECT  28.704 30.323 28.728 36.051 ;
     RECT  16.44 35.891 18.84 36.083 ;
     RECT  31.344 35.999 31.368 36.083 ;
     RECT  21.6 33.347 22.152 36.115 ;
     RECT  21.264 36.115 22.872 36.133 ;
     RECT  14.064 36.213 14.088 36.301 ;
     RECT  21.264 36.133 23.016 36.331 ;
     RECT  26.448 35.209 27.552 36.373 ;
     RECT  16.44 36.083 18.6 36.395 ;
     RECT  28.704 36.051 28.776 36.469 ;
     RECT  30.048 33.003 30.312 36.469 ;
     RECT  28.704 36.469 30.312 36.553 ;
     RECT  11.04 34.795 11.352 36.789 ;
     RECT  12.528 35.947 12.84 36.789 ;
     RECT  24.048 33.155 24.072 36.789 ;
     RECT  23.952 36.789 24.072 36.853 ;
     RECT  11.04 36.789 12.84 36.877 ;
     RECT  21.264 36.331 22.776 36.911 ;
     RECT  23.952 36.853 24.552 36.947 ;
     RECT  21.12 36.911 22.776 36.995 ;
     RECT  23.952 36.947 24.072 37.043 ;
     RECT  5.64 35.725 7.464 37.045 ;
     RECT  5.64 37.045 8.088 37.139 ;
     RECT  12.528 36.877 12.84 37.151 ;
     RECT  11.04 36.877 11.352 37.237 ;
     RECT  26.448 36.373 27.672 37.285 ;
     RECT  28.704 36.553 28.728 37.285 ;
     RECT  19.392 37.285 19.416 37.369 ;
     RECT  26.448 37.285 28.728 37.369 ;
     RECT  21.6 36.995 22.776 37.525 ;
     RECT  28.704 37.369 28.728 37.535 ;
     RECT  30.048 36.553 30.312 37.535 ;
     RECT  16.44 36.395 18.264 37.557 ;
     RECT  32.64 35.411 32.952 37.557 ;
     RECT  21.6 37.525 22.824 37.611 ;
     RECT  10.944 37.237 11.352 37.619 ;
     RECT  28.704 37.535 30.312 37.619 ;
     RECT  34.224 37.535 34.248 37.619 ;
     RECT  4.32 35.725 4.488 37.621 ;
     RECT  5.64 37.139 7.8 37.621 ;
     RECT  4.32 37.621 7.8 37.645 ;
     RECT  4.32 37.645 7.464 37.715 ;
     RECT  32.112 37.557 32.952 37.717 ;
     RECT  32.112 37.717 33.384 37.727 ;
     RECT  21.6 37.611 22.44 37.739 ;
     RECT  31.296 37.727 33.384 37.803 ;
     RECT  31.296 37.803 32.952 37.811 ;
     RECT  31.344 37.811 32.952 37.955 ;
     RECT  19.968 37.919 19.992 38.003 ;
     RECT  12.528 37.151 13.656 38.005 ;
     RECT  28.704 37.619 28.92 38.123 ;
     RECT  11.04 37.619 11.352 38.133 ;
     RECT  31.344 37.955 31.368 38.187 ;
     RECT  12.528 38.005 13.752 38.197 ;
     RECT  11.04 38.133 11.448 38.221 ;
     RECT  12.48 38.197 13.752 38.291 ;
     RECT  21.6 37.739 22.152 38.355 ;
     RECT  21.408 38.355 22.152 38.443 ;
     RECT  26.448 37.369 27.552 38.517 ;
     RECT  28.704 38.123 28.728 38.517 ;
     RECT  16.44 37.557 18.36 38.629 ;
     RECT  24.048 37.043 24.072 38.629 ;
     RECT  12.528 38.291 13.752 38.819 ;
     RECT  26.448 38.517 28.728 38.819 ;
     RECT  12.816 38.819 13.752 39.157 ;
     RECT  21.648 38.443 22.152 39.157 ;
     RECT  24 38.629 24.072 39.157 ;
     RECT  28.704 38.819 28.728 39.205 ;
     RECT  30.048 37.619 30.312 39.205 ;
     RECT  12.816 39.157 14.616 39.221 ;
     RECT  15.984 38.629 18.36 39.221 ;
     RECT  19.872 38.645 19.896 39.221 ;
     RECT  23.328 39.157 24.072 39.241 ;
     RECT  12.816 39.221 18.36 39.275 ;
     RECT  28.704 39.205 30.312 39.289 ;
     RECT  9.072 39.221 9.096 39.395 ;
     RECT  19.872 39.221 20.424 39.685 ;
     RECT  19.344 39.685 20.424 39.733 ;
     RECT  21.648 39.157 22.248 39.733 ;
     RECT  26.448 38.819 27.552 39.733 ;
     RECT  32.64 37.955 32.952 39.781 ;
     RECT  34.512 39.637 34.536 39.781 ;
     RECT  32.64 39.781 34.536 39.787 ;
     RECT  19.344 39.733 22.248 39.817 ;
     RECT  11.04 38.221 11.352 39.829 ;
     RECT  32.64 39.787 33.672 39.839 ;
     RECT  5.64 37.715 7.464 39.861 ;
     RECT  10.608 39.829 11.352 39.861 ;
     RECT  12.816 39.275 18.264 39.861 ;
     RECT  19.344 39.817 20.52 39.865 ;
     RECT  32.496 39.839 33.672 39.865 ;
     RECT  32.496 39.865 33.144 39.877 ;
     RECT  10.608 39.861 18.264 39.915 ;
     RECT  21.696 39.817 22.248 39.925 ;
     RECT  5.64 39.861 7.896 39.949 ;
     RECT  10.944 39.915 18.264 39.949 ;
     RECT  31.92 39.877 33.144 39.949 ;
     RECT  31.92 39.949 32.952 39.979 ;
     RECT  8.976 39.925 9 40.019 ;
     RECT  24 39.241 24.072 40.019 ;
     RECT  21.696 39.925 22.872 40.107 ;
     RECT  12.816 39.949 18.264 40.299 ;
     RECT  25.824 39.733 27.552 40.501 ;
     RECT  10.944 39.949 11.352 40.595 ;
     RECT  12.816 40.299 14.232 40.595 ;
     RECT  31.296 40.501 31.368 40.595 ;
     RECT  15.36 40.299 18.264 40.693 ;
     RECT  25.2 40.501 27.552 40.693 ;
     RECT  25.104 40.693 27.552 40.777 ;
     RECT  31.344 40.595 31.368 40.875 ;
     RECT  25.824 40.777 27.552 40.933 ;
     RECT  28.704 39.289 28.728 40.933 ;
     RECT  12.816 40.595 13.8 40.939 ;
     RECT  4.32 37.715 4.488 40.991 ;
     RECT  8.784 40.147 8.808 40.991 ;
     RECT  19.824 39.865 20.52 40.991 ;
     RECT  21.696 40.107 22.152 40.991 ;
     RECT  25.824 40.933 28.728 41.017 ;
     RECT  8.784 40.991 8.904 41.075 ;
     RECT  25.824 41.017 27.552 41.075 ;
     RECT  5.64 39.949 7.464 41.107 ;
     RECT  5.64 41.107 8.04 41.195 ;
     RECT  3.984 40.991 4.488 41.365 ;
     RECT  3.408 41.365 4.488 41.451 ;
     RECT  15.36 40.693 18.84 41.557 ;
     RECT  19.824 40.991 22.152 41.557 ;
     RECT  32.64 39.979 32.952 41.567 ;
     RECT  15.36 41.557 22.152 41.593 ;
     RECT  12.816 40.939 13.512 41.651 ;
     RECT  15.36 41.593 20.472 41.653 ;
     RECT  32.544 41.567 32.952 41.653 ;
     RECT  24.048 40.019 24.072 41.711 ;
     RECT  23.952 41.711 24.072 41.759 ;
     RECT  23.856 41.759 24.072 41.843 ;
     RECT  21.696 41.593 22.152 41.845 ;
     RECT  30.048 39.289 30.312 41.909 ;
     RECT  32.448 41.653 32.952 41.951 ;
     RECT  26.448 41.075 27.552 41.989 ;
     RECT  28.704 41.017 28.728 41.989 ;
     RECT  29.712 41.909 30.312 42.035 ;
     RECT  31.92 41.951 32.952 42.035 ;
     RECT  21.696 41.845 23.016 42.091 ;
     RECT  15.024 41.653 20.472 42.101 ;
     RECT  11.04 40.595 11.352 42.143 ;
     RECT  14.976 42.101 20.472 42.143 ;
     RECT  12.816 41.651 13.176 42.155 ;
     RECT  29.808 42.035 30.312 42.155 ;
     RECT  14.208 42.143 20.472 42.189 ;
     RECT  31.296 42.101 31.32 42.189 ;
     RECT  14.208 42.189 14.232 42.227 ;
     RECT  15.36 42.189 20.472 42.227 ;
     RECT  36.816 35.917 36.84 42.227 ;
     RECT  10.896 42.143 11.352 42.387 ;
     RECT  12.816 42.155 12.84 42.387 ;
     RECT  9.936 42.387 11.352 42.475 ;
     RECT  12.72 42.387 12.84 42.475 ;
     RECT  16.44 42.227 19.464 42.505 ;
     RECT  5.64 41.195 7.464 42.613 ;
     RECT  32.64 42.035 32.952 42.677 ;
     RECT  19.44 42.505 19.464 42.731 ;
     RECT  26.448 41.989 28.728 42.741 ;
     RECT  21.696 42.091 22.872 42.745 ;
     RECT  5.64 42.613 7.512 42.795 ;
     RECT  9.456 42.741 9.48 42.829 ;
     RECT  10.512 42.475 11.352 42.829 ;
     RECT  26.064 42.741 28.728 42.829 ;
     RECT  32.64 42.677 33.096 42.859 ;
     RECT  26.448 42.829 28.728 43.081 ;
     RECT  9.216 43.141 9.24 43.219 ;
     RECT  24.048 41.843 24.072 43.253 ;
     RECT  20.448 42.227 20.472 43.295 ;
     RECT  21.696 42.745 22.248 43.295 ;
     RECT  8.496 43.219 9.24 43.307 ;
     RECT  20.448 43.295 22.248 43.321 ;
     RECT  25.392 43.295 25.416 43.379 ;
     RECT  12.816 42.475 12.84 43.509 ;
     RECT  14.208 43.295 14.232 43.525 ;
     RECT  15.36 42.227 15.384 43.525 ;
     RECT  28.704 43.081 28.728 43.573 ;
     RECT  30.048 42.155 30.312 43.573 ;
     RECT  28.704 43.573 30.312 43.657 ;
     RECT  14.208 43.525 15.384 43.691 ;
     RECT  26.448 43.081 27.672 43.755 ;
     RECT  12.816 43.509 13.224 43.763 ;
     RECT  26.448 43.755 27.552 43.813 ;
     RECT  20.448 43.321 22.152 43.819 ;
     RECT  16.44 42.505 18.264 43.871 ;
     RECT  20.448 43.819 20.472 43.871 ;
     RECT  15.36 43.691 15.384 43.883 ;
     RECT  19.92 43.871 20.472 43.947 ;
     RECT  13.824 43.871 13.848 43.955 ;
     RECT  16.44 43.871 18.504 43.955 ;
     RECT  19.92 43.947 19.944 43.955 ;
     RECT  32.64 42.859 32.952 43.987 ;
     RECT  16.44 43.955 18.264 44.021 ;
     RECT  31.968 43.987 32.952 44.075 ;
     RECT  16.32 44.021 18.264 44.195 ;
     RECT  25.92 43.813 27.552 44.597 ;
     RECT  25.344 44.597 27.552 44.685 ;
     RECT  35.664 44.597 35.688 44.723 ;
     RECT  25.776 44.685 27.552 44.725 ;
     RECT  21.696 43.819 22.152 44.965 ;
     RECT  23.472 43.253 24.072 44.965 ;
     RECT  30.048 43.657 30.312 44.965 ;
     RECT  21.696 44.965 24.072 45.157 ;
     RECT  29.712 44.965 30.312 45.157 ;
     RECT  4.32 41.451 4.488 45.167 ;
     RECT  12.816 43.763 12.84 45.167 ;
     RECT  28.704 43.657 28.728 45.215 ;
     RECT  29.712 45.157 30.84 45.215 ;
     RECT  5.64 42.795 7.464 45.237 ;
     RECT  32.64 44.075 32.952 45.237 ;
     RECT  9.024 45.157 9.048 45.241 ;
     RECT  21.12 45.157 24.168 45.241 ;
     RECT  32.64 45.237 33.336 45.325 ;
     RECT  11.04 42.829 11.352 45.397 ;
     RECT  12.432 45.167 12.84 45.397 ;
     RECT  11.04 45.397 12.84 45.483 ;
     RECT  21.696 45.241 24.168 45.493 ;
     RECT  21.696 45.493 24.504 45.577 ;
     RECT  4.32 45.167 4.536 45.599 ;
     RECT  5.64 45.237 7.8 45.599 ;
     RECT  16.44 44.195 18.264 45.599 ;
     RECT  15.024 45.599 18.264 45.621 ;
     RECT  4.128 45.599 8.616 45.683 ;
     RECT  14.16 45.621 18.264 45.709 ;
     RECT  14.832 45.709 18.264 45.827 ;
     RECT  16.32 45.827 18.264 45.867 ;
     RECT  28.704 45.215 30.84 45.973 ;
     RECT  28.704 45.973 31.32 46.009 ;
     RECT  30.048 46.009 31.32 46.069 ;
     RECT  30.048 46.069 31.368 46.153 ;
     RECT  25.776 44.725 27.72 46.175 ;
     RECT  5.52 45.683 7.848 46.201 ;
     RECT  25.632 46.175 27.72 46.259 ;
     RECT  30.048 46.153 30.648 46.259 ;
     RECT  26.4 46.259 27.72 46.357 ;
     RECT  28.704 46.009 28.728 46.357 ;
     RECT  26.4 46.357 28.728 46.379 ;
     RECT  11.04 45.483 11.352 46.501 ;
     RECT  12.816 45.483 12.84 46.501 ;
     RECT  19.68 46.549 19.704 46.645 ;
     RECT  32.64 45.325 32.952 46.675 ;
     RECT  21.696 45.577 24.072 46.709 ;
     RECT  4.32 45.683 4.488 46.751 ;
     RECT  5.52 46.201 7.464 46.751 ;
     RECT  19.68 46.645 20.568 46.751 ;
     RECT  11.04 46.501 12.84 46.773 ;
     RECT  14.832 45.827 14.952 46.773 ;
     RECT  16.44 45.867 18.264 46.773 ;
     RECT  19.536 46.751 20.568 46.773 ;
     RECT  4.32 46.751 7.464 46.835 ;
     RECT  10.704 46.773 12.84 46.837 ;
     RECT  14.16 46.773 14.952 46.837 ;
     RECT  16.44 46.773 20.568 46.837 ;
     RECT  21.696 46.709 24.264 46.837 ;
     RECT  10.608 46.837 14.952 46.861 ;
     RECT  9.6 46.837 9.624 46.931 ;
     RECT  10.608 46.861 14.808 46.931 ;
     RECT  16.44 46.837 24.264 46.931 ;
     RECT  38.04 26.041 38.352 47.029 ;
     RECT  10.656 46.931 14.808 47.113 ;
     RECT  37.056 47.029 38.352 47.113 ;
     RECT  32.64 46.675 33.672 47.135 ;
     RECT  20.784 46.931 24.264 47.147 ;
     RECT  31.872 47.135 33.672 47.187 ;
     RECT  11.04 47.113 14.28 47.219 ;
     RECT  31.872 47.187 33.864 47.219 ;
     RECT  32.64 47.219 33.864 47.275 ;
     RECT  11.04 47.219 13.368 47.315 ;
     RECT  16.44 46.931 19.368 47.315 ;
     RECT  30.048 46.259 30.312 47.379 ;
     RECT  30 47.379 30.312 47.467 ;
     RECT  12.432 47.315 13.368 47.851 ;
     RECT  21.024 47.147 24.264 47.861 ;
     RECT  16.44 47.315 18.36 47.939 ;
     RECT  21.024 47.861 24.552 47.939 ;
     RECT  12.432 47.851 12.84 48.141 ;
     RECT  16.44 47.939 18.312 48.277 ;
     RECT  15.984 48.277 18.312 48.339 ;
     RECT  19.344 47.315 19.368 48.373 ;
     RECT  15.792 48.339 18.312 48.427 ;
     RECT  4.32 46.835 4.488 48.431 ;
     RECT  5.64 46.835 7.464 48.431 ;
     RECT  4.32 48.431 8.424 48.515 ;
     RECT  21.744 47.939 24.552 48.515 ;
     RECT  34.608 48.517 34.632 48.619 ;
     RECT  19.344 48.373 19.416 48.697 ;
     RECT  19.92 48.853 19.944 48.939 ;
     RECT  32.64 47.275 32.952 48.949 ;
     RECT  16.44 48.427 18.312 49.007 ;
     RECT  31.92 48.949 32.952 49.033 ;
     RECT  14.784 49.007 14.808 49.091 ;
     RECT  16.44 49.007 18.36 49.091 ;
     RECT  21.84 48.515 24.552 49.131 ;
     RECT  26.448 46.379 28.728 49.171 ;
     RECT  21.84 49.131 24.216 49.323 ;
     RECT  20.448 49.007 20.472 49.429 ;
     RECT  12.816 48.141 12.84 49.461 ;
     RECT  25.44 49.171 28.728 49.475 ;
     RECT  24.048 49.323 24.216 49.515 ;
     RECT  12.816 49.461 13.464 49.549 ;
     RECT  16.44 49.091 18.312 49.619 ;
     RECT  25.536 49.475 28.728 49.909 ;
     RECT  30.048 47.467 30.312 49.909 ;
     RECT  11.04 47.315 11.352 49.957 ;
     RECT  12.816 49.549 12.84 49.957 ;
     RECT  20.448 49.429 20.568 49.957 ;
     RECT  21.84 49.323 22.968 49.967 ;
     RECT  8.496 49.957 8.52 50.005 ;
     RECT  20.448 49.957 20.664 50.037 ;
     RECT  8.496 50.005 8.664 50.041 ;
     RECT  9.648 49.957 9.672 50.041 ;
     RECT  11.04 49.957 12.84 50.041 ;
     RECT  15.36 49.957 15.384 50.041 ;
     RECT  20.256 50.037 20.664 50.041 ;
     RECT  21.744 49.967 22.968 50.041 ;
     RECT  21.744 50.041 22.92 50.051 ;
     RECT  25.536 49.909 30.312 50.051 ;
     RECT  8.64 50.041 8.664 50.091 ;
     RECT  20.256 50.041 20.28 50.195 ;
     RECT  0.24 0.787 0.552 50.389 ;
     RECT  4.32 48.515 4.488 50.533 ;
     RECT  31.344 50.485 31.368 50.533 ;
     RECT  16.44 49.619 18.264 50.543 ;
     RECT  31.344 50.533 31.656 50.591 ;
     RECT  32.64 49.033 32.952 50.591 ;
     RECT  21.84 50.051 22.92 50.603 ;
     RECT  25.68 50.051 30.312 50.603 ;
     RECT  15.984 50.543 18.264 50.627 ;
     RECT  3.888 50.533 4.488 50.643 ;
     RECT  5.64 48.515 7.464 50.643 ;
     RECT  16.44 50.627 18.264 50.643 ;
     RECT  24.048 49.515 24.12 50.725 ;
     RECT  3.408 50.643 7.464 50.731 ;
     RECT  26.448 50.603 30.312 50.731 ;
     RECT  24.048 50.725 24.168 50.771 ;
     RECT  12.816 50.041 12.84 50.965 ;
     RECT  11.04 50.041 11.352 51.061 ;
     RECT  12.816 50.965 13.08 51.115 ;
     RECT  30.048 50.731 30.312 51.125 ;
     RECT  13.056 51.115 13.08 51.243 ;
     RECT  30.048 51.125 30.36 51.253 ;
     RECT  31.344 50.591 32.952 51.253 ;
     RECT  19.968 50.773 19.992 51.301 ;
     RECT  10.8 51.061 11.352 51.311 ;
     RECT  24.144 50.771 24.168 51.311 ;
     RECT  10.8 51.311 12.072 51.317 ;
     RECT  30.048 51.253 32.952 51.337 ;
     RECT  14.208 50.735 14.232 51.359 ;
     RECT  10.56 51.317 12.072 51.395 ;
     RECT  13.632 51.359 14.232 51.443 ;
     RECT  14.544 51.541 14.568 51.627 ;
     RECT  16.44 50.643 18.84 51.635 ;
     RECT  31.776 51.337 32.952 51.635 ;
     RECT  30.048 51.337 30.312 51.765 ;
     RECT  19.968 51.301 20.376 51.781 ;
     RECT  19.968 51.781 20.568 51.829 ;
     RECT  21.84 50.603 22.296 51.829 ;
     RECT  19.968 51.829 22.296 51.883 ;
     RECT  10.56 51.395 11.352 51.887 ;
     RECT  21.12 51.883 22.296 51.913 ;
     RECT  24.144 51.311 24.6 51.935 ;
     RECT  26.448 50.731 28.728 51.957 ;
     RECT  10.224 51.887 11.352 51.971 ;
     RECT  35.808 51.887 35.832 51.971 ;
     RECT  29.952 51.765 30.312 52.019 ;
     RECT  23.904 51.935 24.6 52.051 ;
     RECT  25.68 51.957 28.728 52.051 ;
     RECT  21.648 51.913 22.296 52.165 ;
     RECT  23.904 52.051 28.728 52.211 ;
     RECT  21.648 52.165 22.344 52.213 ;
     RECT  34.704 52.149 34.728 52.237 ;
     RECT  21.648 52.213 23.064 52.307 ;
     RECT  21.648 52.307 22.344 52.331 ;
     RECT  0.24 50.389 1.176 52.405 ;
     RECT  8.736 52.341 8.76 52.429 ;
     RECT  21.648 52.331 22.248 52.459 ;
     RECT  24.048 52.211 28.728 52.459 ;
     RECT  4.32 50.731 4.488 52.463 ;
     RECT  16.44 51.635 18.792 52.489 ;
     RECT  34.8 52.405 34.824 52.489 ;
     RECT  4.272 52.463 4.488 52.547 ;
     RECT  19.776 52.405 19.848 52.547 ;
     RECT  19.776 52.547 19.8 52.651 ;
     RECT  16.44 52.489 18.696 52.691 ;
     RECT  3.168 52.885 3.192 52.933 ;
     RECT  3.072 52.933 3.192 52.981 ;
     RECT  4.32 52.547 4.488 52.981 ;
     RECT  4.32 52.981 4.584 53.039 ;
     RECT  5.64 50.731 7.464 53.039 ;
     RECT  16.44 52.691 18.264 53.039 ;
     RECT  9.888 52.463 9.912 53.045 ;
     RECT  11.04 51.971 11.352 53.045 ;
     RECT  15.648 53.039 18.264 53.045 ;
     RECT  4.32 53.039 7.464 53.075 ;
     RECT  5.52 53.075 7.464 53.123 ;
     RECT  9.888 53.045 11.352 53.171 ;
     RECT  24.048 52.459 25.08 53.279 ;
     RECT  23.76 53.279 25.08 53.363 ;
     RECT  32.64 51.635 32.952 53.423 ;
     RECT  15.36 53.045 18.264 53.471 ;
     RECT  34.56 53.429 34.584 53.471 ;
     RECT  21.744 52.459 22.248 53.493 ;
     RECT  32.448 53.423 32.952 53.507 ;
     RECT  34.56 53.471 34.776 53.555 ;
     RECT  14.784 53.471 18.264 53.557 ;
     RECT  21.744 53.493 23.064 53.557 ;
     RECT  24.048 53.363 25.08 53.557 ;
     RECT  26.256 52.459 28.728 53.557 ;
     RECT  32.64 53.507 32.952 53.557 ;
     RECT  9.888 53.171 9.912 53.581 ;
     RECT  14.448 53.557 18.264 53.651 ;
     RECT  24.048 53.557 28.728 53.651 ;
     RECT  32.64 53.557 33.144 53.651 ;
     RECT  36.384 53.557 36.408 53.651 ;
     RECT  15.408 53.651 18.264 53.995 ;
     RECT  24.048 53.651 25.176 53.995 ;
     RECT  24.048 53.995 24.552 54.035 ;
     RECT  21.312 53.557 23.064 54.133 ;
     RECT  20.976 54.133 23.064 54.389 ;
     RECT  24.048 54.035 24.504 54.389 ;
     RECT  4.32 53.075 4.488 54.483 ;
     RECT  5.64 53.123 7.464 54.483 ;
     RECT  4.32 54.483 7.464 54.571 ;
     RECT  11.04 53.171 11.352 54.709 ;
     RECT  26.448 53.651 28.728 54.709 ;
     RECT  30.048 52.019 30.312 54.709 ;
     RECT  5.64 54.571 7.464 54.815 ;
     RECT  16.32 53.995 18.264 54.815 ;
     RECT  10.224 54.709 11.448 54.837 ;
     RECT  20.976 54.389 24.504 54.851 ;
     RECT  10.224 54.837 11.64 54.891 ;
     RECT  5.64 54.815 8.184 54.899 ;
     RECT  16.32 54.815 18.84 54.899 ;
     RECT  11.04 54.891 11.64 55.139 ;
     RECT  20.976 54.851 24.168 55.139 ;
     RECT  0.24 52.405 1.224 55.141 ;
     RECT  20.976 55.139 23.064 55.237 ;
     RECT  26.448 54.709 30.312 55.343 ;
     RECT  32.64 53.651 32.952 55.391 ;
     RECT  20.4 55.237 23.064 55.403 ;
     RECT  26.208 55.343 30.312 55.403 ;
     RECT  34.8 55.237 35.112 55.403 ;
     RECT  9.744 55.343 9.768 55.427 ;
     RECT  16.32 54.899 18.36 55.427 ;
     RECT  20.544 55.403 23.064 55.467 ;
     RECT  34.8 55.403 34.824 55.467 ;
     RECT  28.704 55.403 30.312 55.475 ;
     RECT  32.64 55.391 33.624 55.475 ;
     RECT  30.048 55.475 30.312 55.909 ;
     RECT  16.32 55.427 18.264 55.919 ;
     RECT  8.88 55.909 8.904 55.993 ;
     RECT  30.048 55.909 31.032 55.993 ;
     RECT  16.272 55.919 18.264 56.003 ;
     RECT  5.64 54.899 7.464 56.083 ;
     RECT  5.64 56.083 7.8 56.171 ;
     RECT  32.64 55.475 33.048 56.245 ;
     RECT  2.928 52.981 3.192 56.341 ;
     RECT  11.04 55.139 11.352 56.351 ;
     RECT  11.04 56.351 12.168 56.435 ;
     RECT  21.216 55.467 23.064 56.437 ;
     RECT  26.208 55.403 27.552 56.437 ;
     RECT  31.728 56.245 33.048 56.485 ;
     RECT  12.72 56.437 12.744 56.521 ;
     RECT  25.68 56.437 27.552 56.531 ;
     RECT  31.728 56.485 33.672 56.531 ;
     RECT  32.64 56.531 33.672 56.569 ;
     RECT  26.448 56.531 27.552 56.595 ;
     RECT  28.704 55.475 28.728 56.595 ;
     RECT  2.88 56.341 3.192 56.677 ;
     RECT  24.096 55.139 24.168 56.917 ;
     RECT  11.04 56.435 11.352 57.013 ;
     RECT  21.12 56.437 23.064 57.013 ;
     RECT  24.048 56.917 24.168 57.013 ;
     RECT  13.056 57.013 13.08 57.097 ;
     RECT  14.304 57.013 14.328 57.097 ;
     RECT  10.32 57.013 11.352 57.107 ;
     RECT  16.32 56.003 18.264 57.205 ;
     RECT  21.12 57.013 24.168 57.333 ;
     RECT  19.536 56.309 19.56 57.397 ;
     RECT  19.536 57.397 19.992 57.491 ;
     RECT  10.896 57.107 11.352 57.503 ;
     RECT  21.12 57.333 24.456 57.515 ;
     RECT  35.856 57.427 35.88 57.515 ;
     RECT  32.64 56.569 33.096 57.539 ;
     RECT  21.12 57.515 24.36 57.579 ;
     RECT  10.896 57.503 11.976 57.587 ;
     RECT  21.12 57.579 24.12 57.587 ;
     RECT  26.448 56.595 28.728 57.589 ;
     RECT  32.64 57.539 32.952 57.589 ;
     RECT  10.896 57.587 11.496 57.683 ;
     RECT  14.112 57.589 14.136 57.683 ;
     RECT  26.208 57.589 28.728 57.683 ;
     RECT  31.776 57.589 32.952 57.683 ;
     RECT  30.048 55.993 30.312 58.069 ;
     RECT  13.2 58.003 13.224 58.091 ;
     RECT  8.448 58.069 8.472 58.155 ;
     RECT  26.4 57.683 28.728 58.155 ;
     RECT  5.64 56.171 7.464 58.165 ;
     RECT  5.52 58.165 7.464 58.259 ;
     RECT  19.536 57.491 19.56 58.421 ;
     RECT  4.32 54.571 4.488 58.645 ;
     RECT  25.104 58.607 25.128 58.691 ;
     RECT  15.36 57.205 18.264 58.739 ;
     RECT  21.12 57.587 23.064 58.805 ;
     RECT  24.096 57.587 24.12 58.805 ;
     RECT  26.448 58.155 28.728 58.981 ;
     RECT  29.856 58.069 30.312 58.981 ;
     RECT  26.448 58.981 30.312 59.027 ;
     RECT  28.704 59.027 30.312 59.065 ;
     RECT  32.64 57.683 32.952 59.077 ;
     RECT  32.544 59.077 32.952 59.179 ;
     RECT  0.24 55.141 1.608 59.221 ;
     RECT  21.12 58.805 24.12 59.221 ;
     RECT  10.896 57.683 11.352 59.231 ;
     RECT  15.696 58.739 18.264 59.231 ;
     RECT  19.344 58.421 19.56 59.231 ;
     RECT  0.24 59.221 1.704 59.269 ;
     RECT  2.784 56.677 3.192 59.269 ;
     RECT  4.32 58.645 4.632 59.307 ;
     RECT  5.64 58.259 7.464 59.315 ;
     RECT  10.896 59.231 11.448 59.315 ;
     RECT  14.64 59.231 14.664 59.315 ;
     RECT  35.904 59.231 35.928 59.315 ;
     RECT  5.64 59.315 6.072 59.341 ;
     RECT  10.896 59.315 11.352 59.411 ;
     RECT  15.696 59.231 19.56 59.749 ;
     RECT  26.448 59.027 27.672 59.785 ;
     RECT  4.32 59.307 4.488 59.797 ;
     RECT  21.12 59.221 24.168 59.797 ;
     RECT  15.408 59.749 19.56 60.277 ;
     RECT  28.704 59.065 29.016 60.277 ;
     RECT  30.048 59.065 30.312 60.277 ;
     RECT  13.344 60.243 13.368 60.331 ;
     RECT  14.832 60.277 19.56 60.361 ;
     RECT  28.704 60.277 30.312 60.361 ;
     RECT  29.856 60.361 30.312 60.419 ;
     RECT  30.144 60.419 30.312 60.467 ;
     RECT  15.696 60.361 19.56 60.709 ;
     RECT  11.04 59.411 11.352 60.757 ;
     RECT  11.04 60.757 11.448 60.843 ;
     RECT  4.224 59.797 4.488 60.949 ;
     RECT  4.176 60.949 4.488 61.043 ;
     RECT  32.64 59.179 32.952 61.093 ;
     RECT  15.696 60.709 19.992 61.343 ;
     RECT  32.544 61.093 32.952 61.419 ;
     RECT  14.784 61.343 19.992 61.427 ;
     RECT  5.64 59.341 5.952 61.429 ;
     RECT  12.576 60.997 12.6 61.477 ;
     RECT  15.696 61.427 19.992 61.493 ;
     RECT  21.12 59.797 24.984 61.493 ;
     RECT  7.104 59.315 7.464 61.535 ;
     RECT  15.696 61.493 24.984 61.547 ;
     RECT  5.328 61.429 5.952 61.557 ;
     RECT  7.104 61.535 7.752 61.557 ;
     RECT  5.328 61.557 7.752 61.619 ;
     RECT  5.328 61.619 7.464 61.667 ;
     RECT  28.704 60.361 28.728 61.765 ;
     RECT  28.704 61.765 29.256 61.867 ;
     RECT  5.328 61.667 6.264 61.945 ;
     RECT  12.576 61.477 13.56 62.053 ;
     RECT  30.288 60.467 30.312 62.111 ;
     RECT  8.736 62.111 8.76 62.133 ;
     RECT  9.84 62.111 9.864 62.133 ;
     RECT  30.288 62.111 30.744 62.133 ;
     RECT  12.576 62.053 13.704 62.137 ;
     RECT  8.736 62.133 9.864 62.195 ;
     RECT  12.576 62.137 12.792 62.195 ;
     RECT  30.24 62.133 30.744 62.195 ;
     RECT  4.176 61.043 4.344 62.197 ;
     RECT  5.328 61.945 5.952 62.197 ;
     RECT  8.736 62.195 8.904 62.197 ;
     RECT  8.448 62.197 8.904 62.221 ;
     RECT  30.24 62.195 30.312 62.243 ;
     RECT  12.576 62.195 12.6 62.245 ;
     RECT  12.528 62.245 12.6 62.329 ;
     RECT  11.04 60.843 11.352 62.437 ;
     RECT  28.704 61.867 29.16 62.443 ;
     RECT  10.896 62.437 11.352 62.627 ;
     RECT  7.44 61.667 7.464 62.709 ;
     RECT  8.448 62.221 8.472 62.709 ;
     RECT  15.696 61.547 20.52 62.725 ;
     RECT  15.696 62.725 20.76 62.771 ;
     RECT  7.44 62.709 8.472 63.109 ;
     RECT  15.984 62.771 20.76 63.157 ;
     RECT  21.84 61.547 24.984 63.157 ;
     RECT  26.448 59.785 27.552 63.205 ;
     RECT  15.984 63.157 24.984 63.251 ;
     RECT  12.576 62.329 12.6 63.263 ;
     RECT  14.208 63.205 14.232 63.289 ;
     RECT  15.984 63.251 20.76 63.299 ;
     RECT  12.576 63.263 13.176 63.347 ;
     RECT  15.984 63.299 19.56 63.539 ;
     RECT  32.64 61.419 32.952 63.637 ;
     RECT  31.872 63.637 32.952 63.723 ;
     RECT  11.04 62.627 11.352 63.781 ;
     RECT  12.576 63.347 12.6 63.781 ;
     RECT  32.64 63.723 32.952 63.839 ;
     RECT  13.584 63.925 13.608 64.019 ;
     RECT  4.176 62.197 5.952 64.069 ;
     RECT  7.056 63.109 8.472 64.069 ;
     RECT  28.704 62.443 28.728 64.275 ;
     RECT  28.704 64.275 29.304 64.363 ;
     RECT  11.04 63.781 12.6 64.415 ;
     RECT  32.64 63.839 33.048 64.415 ;
     RECT  10.224 64.415 12.888 64.499 ;
     RECT  15.36 64.415 15.384 64.499 ;
     RECT  32.64 64.415 33.672 64.499 ;
     RECT  4.176 64.069 8.472 64.629 ;
     RECT  34.8 64.357 34.824 64.691 ;
     RECT  16.44 63.539 19.56 64.693 ;
     RECT  20.736 63.299 20.76 64.693 ;
     RECT  4.176 64.629 9 64.739 ;
     RECT  21.84 63.251 24.984 64.741 ;
     RECT  0.24 59.269 3.192 64.981 ;
     RECT  4.176 64.739 8.472 64.981 ;
     RECT  32.64 64.499 32.952 65.013 ;
     RECT  32.496 65.013 32.952 65.171 ;
     RECT  21.84 64.741 25.08 65.461 ;
     RECT  26.16 63.205 27.552 65.461 ;
     RECT  10.416 64.499 12.6 65.509 ;
     RECT  16.44 64.693 20.76 65.509 ;
     RECT  21.84 65.461 27.552 65.509 ;
     RECT  16.44 65.509 27.552 65.545 ;
     RECT  30.288 62.243 30.312 65.555 ;
     RECT  26.16 65.545 27.552 65.707 ;
     RECT  0.24 64.981 8.472 66.133 ;
     RECT  0.24 66.133 9.432 66.143 ;
     RECT  10.416 65.509 12.696 66.143 ;
     RECT  0.24 66.143 12.696 66.227 ;
     RECT  16.44 65.545 25.08 66.719 ;
     RECT  26.448 65.707 27.552 66.719 ;
     RECT  32.64 65.171 32.952 67.247 ;
     RECT  13.968 67.247 13.992 67.331 ;
     RECT  16.44 66.719 27.552 67.331 ;
     RECT  32.64 67.247 33.048 67.331 ;
     RECT  23.952 67.331 27.552 67.379 ;
     RECT  0.24 66.227 9.432 67.411 ;
     RECT  10.416 66.227 12.696 67.411 ;
     RECT  32.64 67.331 32.952 67.631 ;
     RECT  32.496 67.631 32.952 67.715 ;
     RECT  24.192 67.379 27.552 67.893 ;
     RECT  28.704 64.363 28.728 67.893 ;
     RECT  24.192 67.893 28.728 67.981 ;
     RECT  0.24 67.411 12.696 68.075 ;
     RECT  16.44 67.331 22.872 68.341 ;
     RECT  24.192 67.981 27.552 68.341 ;
     RECT  28.704 67.981 28.728 68.399 ;
     RECT  16.44 68.341 27.552 69.045 ;
     RECT  28.704 68.399 29.112 69.045 ;
     RECT  16.44 69.045 29.496 69.155 ;
     RECT  16.44 69.155 27.672 69.193 ;
     RECT  10.416 68.075 12.696 69.445 ;
     RECT  16.44 69.193 27.552 69.491 ;
     RECT  16.44 69.491 26.04 69.577 ;
     RECT  27.12 69.491 27.552 70.211 ;
     RECT  16.44 69.577 25.656 70.259 ;
     RECT  0.24 68.075 9.432 70.597 ;
     RECT  10.416 69.445 12.936 70.597 ;
     RECT  16.44 70.259 25.128 70.669 ;
     RECT  27.24 70.211 27.552 71.029 ;
     RECT  28.704 69.155 28.728 71.029 ;
     RECT  27.24 71.029 28.728 71.219 ;
     RECT  16.44 70.669 25.08 71.989 ;
     RECT  0.24 70.597 12.936 72.181 ;
     RECT  16.44 71.989 25.704 72.235 ;
     RECT  15.168 65.509 15.192 72.949 ;
     RECT  15.024 72.949 15.192 73.077 ;
     RECT  16.44 72.235 25.08 73.077 ;
     RECT  15.024 73.077 25.08 73.477 ;
     RECT  15.024 73.477 25.128 73.525 ;
     RECT  27.24 71.219 27.552 73.525 ;
     RECT  32.64 67.715 32.952 73.525 ;
     RECT  31.344 73.525 31.368 73.619 ;
     RECT  32.64 73.525 33.144 73.619 ;
     RECT  27.24 73.525 27.672 73.909 ;
     RECT  28.704 71.219 28.728 73.909 ;
     RECT  15.024 73.525 25.656 74.101 ;
     RECT  27.24 73.909 28.728 74.101 ;
     RECT  14.832 74.101 28.728 74.147 ;
     RECT  0.24 72.181 13.704 74.165 ;
     RECT  14.832 74.147 28.008 74.165 ;
     RECT  0.24 74.165 28.008 74.195 ;
     RECT  0.24 74.195 26.04 74.243 ;
     RECT  0.24 74.243 25.608 74.771 ;
     RECT  27.24 74.195 28.008 75.107 ;
     RECT  0.24 74.771 25.272 76.884 ;
     RECT  27.24 75.107 27.552 76.884 ;
     RECT  32.64 73.619 32.952 76.884 ;
     RECT  38.04 47.113 38.352 76.884 ;
     RECT  0.432 76.884 25.272 76.973 ;
     RECT  27.432 76.884 27.552 76.973 ;
     RECT  32.832 76.884 32.952 76.973 ;
     RECT  38.232 76.884 38.352 76.973 ;
     RECT  0.624 76.973 25.272 77.557 ;
     RECT  0.624 77.557 25.368 77.584 ;
     RECT  25.2 77.584 25.368 77.603 ;
     RECT  25.344 77.603 25.368 77.641 ;
    LAYER M6 ;
     RECT  0 33.396 2.821 34.26 ;
     RECT  0 49.596 3.397 50.46 ;
     RECT  0 22.596 3.618 23.46 ;
     RECT  3.397 41.408 3.637 41.44 ;
     RECT  3.618 22.596 3.893 23.904 ;
     RECT  3.637 41.024 4.019 41.44 ;
     RECT  0 44.196 4.117 45.06 ;
     RECT  3.061 52.992 4.261 53.024 ;
     RECT  4.261 52.48 4.395 53.024 ;
     RECT  2.821 32.448 4.405 34.26 ;
     RECT  4.117 44.196 4.405 45.664 ;
     RECT  4.395 52.992 4.595 53.024 ;
     RECT  0 60.396 4.597 61.26 ;
     RECT  4.405 32.448 4.885 35.168 ;
     RECT  0 54.996 4.885 55.86 ;
     RECT  0 27.996 4.917 28.86 ;
     RECT  3.893 22.596 4.981 24.416 ;
     RECT  0 38.796 4.981 39.66 ;
     RECT  4.981 37.632 5.171 39.66 ;
     RECT  4.917 27.996 5.173 29.024 ;
     RECT  3.397 49.596 5.173 50.72 ;
     RECT  5.173 27.84 5.237 29.024 ;
     RECT  4.405 44.196 5.237 46.24 ;
     RECT  5.173 48.448 5.242 50.72 ;
     RECT  5.237 44.196 5.315 46.816 ;
     RECT  5.242 49.596 5.315 50.72 ;
     RECT  5.237 27.84 5.317 29.6 ;
     RECT  4.885 31.36 5.413 35.168 ;
     RECT  5.413 31.36 5.483 35.68 ;
     RECT  4.981 21.568 5.493 24.416 ;
     RECT  5.317 25.792 5.493 25.824 ;
     RECT  5.483 31.36 5.493 31.392 ;
     RECT  4.597 59.264 5.509 61.26 ;
     RECT  5.317 27.392 5.547 29.6 ;
     RECT  5.547 27.84 5.555 29.6 ;
     RECT  5.486 53.056 5.555 53.088 ;
     RECT  5.315 44.196 5.611 46.24 ;
     RECT  5.509 58.176 5.675 61.26 ;
     RECT  0 11.796 5.749 12.66 ;
     RECT  5.509 14.208 5.749 14.24 ;
     RECT  5.493 31.296 5.749 31.392 ;
     RECT  4.885 54.528 5.813 55.86 ;
     RECT  0 76.596 5.989 76.884 ;
     RECT  5.749 30.912 6.083 31.392 ;
     RECT  5.483 33.088 6.083 35.168 ;
     RECT  5.813 54.144 6.083 55.86 ;
     RECT  5.675 58.88 6.083 61.26 ;
     RECT  4.019 41.408 6.133 41.44 ;
     RECT  6.133 41.152 6.179 41.44 ;
     RECT  5.989 76.596 6.179 77.088 ;
     RECT  0 65.796 6.181 66.66 ;
     RECT  6.083 60.396 6.229 61.26 ;
     RECT  0 17.196 6.277 18.06 ;
     RECT  5.315 49.596 6.613 50.46 ;
     RECT  5.493 21.312 6.645 25.824 ;
     RECT  6.277 17.196 6.661 19.232 ;
     RECT  6.661 16.768 6.699 19.232 ;
     RECT  6.613 49.596 6.699 50.592 ;
     RECT  0 6.396 6.709 7.26 ;
     RECT  6.083 31.36 6.778 31.392 ;
     RECT  6.083 54.528 6.837 55.86 ;
     RECT  5.611 44.196 6.901 45.984 ;
     RECT  6.181 65.472 6.901 66.66 ;
     RECT  6.901 65.024 6.949 66.66 ;
     RECT  6.083 58.88 7.019 58.912 ;
     RECT  6.179 41.152 7.022 41.184 ;
     RECT  6.229 60.396 7.045 61.92 ;
     RECT  6.837 54.528 7.211 56.16 ;
     RECT  5.171 38.796 7.221 39.66 ;
     RECT  7.022 41.024 7.221 41.184 ;
     RECT  7.189 58.752 7.266 58.784 ;
     RECT  7.266 58.624 7.275 58.784 ;
     RECT  7.045 60.396 7.275 63.2 ;
     RECT  6.949 64.896 7.275 66.66 ;
     RECT  7.221 38.796 7.285 41.184 ;
     RECT  7.221 69.376 7.294 69.408 ;
     RECT  6.699 16.768 7.333 18.06 ;
     RECT  6.901 44.196 7.333 47.136 ;
     RECT  6.757 74.048 7.333 74.08 ;
     RECT  7.275 58.624 7.339 58.656 ;
     RECT  6.005 9.984 7.349 10.016 ;
     RECT  6.645 20.864 7.349 26.336 ;
     RECT  5.555 27.84 7.349 29.536 ;
     RECT  6.699 49.596 7.381 50.46 ;
     RECT  7.333 16.576 7.403 18.06 ;
     RECT  7.333 43.904 7.477 47.136 ;
     RECT  7.477 42.752 7.541 47.136 ;
     RECT  7.275 60.396 7.595 62.752 ;
     RECT  0 0.996 7.669 1.86 ;
     RECT  7.349 20.864 7.669 29.536 ;
     RECT  7.541 42.752 7.723 47.2 ;
     RECT  7.669 20.864 7.733 29.664 ;
     RECT  7.733 19.776 7.797 29.664 ;
     RECT  7.285 37.568 7.811 41.184 ;
     RECT  7.211 54.848 7.811 56.16 ;
     RECT  7.723 43.264 7.861 47.2 ;
     RECT  7.797 19.776 7.87 30.304 ;
     RECT  7.87 19.776 7.907 29.536 ;
     RECT  7.349 9.984 7.957 10.336 ;
     RECT  7.907 19.776 8.003 24.48 ;
     RECT  7.811 38.796 8.051 41.184 ;
     RECT  7.957 9.792 8.053 10.336 ;
     RECT  7.907 26.304 8.099 29.536 ;
     RECT  8.053 37.056 8.122 37.088 ;
     RECT  7.811 54.848 8.235 55.968 ;
     RECT  7.669 0.996 8.309 3.168 ;
     RECT  8.245 68.992 8.314 69.024 ;
     RECT  7.861 43.264 8.366 47.264 ;
     RECT  7.381 49.024 8.366 50.46 ;
     RECT  8.366 43.264 8.435 50.46 ;
     RECT  8.437 31.36 8.531 31.392 ;
     RECT  8.003 21.952 8.579 24.48 ;
     RECT  6.709 6.016 8.629 7.26 ;
     RECT  8.629 52.352 8.771 52.384 ;
     RECT  7.275 65.796 8.885 66.66 ;
     RECT  8.051 38.796 8.915 41.056 ;
     RECT  8.235 54.996 8.939 55.968 ;
     RECT  8.437 58.112 8.939 58.144 ;
     RECT  8.885 64.64 9.011 66.66 ;
     RECT  7.333 73.536 9.061 74.08 ;
     RECT  9.061 73.536 9.131 74.144 ;
     RECT  6.083 33.396 9.134 35.168 ;
     RECT  9.134 33.396 9.203 35.936 ;
     RECT  8.309 0.996 9.205 3.424 ;
     RECT  8.435 43.264 9.251 47.264 ;
     RECT  5.749 11.796 9.269 14.24 ;
     RECT  0 71.196 9.301 72.06 ;
     RECT  9.131 73.536 9.301 73.568 ;
     RECT  8.629 5.632 9.333 7.26 ;
     RECT  8.053 8.96 9.333 10.336 ;
     RECT  9.203 33.396 9.387 34.848 ;
     RECT  9.011 65.796 9.445 66.66 ;
     RECT  9.445 65.796 9.461 67.488 ;
     RECT  9.269 11.796 9.515 14.688 ;
     RECT  9.301 71.196 9.515 73.568 ;
     RECT  9.333 5.632 9.525 10.336 ;
     RECT  9.515 11.796 9.525 14.304 ;
     RECT  8.099 26.304 9.653 29.024 ;
     RECT  7.403 16.768 9.781 18.06 ;
     RECT  7.595 60.396 9.899 62.176 ;
     RECT  9.653 25.792 9.909 29.024 ;
     RECT  9.445 42.752 9.925 42.784 ;
     RECT  9.205 0.128 9.973 3.424 ;
     RECT  9.515 73.536 10.091 73.568 ;
     RECT  9.061 31.488 10.094 31.52 ;
     RECT  9.781 16.256 10.165 18.06 ;
     RECT  9.877 52.48 10.165 53.536 ;
     RECT  8.939 54.996 10.165 55.86 ;
     RECT  10.165 16.256 10.213 18.272 ;
     RECT  8.003 19.776 10.213 19.808 ;
     RECT  10.165 52.48 10.213 55.86 ;
     RECT  9.973 0.128 10.229 3.744 ;
     RECT  10.213 51.904 10.286 55.86 ;
     RECT  9.899 60.396 10.347 61.92 ;
     RECT  9.461 65.796 10.355 68.064 ;
     RECT  8.915 38.796 10.357 40.224 ;
     RECT  10.094 31.36 10.405 31.52 ;
     RECT  9.387 33.396 10.405 34.784 ;
     RECT  9.925 42.432 10.421 42.784 ;
     RECT  8.435 49.596 10.485 50.46 ;
     RECT  10.286 51.904 10.485 57.056 ;
     RECT  10.347 60.396 10.539 61.6 ;
     RECT  10.421 41.664 10.547 42.784 ;
     RECT  8.579 22.336 10.549 24.48 ;
     RECT  9.909 25.792 10.549 29.536 ;
     RECT  10.549 22.336 10.597 29.536 ;
     RECT  10.229 0.128 10.643 4.32 ;
     RECT  10.037 37.312 10.677 37.344 ;
     RECT  10.405 31.36 10.731 34.784 ;
     RECT  10.597 22.144 10.741 29.536 ;
     RECT  10.741 22.144 10.81 29.664 ;
     RECT  10.213 16.256 10.885 19.808 ;
     RECT  10.81 22.144 10.885 29.6 ;
     RECT  10.213 64.448 10.885 64.48 ;
     RECT  10.355 65.796 10.885 66.66 ;
     RECT  9.525 5.632 10.933 14.304 ;
     RECT  10.885 16.256 10.933 29.6 ;
     RECT  10.357 38.796 10.933 40.288 ;
     RECT  10.547 41.664 10.933 42.464 ;
     RECT  10.885 64.448 10.933 66.66 ;
     RECT  6.179 76.596 10.933 76.884 ;
     RECT  10.933 5.632 10.987 29.6 ;
     RECT  10.485 49.596 10.987 57.056 ;
     RECT  10.987 22.272 11.115 29.6 ;
     RECT  10.987 49.596 11.115 51.808 ;
     RECT  10.987 53.504 11.115 57.056 ;
     RECT  9.515 71.196 11.189 72.06 ;
     RECT  10.987 5.632 11.307 20.96 ;
     RECT  10.539 60.396 11.317 61.26 ;
     RECT  10.677 36.8 11.413 37.344 ;
     RECT  10.933 38.796 11.413 42.464 ;
     RECT  10.933 76.596 11.413 77.088 ;
     RECT  11.115 54.72 11.438 57.056 ;
     RECT  11.438 54.72 11.459 57.632 ;
     RECT  11.317 59.264 11.459 61.26 ;
     RECT  10.355 68.032 11.459 68.064 ;
     RECT  11.189 71.196 11.459 73.12 ;
     RECT  11.459 54.848 11.507 57.632 ;
     RECT  10.643 0.128 11.509 4.128 ;
     RECT  11.413 76.596 11.509 77.216 ;
     RECT  10.933 63.936 11.603 66.66 ;
     RECT  11.507 54.848 11.651 57.568 ;
     RECT  10.731 31.36 12.085 34.656 ;
     RECT  11.413 36.8 12.085 42.464 ;
     RECT  12.085 31.36 12.131 42.464 ;
     RECT  12.085 73.536 12.149 74.144 ;
     RECT  11.509 76.596 12.341 77.472 ;
     RECT  12.277 68.416 12.346 68.448 ;
     RECT  12.149 73.536 12.419 74.656 ;
     RECT  9.251 44.196 12.421 47.264 ;
     RECT  12.341 76.596 12.469 77.6 ;
     RECT  11.459 60.396 12.517 61.26 ;
     RECT  12.419 74.496 12.517 74.656 ;
     RECT  12.131 37.312 12.755 42.464 ;
     RECT  11.115 49.596 12.853 51.36 ;
     RECT  11.603 63.936 12.922 64.48 ;
     RECT  12.517 60.396 12.981 62.304 ;
     RECT  12.922 63.936 12.981 63.968 ;
     RECT  11.509 0.064 13.026 4.128 ;
     RECT  12.517 74.496 13.045 74.72 ;
     RECT  12.469 76.288 13.045 77.6 ;
     RECT  13.026 0.064 13.099 4.576 ;
     RECT  12.421 44.196 13.189 48.096 ;
     RECT  11.651 54.996 13.189 57.568 ;
     RECT  12.981 60.396 13.301 63.968 ;
     RECT  12.853 49.596 13.365 51.488 ;
     RECT  13.189 43.52 13.419 48.096 ;
     RECT  13.365 49.472 13.475 51.488 ;
     RECT  13.189 54.996 13.611 58.08 ;
     RECT  11.307 6.016 13.621 20.96 ;
     RECT  11.115 22.336 13.621 29.6 ;
     RECT  12.131 31.36 13.621 36 ;
     RECT  12.755 37.312 13.621 42.144 ;
     RECT  13.301 60.288 13.63 63.968 ;
     RECT  13.63 60.288 13.739 63.52 ;
     RECT  11.603 65.796 13.934 66.66 ;
     RECT  13.934 65.796 14.003 67.296 ;
     RECT  13.739 60.288 14.069 61.536 ;
     RECT  13.611 54.996 14.133 57.632 ;
     RECT  13.099 0.064 14.147 4.192 ;
     RECT  13.621 6.016 14.197 42.144 ;
     RECT  13.419 43.52 14.197 47.328 ;
     RECT  13.045 74.496 14.261 77.6 ;
     RECT  14.197 6.016 14.291 47.328 ;
     RECT  14.133 54.08 14.437 57.632 ;
     RECT  13.475 49.596 14.533 51.488 ;
     RECT  14.291 6.016 14.581 7.392 ;
     RECT  14.069 59.776 14.629 61.536 ;
     RECT  14.533 49.596 14.773 51.616 ;
     RECT  14.437 53.568 14.773 57.632 ;
     RECT  14.773 53.504 14.837 57.632 ;
     RECT  11.459 71.196 14.837 72.06 ;
     RECT  14.261 74.112 14.837 77.6 ;
     RECT  14.837 71.196 14.867 77.6 ;
     RECT  14.291 8.96 14.891 47.328 ;
     RECT  14.837 53.376 14.901 57.632 ;
     RECT  14.901 53.248 15.029 57.632 ;
     RECT  14.629 59.264 15.029 61.536 ;
     RECT  14.773 49.024 15.349 51.616 ;
     RECT  15.029 53.248 15.349 61.536 ;
     RECT  13.739 63.232 15.349 63.52 ;
     RECT  14.891 8.96 15.443 8.992 ;
     RECT  15.349 49.024 15.443 61.536 ;
     RECT  14.581 5.888 15.541 7.392 ;
     RECT  14.867 71.196 15.587 73.248 ;
     RECT  15.443 60.396 15.669 61.536 ;
     RECT  15.349 63.232 15.669 64.48 ;
     RECT  15.541 5.44 15.733 7.392 ;
     RECT  14.891 10.304 15.781 47.328 ;
     RECT  15.443 49.024 15.781 59.104 ;
     RECT  15.669 60.396 15.861 64.48 ;
     RECT  14.003 65.796 15.861 66.66 ;
     RECT  15.781 10.304 15.875 59.104 ;
     RECT  15.875 25.92 15.979 59.104 ;
     RECT  15.861 60.396 16.019 66.66 ;
     RECT  14.867 74.688 16.309 77.6 ;
     RECT  16.019 60.396 16.363 63.328 ;
     RECT  16.309 74.112 16.378 77.6 ;
     RECT  15.979 32.192 16.427 59.104 ;
     RECT  16.427 32.192 16.491 34.656 ;
     RECT  16.491 32.192 16.811 34.528 ;
     RECT  15.875 10.304 16.883 24.48 ;
     RECT  16.019 64.768 17.077 66.66 ;
     RECT  14.147 0.064 17.525 4.128 ;
     RECT  15.733 5.44 17.525 8.416 ;
     RECT  16.811 32.192 17.589 34.4 ;
     RECT  16.363 63.232 17.605 63.328 ;
     RECT  17.077 64.768 17.605 67.552 ;
     RECT  15.587 71.196 17.605 72.06 ;
     RECT  16.363 60.396 17.699 61.536 ;
     RECT  15.979 25.92 17.717 30.112 ;
     RECT  17.605 71.196 17.909 73.056 ;
     RECT  16.883 10.816 17.914 24.48 ;
     RECT  16.427 35.968 18.027 59.104 ;
     RECT  17.525 0.064 18.091 8.416 ;
     RECT  17.909 70.08 18.158 73.056 ;
     RECT  17.717 25.92 18.181 30.176 ;
     RECT  17.589 31.488 18.181 34.4 ;
     RECT  18.091 0.128 18.293 8.416 ;
     RECT  17.914 11.008 18.357 24.48 ;
     RECT  18.181 25.92 18.357 34.4 ;
     RECT  18.293 0.128 18.411 8.608 ;
     RECT  18.357 11.008 18.43 34.4 ;
     RECT  18.43 25.92 18.485 34.4 ;
     RECT  18.027 35.968 18.485 55.86 ;
     RECT  18.411 8.576 18.549 8.608 ;
     RECT  18.485 25.92 18.731 55.86 ;
     RECT  18.158 69.568 18.757 73.056 ;
     RECT  17.605 63.232 18.805 67.552 ;
     RECT  18.411 0.128 18.851 7.26 ;
     RECT  18.43 11.008 18.851 24.16 ;
     RECT  18.851 11.584 18.899 24.16 ;
     RECT  18.851 0.128 18.923 4.32 ;
     RECT  18.757 69.504 18.933 73.056 ;
     RECT  16.378 74.624 18.933 77.6 ;
     RECT  18.027 57.344 18.997 59.104 ;
     RECT  17.699 60.396 18.997 61.26 ;
     RECT  18.805 63.168 19.045 67.552 ;
     RECT  18.997 57.344 19.066 61.26 ;
     RECT  18.731 25.984 19.091 55.86 ;
     RECT  18.933 69.504 19.115 77.6 ;
     RECT  19.115 69.504 19.307 72.06 ;
     RECT  19.066 60.396 19.333 61.26 ;
     RECT  19.045 62.784 19.333 67.552 ;
     RECT  18.923 0.128 19.427 3.872 ;
     RECT  18.899 11.584 19.427 13.088 ;
     RECT  19.115 73.472 19.523 77.6 ;
     RECT  19.091 26.112 19.525 55.86 ;
     RECT  19.066 57.344 19.525 59.104 ;
     RECT  18.549 8.576 19.701 8.928 ;
     RECT  19.427 0.128 19.765 3.552 ;
     RECT  18.899 14.912 19.765 24.16 ;
     RECT  18.851 5.824 19.955 7.26 ;
     RECT  19.525 26.112 19.955 59.104 ;
     RECT  19.955 5.952 19.957 7.26 ;
     RECT  19.701 8.576 19.957 9.696 ;
     RECT  19.523 74.112 20.075 77.6 ;
     RECT  19.957 5.952 20.147 9.696 ;
     RECT  19.427 11.584 20.245 12.66 ;
     RECT  19.955 31.616 20.41 59.104 ;
     RECT  19.955 26.112 20.533 30.304 ;
     RECT  19.333 60.396 20.533 67.552 ;
     RECT  20.41 31.616 20.579 50.46 ;
     RECT  20.533 60.396 20.651 67.808 ;
     RECT  20.579 31.616 20.675 31.968 ;
     RECT  19.765 14.912 20.725 24.608 ;
     RECT  20.533 25.984 20.725 30.304 ;
     RECT  20.725 14.912 21.155 30.304 ;
     RECT  19.307 69.568 21.155 72.06 ;
     RECT  21.155 14.912 21.173 25.696 ;
     RECT  20.147 5.952 21.251 8.736 ;
     RECT  21.173 14.784 21.443 25.696 ;
     RECT  21.155 27.392 21.541 30.304 ;
     RECT  20.579 46.848 21.562 50.46 ;
     RECT  21.541 27.392 21.611 31.52 ;
     RECT  21.251 6.016 21.621 8.736 ;
     RECT  20.245 10.24 21.621 12.66 ;
     RECT  21.443 14.784 21.675 14.816 ;
     RECT  21.155 69.696 21.685 72.06 ;
     RECT  21.685 69.696 21.733 73.12 ;
     RECT  20.075 74.688 21.733 77.6 ;
     RECT  19.765 0.064 21.877 3.552 ;
     RECT  21.733 69.696 21.995 77.6 ;
     RECT  20.579 33.396 22.005 45.472 ;
     RECT  21.611 27.392 22.059 31.392 ;
     RECT  21.562 47.552 22.261 50.46 ;
     RECT  20.41 51.84 22.261 59.104 ;
     RECT  20.651 60.396 22.325 61.536 ;
     RECT  20.651 63.104 22.325 67.808 ;
     RECT  22.325 60.396 22.595 67.808 ;
     RECT  22.261 47.552 22.741 59.104 ;
     RECT  22.595 60.396 22.741 67.68 ;
     RECT  21.443 16.32 22.789 25.696 ;
     RECT  22.005 33.28 22.835 45.472 ;
     RECT  22.741 47.552 23.01 67.68 ;
     RECT  22.835 38.656 23.029 45.472 ;
     RECT  23.01 46.976 23.029 67.68 ;
     RECT  23.029 38.656 23.083 67.68 ;
     RECT  22.789 16 23.093 25.696 ;
     RECT  21.995 69.696 23.147 72.06 ;
     RECT  22.835 33.28 23.317 37.344 ;
     RECT  23.093 16 23.349 26.016 ;
     RECT  23.317 33.088 23.349 37.344 ;
     RECT  22.059 27.392 23.467 30.496 ;
     RECT  23.349 14.976 23.477 26.016 ;
     RECT  23.477 14.848 23.659 26.016 ;
     RECT  23.083 51.968 23.659 67.68 ;
     RECT  21.621 6.016 23.891 12.66 ;
     RECT  23.659 64.128 23.893 67.68 ;
     RECT  23.147 70.464 23.893 72.06 ;
     RECT  21.995 73.536 23.893 77.6 ;
     RECT  23.659 16 23.925 26.016 ;
     RECT  23.467 27.996 23.941 30.496 ;
     RECT  23.891 8.704 23.987 12.66 ;
     RECT  23.083 38.656 24.058 50.46 ;
     RECT  23.893 64.128 24.107 68.96 ;
     RECT  23.987 8.704 24.235 8.736 ;
     RECT  23.893 70.464 24.427 77.6 ;
     RECT  24.107 64.384 24.469 68.96 ;
     RECT  24.427 70.464 24.469 72.224 ;
     RECT  24.058 38.796 24.565 50.46 ;
     RECT  23.659 51.968 24.565 62.56 ;
     RECT  24.565 38.796 24.634 62.56 ;
     RECT  23.941 27.996 24.899 31.392 ;
     RECT  24.469 64.384 24.995 72.224 ;
     RECT  23.925 16 25.045 26.656 ;
     RECT  24.899 27.996 25.045 28.86 ;
     RECT  21.877 0.064 25.093 4.384 ;
     RECT  23.891 6.016 25.093 7.26 ;
     RECT  24.427 73.536 25.379 77.6 ;
     RECT  24.899 30.464 25.429 31.392 ;
     RECT  23.349 32.96 25.429 37.344 ;
     RECT  25.429 30.464 25.515 37.344 ;
     RECT  25.515 32.384 25.589 37.344 ;
     RECT  24.634 38.796 25.589 50.592 ;
     RECT  24.995 68.992 25.594 72.224 ;
     RECT  25.594 69.12 25.717 72.224 ;
     RECT  25.379 73.536 25.717 77.216 ;
     RECT  25.717 69.12 25.963 77.216 ;
     RECT  25.963 73.536 26.027 77.216 ;
     RECT  25.093 0.064 26.051 7.26 ;
     RECT  26.051 0.064 26.155 2.72 ;
     RECT  26.027 74.112 26.155 77.216 ;
     RECT  25.515 30.464 26.229 30.752 ;
     RECT  25.589 32.384 26.243 50.592 ;
     RECT  26.243 32.384 26.291 34.656 ;
     RECT  25.045 16 26.293 28.86 ;
     RECT  26.229 30.336 26.293 30.752 ;
     RECT  26.293 16 26.357 30.752 ;
     RECT  24.634 51.968 26.421 62.56 ;
     RECT  26.421 51.968 26.435 63.072 ;
     RECT  23.987 10.304 26.485 12.66 ;
     RECT  26.435 51.968 26.606 57.632 ;
     RECT  26.435 58.944 26.725 63.072 ;
     RECT  24.995 64.384 26.725 67.68 ;
     RECT  26.485 8.896 26.731 8.928 ;
     RECT  26.357 15.744 26.819 30.752 ;
     RECT  26.243 36.032 26.819 50.592 ;
     RECT  26.155 75.52 26.859 77.216 ;
     RECT  26.725 58.944 26.938 67.68 ;
     RECT  26.859 76.596 27.051 77.216 ;
     RECT  26.819 43.008 27.061 50.592 ;
     RECT  26.606 51.904 27.061 57.632 ;
     RECT  25.963 69.12 27.243 72.224 ;
     RECT  27.051 76.596 27.435 77.152 ;
     RECT  26.819 15.744 27.509 30.688 ;
     RECT  27.435 76.596 27.563 77.088 ;
     RECT  26.155 74.112 27.573 74.144 ;
     RECT  27.573 74.112 27.637 74.72 ;
     RECT  27.243 69.12 27.683 69.152 ;
     RECT  27.637 73.536 27.683 74.72 ;
     RECT  26.485 10.304 27.685 13.024 ;
     RECT  27.509 15.616 27.701 30.688 ;
     RECT  27.683 73.536 27.706 74.144 ;
     RECT  26.051 4.352 27.731 7.26 ;
     RECT  27.685 10.304 27.755 13.088 ;
     RECT  27.755 10.304 27.827 13.024 ;
     RECT  26.819 36.032 27.971 41.696 ;
     RECT  27.061 43.008 27.971 57.632 ;
     RECT  27.701 14.912 28.019 30.688 ;
     RECT  27.827 10.304 28.213 12.66 ;
     RECT  26.938 63.744 28.213 67.68 ;
     RECT  27.781 69.056 28.213 69.088 ;
     RECT  28.213 63.744 28.267 69.088 ;
     RECT  27.243 71.04 28.267 72.224 ;
     RECT  27.706 73.92 28.267 74.144 ;
     RECT  27.971 54.72 28.453 57.632 ;
     RECT  26.938 58.944 28.453 62.432 ;
     RECT  28.453 54.72 28.523 62.432 ;
     RECT  27.971 43.008 28.547 53.408 ;
     RECT  28.267 74.112 28.651 74.144 ;
     RECT  28.547 43.008 28.907 47.584 ;
     RECT  26.291 33.396 28.917 34.656 ;
     RECT  27.971 36.032 28.917 36.128 ;
     RECT  28.523 54.72 29.123 57.504 ;
     RECT  29.123 54.848 29.171 57.504 ;
     RECT  28.523 59.008 29.171 62.432 ;
     RECT  27.971 37.568 29.301 41.696 ;
     RECT  28.907 43.008 29.301 47.456 ;
     RECT  28.267 64.32 29.355 69.088 ;
     RECT  28.019 15.168 29.461 30.688 ;
     RECT  29.355 69.056 29.507 69.088 ;
     RECT  29.461 14.592 29.605 30.688 ;
     RECT  28.917 33.396 29.653 36.128 ;
     RECT  29.301 37.568 29.653 47.456 ;
     RECT  26.155 0.128 29.685 2.72 ;
     RECT  27.731 4.928 29.685 7.26 ;
     RECT  29.605 14.528 29.699 30.688 ;
     RECT  29.653 33.396 29.699 47.456 ;
     RECT  29.699 33.396 29.739 36.512 ;
     RECT  29.699 16 29.795 30.688 ;
     RECT  29.171 54.996 29.845 57.504 ;
     RECT  29.171 59.008 29.845 62.176 ;
     RECT  29.845 54.996 29.931 62.176 ;
     RECT  29.739 33.396 30.181 36.128 ;
     RECT  29.931 60.288 30.202 62.176 ;
     RECT  29.699 14.528 30.251 14.624 ;
     RECT  30.181 32.512 30.275 36.128 ;
     RECT  29.699 37.888 30.275 47.456 ;
     RECT  28.547 48.96 30.275 53.408 ;
     RECT  30.251 14.592 30.315 14.624 ;
     RECT  29.685 0.128 30.371 7.26 ;
     RECT  30.275 44.196 30.443 47.456 ;
     RECT  29.795 17.196 30.645 30.688 ;
     RECT  30.275 32.512 30.645 36.064 ;
     RECT  30.371 0.128 30.763 3.488 ;
     RECT  30.202 60.396 30.778 62.176 ;
     RECT  30.275 37.888 31.285 42.144 ;
     RECT  31.285 37.76 31.349 42.144 ;
     RECT  30.645 17.196 31.379 36.064 ;
     RECT  31.349 37.568 31.379 42.144 ;
     RECT  30.443 44.196 31.379 46.752 ;
     RECT  31.333 73.536 31.403 73.568 ;
     RECT  31.379 22.596 31.723 35.36 ;
     RECT  29.931 54.996 31.765 57.504 ;
     RECT  29.355 64.32 31.842 67.68 ;
     RECT  31.765 54.996 31.851 57.632 ;
     RECT  28.213 9.536 31.909 12.66 ;
     RECT  31.842 63.68 31.915 67.68 ;
     RECT  30.371 4.928 31.925 7.26 ;
     RECT  31.379 17.196 31.955 20.192 ;
     RECT  30.275 48.96 31.955 52.448 ;
     RECT  31.379 44.196 31.957 45.06 ;
     RECT  31.909 9.408 31.979 12.66 ;
     RECT  31.379 37.568 31.979 39.968 ;
     RECT  31.955 49.596 32.043 52.448 ;
     RECT  32.043 49.596 32.062 50.72 ;
     RECT  31.957 44.032 32.171 45.06 ;
     RECT  32.043 52.416 32.437 52.448 ;
     RECT  31.723 33.396 32.506 35.36 ;
     RECT  31.925 4.416 32.531 7.26 ;
     RECT  31.979 10.176 32.531 12.66 ;
     RECT  32.506 33.396 32.531 34.976 ;
     RECT  32.062 49.596 32.531 50.656 ;
     RECT  31.915 63.872 32.531 67.68 ;
     RECT  30.778 60.396 32.533 61.26 ;
     RECT  32.533 59.136 32.619 61.408 ;
     RECT  31.379 41.6 32.811 42.144 ;
     RECT  32.619 59.136 32.811 61.26 ;
     RECT  31.861 47.168 32.821 47.2 ;
     RECT  31.955 20.16 33.013 20.192 ;
     RECT  32.821 47.04 33.013 47.2 ;
     RECT  32.531 63.872 33.059 67.296 ;
     RECT  30.763 0.128 33.061 2.784 ;
     RECT  32.531 4.416 33.061 4.96 ;
     RECT  32.437 52.416 33.077 53.472 ;
     RECT  33.059 63.872 33.082 66.66 ;
     RECT  31.851 54.996 33.107 57.504 ;
     RECT  32.171 44.196 33.141 45.06 ;
     RECT  33.013 47.04 33.141 47.264 ;
     RECT  33.077 52.416 33.155 53.6 ;
     RECT  31.979 37.568 33.195 39.904 ;
     RECT  33.061 42.688 33.195 42.848 ;
     RECT  33.109 73.536 33.195 73.568 ;
     RECT  31.723 22.596 33.653 31.904 ;
     RECT  33.013 20.16 33.683 20.32 ;
     RECT  33.195 37.568 33.683 39.84 ;
     RECT  33.141 46.72 33.683 47.264 ;
     RECT  33.107 54.996 33.683 56.544 ;
     RECT  33.061 0.128 33.731 4.96 ;
     RECT  33.683 47.04 33.875 47.264 ;
     RECT  33.683 20.288 33.963 20.32 ;
     RECT  33.683 37.568 34.259 39.776 ;
     RECT  33.653 21.696 34.347 31.904 ;
     RECT  34.259 38.796 34.547 39.776 ;
     RECT  32.531 49.596 34.597 50.46 ;
     RECT  33.155 52.416 34.613 53.472 ;
     RECT  33.141 44.196 34.667 45.28 ;
     RECT  34.597 48.576 34.667 50.46 ;
     RECT  34.613 52.16 34.741 53.472 ;
     RECT  33.731 0.128 34.835 4.064 ;
     RECT  34.741 52.16 34.835 53.536 ;
     RECT  33.082 64.384 34.835 66.66 ;
     RECT  34.347 22.596 34.837 31.904 ;
     RECT  32.531 33.396 34.869 34.26 ;
     RECT  34.837 22.596 34.934 32.032 ;
     RECT  34.934 22.596 35.002 31.968 ;
     RECT  34.835 53.504 35.051 53.536 ;
     RECT  35.002 22.596 35.363 31.904 ;
     RECT  34.869 33.396 35.363 35.36 ;
     RECT  32.811 60.396 35.829 61.26 ;
     RECT  35.797 51.904 35.883 51.936 ;
     RECT  35.363 27.996 35.891 30.752 ;
     RECT  35.125 57.472 35.902 57.504 ;
     RECT  32.531 10.56 35.939 12.66 ;
     RECT  35.829 59.264 35.939 61.26 ;
     RECT  36.373 35.84 36.459 35.872 ;
     RECT  36.373 53.568 36.459 53.6 ;
     RECT  35.363 22.596 36.515 26.016 ;
     RECT  35.891 27.996 36.515 29.792 ;
     RECT  36.515 25.792 37.091 26.016 ;
     RECT  33.875 47.04 37.091 47.072 ;
     RECT  32.531 6.396 38.16 7.26 ;
     RECT  35.939 11.796 38.16 12.66 ;
     RECT  31.955 17.196 38.16 18.06 ;
     RECT  36.515 22.596 38.16 23.46 ;
     RECT  36.515 27.996 38.16 28.86 ;
     RECT  35.363 33.396 38.16 34.26 ;
     RECT  34.547 38.796 38.16 39.66 ;
     RECT  34.667 44.196 38.16 45.06 ;
     RECT  34.667 49.596 38.16 50.46 ;
     RECT  33.683 54.996 38.16 55.86 ;
     RECT  35.939 60.396 38.16 61.26 ;
     RECT  34.835 65.796 38.16 66.66 ;
     RECT  28.267 71.196 38.16 72.06 ;
     RECT  27.563 76.596 38.16 76.884 ;
     RECT  34.835 0.128 38.339 2.784 ;
     RECT  38.339 1.572 38.579 2.784 ;
     RECT  38.339 0.128 38.771 0.16 ;
     RECT  38.579 1.572 38.944 1.86 ;
     RECT  38.16 6.972 38.944 7.26 ;
     RECT  38.16 12.372 38.944 12.66 ;
     RECT  38.16 17.772 38.944 18.06 ;
     RECT  38.16 23.172 38.944 23.46 ;
     RECT  38.16 28.572 38.944 28.86 ;
     RECT  38.16 33.972 38.944 34.26 ;
     RECT  38.16 39.372 38.944 39.66 ;
     RECT  38.16 44.772 38.944 45.06 ;
     RECT  38.16 50.172 38.944 50.46 ;
     RECT  38.16 55.572 38.944 55.86 ;
     RECT  38.16 60.972 38.944 61.26 ;
     RECT  38.16 66.372 38.944 66.66 ;
     RECT  38.16 71.772 38.944 72.06 ;
    LAYER M7 ;
     RECT  18.048 0.053 18.08 0.117 ;
     RECT  19.776 0.053 19.808 0.117 ;
     RECT  26.112 0.053 26.144 0.117 ;
     RECT  16 0.117 20.704 0.181 ;
     RECT  22.016 0.053 24.224 0.181 ;
     RECT  9.216 0.117 9.248 0.245 ;
     RECT  11.52 0.053 11.552 0.245 ;
     RECT  14.144 0.117 14.304 0.245 ;
     RECT  16 0.181 24.224 0.245 ;
     RECT  26.112 0.117 27.04 0.245 ;
     RECT  26.112 0.245 27.616 0.299 ;
     RECT  13.952 0.245 24.8 0.309 ;
     RECT  13.952 0.309 25.056 0.373 ;
     RECT  30.912 0.245 30.944 0.427 ;
     RECT  9.216 0.245 11.552 0.501 ;
     RECT  12.928 0.373 25.056 0.501 ;
     RECT  27.008 0.299 27.616 0.531 ;
     RECT  37.952 0.373 37.984 0.531 ;
     RECT  37.952 0.531 38.944 0.555 ;
     RECT  27.008 0.531 28.144 1.451 ;
     RECT  9.216 0.501 25.056 2.229 ;
     RECT  9.088 2.229 25.056 2.613 ;
     RECT  6.256 0.531 6.544 3.125 ;
     RECT  6.256 3.125 7.712 3.381 ;
     RECT  9.088 2.613 25.248 3.381 ;
     RECT  30.72 2.741 30.752 3.499 ;
     RECT  6.256 3.381 25.248 3.765 ;
     RECT  6.256 3.765 25.312 4.917 ;
     RECT  27.264 1.451 28.144 4.917 ;
     RECT  6.256 4.917 28.144 9.525 ;
     RECT  6.256 9.525 28.256 9.973 ;
     RECT  29.696 3.893 29.728 10.485 ;
     RECT  31.936 4.405 31.968 10.539 ;
     RECT  33.256 0.531 33.544 10.741 ;
     RECT  6.016 9.973 28.256 13.813 ;
     RECT  29.696 10.485 30.24 14.581 ;
     RECT  29.696 14.581 30.304 16.043 ;
     RECT  30.272 16.043 30.304 18.923 ;
     RECT  33.256 10.741 33.952 20.331 ;
     RECT  5.76 13.813 28.256 21.301 ;
     RECT  5.504 21.301 28.256 21.557 ;
     RECT  4.992 21.557 28.256 21.621 ;
     RECT  33.256 20.331 33.696 21.685 ;
     RECT  4.992 21.621 30.24 22.965 ;
     RECT  4.16 22.965 30.24 23.605 ;
     RECT  4.16 23.605 31.328 23.723 ;
     RECT  33.256 21.685 34.336 23.733 ;
     RECT  4.16 23.723 28.512 23.861 ;
     RECT  29.952 23.723 31.328 24.053 ;
     RECT  33.256 23.733 34.784 24.053 ;
     RECT  3.648 23.861 28.512 25.013 ;
     RECT  29.952 24.053 34.784 25.013 ;
     RECT  3.648 25.013 34.784 28.459 ;
     RECT  31.296 28.459 34.784 29.099 ;
     RECT  3.648 28.459 29.984 31.861 ;
     RECT  31.296 29.099 33.544 31.861 ;
     RECT  34.944 30.709 35.872 31.978 ;
     RECT  3.648 31.861 33.544 32.437 ;
     RECT  3.136 32.437 33.544 33.323 ;
     RECT  34.88 31.978 35.872 35.371 ;
     RECT  35.84 35.371 35.872 35.829 ;
     RECT  3.648 33.323 33.544 41.067 ;
     RECT  3.904 41.067 33.544 44.597 ;
     RECT  35.84 35.829 36.448 44.597 ;
     RECT  3.904 44.597 36.448 50.603 ;
     RECT  4.352 50.603 36.448 51.947 ;
     RECT  4.352 51.947 34.656 52.203 ;
     RECT  4.352 52.203 33.544 52.523 ;
     RECT  4.544 52.523 33.544 53.035 ;
     RECT  5.504 53.035 33.544 53.099 ;
     RECT  36.416 51.947 36.448 53.611 ;
     RECT  35.008 53.493 35.04 55.349 ;
     RECT  35.008 55.349 35.168 55.403 ;
     RECT  35.136 55.403 35.168 57.461 ;
     RECT  35.136 57.461 35.872 57.515 ;
     RECT  5.632 53.099 33.544 57.643 ;
     RECT  5.632 57.643 31.392 58.219 ;
     RECT  6.256 58.219 31.392 59.125 ;
     RECT  32.768 57.643 33.544 59.125 ;
     RECT  35.84 57.515 35.872 59.307 ;
     RECT  6.256 59.125 33.544 60.331 ;
     RECT  30.72 60.331 33.544 62.187 ;
     RECT  6.256 60.331 29.408 64.811 ;
     RECT  31.36 62.187 33.544 65.067 ;
     RECT  32.832 65.067 33.544 67.307 ;
     RECT  6.256 64.811 29.344 69.099 ;
     RECT  6.256 69.099 28.64 73.131 ;
     RECT  6.256 73.131 10.08 73.579 ;
     RECT  31.36 65.067 31.392 73.579 ;
     RECT  33.152 67.307 33.544 73.579 ;
     RECT  6.256 73.579 7.264 74.091 ;
     RECT  9.088 73.579 9.12 74.155 ;
     RECT  11.656 73.131 28.64 74.155 ;
     RECT  0.856 0.531 1.144 76.959 ;
     RECT  6.256 74.091 6.544 76.959 ;
     RECT  11.656 74.155 28.144 76.959 ;
     RECT  33.256 73.579 33.544 76.959 ;
     RECT  38.656 0.555 38.944 76.959 ;
     RECT  11.656 76.959 27.552 76.981 ;
     RECT  11.52 76.981 27.552 77.035 ;
     RECT  13.824 77.035 25.12 77.099 ;
     RECT  27.008 77.035 27.552 77.099 ;
     RECT  13.824 77.099 21.792 77.163 ;
     RECT  23.424 77.099 25.12 77.163 ;
     RECT  27.008 77.099 27.424 77.163 ;
     RECT  11.52 77.035 12.512 77.227 ;
     RECT  27.008 77.163 27.04 77.227 ;
     RECT  13.888 77.163 21.792 77.291 ;
     RECT  23.616 77.163 25.12 77.291 ;
     RECT  13.888 77.291 13.92 77.355 ;
     RECT  15.296 77.291 21.792 77.355 ;
     RECT  15.36 77.355 20.832 77.419 ;
     RECT  23.936 77.291 25.056 77.419 ;
     RECT  11.52 77.227 12.384 77.483 ;
     RECT  15.36 77.419 17.568 77.483 ;
     RECT  24.576 77.419 24.608 77.483 ;
     RECT  12.352 77.483 12.384 77.611 ;
     RECT  15.36 77.483 15.584 77.611 ;
  END
END hfd_stn_r30
END LIBRARY
